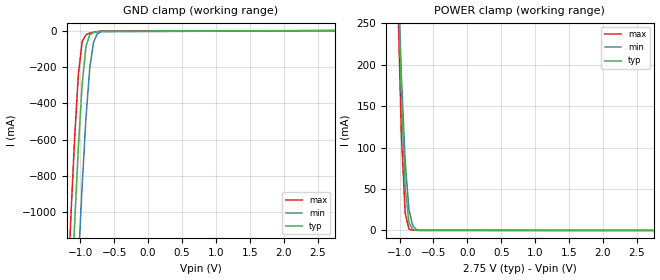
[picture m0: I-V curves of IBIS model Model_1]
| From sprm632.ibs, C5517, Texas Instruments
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| Model based on original model for IC33THYPD
|   Sub model IC33THY_PD_ON_IND_2P75
[model]   Model_1
|[Description]  [2.75V-INPUT-PD-X, IND]
|   PD,IND,
|[Input Load]   PD
|[Output Drive]
|Voltage   2.75V
|Mode   INPUT
Model_type   Input
Polarity   Non-Inverting
Vinl =  0.7
Vinh =  1.7
C_comp   0.88152539p  0.83844711p  0.88864286p
[Model Spec]
Vinl   0.7   0.7   0.7
Vinh   1.7   1.7   1.7
[Temperature Range]   25   105   -40
[Voltage Range]   2.75   2.475   3.025
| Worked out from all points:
|   GND clamp passes 1 mA (typ) near -0.59 V on its own axis
|   POWER clamp passes 1 mA (typ) near -0.79 V on its own axis
[POWER_clamp]
-2.75V    7.27A      6.262A     8.251A
-1.028V   318.4mA    321mA      289.5mA
-972.2mV  160.5mA    185.6mA    114.9mA
-916.7mV  52.38mA    82.72mA    20.8mA
-861.1mV  9.552mA    25.5mA     1.814mA
-805.6mV  1.329mA    5.828mA    224.5uA
-750mV    215.5uA    1.175mA    112.3uA
-694.4mV  80.76uA    256.9uA    104.8uA
2.75V     -84.09pA   -14.35uA   24.32uA
[GND_clamp]
-2.75V    -17A       -17.63A    -16.56A
-1.194V   -2A        -2.688A    -1.495A
-1.139V   -1.516A    -2.198A    -1.02A
-1.083V   -1.056A    -1.723A    -584.9mA
-1.028V   -635.2mA   -1.268A    -236.1mA
-972.2mV  -291mA     -845.8mA   -59.93mA
-916.7mV  -86.57mA   -479.1mA   -22.05mA
-861.1mV  -22.91mA   -206.5mA   -14.2mA
-805.6mV  -10.26mA   -63.94mA   -9.582mA
-750mV    -6.123mA   -17.61mA   -5.862mA
-694.4mV  -3.584mA   -6.2mA     -3.052mA
2.75V     61.47uA    35.47uA    104.1uA
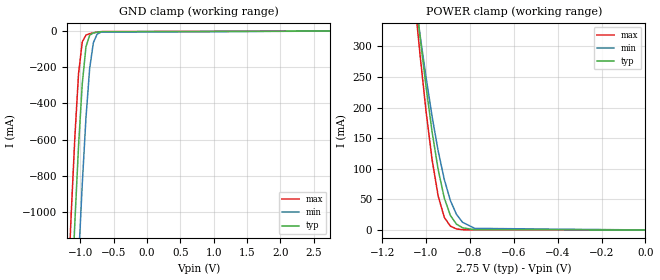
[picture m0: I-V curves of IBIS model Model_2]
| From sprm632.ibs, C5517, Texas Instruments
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| Model based on original model for IC33THYPD
|   Sub model IC33THY_PD_OFF_IND_2P75
[model]   Model_2
|[Description]  [2.75V-INPUT-PD_OFF-X, IND]
|   PD_OFF,IND,
|[Input Load]   PD_OFF
|[Output Drive]
|Voltage   2.75V
|Mode   INPUT
Model_type   Input
Polarity   Non-Inverting
Vinl =  0.7
Vinh =  1.7
C_comp   0.88152539p  0.83844711p  0.88864286p
[Model Spec]
Vinl   0.7   0.7   0.7
Vinh   1.7   1.7   1.7
[Temperature Range]   25   105   -40
[Voltage Range]   2.75   2.475   3.025
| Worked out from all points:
|   GND clamp passes 1 mA (typ) near -0.60 V on its own axis
|   POWER clamp passes 1 mA (typ) near -0.80 V on its own axis
[POWER_clamp]
-2.75V    7.27A      6.262A     8.251A
-1.056V   408.2mA    396.6mA    392.6mA
-1.028V   318.4mA    321mA      289.4mA
-1V       234.9mA    250.1mA    195mA
-972.2mV  160.4mA    185.5mA    114.9mA
-944.4mV  98.35mA    129mA      55.3mA
-916.7mV  52.33mA    82.69mA    20.7mA
-888.9mV  23.73mA    48.12mA    6.231mA
-861.1mV  9.493mA    25.47mA    1.71mA
-833.3mV  3.542mA    12.5mA     458.8uA
-777.8mV  444.2uA    2.594mA    31.13uA
0V        254pA      2.979nA    144.1pA
[GND_clamp]
-2.75V    -17A       -17.63A    -16.56A
-1.194V   -2A        -2.688A    -1.495A
-1.139V   -1.516A    -2.198A    -1.02A
-1.083V   -1.056A    -1.723A    -584.9mA
-1.028V   -635.2mA   -1.268A    -236.1mA
-972.2mV  -291mA     -845.8mA   -59.88mA
-916.7mV  -86.55mA   -479.1mA   -21.97mA
-861.1mV  -22.87mA   -206.5mA   -14.11mA
-805.6mV  -10.22mA   -63.93mA   -9.501mA
-750mV    -6.074mA   -17.59mA   -5.787mA
-694.4mV  -3.536mA   -6.179mA   -2.982mA
2.75V     254pA      4.299nA    119.2pA
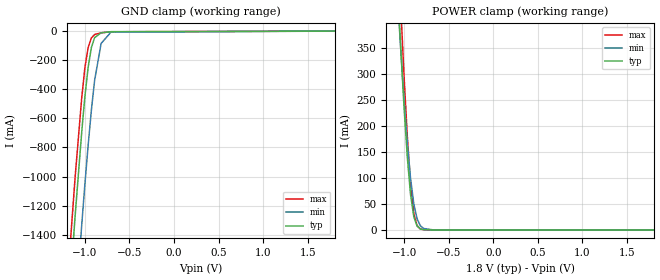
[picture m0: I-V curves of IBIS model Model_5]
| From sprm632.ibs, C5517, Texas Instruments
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| Model based on original model for IC33THYPD
|   Sub model IC33THY_PD_ON_COM_1P8
[model]   Model_5
|[Description]  [1.8V-INPUT-PD-X, COM]
|   PD,COM,
|[Input Load]   PD
|[Output Drive]
|Voltage   1.8V
|Mode   INPUT
Model_type   Input
Polarity   Non-Inverting
Vinl =  0.63
Vinh =  1.17
C_comp   0.92608326p  0.90524032p  0.94286856p
[Model Spec]
Vinl   0.63   0.567   0.693
Vinh   1.17   1.053   1.287
[Temperature Range]   25   105   -10
[Voltage Range]   1.8   1.62   1.98
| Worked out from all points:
|   GND clamp passes 1 mA (typ) near -0.60 V on its own axis
|   POWER clamp passes 1 mA (typ) near -0.79 V on its own axis
[POWER_clamp]
-1.8V     3.329A     2.879A     3.744A
-1.073V   466mA      445.2mA    563mA
-1.036V   345.6mA    343.9mA    424.5mA
-1V       234.9mA    250.1mA    294.9mA
-963.6mV  139.8mA    167.1mA    180mA
-927.3mV  67.8mA     99.04mA    88.62mA
-890.9mV  25.26mA    50.21mA    31.77mA
-854.5mV  7.627mA    21.73mA    8.494mA
-818.2mV  2.034mA    8.241mA    1.915mA
-781.8mV  537.6uA    2.928mA    435.2uA
-672.7mV  28.87uA    127.4uA    35.69uA
1.8V      -54.7pA    -5.012uA   8.703uA
[GND_clamp]
-1.8V     -7.705A    -8.371A    -7.441A
-1.182V   -1.888A    -2.575A    -1.614A
-1.145V   -1.573A    -2.255A    -1.301A
-1.109V   -1.266A    -1.941A    -999.8mA
-1.036V   -696.6mA   -1.336A    -461.3mA
-1V       -449.7mA   -1.052A    -251.6mA
-963.6mV  -248.8mA   -784.8mA   -112.8mA
-927.3mV  -112.6mA   -543.2mA   -46.64mA
-890.9mV  -44.82mA   -337.9mA   -23.68mA
-818.2mV  -11.79mA   -85.27mA   -12mA
-709.1mV  -4.152mA   -7.899mA   -4.826mA
1.8V      20.41uA    11.64uA    31.82uA
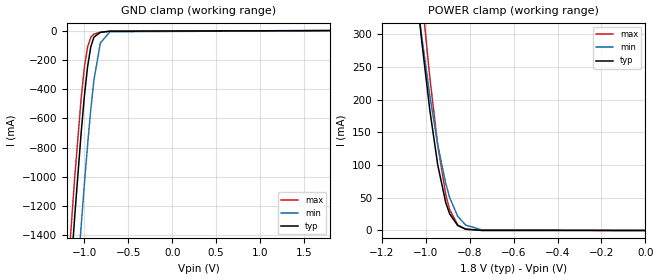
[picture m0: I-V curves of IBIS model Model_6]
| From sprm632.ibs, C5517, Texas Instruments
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| Model based on original model for IC33THYPD
|   Sub model IC33THY_PD_OFF_COM_1P8
[model]   Model_6
|[Description]  [1.8V-INPUT-PD_OFF-X, COM]
|   PD_OFF,COM,
|[Input Load]   PD_OFF
|[Output Drive]
|Voltage   1.8V
|Mode   INPUT
Model_type   Input
Polarity   Non-Inverting
Vinl =  0.63
Vinh =  1.17
C_comp   0.92608326p  0.90524032p  0.94286856p
[Model Spec]
Vinl   0.63   0.567   0.693
Vinh   1.17   1.053   1.287
[Temperature Range]   25   105   -10
[Voltage Range]   1.8   1.62   1.98
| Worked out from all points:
|   GND clamp passes 1 mA (typ) near -0.60 V on its own axis
|   POWER clamp passes 1 mA (typ) near -0.80 V on its own axis
[POWER_clamp]
-1.8V     3.329A     2.879A     3.744A
-1.055V   404.8mA    393.8mA    492.9mA
-1.036V   345.6mA    343.9mA    424.5mA
-1.018V   288.7mA    295.9mA    358.3mA
-981.8mV  184.9mA    207mA      235.1mA
-945.5mV  100.3mA    130.9mA    130.6mA
-909.1mV  42.72mA    71.97mA    55.33mA
-890.9mV  25.25mA    50.2mA     31.74mA
-854.5mV  7.607mA    21.72mA    8.463mA
-818.2mV  2.014mA    8.229mA    1.884mA
-745.5mV  132uA      1.007mA    85.84uA
0V        132pA      1.821nA    116.7pA
[GND_clamp]
-1.8V     -7.705A    -8.371A    -7.441A
-1.182V   -1.888A    -2.575A    -1.614A
-1.145V   -1.573A    -2.255A    -1.301A
-1.109V   -1.266A    -1.941A    -999.8mA
-1.036V   -696.6mA   -1.336A    -461.3mA
-1V       -449.7mA   -1.052A    -251.6mA
-963.6mV  -248.8mA   -784.8mA   -112.8mA
-927.3mV  -112.6mA   -543.2mA   -46.61mA
-890.9mV  -44.81mA   -337.9mA   -23.65mA
-818.2mV  -11.76mA   -85.26mA   -11.96mA
-709.1mV  -4.12mA    -7.886mA   -4.782mA
1.8V      132pA      2.08nA     95.31pA
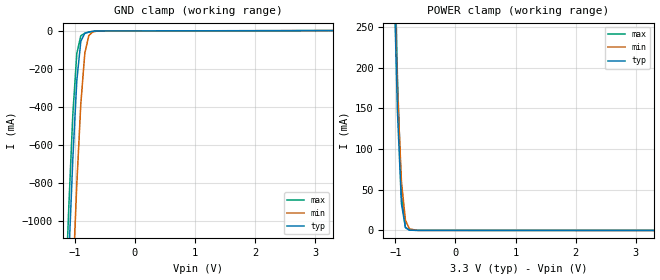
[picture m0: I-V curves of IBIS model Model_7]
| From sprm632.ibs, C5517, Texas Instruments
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| Model based on original model for IC33THYPD
|   Sub model IC33THY_PD_ON_COM_3P3
[model]   Model_7
|[Description]  [3.3V-INPUT-PD-X, COM]
|   PD,COM,
|[Input Load]   PD
|[Output Drive]
|Voltage   3.3V
|Mode   INPUT
Model_type   Input
Polarity   Non-Inverting
Vinl =  0.8
Vinh =  2
C_comp   0.86952386p  0.83844711p  0.87673039p
[Model Spec]
Vinl   0.8   0.8   0.8
Vinh   2   2   2
[Temperature Range]   25   105   -10
[Voltage Range]   3.3   2.97   3.63
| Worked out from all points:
|   GND clamp passes 1 mA (typ) near -0.59 V on its own axis
|   POWER clamp passes 1 mA (typ) near -0.78 V on its own axis
[POWER_clamp]
-3.3V     9.572A     8.242A     10.62A
-1.033V   336mA      335.8mA    413.4mA
-966.7mV  147mA      173.6mA    188.9mA
-900mV    33.1mA     60.41mA    42.36mA
-833.3mV  3.635mA    12.55mA    3.712mA
-766.7mV  387uA      1.932mA    351.1uA
-633.3mV  95.7uA     90.13uA    139.8uA
3.3V      -101.5pA   -26.63uA   30.53uA
[GND_clamp]
-3.3V     -22.43A    -23.04A    -22.19A
-1.167V   -1.756A    -2.441A    -1.482A
-1.1V     -1.191A    -1.863A    -927mA
-1.033V   -674.7mA   -1.312A    -441.8mA
-966.7mV  -263.3mA   -806.2mA   -121.4mA
-900mV    -56.2mA    -384.9mA   -27.18mA
-833.3mV  -14.39mA   -119.2mA   -13.45mA
-766.7mV  -7.115mA   -25.7mA    -8.195mA
-700mV    -3.804mA   -6.765mA   -4.408mA
-633.3mV  -1.704mA   -2.591mA   -1.876mA
3.3V      93.69uA    54.29uA    138.8uA
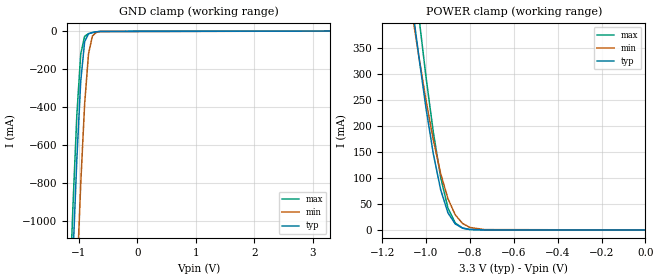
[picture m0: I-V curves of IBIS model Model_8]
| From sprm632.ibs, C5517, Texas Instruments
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| Model based on original model for IC33THYPD
|   Sub model IC33THY_PD_OFF_COM_3P3
[model]   Model_8
|[Description]  [3.3V-INPUT-PD_OFF-X, COM]
|   PD_OFF,COM,
|[Input Load]   PD_OFF
|[Output Drive]
|Voltage   3.3V
|Mode   INPUT
Model_type   Input
Polarity   Non-Inverting
Vinl =  0.8
Vinh =  2
C_comp   0.86952386p  0.83844711p  0.87673039p
[Model Spec]
Vinl   0.8   0.8   0.8
Vinh   2   2   2
[Temperature Range]   25   105   -10
[Voltage Range]   3.3   2.97   3.63
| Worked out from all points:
|   GND clamp passes 1 mA (typ) near -0.59 V on its own axis
|   POWER clamp passes 1 mA (typ) near -0.80 V on its own axis
[POWER_clamp]
-3.3V     9.572A     8.242A     10.62A
-1.067V   445.4mA    427.9mA    539.5mA
-1.033V   335.9mA    335.8mA    413.3mA
-1V       234.9mA    250.1mA    294.9mA
-966.7mV  146.9mA    173.5mA    188.8mA
-933.3mV  77.82mA    109.1mA    101.7mA
-900mV    33.01mA    60.36mA    42.24mA
-866.7mV  11.56mA    29.21mA    13.5mA
-833.3mV  3.542mA    12.5mA     3.575mA
-800mV    1.012mA    4.898mA    862.3uA
-733.3mV  83.43uA    702.6uA    51.03uA
0V        368.6pA    3.926nA    435.5pA
[GND_clamp]
-3.3V     -22.43A    -23.04A    -22.19A
-1.167V   -1.756A    -2.441A    -1.482A
-1.1V     -1.191A    -1.863A    -927mA
-1.033V   -674.7mA   -1.312A    -441.8mA
-966.7mV  -263.3mA   -806.2mA   -121.3mA
-900mV    -56.17mA   -384.9mA   -27.12mA
-833.3mV  -14.34mA   -119.2mA   -13.37mA
-766.7mV  -7.058mA   -25.69mA   -8.118mA
-700mV    -3.749mA   -6.74mA    -4.336mA
-633.3mV  -1.654mA   -2.561mA   -1.811mA
3.3V      368.6pA    8.935nA    310.6pA
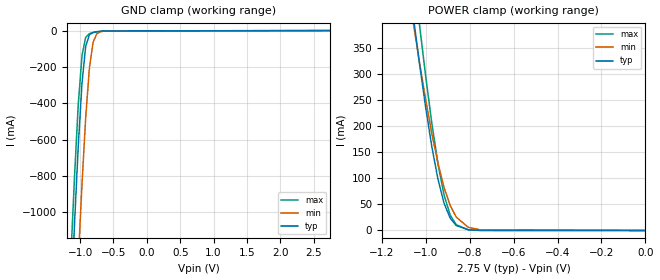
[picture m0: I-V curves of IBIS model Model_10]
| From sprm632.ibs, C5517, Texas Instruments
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| Model based on original model for IC33THYPD
|   Sub model IC33THY_PD_OFF_COM_2P75
[model]   Model_10
|[Description]  [2.75V-INPUT-PD_OFF-X, COM]
|   PD_OFF,COM,
|[Input Load]   PD_OFF
|[Output Drive]
|Voltage   2.75V
|Mode   INPUT
Model_type   Input
Polarity   Non-Inverting
Vinl =  0.7
Vinh =  1.7
C_comp   0.88152539p  0.83844711p  0.88864286p
[Model Spec]
Vinl   0.7   0.7   0.7
Vinh   1.7   1.7   1.7
[Temperature Range]   25   105   -10
[Voltage Range]   2.75   2.475   3.025
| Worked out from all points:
|   GND clamp passes 1 mA (typ) near -0.60 V on its own axis
|   POWER clamp passes 1 mA (typ) near -0.80 V on its own axis
[POWER_clamp]
-2.75V    7.27A      6.262A     8.085A
-1.056V   408.2mA    396.6mA    496.7mA
-1.028V   318.4mA    321mA      393mA
-1V       234.9mA    250.1mA    294.9mA
-972.2mV  160.4mA    185.5mA    205.3mA
-944.4mV  98.35mA    129mA      128.1mA
-916.7mV  52.33mA    82.69mA    68.18mA
-888.9mV  23.73mA    48.12mA    29.7mA
-861.1mV  9.493mA    25.47mA    10.83mA
-805.6mV  1.267mA    5.793mA    1.115mA
-750mV    154uA      1.139mA    102uA
0V        254pA      2.979nA    256.4pA
[GND_clamp]
-2.75V    -17A       -17.63A    -16.75A
-1.139V   -1.516A    -2.198A    -1.246A
-1.083V   -1.056A    -1.723A    -796.9mA
-1.028V   -635.2mA   -1.268A    -406.8mA
-972.2mV  -291mA     -845.8mA   -138.4mA
-916.7mV  -86.55mA   -479.1mA   -37.11mA
-861.1mV  -22.87mA   -206.5mA   -16.79mA
-805.6mV  -10.22mA   -63.93mA   -10.91mA
-750mV    -6.074mA   -17.59mA   -7.059mA
-694.4mV  -3.536mA   -6.179mA   -4.079mA
-638.9mV  -1.787mA   -2.756mA   -1.969mA
2.75V     254pA      4.299nA    195.7pA
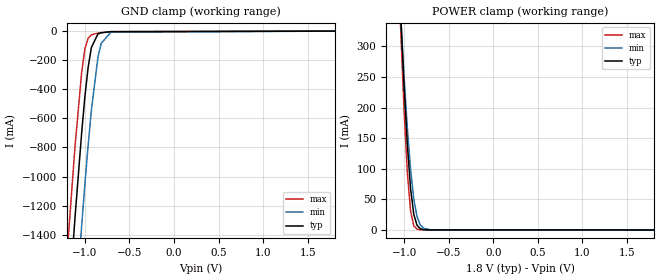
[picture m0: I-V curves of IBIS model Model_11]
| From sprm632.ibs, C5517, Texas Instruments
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| Model based on original model for IC33THYPD
|   Sub model IC33THY_PD_ON_IND_1P8
[model]   Model_11
|[Description]  [1.8V-INPUT-PD-X, IND]
|   PD,IND,
|[Input Load]   PD
|[Output Drive]
|Voltage   1.8V
|Mode   INPUT
Model_type   Input
Polarity   Non-Inverting
Vinl =  0.63
Vinh =  1.17
C_comp   0.92608326p  0.90524032p  0.94286856p
[Model Spec]
Vinl   0.63   0.567   0.693
Vinh   1.17   1.053   1.287
[Temperature Range]   25   105   -40
[Voltage Range]   1.8   1.62   1.98
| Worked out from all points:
|   GND clamp passes 1 mA (typ) near -0.60 V on its own axis
|   POWER clamp passes 1 mA (typ) near -0.79 V on its own axis
[POWER_clamp]
-1.8V     3.329A     2.879A     3.753A
-1.073V   466mA      445.2mA    459.6mA
-1.036V   345.6mA    343.9mA    320.6mA
-1V       234.9mA    250.1mA    195.1mA
-963.6mV  139.8mA    167.1mA    93.99mA
-927.3mV  67.8mA     99.04mA    31mA
-890.9mV  25.26mA    50.21mA    6.862mA
-854.5mV  7.627mA    21.73mA    1.306mA
-818.2mV  2.034mA    8.241mA    253.8uA
-781.8mV  537.6uA    2.928mA    73.12uA
-709.1mV  53.45uA    351.4uA    36.37uA
1.8V      -54.7pA    -5.012uA   9.776uA
[GND_clamp]
-1.8V     -7.705A    -8.371A    -7.226A
-1.182V   -1.888A    -2.575A    -1.385A
-1.145V   -1.573A    -2.255A    -1.075A
-1.109V   -1.266A    -1.941A    -779.8mA
-1.036V   -696.6mA   -1.336A    -281mA
-1V       -449.7mA   -1.052A    -122.4mA
-963.6mV  -248.8mA   -784.8mA   -48.76mA
-927.3mV  -112.6mA   -543.2mA   -24.99mA
-854.5mV  -20.28mA   -183mA     -13.56mA
-818.2mV  -11.79mA   -85.27mA   -10.51mA
-709.1mV  -4.152mA   -7.899mA   -3.673mA
1.8V      20.41uA    11.64uA    35.18uA
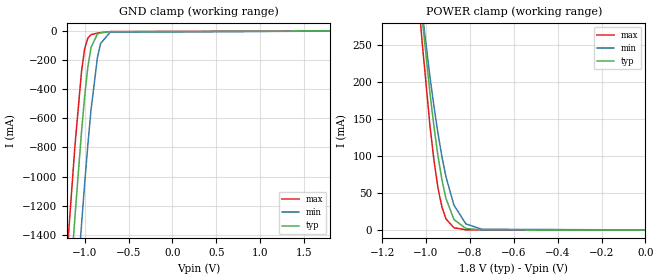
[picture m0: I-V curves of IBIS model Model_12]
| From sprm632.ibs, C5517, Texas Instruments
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| Model based on original model for IC33THYPD
|   Sub model IC33THY_PD_OFF_IND_1P8
[model]   Model_12
|[Description]  [1.8V-INPUT-PD_OFF-X, IND]
|   PD_OFF,IND,
|[Input Load]   PD_OFF
|[Output Drive]
|Voltage   1.8V
|Mode   INPUT
Model_type   Input
Polarity   Non-Inverting
Vinl =  0.63
Vinh =  1.17
C_comp   0.92608326p  0.90524032p  0.94286856p
[Model Spec]
Vinl   0.63   0.567   0.693
Vinh   1.17   1.053   1.287
[Temperature Range]   25   105   -40
[Voltage Range]   1.8   1.62   1.98
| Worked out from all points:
|   GND clamp passes 1 mA (typ) near -0.60 V on its own axis
|   POWER clamp passes 1 mA (typ) near -0.80 V on its own axis
[POWER_clamp]
-1.8V     3.329A     2.879A     3.753A
-1.036V   345.6mA    343.9mA    320.5mA
-1.018V   288.7mA    295.9mA    255.6mA
-981.8mV  184.9mA    207mA      140.6mA
-963.6mV  139.7mA    167.1mA    93.97mA
-945.5mV  100.3mA    130.9mA    57.04mA
-927.3mV  67.78mA    99.03mA    30.97mA
-909.1mV  42.72mA    71.97mA    15.06mA
-872.7mV  14.17mA    33.67mA    2.991mA
-818.2mV  2.014mA    8.229mA    218.6uA
-745.5mV  132uA      1.007mA    6.591uA
0V        132pA      1.821nA    91.6pA
[GND_clamp]
-1.8V     -7.705A    -8.371A    -7.226A
-1.182V   -1.888A    -2.575A    -1.385A
-1.145V   -1.573A    -2.255A    -1.075A
-1.109V   -1.266A    -1.941A    -779.8mA
-1.036V   -696.6mA   -1.336A    -281mA
-1V       -449.7mA   -1.052A    -122.4mA
-963.6mV  -248.8mA   -784.8mA   -48.73mA
-927.3mV  -112.6mA   -543.2mA   -24.95mA
-854.5mV  -20.26mA   -183mA     -13.5mA
-818.2mV  -11.76mA   -85.26mA   -10.46mA
-709.1mV  -4.12mA    -7.886mA   -3.624mA
1.8V      132pA      2.08nA     76.27pA
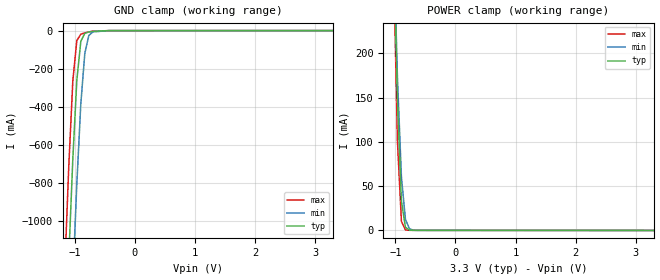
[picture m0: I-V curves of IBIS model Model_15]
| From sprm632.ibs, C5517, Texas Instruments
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| Model based on original model for IC33THYPD
|   Sub model IC33THY_PD_ON_IND_3P3
[model]   Model_15
|[Description]  [3.3V-INPUT-PD-X, IND]
|   PD,IND,
|[Input Load]   PD
|[Output Drive]
|Voltage   3.3V
|Mode   INPUT
Model_type   Input
Polarity   Non-Inverting
Vinl =  0.8
Vinh =  2
C_comp   0.86952386p  0.83844711p  0.87673039p
[Model Spec]
Vinl   0.8   0.8   0.8
Vinh   2   2   2
[Temperature Range]   25   105   -40
[Voltage Range]   3.3   2.97   3.63
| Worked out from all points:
|   GND clamp passes 1 mA (typ) near -0.59 V on its own axis
|   POWER clamp passes 1 mA (typ) near -0.78 V on its own axis
[POWER_clamp]
-3.3V     9.572A     8.242A     10.87A
-1.033V   336mA      335.8mA    309.6mA
-966.7mV  147mA      173.6mA    101.2mA
-900mV    33.1mA     60.41mA    10.29mA
-833.3mV  3.635mA    12.55mA    616.4uA
-766.7mV  387uA      1.932mA    176.2uA
-700mV    117.1uA    312.6uA    158.6uA
-633.3mV  95.7uA     90.13uA    157.9uA
3.3V      -101.5pA   -26.63uA   34.57uA
[GND_clamp]
-3.3V     -22.43A    -23.04A    -22A
-1.167V   -1.756A    -2.441A    -1.254A
-1.1V     -1.191A    -1.863A    -709.3mA
-1.033V   -674.7mA   -1.312A    -264.7mA
-966.7mV  -263.3mA   -806.2mA   -52.38mA
-900mV    -56.2mA    -384.9mA   -18.8mA
-833.3mV  -14.39mA   -119.2mA   -11.76mA
-766.7mV  -7.115mA   -25.7mA    -6.903mA
-700mV    -3.804mA   -6.765mA   -3.294mA
-433.3mV  -62.88uA   -118.9uA   -56.3uA
3.3V      93.69uA    54.29uA    157.6uA
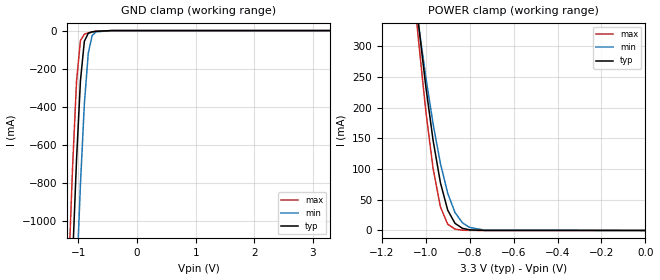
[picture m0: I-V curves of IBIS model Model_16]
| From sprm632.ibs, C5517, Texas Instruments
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| Model based on original model for IC33THYPD
|   Sub model IC33THY_PD_OFF_IND_3P3
[model]   Model_16
|[Description]  [3.3V-INPUT-PD_OFF-X, IND]
|   PD_OFF,IND,
|[Input Load]   PD_OFF
|[Output Drive]
|Voltage   3.3V
|Mode   INPUT
Model_type   Input
Polarity   Non-Inverting
Vinl =  0.8
Vinh =  2
C_comp   0.86952386p  0.83844711p  0.87673039p
[Model Spec]
Vinl   0.8   0.8   0.8
Vinh   2   2   2
[Temperature Range]   25   105   -40
[Voltage Range]   3.3   2.97   3.63
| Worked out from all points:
|   GND clamp passes 1 mA (typ) near -0.59 V on its own axis
|   POWER clamp passes 1 mA (typ) near -0.80 V on its own axis
[POWER_clamp]
-3.3V     9.572A     8.242A     10.87A
-1.067V   445.4mA    427.9mA    435.7mA
-1.033V   335.9mA    335.8mA    309.5mA
-1V       234.9mA    250.1mA    195mA
-966.7mV  146.9mA    173.5mA    101.1mA
-933.3mV  77.82mA    109.1mA    38.46mA
-900mV    33.01mA    60.36mA    10.14mA
-866.7mV  11.56mA    29.21mA    2.249mA
-833.3mV  3.542mA    12.5mA     458.8uA
-800mV    1.012mA    4.898mA    89.45uA
-733.3mV  83.43uA    702.6uA    3.665uA
0V        368.6pA    3.926nA    180.8pA
[GND_clamp]
-3.3V     -22.43A    -23.04A    -22A
-1.167V   -1.756A    -2.441A    -1.254A
-1.1V     -1.191A    -1.863A    -709.3mA
-1.033V   -674.7mA   -1.312A    -264.7mA
-966.7mV  -263.3mA   -806.2mA   -52.32mA
-900mV    -56.17mA   -384.9mA   -18.7mA
-833.3mV  -14.34mA   -119.2mA   -11.67mA
-766.7mV  -7.058mA   -25.69mA   -6.816mA
-700mV    -3.749mA   -6.74mA    -3.214mA
-433.3mV  -28.76uA   -96.03uA   -6.535uA
3.3V      368.6pA    8.935nA    147.2pA
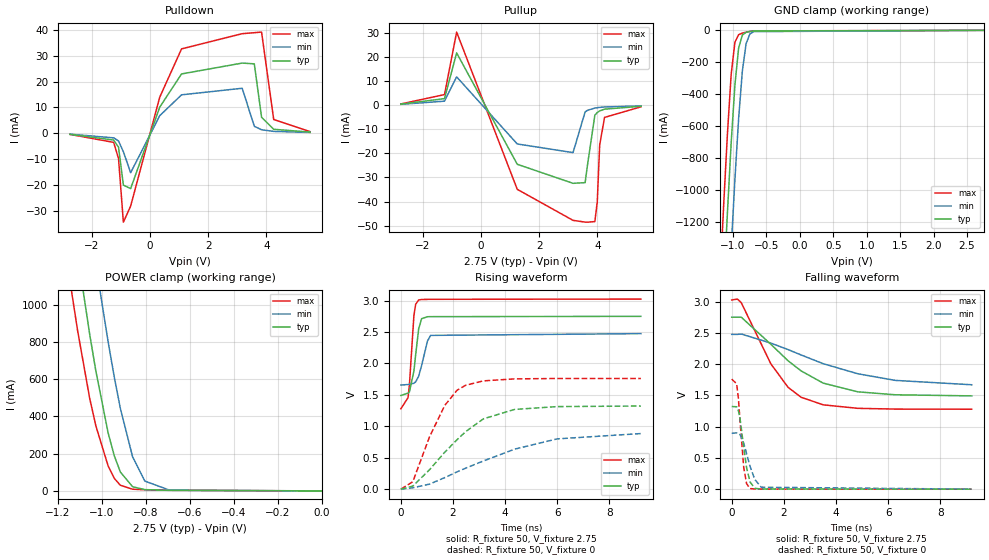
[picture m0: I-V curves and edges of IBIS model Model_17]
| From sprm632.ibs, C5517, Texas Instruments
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| Model based on original model for OC3350CT
|   Sub model OC3350CT_IND_2P75
[model]   Model_17
|[Description]  [2.75V-3-STATE-X-X]
|   , ,
|[Input Load]
|[Output Drive]
|Voltage   2.75V
|Mode   3-STATE
Model_type   3-state
Polarity   Non-Inverting
Enable   Active-Low
Cref =  15.0000pF
Rref =  100.0000M
Vref =  0V
Vmeas =  1.375
C_comp   1.3344371p   1.2993811p   1.3415641p
[Temperature Range]   25   105   -40
[Voltage Range]   2.75   2.475   3.025
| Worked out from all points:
|   slope of the pulldown table from 0 to 0.412 V, typ, clamps not added: 34.2 ohm
|   slope of the pullup table from 0 to 0.412 V, typ, clamps not added: 40.5 ohm
|   GND clamp passes 1 mA (typ) near -0.59 V on its own axis
|   POWER clamp passes 1 mA (typ) near -0.52 V on its own axis
|   rising waveform, R_fixture 50, V_fixture 2.75: 20-80 % time 210ps typ, 288ps min, 162ps max; typ from 1.49 V to 2.75 V
|   rising waveform, R_fixture 50, V_fixture 0: 20-80 % time 1.93ns typ, 3.3ns min, 1.15ns max; typ from 0 V to 1.32 V
|   falling waveform, R_fixture 50, V_fixture 2.75: 20-80 % time 2.23ns typ, 3.33ns min, 1.46ns max; typ from 2.75 V to 1.49 V
|   falling waveform, R_fixture 50, V_fixture 0: 20-80 % time 262ps typ, 387ps min, 195ps max; typ from 1.32 V to 0 V
[POWER_clamp]
-2.75V    16.94A     17.55A     16.52A
-1.167V   1.737A     2.381A     1.292A
-1.111V   1.273A     1.9A       861.3mA
-1.056V   840.8mA    1.438A     496.8mA
-1.028V   643.9mA    1.216A     349.4mA
-972.2mV  311.6mA    800.4mA    133.7mA
-944.4mV  188.9mA    612.4mA    67.69mA
-916.7mV  101.5mA    443mA      30.38mA
-861.1mV  22.6mA     183.2mA    9.262mA
-805.6mV  7.009mA    53.11mA    6.255mA
-694.4mV  3.061mA    4.465mA    3.723mA
0V        269.9pA    3.665nA    128.1pA
[Pulldown]
-2.75V    -442uA     -375.6uA   -474.1uA
-1.25V    -2.654mA   -1.806mA   -3.558mA
-1.083V   -5.416mA   -3.008mA   -9.846mA
-916.7mV  -20.1mA    -7.191mA   -34.47mA
-666.7mV  -21.47mA   -15.31mA   -28.22mA
333.3mV   10.1mA     6.791mA    13.96mA
1.083V    22.95mA    14.86mA    32.66mA
3.167V    27.16mA    17.4mA     38.54mA
3.583V    26.86mA    2.673mA    38.92mA
3.833V    6.162mA    1.323mA    39.16mA
4.25V     1.511mA    698.6uA    5.299mA
5.5V      426.6uA    283.2uA    606.1uA
[Pullup]
-2.75V    418.2uA    329.2uA    487.1uA
-1.25V    2.701mA    1.641mA    4.369mA
-833.3mV  21.65mA    11.72mA    30.28mA
1.25V     -24.52mA   -16.1mA    -34.9mA
3.167V    -32.42mA   -19.68mA   -47.77mA
3.583V    -32.13mA   -2.799mA   -48.5mA
3.667V    -24.56mA   -2.133mA   -48.53mA
3.917V    -4.161mA   -1.221mA   -48.27mA
4V        -3.056mA   -1.065mA   -40.08mA
4.083V    -2.401mA   -943.9uA   -16.54mA
4.25V     -1.668mA   -767.8uA   -5.093mA
5.5V      -494.4uA   -316.6uA   -710uA
[GND_clamp]
-2.75V    -17.09A    -17.75A    -16.63A
-1.194V   -2.084A    -2.795A    -1.56A
-1.139V   -1.598A    -2.303A    -1.082A
-1.083V   -1.133A    -1.824A    -639.4mA
-1.028V   -703.4mA   -1.364A    -275mA
-972.2mV  -342.5mA   -933.9mA   -74.49mA
-916.7mV  -111mA     -552.6mA   -27.1mA
-861.1mV  -29.66mA   -255.8mA   -17.34mA
-805.6mV  -12.76mA   -85.11mA   -11.68mA
-750mV    -7.49mA    -23.64mA   -7.122mA
-694.4mV  -4.355mA   -7.989mA   -3.677mA
2.75V     269.9pA    28.51uA    71.29pA
[Ramp]
dV/dt_f 0.76430358/2.2499866n 0.49810524/3.4588381n  1.0576467/1.4687417n
dV/dt_r 0.79434594/1.9333317n 0.53652254/3.3498741n   1.057181/1.1493145n
R_load = 50
[Rising Waveform]
R_fixture = 50
V_fixture = 2.75
V_fixture_min = 2.475
V_fixture_max = 3.025
0s        1.491V     1.657V     1.28V
274.5ps   1.528V     1.665V     1.455V
329.2ps   1.549V     1.669V     1.666V
500.5ps   1.879V     1.685V     2.763V
568.1ps   2.138V     1.708V     2.943V
683.4ps   2.552V     1.799V     3.011V
796.9ps   2.713V     1.969V     3.018V
1.02ns    2.744V     2.355V     3.02V
1.139ns   2.745V     2.447V     3.021V
9.211ns   2.75V      2.475V     3.025V
[Rising Waveform]
R_fixture = 50
V_fixture = 0
V_fixture_min = 0
V_fixture_max = 0
0s        0V         288.8uV    815.2uV
458.3ps   48.39mV    21.83mV    118mV
1.097ns   308.1mV    80.03mV    830.2mV
1.683ns   586.9mV    183.6mV    1.332V
2.157ns   787.4mV    275.8mV    1.574V
2.488ns   916.1mV    334.5mV    1.654V
3.166ns   1.119V     448.7mV    1.723V
4.366ns   1.269V     637.1mV    1.755V
6.001ns   1.314V     800.5mV    1.761V
9.211ns   1.323V     884.8mV    1.761V
[Falling Waveform]
R_fixture = 50
V_fixture = 2.75
V_fixture_min = 2.475
V_fixture_max = 3.025
0s        2.751V     2.476V     3.026V
221ps     2.751V     2.476V     3.041V
366.4ps   2.751V     2.482V     2.984V
1.499ns   2.319V     2.337V     2.007V
2.162ns   2.054V     2.233V     1.63V
2.663ns   1.892V     2.147V     1.47V
3.513ns   1.696V     2.007V     1.349V
4.84ns    1.557V     1.846V     1.293V
6.276ns   1.51V      1.74V      1.281V
9.211ns   1.492V     1.67V      1.279V
[Falling Waveform]
R_fixture = 50
V_fixture = 0
V_fixture_min = 0
V_fixture_max = 0
0s        1.322V     893.9mV    1.761V
190.6ps   1.318V     900.1mV    1.685V
256.3ps   1.258V     895.8mV    1.457V
319ps     1.134V     873.6mV    1.095V
461.3ps   666.8mV    734.7mV    347.4mV
571.7ps   344.6mV    568.6mV    87.88mV
703.1ps   115.4mV    365.3mV    9.997mV
887.1ps   13.83mV    155.7mV    2.053mV
1.133ns   2.135mV    30.91mV    1.739mV
9.211ns   771.6nV    35.61uV    0V
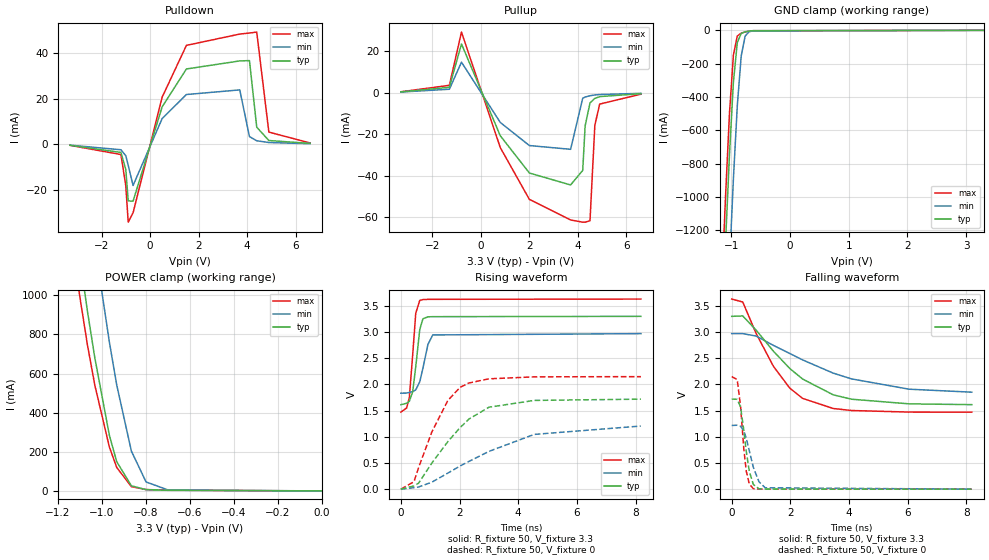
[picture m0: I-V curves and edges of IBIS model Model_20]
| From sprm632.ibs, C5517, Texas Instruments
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| Model based on original model for OC3350CT
|   Sub model OC3350CT_COM_3P3
[model]   Model_20
|[Description]  [3.3V-3-STATE-X-X]
|   , ,
|[Input Load]
|[Output Drive]
|Voltage   3.3V
|Mode   3-STATE
Model_type   3-state
Polarity   Non-Inverting
Enable   Active-Low
Cref =  15.0000pF
Rref =  100.0000M
Vref =  0V
Vmeas =  1.65
C_comp   1.313883p   1.2993811p   1.3212381p
[Temperature Range]   25   105   -10
[Voltage Range]   3.3   2.97   3.63
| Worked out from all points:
|   slope of the pulldown table from 0 to 0.495 V, typ, clamps not added: 30.2 ohm
|   slope of the pullup table from 0 to 0.495 V, typ, clamps not added: 36.2 ohm
|   GND clamp passes 1 mA (typ) near -0.58 V on its own axis
|   POWER clamp passes 1 mA (typ) near -0.52 V on its own axis
|   rising waveform, R_fixture 50, V_fixture 3.3: 20-80 % time 196ps typ, 265ps min, 161ps max; typ from 1.61 V to 3.3 V
|   rising waveform, R_fixture 50, V_fixture 0: 20-80 % time 1.54ns typ, 2.65ns min, 1.02ns max; typ from 0.001 V to 1.72 V
|   falling waveform, R_fixture 50, V_fixture 3.3: 20-80 % time 1.91ns typ, 2.85ns min, 1.38ns max; typ from 3.3 V to 1.61 V
|   falling waveform, R_fixture 50, V_fixture 0: 20-80 % time 240ps typ, 347ps min, 195ps max; typ from 1.72 V to 0 V
[POWER_clamp]
-3.3V     22.37A     22.96A     22.14A
-1.167V   1.737A     2.381A     1.512A
-1.133V   1.455A     2.091A     1.242A
-1.1V     1.183A     1.806A     986.5mA
-1.067V   923.7mA    1.529A     751.1mA
-1.033V   682mA      1.26A      542mA
-966.7mV  284.5mA    761.6mA    224.7mA
-933.3mV  149.5mA    542mA      120.3mA
-866.7mV  26.4mA     203.8mA    21.79mA
-800mV    6.466mA    45.92mA    6.888mA
-700mV    3.149mA    4.854mA    3.951mA
0V        403.5pA    4.834nA    481.9pA
[Pulldown]
-3.3V     -379.4uA   -332.5uA   -410.9uA
-1.2V     -3.536mA   -2.351mA   -4.449mA
-1V       -10.99mA   -4.978mA   -18.18mA
-900mV    -24.8mA    -9.221mA   -34.15mA
-700mV    -24.92mA   -18.03mA   -29.99mA
500mV     16.51mA    11.37mA    20.75mA
1.5V      33.12mA    21.9mA     43.48mA
3.7V      36.65mA    23.93mA    48.44mA
4.1V      36.79mA    3.426mA    48.89mA
4.4V      7.557mA    1.597mA    49.31mA
4.9V      1.707mA    822.5uA    5.402mA
6.6V      436uA      304.4uA    625.7uA
[Pullup]
-3.3V     352.6uA    285.2uA    404.5uA
-1.3V     2.559mA    1.632mA    3.524mA
-800mV    23.47mA    14.67mA    29.18mA
800mV     -20.79mA   -14.38mA   -26.49mA
2V        -38.75mA   -25.51mA   -51.47mA
3.7V      -44.51mA   -27.33mA   -61.38mA
4.2V      -37.5mA    -2.71mA    -62.46mA
4.3V      -15.98mA   -2.138mA   -62.46mA
4.5V      -4.996mA   -1.492mA   -61.74mA
4.7V      -2.802mA   -1.142mA   -15.74mA
4.9V      -1.927mA   -922.6uA   -5.513mA
6.6V      -515.3uA   -347uA     -755.5uA
[GND_clamp]
-3.3V     -22.52A    -23.16A    -22.27A
-1.167V   -1.839A    -2.548A    -1.554A
-1.1V     -1.269A    -1.966A    -993.6mA
-1.033V   -744mA     -1.409A    -496.3mA
-966.7mV  -312.4mA   -893.1mA   -148.8mA
-900mV    -73.25mA   -452.3mA   -33.84mA
-833.3mV  -18.21mA   -153.7mA   -16.45mA
-766.7mV  -8.719mA   -34.69mA   -9.979mA
-700mV    -4.617mA   -8.747mA   -5.338mA
-633.3mV  -2.04mA    -3.207mA   -2.234mA
3.3V      403.5pA    85.4uA     -99.59pA
[Ramp]
dV/dt_f  1.0230885/1.9215656n 0.69092053/2.9599406n  1.3078875/1.380556n
dV/dt_r  1.0321169/1.5386113n 0.72980603/2.6929629n  1.2899667/1.0217464n
R_load = 50
[Rising Waveform]
R_fixture = 50
V_fixture = 3.3
V_fixture_min = 2.97
V_fixture_max = 3.63
0s        1.613V     1.833V     1.471V
195.9ps   1.64V      1.836V     1.55V
287.2ps   1.677V     1.847V     1.741V
403.4ps   1.86V      1.863V     2.566V
507.8ps   2.339V     1.897V     3.358V
644.1ps   3.047V     2.051V     3.605V
752.2ps   3.254V     2.31V      3.62V
922.9ps   3.291V     2.764V     3.624V
1.087ns   3.294V     2.945V     3.625V
8.184ns   3.3V       2.97V      3.63V
[Rising Waveform]
R_fixture = 50
V_fixture = 0
V_fixture_min = 0
V_fixture_max = 0
0s        613.9uV    904.6uV    699.7uV
447.5ps   63.48mV    29.27mV    143.6mV
604.5ps   114.9mV    41.9mV     412.6mV
1.057ns   500.4mV    134.1mV    1.094V
1.601ns   908mV      307.7mV    1.693V
2.019ns   1.176V     442.3mV    1.945V
2.319ns   1.338V     530.3mV    2.028V
3.002ns   1.565V     721.8mV    2.107V
4.545ns   1.695V     1.046V     2.145V
8.184ns   1.719V     1.206V     2.149V
[Falling Waveform]
R_fixture = 50
V_fixture = 3.3
V_fixture_min = 2.97
V_fixture_max = 3.63
0s        3.3V       2.97V      3.63V
376.9ps   3.308V     2.97V      3.574V
832ps     3.037V     2.924V     2.974V
1.423ns   2.634V     2.745V     2.346V
1.983ns   2.303V     2.59V      1.928V
2.415ns   2.104V     2.469V     1.734V
3.459ns   1.802V     2.216V     1.541V
4.082ns   1.718V     2.106V     1.502V
6.049ns   1.629V     1.909V     1.472V
8.184ns   1.614V     1.852V     1.47V
[Falling Waveform]
R_fixture = 50
V_fixture = 0
V_fixture_min = 0
V_fixture_max = 0
0s        1.72V      1.216V     2.15V
188.3ps   1.716V     1.221V     2.093V
301.5ps   1.572V     1.203V     1.586V
413.7ps   1.123V     1.113V     765.5mV
496.1ps   724.8mV    973.5mV    347.1mV
600.1ps   340.6mV    732.8mV    97.64mV
736.9ps   91.01mV    418.6mV    9.912mV
931.6ps   6.381mV    140.3mV    2.489mV
1.142ns   2.381mV    26.7mV     1.98mV
8.184ns   1.963uV    45.61uV    0V
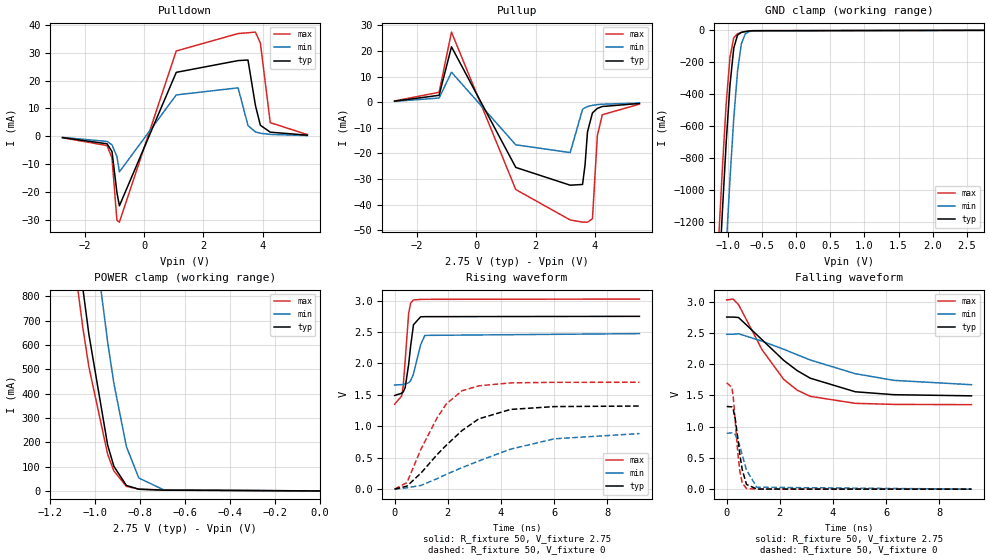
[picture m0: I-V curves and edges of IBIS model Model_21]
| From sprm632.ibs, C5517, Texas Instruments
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| Model based on original model for OC3350CT
|   Sub model OC3350CT_COM_2P75
[model]   Model_21
|[Description]  [2.75V-3-STATE-X-X]
|   , ,
|[Input Load]
|[Output Drive]
|Voltage   2.75V
|Mode   3-STATE
Model_type   3-state
Polarity   Non-Inverting
Enable   Active-Low
Cref =  15.0000pF
Rref =  100.0000M
Vref =  0V
Vmeas =  1.375
C_comp   1.3344371p   1.2993811p   1.3415641p
[Temperature Range]   25   105   -10
[Voltage Range]   2.75   2.475   3.025
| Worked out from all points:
|   slope of the pulldown table from 0 to 0.412 V, typ, clamps not added: 34.2 ohm
|   slope of the pullup table from 0 to 0.412 V, typ, clamps not added: 40.5 ohm
|   GND clamp passes 1 mA (typ) near -0.59 V on its own axis
|   POWER clamp passes 1 mA (typ) near -0.52 V on its own axis
|   rising waveform, R_fixture 50, V_fixture 2.75: 20-80 % time 210ps typ, 288ps min, 172ps max; typ from 1.49 V to 2.75 V
|   rising waveform, R_fixture 50, V_fixture 0: 20-80 % time 1.93ns typ, 3.3ns min, 1.26ns max; typ from 0 V to 1.32 V
|   falling waveform, R_fixture 50, V_fixture 2.75: 20-80 % time 2.23ns typ, 3.34ns min, 1.61ns max; typ from 2.75 V to 1.49 V
|   falling waveform, R_fixture 50, V_fixture 0: 20-80 % time 262ps typ, 387ps min, 207ps max; typ from 1.32 V to 0 V
[POWER_clamp]
-2.75V    16.94A     17.55A     16.71A
-1.167V   1.737A     2.381A     1.512A
-1.139V   1.502A     2.139A     1.286A
-1.111V   1.273A     1.9A       1.07A
-1.056V   840.8mA    1.438A     678.2mA
-1.028V   643.9mA    1.216A     510.1mA
-944.4mV  188.9mA    612.4mA    151mA
-916.7mV  101.5mA    443mA      82.28mA
-861.1mV  22.6mA     183.2mA    18.82mA
-805.6mV  7.009mA    53.11mA    7.278mA
-694.4mV  3.061mA    4.465mA    3.846mA
0V        269.9pA    3.665nA    268.5pA
[Pulldown]
-2.75V    -442uA     -375.6uA   -488.5uA
-1.25V    -2.654mA   -1.806mA   -3.299mA
-1.083V   -5.416mA   -3.008mA   -7.76mA
-916.7mV  -20.1mA    -7.191mA   -30.06mA
-833.3mV  -24.89mA   -12.72mA   -30.76mA
1.083V    22.95mA    14.86mA    30.61mA
3.167V    27.16mA    17.4mA     36.85mA
3.5V      27.37mA    3.87mA     37.14mA
3.75V     11.11mA    1.6mA      37.38mA
3.917V    3.983mA    1.126mA    33.46mA
4.25V     1.511mA    698.6uA    4.923mA
5.5V      426.6uA    283.2uA    642.7uA
[Pullup]
-2.75V    418.2uA    329.2uA    490uA
-1.25V    2.701mA    1.641mA    3.883mA
-833.3mV  21.65mA    11.72mA    27.4mA
1.333V    -25.47mA   -16.64mA   -34.11mA
3.167V    -32.42mA   -19.68mA   -46mA
3.583V    -32.13mA   -2.799mA   -46.82mA
3.667V    -24.56mA   -2.133mA   -46.85mA
3.75V     -11.6mA    -1.713mA   -46.87mA
3.917V    -4.161mA   -1.221mA   -45.51mA
4.083V    -2.401mA   -943.9uA   -12.97mA
4.25V     -1.668mA   -767.8uA   -4.888mA
5.5V      -494.4uA   -316.6uA   -762.1uA
[GND_clamp]
-2.75V    -17.09A    -17.75A    -16.84A
-1.139V   -1.598A    -2.303A    -1.316A
-1.083V   -1.133A    -1.824A    -861.4mA
-1.028V   -703.4mA   -1.364A    -459.8mA
-972.2mV  -342.5mA   -933.9mA   -168.6mA
-916.7mV  -111mA     -552.6mA   -46.56mA
-861.1mV  -29.66mA   -255.8mA   -20.72mA
-805.6mV  -12.76mA   -85.11mA   -13.41mA
-750mV    -7.49mA    -23.64mA   -8.68mA
-694.4mV  -4.355mA   -7.989mA   -5.022mA
-638.9mV  -2.204mA   -3.457mA   -2.429mA
2.75V     269.9pA    28.51uA    -215.6pA
[Ramp]
dV/dt_f 0.76430409/2.2498549n 0.49810139/3.4623434n  1.0144178/1.6146752n
dV/dt_r 0.79434595/1.9333298n 0.53652279/3.3501589n  1.0211187/1.2625832n
R_load = 50
[Rising Waveform]
R_fixture = 50
V_fixture = 2.75
V_fixture_min = 2.475
V_fixture_max = 3.025
0s        1.491V     1.657V     1.352V
265.3ps   1.526V     1.664V     1.482V
323.8ps   1.546V     1.668V     1.646V
395.9ps   1.615V     1.673V     2.032V
528.9ps   1.986V     1.693V     2.799V
603.9ps   2.28V      1.726V     2.961V
710.3ps   2.616V     1.832V     3.011V
979.8ps   2.743V     2.299V     3.02V
1.138ns   2.745V     2.447V     3.021V
9.211ns   2.75V      2.475V     3.025V
[Rising Waveform]
R_fixture = 50
V_fixture = 0
V_fixture_min = 0
V_fixture_max = 0
0s        0V         288.4uV    772.8uV
464.7ps   49.07mV    22.29mV    105.3mV
993.6ps   256.7mV    60.12mV    638.1mV
1.595ns   548.4mV    166.7mV    1.132V
1.941ns   697.8mV    234.9mV    1.354V
2.535ns   932.3mV    342.5mV    1.566V
3.166ns   1.119V     448.6mV    1.644V
4.365ns   1.269V     637mV      1.691V
6.004ns   1.314V     800.8mV    1.7V
9.211ns   1.323V     884.8mV    1.701V
[Falling Waveform]
R_fixture = 50
V_fixture = 2.75
V_fixture_min = 2.475
V_fixture_max = 3.025
0s        2.751V     2.476V     3.025V
244.6ps   2.751V     2.477V     3.039V
447.3ps   2.744V     2.485V     2.949V
1.335ns   2.387V     2.365V     2.226V
2.149ns   2.058V     2.236V     1.753V
2.646ns   1.897V     2.15V      1.584V
3.143ns   1.774V     2.065V     1.484V
4.837ns   1.557V     1.846V     1.372V
6.301ns   1.51V      1.739V     1.355V
9.211ns   1.492V     1.67V      1.351V
[Falling Waveform]
R_fixture = 50
V_fixture = 0
V_fixture_min = 0
V_fixture_max = 0
0s        1.322V     893.9mV    1.701V
193.9ps   1.316V     900.2mV    1.627V
250.9ps   1.266V     896.5mV    1.456V
318.5ps   1.134V     873.6mV    1.11V
414ps     829.8mV    792.4mV    593.6mV
499.4ps   540.4mV    681.2mV    273.4mV
585.6ps   311mV      545.7mV    100mV
745.3ps   76.46mV    305.7mV    8.422mV
1.133ns   2.134mV    30.81mV    1.825mV
9.211ns   770.1nV    35.61uV    0V
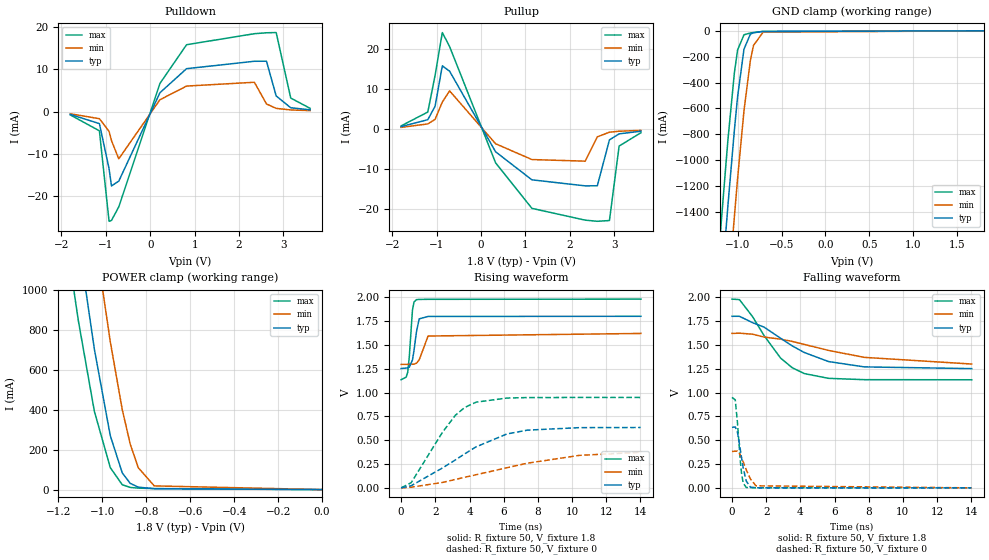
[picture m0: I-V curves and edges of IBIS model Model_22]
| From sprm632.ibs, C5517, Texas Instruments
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| Model based on original model for OC3350CT
|   Sub model OC3350CT_IND_1P8
[model]   Model_22
|[Description]  [1.8V-3-STATE-X-X]
|   , ,
|[Input Load]
|[Output Drive]
|Voltage   1.8V
|Mode   3-STATE
Model_type   3-state
Polarity   Non-Inverting
Enable   Active-Low
Cref =  15.0000pF
Rref =  100.0000M
Vref =  0V
Vmeas =  0.9
C_comp   1.382326p   1.3625191p   1.400048p
[Temperature Range]   25   105   -40
[Voltage Range]   1.8   1.62   1.98
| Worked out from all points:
|   slope of the pulldown table from 0 to 0.27 V, typ, clamps not added: 51 ohm
|   slope of the pullup table from 0 to 0.27 V, typ, clamps not added: 57.1 ohm
|   GND clamp passes 1 mA (typ) near -0.59 V on its own axis
|   POWER clamp passes 1 mA (typ) near -0.52 V on its own axis
|   rising waveform, R_fixture 50, V_fixture 1.8: 20-80 % time 259ps typ, 376ps min, 192ps max; typ from 1.25 V to 1.8 V
|   rising waveform, R_fixture 50, V_fixture 0: 20-80 % time 3.49ns typ, 5.74ns min, 2.09ns max; typ from 0.001 V to 0.634 V
|   falling waveform, R_fixture 50, V_fixture 1.8: 20-80 % time 3.24ns typ, 5.05ns min, 2.09ns max; typ from 1.8 V to 1.25 V
|   falling waveform, R_fixture 50, V_fixture 0: 20-80 % time 354ps typ, 550ps min, 246ps max; typ from 0.634 V to 0 V
[POWER_clamp]
-1.8V     7.656A     8.299A     7.195A
-1.182V   1.868A     2.514A     1.416A
-1.164V   1.711A     2.354A     1.267A
-1.127V   1.405A     2.039A     981.3mA
-1.109V   1.256A     1.883A     846.6mA
-1.036V   703.1mA    1.284A     392.2mA
-963.6mV  270.2mA    740.6mA    110.2mA
-909.1mV  83.65mA    400.5mA    24.3mA
-872.7mV  31.2mA     227.3mA    10.88mA
-836.4mV  12.3mA     109.9mA    7.425mA
-763.6mV  4.548mA    18.58mA    5.183mA
0V        133.9pA    2.238nA    80.44pA
[Pulldown]
-1.8V     -681.8uA   -528.3uA   -794.6uA
-1.145V   -2.847mA   -1.688mA   -4.551mA
-927.3mV  -13.48mA   -4.671mA   -25.92mA
-872.7mV  -17.57mA   -6.854mA   -25.72mA
-709.1mV  -16.44mA   -11.17mA   -22.52mA
218.2mV   4.45mA     2.794mA    6.638mA
818.2mV   10.13mA    6.022mA    15.79mA
2.345V    11.88mA    6.92mA     18.39mA
2.618V    11.89mA    1.797mA    18.61mA
2.836V    3.687mA    752.6uA    18.66mA
3.164V    900.6uA    382.8uA    3.183mA
3.6V      416.6uA    227.7uA    766.1uA
[Pullup]
-1.8V     683.6uA    489.2uA    876.7uA
-1.2V     2.423mA    1.368mA    4.325mA
-1.036V   5.753mA    2.495mA    13.46mA
-872.7mV  15.87mA    6.82mA     24.17mA
-709.1mV  14.53mA    9.611mA    20.69mA
327.3mV   -5.597mA   -3.586mA   -8.356mA
1.145V    -12.6mA    -7.535mA   -19.72mA
2.345V    -14.1mA    -7.935mA   -22.66mA
2.618V    -14.08mA   -1.863mA   -22.95mA
2.891V    -2.622mA   -708.2uA   -22.76mA
3.109V    -1.114mA   -461.6uA   -4.158mA
3.6V      -465.3uA   -255.6uA   -836.1uA
[GND_clamp]
-1.8V     -7.797A    -8.487A    -7.298A
-1.218V   -2.296A    -3.009A    -1.771A
-1.182V   -1.972A    -2.683A    -1.449A
-1.145V   -1.654A    -2.361A    -1.137A
-1.109V   -1.345A    -2.044A    -838.1mA
-1.036V   -766.4mA   -1.434A    -323.2mA
-1V       -510.9mA   -1.144A    -148.7mA
-927.3mV  -142.3mA   -620.2mA   -30.84mA
-854.5mV  -26.15mA   -228.8mA   -16.59mA
-818.2mV  -14.78mA   -112.1mA   -12.85mA
-709.1mV  -5.074mA   -10.31mA   -4.466mA
1.8V      133.9pA    3.271uA    36.4pA
[Ramp]
dV/dt_f 0.33498686/3.2897393n 0.19919624/5.2987374n 0.51434147/2.1166216n
dV/dt_r 0.38059441/3.5004528n 0.22884564/5.899184n  0.56967297/2.0974967n
R_load = 50
[Rising Waveform]
R_fixture = 50
V_fixture = 1.8
V_fixture_min = 1.62
V_fixture_max = 1.98
0s        1.252V     1.295V     1.135V
297.7ps   1.257V     1.296V     1.163V
387.1ps   1.26V      1.296V     1.215V
476.6ps   1.266V     1.297V     1.375V
661ps     1.341V     1.297V     1.863V
751.1ps   1.44V      1.298V     1.949V
895.1ps   1.636V     1.308V     1.975V
1.055ns   1.773V     1.342V     1.977V
1.575ns   1.798V     1.593V     1.978V
14.03ns   1.8V       1.62V      1.98V
[Rising Waveform]
R_fixture = 50
V_fixture = 0
V_fixture_min = 0
V_fixture_max = 0
0s        700.5uV    378uV      998.3uV
588.6ps   23.11mV    7.304mV    54.3mV
2.413ns   208.7mV    57.07mV    582.2mV
3.174ns   293.6mV    88.63mV    762.2mV
3.717ns   356.8mV    111.5mV    843.6mV
4.386ns   430.7mV    137.9mV    899.2mV
6.181ns   565.3mV    211mV      942.4mV
7.383ns   605.6mV    259mV      947.4mV
10.44ns   632.1mV    341.4mV    948.6mV
14.01ns   633.6mV    373.5mV    948.3mV
[Falling Waveform]
R_fixture = 50
V_fixture = 1.8
V_fixture_min = 1.62
V_fixture_max = 1.98
0s        1.8V       1.62V      1.98V
435.4ps   1.8V       1.623V     1.975V
1.206ns   1.733V     1.612V     1.796V
1.879ns   1.686V     1.582V     1.597V
2.843ns   1.57V      1.56V      1.362V
3.537ns   1.488V     1.536V     1.259V
4.232ns   1.42V      1.505V     1.199V
5.65ns    1.325V     1.442V     1.149V
7.742ns   1.269V     1.369V     1.135V
14.03ns   1.251V     1.299V     1.134V
[Falling Waveform]
R_fixture = 50
V_fixture = 0
V_fixture_min = 0
V_fixture_max = 0
0s        634mV      381.4mV    949mV
191.8ps   639.9mV    385.3mV    923.3mV
325ps     579mV      384.8mV    677.2mV
477.9ps   413.1mV    348.1mV    300mV
564.2ps   310.4mV    315mV      144.9mV
661.3ps   205.7mV    271.1mV    47.73mV
835.9ps   71.3mV     188.5mV    4.386mV
1.071ns   8.066mV    95.58mV    1.417mV
1.4ns     913.3uV    21.41mV    1.197mV
14.01ns   210.1nV    14.66uV    0V
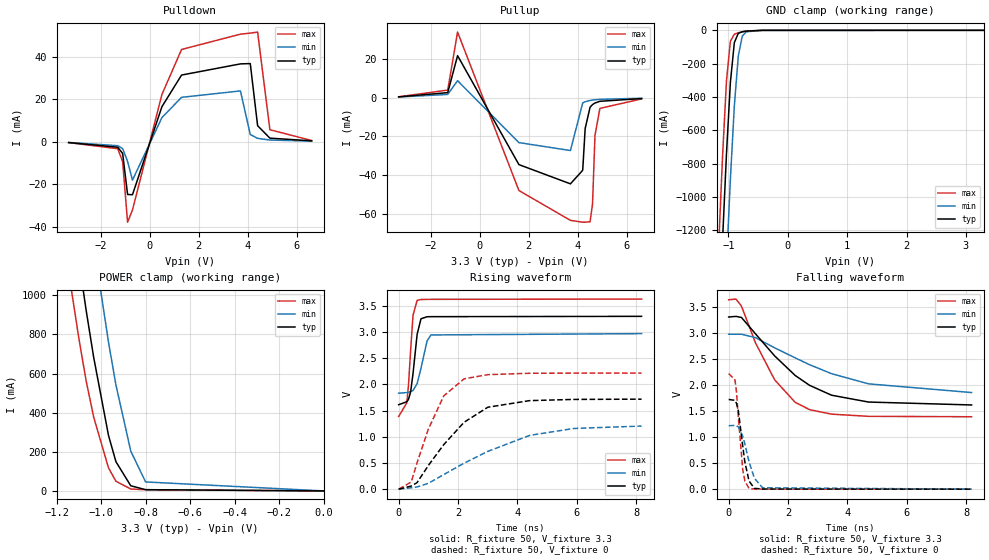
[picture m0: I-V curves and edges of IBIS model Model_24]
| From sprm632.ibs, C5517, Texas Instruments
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| Model based on original model for OC3350CT
|   Sub model OC3350CT_IND_3P3
[model]   Model_24
|[Description]  [3.3V-3-STATE-X-X]
|   , ,
|[Input Load]
|[Output Drive]
|Voltage   3.3V
|Mode   3-STATE
Model_type   3-state
Polarity   Non-Inverting
Enable   Active-Low
Cref =  15.0000pF
Rref =  100.0000M
Vref =  0V
Vmeas =  1.65
C_comp   1.313883p   1.2993811p   1.3212381p
[Temperature Range]   25   105   -40
[Voltage Range]   3.3   2.97   3.63
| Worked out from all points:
|   slope of the pulldown table from 0 to 0.495 V, typ, clamps not added: 30.2 ohm
|   slope of the pullup table from 0 to 0.495 V, typ, clamps not added: 36.2 ohm
|   GND clamp passes 1 mA (typ) near -0.58 V on its own axis
|   POWER clamp passes 1 mA (typ) near -0.52 V on its own axis
|   rising waveform, R_fixture 50, V_fixture 3.3: 20-80 % time 196ps typ, 265ps min, 153ps max; typ from 1.61 V to 3.3 V
|   rising waveform, R_fixture 50, V_fixture 0: 20-80 % time 1.54ns typ, 2.66ns min, 923ps max; typ from 0.001 V to 1.72 V
|   falling waveform, R_fixture 50, V_fixture 3.3: 20-80 % time 1.91ns typ, 2.85ns min, 1.27ns max; typ from 3.3 V to 1.61 V
|   falling waveform, R_fixture 50, V_fixture 0: 20-80 % time 240ps typ, 347ps min, 185ps max; typ from 1.72 V to 0 V
[POWER_clamp]
-3.3V     22.37A     22.96A     21.96A
-1.2V     2.026A     2.675A     1.569A
-1.167V   1.737A     2.381A     1.292A
-1.133V   1.455A     2.091A     1.027A
-1.1V     1.183A     1.806A     781.8mA
-1.067V   923.7mA    1.529A     562.8mA
-1.033V   682mA      1.26A      376.8mA
-966.7mV  284.5mA    761.6mA    118.2mA
-933.3mV  149.5mA    542mA      49.47mA
-866.7mV  26.4mA     203.8mA    9.959mA
-800mV    6.466mA    45.92mA    6.091mA
0V        403.5pA    4.834nA    163.5pA
[Pulldown]
-3.3V     -379.4uA   -332.5uA   -396.2uA
-1.3V     -2.567mA   -1.838mA   -3.256mA
-1.1V     -5.531mA   -3.228mA   -9.379mA
-900mV    -24.8mA    -9.221mA   -37.84mA
-700mV    -24.92mA   -18.03mA   -32.09mA
500mV     16.51mA    11.37mA    22.25mA
1.3V      31.39mA    20.91mA    43.42mA
3.7V      36.65mA    23.93mA    50.64mA
4.1V      36.79mA    3.426mA    51.12mA
4.4V      7.557mA    1.597mA    51.61mA
4.9V      1.707mA    822.5uA    5.677mA
6.6V      436uA      304.4uA    587.7uA
[Pullup]
-3.3V     352.6uA    285.2uA    400.6uA
-1.3V     2.559mA    1.632mA    3.875mA
-900mV    21.62mA    8.718mA    33.78mA
1.6V      -34.58mA   -23.24mA   -47.95mA
3.7V      -44.51mA   -27.33mA   -63.35mA
4.2V      -37.5mA    -2.71mA    -64.29mA
4.3V      -15.98mA   -2.138mA   -64.26mA
4.5V      -4.996mA   -1.492mA   -64.06mA
4.6V      -3.604mA   -1.294mA   -54.92mA
4.7V      -2.802mA   -1.142mA   -19.48mA
4.9V      -1.927mA   -922.6uA   -5.59mA
6.6V      -515.3uA   -347uA     -695.9uA
[GND_clamp]
-3.3V     -22.52A    -23.16A    -22.07A
-1.167V   -1.839A    -2.548A    -1.318A
-1.1V     -1.269A    -1.966A    -766.4mA
-1.033V   -744mA     -1.409A    -305.8mA
-966.7mV  -312.4mA   -893.1mA   -65.16mA
-900mV    -73.25mA   -452.3mA   -23.01mA
-833.3mV  -18.21mA   -153.7mA   -14.34mA
-766.7mV  -8.719mA   -34.69mA   -8.384mA
-700mV    -4.617mA   -8.747mA   -3.962mA
-433.3mV  -35.67uA   -118.9uA   -8.141uA
3.3V      403.5pA    85.4uA     95.55pA
[Ramp]
dV/dt_f  1.0230907/1.9224039n 0.69092388/2.9603124n  1.3568423/1.2759417n
dV/dt_r  1.0321167/1.5385884n 0.72983857/2.6960954n  1.3300534/0.92348523n
R_load = 50
[Rising Waveform]
R_fixture = 50
V_fixture = 3.3
V_fixture_min = 2.97
V_fixture_max = 3.63
0s        1.613V     1.833V     1.389V
274.9ps   1.67V      1.845V     1.65V
329ps     1.713V     1.852V     1.974V
402.8ps   1.859V     1.863V     2.652V
483.4ps   2.208V     1.884V     3.32V
622.6ps   2.959V     2.018V     3.606V
751.9ps   3.254V     2.31V      3.621V
955.3ps   3.292V     2.828V     3.624V
1.087ns   3.294V     2.945V     3.625V
8.184ns   3.3V       2.97V      3.63V
[Rising Waveform]
R_fixture = 50
V_fixture = 0
V_fixture_min = 0
V_fixture_max = 0
0s        615.3uV    905.7uV    830.8uV
424.3ps   60.37mV    27.19mV    137.9mV
620.7ps   126.5mV    43.11mV    505.8mV
1.004ns   455.9mV    112.8mV    1.153V
1.518ns   850.9mV    279.3mV    1.781V
2.204ns   1.278V     497.3mV    2.107V
3.003ns   1.565V     722.1mV    2.187V
4.411ns   1.691V     1.027V     2.213V
5.888ns   1.714V     1.159V     2.216V
8.184ns   1.719V     1.206V     2.216V
[Falling Waveform]
R_fixture = 50
V_fixture = 3.3
V_fixture_min = 2.97
V_fixture_max = 3.63
0s        3.3V       2.97V      3.63V
244.9ps   3.312V     2.97V      3.644V
429.5ps   3.292V     2.97V      3.511V
902.7ps   2.978V     2.905V     2.805V
1.549ns   2.554V     2.709V     2.096V
2.242ns   2.179V     2.517V     1.663V
2.727ns   1.99V      2.385V     1.524V
3.465ns   1.801V     2.214V     1.438V
4.711ns   1.67V      2.019V     1.396V
8.184ns   1.614V     1.852V     1.388V
[Falling Waveform]
R_fixture = 50
V_fixture = 0
V_fixture_min = 0
V_fixture_max = 0
0s        1.72V      1.216V     2.217V
213.4ps   1.702V     1.222V     2.091V
261.3ps   1.649V     1.216V     1.871V
328.3ps   1.493V     1.191V     1.361V
474.2ps   822.1mV    1.014V     377.1mV
545.9ps   518.7mV    863.2mV    152.5mV
686.3ps   154.9mV    525.5mV    14.15mV
865.6ps   16.18mV    210.8mV    2.29mV
1.141ns   2.383mV    26.92mV    1.882mV
8.184ns   1.944uV    45.76uV    0V
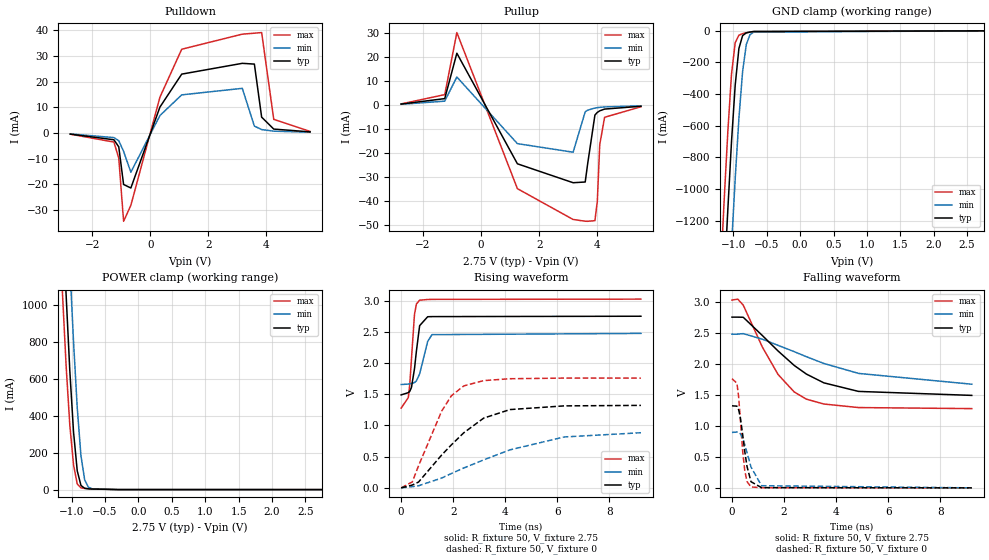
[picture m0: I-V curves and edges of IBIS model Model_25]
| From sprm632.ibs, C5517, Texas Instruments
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| Model based on original model for BC3350CTHYPD
|   Sub model PD_ON_IND_2P75
[model]   Model_25
|[Description]  [2.75V-I/O-PD-X, IND]
|   PD,IND,
|[Input Load]   PD
|[Output Drive]
|Voltage   2.75V
|Mode   I/O
Model_type   I/O
Polarity   Non-Inverting
Enable   Active-Low
Vinl =  0.7
Vinh =  1.7
Cref =  15.0000pF
Rref =  100.0000M
Vref =  0V
Vmeas =  1.375
C_comp   0.88864286p  0.88152539p   1.2993811p
[Model Spec]
Vinl   0.7   0.7   0.7
Vinh   1.7   1.7   1.7
[Temperature Range]   25   105   -40
[Voltage Range]   2.75   2.475   3.025
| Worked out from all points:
|   slope of the pulldown table from 0 to 0.412 V, typ, clamps not added: 34.2 ohm
|   slope of the pullup table from 0 to 0.412 V, typ, clamps not added: 40.5 ohm
|   GND clamp passes 1 mA (typ) near -0.58 V on its own axis
|   POWER clamp passes 1 mA (typ) near -0.52 V on its own axis
|   rising waveform, R_fixture 50, V_fixture 2.75: 20-80 % time 213ps typ, 291ps min, 165ps max; typ from 1.49 V to 2.75 V
|   rising waveform, R_fixture 50, V_fixture 0: 20-80 % time 1.93ns typ, 3.3ns min, 1.15ns max; typ from 0 V to 1.32 V
|   falling waveform, R_fixture 50, V_fixture 2.75: 20-80 % time 2.23ns typ, 3.34ns min, 1.48ns max; typ from 2.75 V to 1.49 V
|   falling waveform, R_fixture 50, V_fixture 0: 20-80 % time 266ps typ, 392ps min, 201ps max; typ from 1.32 V to 0 V
[POWER_clamp]
-2.75V    16.94A     17.55A     16.52A
-1.139V   1.502A     2.139A     1.07A
-1.083V   1.052A     1.667A     668.7mA
-1.028V   643.9mA    1.216A     349.4mA
-972.2mV  311.7mA    800.4mA    133.8mA
-916.7mV  101.6mA    443mA      30.48mA
-861.1mV  22.66mA    183.3mA    9.365mA
-805.6mV  7.07mA     53.14mA    6.359mA
-750mV    4.202mA    13.32mA    4.979mA
-694.4mV  3.123mA    4.501mA    3.827mA
-305.6mV  86.15uA    89.18uA    113.6uA
2.75V     -4.594nA   -15.01uA   24.32uA
[Pulldown]
-2.75V    -442uA     -375.6uA   -474.2uA
-1.25V    -2.654mA   -1.807mA   -3.559mA
-1.083V   -5.418mA   -3.009mA   -9.851mA
-916.7mV  -20.1mA    -7.193mA   -34.46mA
-666.7mV  -21.47mA   -15.31mA   -28.22mA
333.3mV   10.1mA     6.791mA    13.96mA
1.083V    22.95mA    14.86mA    32.66mA
3.167V    27.16mA    17.4mA     38.54mA
3.583V    26.86mA    2.673mA    38.92mA
3.833V    6.162mA    1.323mA    39.16mA
4.25V     1.511mA    698.6uA    5.299mA
5.5V      426.6uA    283.2uA    606.1uA
[Pullup]
-2.75V    418.2uA    329.2uA    487.1uA
-1.25V    2.701mA    1.641mA    4.369mA
-833.3mV  21.65mA    11.72mA    30.28mA
1.25V     -24.52mA   -16.1mA    -34.9mA
3.167V    -32.42mA   -19.68mA   -47.77mA
3.583V    -32.12mA   -2.8mA     -48.5mA
3.667V    -24.56mA   -2.134mA   -48.53mA
3.917V    -4.163mA   -1.221mA   -48.26mA
4V        -3.057mA   -1.065mA   -40.08mA
4.083V    -2.401mA   -944uA     -16.55mA
4.25V     -1.668mA   -767.9uA   -5.094mA
5.5V      -494.4uA   -316.6uA   -710uA
[GND_clamp]
-2.75V    -17.09A    -17.75A    -16.63A
-1.194V   -2.084A    -2.795A    -1.56A
-1.139V   -1.598A    -2.303A    -1.082A
-1.083V   -1.133A    -1.824A    -639.6mA
-1.028V   -703.6mA   -1.364A    -275.3mA
-972.2mV  -342.7mA   -934mA     -74.91mA
-916.7mV  -111.4mA   -552.8mA   -27.49mA
-861.1mV  -29.96mA   -256mA     -17.64mA
-805.6mV  -12.97mA   -85.39mA   -11.91mA
-750mV    -7.643mA   -23.86mA   -7.296mA
-694.4mV  -4.465mA   -8.126mA   -3.801mA
2.75V     61.47uA    63.97uA    104.1uA
[Ramp]
dV/dt_f 0.76490836/2.2506497n 0.49851192/3.4704818n  1.0583364/1.485832n
dV/dt_r 0.79331761/1.9288535n 0.53579978/3.3551272n  1.0556067/1.1482477n
R_load = 50
[Rising Waveform]
R_fixture = 50
V_fixture = 2.75
V_fixture_min = 2.475
V_fixture_max = 3.025
0s        1.489V     1.655V     1.277V
274.7ps   1.525V     1.663V     1.446V
329.5ps   1.545V     1.667V     1.649V
396.6ps   1.609V     1.671V     2.065V
512.3ps   1.907V     1.686V     2.779V
586.7ps   2.192V     1.714V     2.945V
710.2ps   2.598V     1.826V     3.006V
1.019ns   2.741V     2.345V     3.017V
1.184ns   2.743V     2.454V     3.019V
9.211ns   2.749V     2.474V     3.023V
[Rising Waveform]
R_fixture = 50
V_fixture = 0
V_fixture_min = 0
V_fixture_max = 0
0s        0V         272.6uV    780.6uV
429.2ps   45.15mV    19.54mV    95.49mV
668.6ps   93.45mV    33.46mV    354mV
1.552ns   524.2mV    156.4mV    1.226V
1.93ns    688.9mV    230.1mV    1.475V
2.405ns   882mV      318.1mV    1.633V
3.17ns    1.117V     448mV      1.718V
4.181ns   1.254V     609.1mV    1.748V
6.26ns    1.313V     815mV      1.758V
9.211ns   1.321V     883.1mV    1.758V
[Falling Waveform]
R_fixture = 50
V_fixture = 2.75
V_fixture_min = 2.475
V_fixture_max = 3.025
0s        2.749V     2.475V     3.024V
221.5ps   2.749V     2.475V     3.039V
432.2ps   2.747V     2.484V     2.943V
1.167ns   2.453V     2.394V     2.267V
1.77ns    2.204V     2.295V     1.826V
2.391ns   1.971V     2.193V     1.544V
2.859ns   1.832V     2.112V     1.428V
3.529ns   1.691V     2.003V     1.35V
4.861ns   1.553V     1.843V     1.293V
9.211ns   1.489V     1.669V     1.276V
[Falling Waveform]
R_fixture = 50
V_fixture = 0
V_fixture_min = 0
V_fixture_max = 0
0s        1.321V     892.7mV    1.758V
190.5ps   1.316V     898.7mV    1.685V
256.2ps   1.258V     894.5mV    1.465V
318.6ps   1.139V     873.2mV    1.116V
410.7ps   855.9mV    798.6mV    593.4mV
489.2ps   592.1mV    700.9mV    283.5mV
577.1ps   346mV      567.7mV    100.4mV
731.6ps   98.61mV    335mV      14.39mV
1.135ns   3.712mV    34.77mV    2.498mV
9.211ns   1.278uV    35.77uV    0V
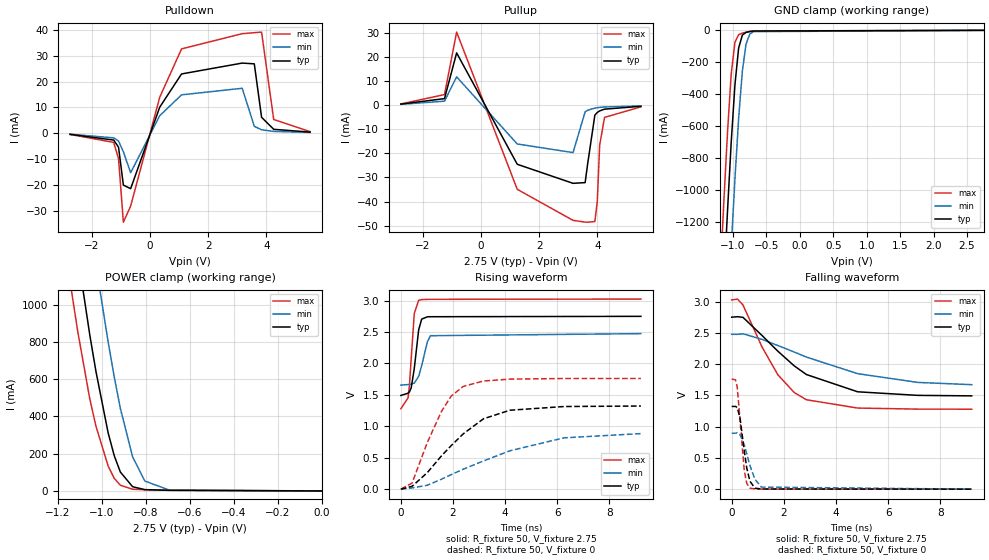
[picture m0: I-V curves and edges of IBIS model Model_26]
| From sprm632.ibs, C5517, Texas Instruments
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| Model based on original model for BC3350CTHYPD
|   Sub model PD_OFF_IND_2P75
[model]   Model_26
|[Description]  [2.75V-I/O-PD_OFF-X, IND]
|   PD_OFF,IND,
|[Input Load]   PD_OFF
|[Output Drive]
|Voltage   2.75V
|Mode   I/O
Model_type   I/O
Polarity   Non-Inverting
Enable   Active-Low
Vinl =  0.7
Vinh =  1.7
Cref =  15.0000pF
Rref =  100.0000M
Vref =  0V
Vmeas =  1.375
C_comp   0.88864286p  0.88152539p   1.2993811p
[Model Spec]
Vinl   0.7   0.7   0.7
Vinh   1.7   1.7   1.7
[Temperature Range]   25   105   -40
[Voltage Range]   2.75   2.475   3.025
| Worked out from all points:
|   slope of the pulldown table from 0 to 0.412 V, typ, clamps not added: 34.2 ohm
|   slope of the pullup table from 0 to 0.412 V, typ, clamps not added: 40.5 ohm
|   GND clamp passes 1 mA (typ) near -0.59 V on its own axis
|   POWER clamp passes 1 mA (typ) near -0.52 V on its own axis
|   rising waveform, R_fixture 50, V_fixture 2.75: 20-80 % time 213ps typ, 290ps min, 165ps max; typ from 1.49 V to 2.75 V
|   rising waveform, R_fixture 50, V_fixture 0: 20-80 % time 1.93ns typ, 3.29ns min, 1.14ns max; typ from 0 V to 1.32 V
|   falling waveform, R_fixture 50, V_fixture 2.75: 20-80 % time 2.23ns typ, 3.33ns min, 1.48ns max; typ from 2.75 V to 1.49 V
|   falling waveform, R_fixture 50, V_fixture 0: 20-80 % time 264ps typ, 390ps min, 199ps max; typ from 1.32 V to 0 V
[POWER_clamp]
-2.75V    16.94A     17.55A     16.52A
-1.167V   1.737A     2.381A     1.292A
-1.111V   1.273A     1.9A       861.3mA
-1.056V   840.8mA    1.438A     496.8mA
-1.028V   643.9mA    1.216A     349.4mA
-972.2mV  311.6mA    800.4mA    133.7mA
-944.4mV  188.9mA    612.4mA    67.69mA
-916.7mV  101.5mA    443mA      30.38mA
-861.1mV  22.6mA     183.2mA    9.262mA
-805.6mV  7.009mA    53.11mA    6.255mA
-694.4mV  3.061mA    4.465mA    3.723mA
0V        327.1pA    3.775nA    188.1pA
[Pulldown]
-2.75V    -442uA     -375.6uA   -474.2uA
-1.25V    -2.654mA   -1.807mA   -3.559mA
-1.083V   -5.418mA   -3.009mA   -9.851mA
-916.7mV  -20.1mA    -7.193mA   -34.46mA
-666.7mV  -21.47mA   -15.31mA   -28.22mA
333.3mV   10.1mA     6.791mA    13.96mA
1.083V    22.95mA    14.86mA    32.66mA
3.167V    27.16mA    17.4mA     38.54mA
3.583V    26.86mA    2.673mA    38.92mA
3.833V    6.162mA    1.323mA    39.16mA
4.25V     1.511mA    698.6uA    5.299mA
5.5V      426.6uA    283.2uA    606.1uA
[Pullup]
-2.75V    418.2uA    329.2uA    487.1uA
-1.25V    2.701mA    1.641mA    4.369mA
-833.3mV  21.65mA    11.72mA    30.28mA
1.25V     -24.52mA   -16.1mA    -34.9mA
3.167V    -32.42mA   -19.68mA   -47.77mA
3.583V    -32.12mA   -2.8mA     -48.5mA
3.667V    -24.56mA   -2.134mA   -48.53mA
3.917V    -4.163mA   -1.221mA   -48.26mA
4V        -3.057mA   -1.065mA   -40.08mA
4.083V    -2.401mA   -944uA     -16.55mA
4.25V     -1.668mA   -767.9uA   -5.094mA
5.5V      -494.4uA   -316.6uA   -710uA
[GND_clamp]
-2.75V    -17.09A    -17.75A    -16.63A
-1.194V   -2.084A    -2.795A    -1.56A
-1.139V   -1.598A    -2.303A    -1.082A
-1.083V   -1.133A    -1.824A    -639.6mA
-1.028V   -703.5mA   -1.364A    -275.3mA
-972.2mV  -342.7mA   -934mA     -74.87mA
-916.7mV  -111.3mA   -552.8mA   -27.41mA
-861.1mV  -29.93mA   -256mA     -17.56mA
-805.6mV  -12.93mA   -85.38mA   -11.83mA
-750mV    -7.594mA   -23.85mA   -7.221mA
-694.4mV  -4.418mA   -8.104mA   -3.731mA
2.75V     327.1pA    28.51uA    123.6pA
[Ramp]
dV/dt_f 0.76421681/2.2477957n 0.49811437/3.4664555n  1.0576226/1.4851522n
dV/dt_r 0.79443793/1.9262057n 0.53649209/3.3528161n   1.057202/1.1456655n
R_load = 50
[Rising Waveform]
R_fixture = 50
V_fixture = 2.75
V_fixture_min = 2.475
V_fixture_max = 3.025
0s        1.491V     1.657V     1.28V
274.7ps   1.527V     1.664V     1.45V
329.5ps   1.548V     1.668V     1.655V
396.6ps   1.612V     1.673V     2.074V
514.8ps   1.92V      1.688V     2.795V
683.1ps   2.535V     1.795V     3.005V
798.4ps   2.706V     1.966V     3.017V
1.019ns   2.743V     2.346V     3.02V
1.137ns   2.744V     2.442V     3.021V
9.211ns   2.75V      2.475V     3.025V
[Rising Waveform]
R_fixture = 50
V_fixture = 0
V_fixture_min = 0
V_fixture_max = 0
0s        0V         270.7uV    777.5uV
429.2ps   45.32mV    19.62mV    96mV
1.01ns    261.3mV    61.88mV    738.6mV
1.554ns   527.9mV    157.5mV    1.234V
1.933ns   693.2mV    231.8mV    1.482V
2.395ns   881mV      317.4mV    1.635V
3.17ns    1.12V      449.4mV    1.721V
4.181ns   1.256V     610.7mV    1.751V
6.26ns    1.315V     816.4mV    1.761V
9.211ns   1.323V     884.3mV    1.761V
[Falling Waveform]
R_fixture = 50
V_fixture = 2.75
V_fixture_min = 2.475
V_fixture_max = 3.025
0s        2.75V      2.476V     3.026V
221.5ps   2.758V     2.476V     3.04V
432.2ps   2.748V     2.485V     2.946V
1.167ns   2.456V     2.395V     2.271V
1.772ns   2.206V     2.297V     1.829V
2.398ns   1.972V     2.193V     1.546V
2.868ns   1.833V     2.112V     1.43V
4.834ns   1.557V     1.847V     1.297V
7.141ns   1.5V       1.707V     1.28V
9.211ns   1.492V     1.671V     1.279V
[Falling Waveform]
R_fixture = 50
V_fixture = 0
V_fixture_min = 0
V_fixture_max = 0
0s        1.323V     893.9mV    1.761V
146.7ps   1.323V     896.2mV    1.748V
212.4ps   1.306V     900.2mV    1.634V
318.6ps   1.141V     874.3mV    1.116V
481.4ps   614.4mV    711.7mV    301.1mV
577.1ps   341.9mV    567.1mV    93.98mV
699.2ps   128mV      378.6mV    17.02mV
888.7ps   16.47mV    160.1mV    3.046mV
1.135ns   2.529mV    32.88mV    1.862mV
9.211ns   1.36uV     36.27uV    0V
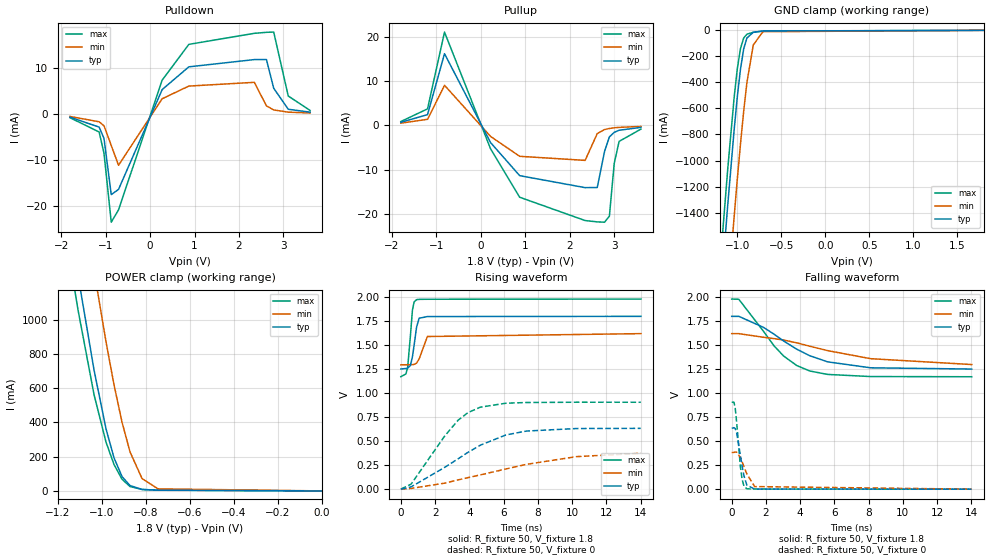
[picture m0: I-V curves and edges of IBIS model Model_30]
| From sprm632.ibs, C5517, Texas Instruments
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| Model based on original model for BC3350CTHYPD
|   Sub model PD_OFF_COM_1P8
[model]   Model_30
|[Description]  [1.8V-I/O-PD_OFF-X, COM]
|   PD_OFF,COM,
|[Input Load]   PD_OFF
|[Output Drive]
|Voltage   1.8V
|Mode   I/O
Model_type   I/O
Polarity   Non-Inverting
Enable   Active-Low
Vinl =  0.63
Vinh =  1.17
Cref =  15.0000pF
Rref =  100.0000M
Vref =  0V
Vmeas =  0.9
C_comp   1.505438p   1.4840531p   1.52103p
[Model Spec]
Vinl   0.63   0.567   0.693
Vinh   1.17   1.053   1.287
[Temperature Range]   25   105   -10
[Voltage Range]   1.8   1.62   1.98
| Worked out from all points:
|   slope of the pulldown table from 0 to 0.27 V, typ, clamps not added: 51 ohm
|   slope of the pullup table from 0 to 0.27 V, typ, clamps not added: 57.1 ohm
|   GND clamp passes 1 mA (typ) near -0.59 V on its own axis
|   POWER clamp passes 1 mA (typ) near -0.52 V on its own axis
|   rising waveform, R_fixture 50, V_fixture 1.8: 20-80 % time 261ps typ, 379ps min, 208ps max; typ from 1.25 V to 1.8 V
|   rising waveform, R_fixture 50, V_fixture 0: 20-80 % time 3.48ns typ, 5.71ns min, 2.28ns max; typ from 0.001 V to 0.634 V
|   falling waveform, R_fixture 50, V_fixture 1.8: 20-80 % time 3.23ns typ, 5.02ns min, 2.28ns max; typ from 1.8 V to 1.25 V
|   falling waveform, R_fixture 50, V_fixture 0: 20-80 % time 357ps typ, 550ps min, 266ps max; typ from 0.634 V to 0 V
[POWER_clamp]
-1.8V     7.656A     8.299A     7.406A
-1.145V   1.557A     2.196A     1.339A
-1.127V   1.405A     2.039A     1.195A
-1.109V   1.256A     1.883A     1.055A
-1.036V   703.1mA    1.284A     559.8mA
-981.8mV  361.6mA    868.9mA    284.1mA
-945.5mV  192.7mA    618.9mA    154mA
-909.1mV  83.65mA    400.5mA    67.92mA
-872.7mV  31.2mA     227.3mA    25.56mA
-818.2mV  8.542mA    72.07mA    8.371mA
-745.5mV  4.031mA    12.05mA    4.916mA
0V        170.6pA    2.308nA    151.6pA
[Pulldown]
-1.8V     -681.9uA   -528.3uA   -799.6uA
-1.145V   -2.848mA   -1.688mA   -3.914mA
-1.036V   -5.317mA   -2.553mA   -8.567mA
-872.7mV  -17.57mA   -6.855mA   -23.59mA
-709.1mV  -16.44mA   -11.17mA   -20.89mA
272.7mV   5.341mA    3.341mA    7.405mA
872.7mV   10.3mA     6.104mA    15.2mA
2.345V    11.88mA    6.92mA     17.61mA
2.618V    11.89mA    1.797mA    17.83mA
2.782V    5.623mA    889uA      17.88mA
3.109V    1.046mA    417.7uA    3.932mA
3.6V      416.6uA    227.7uA    789.5uA
[Pullup]
-1.8V     683.6uA    489.2uA    862.2uA
-1.2V     2.423mA    1.368mA    3.723mA
-818.2mV  16.21mA    9.062mA    21.1mA
218.2mV   -3.905mA   -2.516mA   -5.325mA
872.7mV   -11.39mA   -7.011mA   -16.27mA
2.345V    -14.1mA    -7.933mA   -21.55mA
2.618V    -14.07mA   -1.864mA   -21.85mA
2.782V    -5.914mA   -955.1uA   -21.92mA
2.891V    -2.623mA   -708.3uA   -20.54mA
3V        -1.582mA   -559.9uA   -8.606mA
3.109V    -1.114mA   -461.7uA   -3.639mA
3.6V      -465.4uA   -255.6uA   -860.2uA
[GND_clamp]
-1.8V     -7.797A    -8.487A    -7.522A
-1.182V   -1.972A    -2.683A    -1.687A
-1.145V   -1.654A    -2.361A    -1.372A
-1.109V   -1.345A    -2.044A    -1.068A
-1.036V   -766.6mA   -1.434A    -516.9mA
-1V       -511.1mA   -1.144A    -295mA
-963.6mV  -296.8mA   -871.2mA   -139.2mA
-927.3mV  -142.6mA   -620.4mA   -58.94mA
-890.9mV  -58.94mA   -401.7mA   -29.72mA
-818.2mV  -14.96mA   -112.4mA   -14.89mA
-709.1mV  -5.146mA   -10.44mA   -5.969mA
1.8V      170.6pA    3.271uA    -259.8pA
[Ramp]
dV/dt_f 0.33494281/3.2873853n 0.19913327/5.2259794n  0.4919679/2.3059315n
dV/dt_r 0.38058364/3.483245n  0.22884951/5.8893625n 0.54383768/2.2831261n
R_load = 50
[Rising Waveform]
R_fixture = 50
V_fixture = 1.8
V_fixture_min = 1.62
V_fixture_max = 1.98
0s        1.252V     1.295V     1.172V
292.5ps   1.257V     1.296V     1.2V
395.6ps   1.261V     1.296V     1.265V
556.5ps   1.288V     1.297V     1.595V
675.3ps   1.378V     1.297V     1.864V
772.7ps   1.498V     1.3V       1.949V
917.6ps   1.688V     1.313V     1.974V
1.066ns   1.78V      1.356V     1.977V
1.549ns   1.798V     1.59V      1.978V
14.02ns   1.8V       1.62V      1.98V
[Rising Waveform]
R_fixture = 50
V_fixture = 0
V_fixture_min = 0
V_fixture_max = 0
0s        658.2uV    354.6uV    833.3uV
599.9ps   24.3mV     8.112mV    53.22mV
2.561ns   227.8mV    63.32mV    554.2mV
3.342ns   316.6mV    96.74mV    718mV
3.922ns   383.9mV    120.6mV    797.9mV
4.647ns   458.6mV    149.2mV    854.7mV
6.139ns   565.1mV    210.7mV    895.4mV
7.336ns   605.5mV    258.9mV    902.8mV
10.26ns   631.8mV    339.2mV    905.7mV
14.01ns   633.6mV    374mV      905.4mV
[Falling Waveform]
R_fixture = 50
V_fixture = 1.8
V_fixture_min = 1.62
V_fixture_max = 1.98
0s        1.8V       1.62V      1.98V
414.9ps   1.8V       1.62V      1.978V
1.851ns   1.686V     1.582V     1.646V
2.472ns   1.614V     1.568V     1.493V
3.037ns   1.543V     1.553V     1.386V
3.797ns   1.458V     1.524V     1.288V
4.556ns   1.39V      1.489V     1.231V
5.604ns   1.326V     1.443V     1.195V
8.114ns   1.264V     1.359V     1.173V
14.02ns   1.251V     1.298V     1.171V
[Falling Waveform]
R_fixture = 50
V_fixture = 0
V_fixture_min = 0
V_fixture_max = 0
0s        633.9mV    381.3mV    905.5mV
131ps     640.5mV    383mV      905.5mV
206.2ps   631.4mV    386.9mV    845.2mV
299.2ps   580.8mV    384.2mV    679.2mV
503.5ps   357.1mV    331.4mV    242.3mV
604.9ps   242.4mV    287.6mV    104.6mV
718.7ps   137.4mV    233.7mV    29.78mV
887.1ps   40.96mV    157.5mV    3.767mV
1.342ns   1.044mV    26.9mV     1.382mV
14.01ns   0V         14.93uV    0V
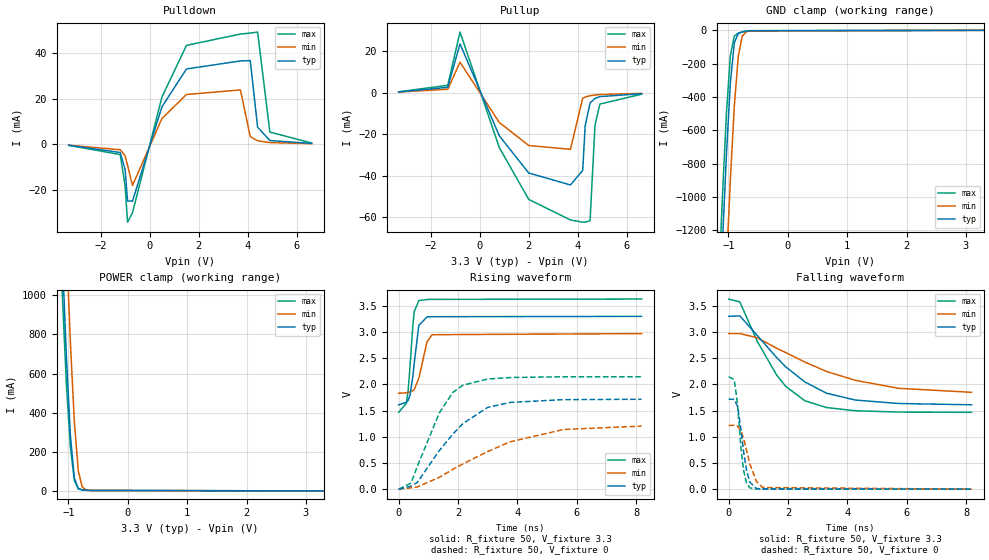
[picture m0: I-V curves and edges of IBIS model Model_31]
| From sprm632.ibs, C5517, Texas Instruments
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| Model based on original model for BC3350CTHYPD
|   Sub model PD_ON_COM_3P3
[model]   Model_31
|[Description]  [3.3V-I/O-PD-X, COM]
|   PD,COM,
|[Input Load]   PD
|[Output Drive]
|Voltage   3.3V
|Mode   I/O
Model_type   I/O
Polarity   Non-Inverting
Enable   Active-Low
Vinl =  0.8
Vinh =  2
Cref =  15.0000pF
Rref =  100.0000M
Vref =  0V
Vmeas =  1.65
C_comp   0.87673039p  0.86952386p   1.2993811p
[Model Spec]
Vinl   0.8   0.8   0.8
Vinh   2   2   2
[Temperature Range]   25   105   -10
[Voltage Range]   3.3   2.97   3.63
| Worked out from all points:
|   slope of the pulldown table from 0 to 0.495 V, typ, clamps not added: 30.2 ohm
|   slope of the pullup table from 0 to 0.495 V, typ, clamps not added: 36.2 ohm
|   GND clamp passes 1 mA (typ) near -0.58 V on its own axis
|   POWER clamp passes 1 mA (typ) near -0.51 V on its own axis
|   rising waveform, R_fixture 50, V_fixture 3.3: 20-80 % time 197ps typ, 267ps min, 165ps max; typ from 1.61 V to 3.3 V
|   rising waveform, R_fixture 50, V_fixture 0: 20-80 % time 1.53ns typ, 2.64ns min, 1.02ns max; typ from 0.001 V to 1.72 V
|   falling waveform, R_fixture 50, V_fixture 3.3: 20-80 % time 1.91ns typ, 2.88ns min, 1.39ns max; typ from 3.3 V to 1.61 V
|   falling waveform, R_fixture 50, V_fixture 0: 20-80 % time 246ps typ, 352ps min, 200ps max; typ from 1.72 V to 0 V
[POWER_clamp]
-3.3V     22.37A     22.96A     22.14A
-1.167V   1.737A     2.381A     1.512A
-1.1V     1.183A     1.806A     986.6mA
-1.033V   682.1mA    1.26A      542.1mA
-966.7mV  284.5mA    761.6mA    224.8mA
-900mV    65.82mA    352.3mA    53.54mA
-833.3mV  11.6mA     102.7mA    10.64mA
-766.7mV  4.746mA    20.06mA    5.625mA
-700mV    3.243mA    4.908mA    4.09mA
-633.3mV  2.292mA    2.258mA    2.914mA
3.3V      -5.816nA   -29.15uA   30.53uA
[Pulldown]
-3.3V     -379.4uA   -332.5uA   -410.9uA
-1.2V     -3.537mA   -2.351mA   -4.45mA
-1V       -10.99mA   -4.979mA   -18.19mA
-900mV    -24.8mA    -9.223mA   -34.14mA
-700mV    -24.92mA   -18.03mA   -29.99mA
500mV     16.51mA    11.37mA    20.75mA
1.5V      33.12mA    21.9mA     43.48mA
3.7V      36.65mA    23.93mA    48.44mA
4.1V      36.79mA    3.426mA    48.89mA
4.4V      7.557mA    1.597mA    49.31mA
4.9V      1.707mA    822.5uA    5.402mA
6.6V      436uA      304.4uA    625.7uA
[Pullup]
-3.3V     352.6uA    285.2uA    404.5uA
-1.3V     2.559mA    1.632mA    3.524mA
-800mV    23.47mA    14.67mA    29.18mA
800mV     -20.79mA   -14.38mA   -26.49mA
2V        -38.75mA   -25.51mA   -51.47mA
3.7V      -44.51mA   -27.32mA   -61.38mA
4.2V      -37.49mA   -2.71mA    -62.46mA
4.3V      -15.99mA   -2.138mA   -62.46mA
4.5V      -4.997mA   -1.493mA   -61.74mA
4.7V      -2.803mA   -1.142mA   -15.75mA
4.9V      -1.928mA   -922.7uA   -5.515mA
6.6V      -515.4uA   -347uA     -755.5uA
[GND_clamp]
-3.3V     -22.52A    -23.16A    -22.27A
-1.167V   -1.839A    -2.548A    -1.554A
-1.1V     -1.269A    -1.966A    -993.7mA
-1.033V   -744.2mA   -1.409A    -496.6mA
-966.7mV  -312.7mA   -893.3mA   -149.2mA
-900mV    -73.59mA   -452.5mA   -34.23mA
-833.3mV  -18.47mA   -154mA     -16.74mA
-766.7mV  -8.896mA   -34.94mA   -10.19mA
-700mV    -4.738mA   -8.896mA   -5.485mA
-633.3mV  -2.121mA   -3.29mA    -2.333mA
3.3V      93.69uA    139.7uA    138.8uA
[Ramp]
dV/dt_f  1.0238659/1.9232564n 0.69143231/2.9931824n  1.3081274/1.3897684n
dV/dt_r  1.0304065/1.5353995n 0.72882488/2.677547n   1.2879696/1.0174418n
R_load = 50
[Rising Waveform]
R_fixture = 50
V_fixture = 3.3
V_fixture_min = 2.97
V_fixture_max = 3.63
0s        1.61V      1.83V      1.467V
258.9ps   1.658V     1.84V      1.639V
317.5ps   1.694V     1.848V     1.871V
381.8ps   1.79V      1.856V     2.34V
476.8ps   2.147V     1.877V     3.125V
524ps     2.403V     1.901V     3.387V
678.6ps   3.126V     2.115V     3.6V
955.3ps   3.287V     2.813V     3.62V
1.126ns   3.291V     2.948V     3.622V
8.184ns   3.298V     2.969V     3.628V
[Rising Waveform]
R_fixture = 50
V_fixture = 0
V_fixture_min = 0
V_fixture_max = 0
0s        585.7uV    869.4uV    670.5uV
417.7ps   58.84mV    26.1mV     115.6mV
625.1ps   127.2mV    42.99mV    432mV
1.367ns   736.1mV    225.1mV    1.453V
1.822ns   1.049V     377.3mV    1.845V
2.162ns   1.251V     481.9mV    1.984V
2.996ns   1.561V     718mV      2.102V
3.764ns   1.656V     905.5mV    2.131V
5.548ns   1.709V     1.139V     2.145V
8.184ns   1.716V     1.204V     2.146V
[Falling Waveform]
R_fixture = 50
V_fixture = 3.3
V_fixture_min = 2.97
V_fixture_max = 3.63
0s        3.298V     2.969V     3.627V
376.9ps   3.306V     2.969V     3.572V
962.9ps   2.933V     2.888V     2.821V
1.612ns   2.514V     2.691V     2.181V
1.926ns   2.332V     2.605V     1.959V
2.568ns   2.045V     2.425V     1.686V
3.299ns   1.83V      2.245V     1.557V
4.271ns   1.7V       2.076V     1.496V
5.73ns    1.634V     1.924V     1.471V
8.184ns   1.61V      1.848V     1.466V
[Falling Waveform]
R_fixture = 50
V_fixture = 0
V_fixture_min = 0
V_fixture_max = 0
0s        1.717V     1.215V     2.146V
189.1ps   1.713V     1.219V     2.09V
301.1ps   1.576V     1.202V     1.605V
415ps     1.133V     1.113V     788.2mV
500ps     729.3mV    971.8mV    366.8mV
600.3ps   364.5mV    743.8mV    117.1mV
714.4ps   133.3mV    480.7mV    24.28mV
934.1ps   12.33mV    148.1mV    4.054mV
1.146ns   3.962mV    31.07mV    2.864mV
8.184ns   2.217uV    43.05uV    0V
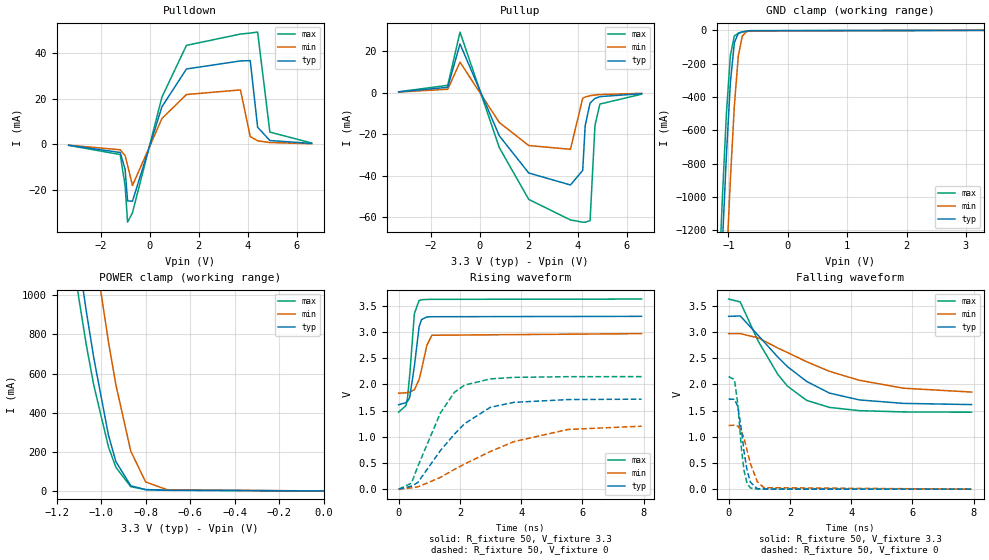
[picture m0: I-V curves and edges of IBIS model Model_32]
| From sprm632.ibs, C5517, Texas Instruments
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| Model based on original model for BC3350CTHYPD
|   Sub model PD_OFF_COM_3P3
[model]   Model_32
|[Description]  [3.3V-I/O-PD_OFF-X, COM]
|   PD_OFF,COM,
|[Input Load]   PD_OFF
|[Output Drive]
|Voltage   3.3V
|Mode   I/O
Model_type   I/O
Polarity   Non-Inverting
Enable   Active-Low
Vinl =  0.8
Vinh =  2
Cref =  15.0000pF
Rref =  100.0000M
Vref =  0V
Vmeas =  1.65
C_comp   0.87673039p  0.86952386p   1.2993811p
[Model Spec]
Vinl   0.8   0.8   0.8
Vinh   2   2   2
[Temperature Range]   25   105   -10
[Voltage Range]   3.3   2.97   3.63
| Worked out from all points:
|   slope of the pulldown table from 0 to 0.495 V, typ, clamps not added: 30.2 ohm
|   slope of the pullup table from 0 to 0.495 V, typ, clamps not added: 36.2 ohm
|   GND clamp passes 1 mA (typ) near -0.58 V on its own axis
|   POWER clamp passes 1 mA (typ) near -0.52 V on its own axis
|   rising waveform, R_fixture 50, V_fixture 3.3: 20-80 % time 199ps typ, 267ps min, 164ps max; typ from 1.61 V to 3.3 V
|   rising waveform, R_fixture 50, V_fixture 0: 20-80 % time 1.53ns typ, 2.63ns min, 1.01ns max; typ from 0.001 V to 1.72 V
|   falling waveform, R_fixture 50, V_fixture 3.3: 20-80 % time 1.91ns typ, 2.86ns min, 1.39ns max; typ from 3.3 V to 1.61 V
|   falling waveform, R_fixture 50, V_fixture 0: 20-80 % time 244ps typ, 350ps min, 199ps max; typ from 1.72 V to 0 V
[POWER_clamp]
-3.3V     22.37A     22.96A     22.14A
-1.167V   1.737A     2.381A     1.512A
-1.133V   1.455A     2.091A     1.242A
-1.1V     1.183A     1.806A     986.5mA
-1.067V   923.7mA    1.529A     751.1mA
-1.033V   682mA      1.26A      542mA
-966.7mV  284.5mA    761.6mA    224.7mA
-933.3mV  149.5mA    542mA      120.3mA
-866.7mV  26.4mA     203.8mA    21.79mA
-800mV    6.466mA    45.92mA    6.888mA
-700mV    3.149mA    4.854mA    3.951mA
0V        473.5pA    4.973nA    559.6pA
[Pulldown]
-3.3V     -379.4uA   -332.5uA   -410.9uA
-1.2V     -3.537mA   -2.351mA   -4.45mA
-1V       -10.99mA   -4.979mA   -18.19mA
-900mV    -24.8mA    -9.223mA   -34.14mA
-700mV    -24.92mA   -18.03mA   -29.99mA
500mV     16.51mA    11.37mA    20.75mA
1.5V      33.12mA    21.9mA     43.48mA
3.7V      36.65mA    23.93mA    48.44mA
4.1V      36.79mA    3.426mA    48.89mA
4.4V      7.557mA    1.597mA    49.31mA
4.9V      1.707mA    822.5uA    5.402mA
6.6V      436uA      304.4uA    625.7uA
[Pullup]
-3.3V     352.6uA    285.2uA    404.5uA
-1.3V     2.559mA    1.632mA    3.524mA
-800mV    23.47mA    14.67mA    29.18mA
800mV     -20.79mA   -14.38mA   -26.49mA
2V        -38.75mA   -25.51mA   -51.47mA
3.7V      -44.51mA   -27.32mA   -61.38mA
4.2V      -37.49mA   -2.71mA    -62.46mA
4.3V      -15.99mA   -2.138mA   -62.46mA
4.5V      -4.997mA   -1.493mA   -61.73mA
4.7V      -2.803mA   -1.142mA   -15.75mA
4.9V      -1.928mA   -922.7uA   -5.515mA
6.6V      -515.4uA   -347uA     -755.5uA
[GND_clamp]
-3.3V     -22.52A    -23.16A    -22.27A
-1.167V   -1.839A    -2.548A    -1.554A
-1.1V     -1.269A    -1.966A    -993.7mA
-1.033V   -744.2mA   -1.409A    -496.5mA
-966.7mV  -312.7mA   -893.3mA   -149.2mA
-900mV    -73.57mA   -452.5mA   -34.16mA
-833.3mV  -18.42mA   -154mA     -16.66mA
-766.7mV  -8.839mA   -34.92mA   -10.11mA
-700mV    -4.683mA   -8.87mA    -5.414mA
-633.3mV  -2.071mA   -3.26mA    -2.268mA
3.3V      473.5pA    85.4uA     -33.23pA
[Ramp]
dV/dt_f  1.0230308/1.9236911n 0.69082822/2.9913011n   1.307581/1.3904679n
dV/dt_r  1.0319633/1.5324042n  0.7298248/2.6739556n  1.2899652/1.0138915n
R_load = 50
[Rising Waveform]
R_fixture = 50
V_fixture = 3.3
V_fixture_min = 2.97
V_fixture_max = 3.63
0s        1.613V     1.833V     1.471V
234.9ps   1.653V     1.84V      1.595V
288.2ps   1.676V     1.847V     1.737V
360.8ps   1.754V     1.856V     2.18V
513.2ps   2.35V      1.898V     3.353V
667.1ps   3.102V     2.093V     3.603V
748.6ps   3.24V      2.29V      3.617V
922.5ps   3.289V     2.751V     3.623V
1.086ns   3.293V     2.939V     3.625V
7.933ns   3.3V       2.97V      3.63V
[Rising Waveform]
R_fixture = 50
V_fixture = 0
V_fixture_min = 0
V_fixture_max = 0
0s        582.9uV    868.7uV    667.3uV
417.7ps   59.07mV    26.21mV    116.2mV
625.2ps   128mV      43.13mV    436.7mV
1.368ns   740.7mV    226.5mV    1.461V
1.821ns   1.052V     378.6mV    1.851V
2.158ns   1.253V     482.7mV    1.988V
2.996ns   1.564V     720.3mV    2.106V
3.764ns   1.658V     907.7mV    2.135V
5.525ns   1.711V     1.14V      2.148V
7.932ns   1.719V     1.203V     2.149V
[Falling Waveform]
R_fixture = 50
V_fixture = 3.3
V_fixture_min = 2.97
V_fixture_max = 3.63
0s        3.3V       2.97V      3.63V
376.9ps   3.308V     2.97V      3.575V
961.9ps   2.938V     2.89V      2.829V
1.608ns   2.52V      2.694V     2.189V
1.923ns   2.338V     2.608V     1.965V
2.548ns   2.056V     2.433V     1.695V
3.295ns   1.834V     2.249V     1.561V
4.268ns   1.704V     2.079V     1.499V
5.705ns   1.638V     1.928V     1.475V
7.933ns   1.615V     1.854V     1.47V
[Falling Waveform]
R_fixture = 50
V_fixture = 0
V_fixture_min = 0
V_fixture_max = 0
0s        1.72V      1.216V     2.15V
189.1ps   1.716V     1.221V     2.093V
301.1ps   1.578V     1.204V     1.606V
415ps     1.133V     1.114V     782.8mV
500.1ps   725.6mV    972.3mV    358.4mV
601ps     357.2mV    741.5mV    108.7mV
711.4ps   131.4mV    484.9mV    21.22mV
934.1ps   9.459mV    144.9mV    2.666mV
1.146ns   2.771mV    28.7mV     2.135mV
7.932ns   3.095uV    52.29uV    0V
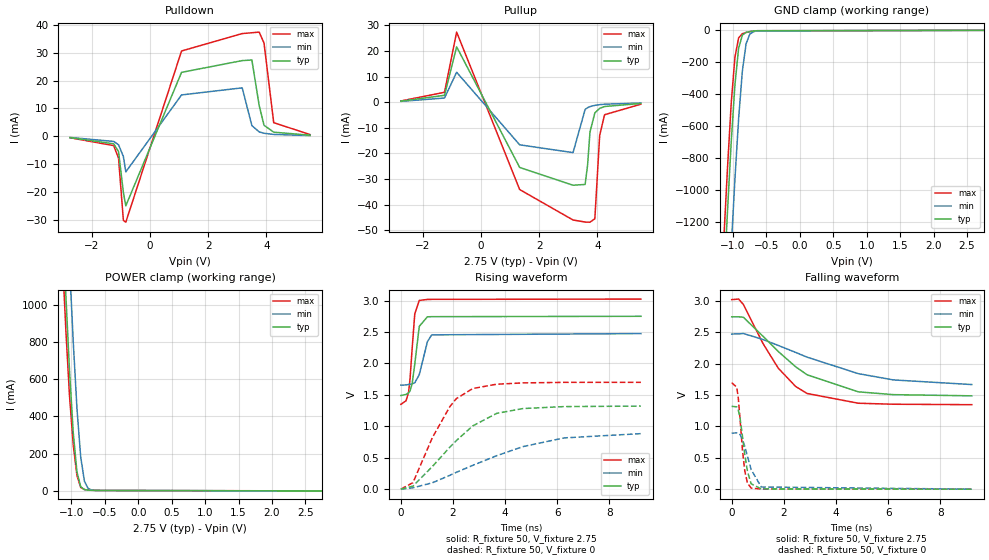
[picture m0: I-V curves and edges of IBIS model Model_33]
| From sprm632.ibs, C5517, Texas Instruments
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| Model based on original model for BC3350CTHYPD
|   Sub model PD_ON_COM_2P75
[model]   Model_33
|[Description]  [2.75V-I/O-PD-X, COM]
|   PD,COM,
|[Input Load]   PD
|[Output Drive]
|Voltage   2.75V
|Mode   I/O
Model_type   I/O
Polarity   Non-Inverting
Enable   Active-Low
Vinl =  0.7
Vinh =  1.7
Cref =  15.0000pF
Rref =  100.0000M
Vref =  0V
Vmeas =  1.375
C_comp   0.88864286p  0.88152539p   1.2993811p
[Model Spec]
Vinl   0.7   0.7   0.7
Vinh   1.7   1.7   1.7
[Temperature Range]   25   105   -10
[Voltage Range]   2.75   2.475   3.025
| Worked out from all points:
|   slope of the pulldown table from 0 to 0.412 V, typ, clamps not added: 34.2 ohm
|   slope of the pullup table from 0 to 0.412 V, typ, clamps not added: 40.5 ohm
|   GND clamp passes 1 mA (typ) near -0.58 V on its own axis
|   POWER clamp passes 1 mA (typ) near -0.52 V on its own axis
|   rising waveform, R_fixture 50, V_fixture 2.75: 20-80 % time 213ps typ, 291ps min, 175ps max; typ from 1.49 V to 2.75 V
|   rising waveform, R_fixture 50, V_fixture 0: 20-80 % time 1.93ns typ, 3.3ns min, 1.27ns max; typ from 0 V to 1.32 V
|   falling waveform, R_fixture 50, V_fixture 2.75: 20-80 % time 2.23ns typ, 3.34ns min, 1.59ns max; typ from 2.75 V to 1.49 V
|   falling waveform, R_fixture 50, V_fixture 0: 20-80 % time 266ps typ, 392ps min, 212ps max; typ from 1.32 V to 0 V
[POWER_clamp]
-2.75V    16.94A     17.55A     16.71A
-1.139V   1.502A     2.139A     1.286A
-1.083V   1.052A     1.667A     866.1mA
-1.028V   643.9mA    1.216A     510.2mA
-972.2mV  311.7mA    800.4mA    245.6mA
-916.7mV  101.6mA    443mA      82.35mA
-861.1mV  22.66mA    183.3mA    18.91mA
-805.6mV  7.07mA     53.14mA    7.37mA
-750mV    4.202mA    13.32mA    5.117mA
-694.4mV  3.123mA    4.501mA    3.938mA
-638.9mV  2.331mA    2.347mA    2.958mA
2.75V     -4.594nA   -15.01uA   21.5uA
[Pulldown]
-2.75V    -442uA     -375.6uA   -488.5uA
-1.25V    -2.654mA   -1.807mA   -3.3mA
-1.083V   -5.418mA   -3.009mA   -7.764mA
-916.7mV  -20.1mA    -7.193mA   -30.06mA
-833.3mV  -24.88mA   -12.72mA   -30.75mA
1.083V    22.95mA    14.86mA    30.61mA
3.167V    27.16mA    17.4mA     36.85mA
3.5V      27.37mA    3.87mA     37.14mA
3.75V     11.11mA    1.6mA      37.38mA
3.917V    3.983mA    1.126mA    33.46mA
4.25V     1.511mA    698.6uA    4.924mA
5.5V      426.6uA    283.2uA    642.7uA
[Pullup]
-2.75V    418.2uA    329.2uA    490uA
-1.25V    2.701mA    1.641mA    3.883mA
-833.3mV  21.65mA    11.72mA    27.4mA
1.333V    -25.47mA   -16.64mA   -34.11mA
3.167V    -32.42mA   -19.68mA   -46mA
3.583V    -32.12mA   -2.8mA     -46.81mA
3.667V    -24.56mA   -2.134mA   -46.85mA
3.75V     -11.61mA   -1.713mA   -46.86mA
3.917V    -4.163mA   -1.221mA   -45.5mA
4.083V    -2.401mA   -944uA     -12.97mA
4.25V     -1.668mA   -767.9uA   -4.889mA
5.5V      -494.4uA   -316.6uA   -762.2uA
[GND_clamp]
-2.75V    -17.09A    -17.75A    -16.84A
-1.139V   -1.598A    -2.303A    -1.316A
-1.083V   -1.133A    -1.824A    -861.6mA
-1.028V   -703.6mA   -1.364A    -460mA
-972.2mV  -342.7mA   -934mA     -168.9mA
-916.7mV  -111.4mA   -552.8mA   -46.96mA
-861.1mV  -29.96mA   -256mA     -21.04mA
-805.6mV  -12.97mA   -85.39mA   -13.66mA
-750mV    -7.643mA   -23.86mA   -8.865mA
-694.4mV  -4.465mA   -8.126mA   -5.156mA
-638.9mV  -2.281mA   -3.54mA    -2.523mA
2.75V     61.47uA    63.97uA    92.23uA
[Ramp]
dV/dt_f 0.76490896/2.2505932n  0.4985079/3.4741637n  1.0149655/1.6015463n
dV/dt_r 0.79331765/1.9288512n 0.53579938/3.3552749n  1.0197169/1.2658938n
R_load = 50
[Rising Waveform]
R_fixture = 50
V_fixture = 2.75
V_fixture_min = 2.475
V_fixture_max = 3.025
0s        1.489V     1.655V     1.349V
199.2ps   1.507V     1.657V     1.406V
294.7ps   1.53V      1.664V     1.538V
353.3ps   1.562V     1.668V     1.762V
435.9ps   1.684V     1.674V     2.25V
533.1ps   1.986V     1.691V     2.786V
706.1ps   2.589V     1.821V     3.001V
1.019ns   2.741V     2.345V     3.017V
1.184ns   2.743V     2.454V     3.018V
9.211ns   2.749V     2.474V     3.023V
[Rising Waveform]
R_fixture = 50
V_fixture = 0
V_fixture_min = 0
V_fixture_max = 0
0s        0V         272.2uV    739.5uV
464.9ps   48.64mV    21.96mV    103.6mV
1.208ns   359.8mV    101.5mV    819.6mV
1.889ns   671.7mV    222.1mV    1.319V
2.133ns   774.3mV    269.2mV    1.441V
2.762ns   1.007V     379.4mV    1.601V
3.675ns   1.205V     531.8mV    1.669V
4.686ns   1.282V     676.9mV    1.69V
6.265ns   1.313V     815.2mV    1.698V
9.211ns   1.321V     883.1mV    1.699V
[Falling Waveform]
R_fixture = 50
V_fixture = 2.75
V_fixture_min = 2.475
V_fixture_max = 3.025
0s        2.75V      2.475V     3.024V
266.9ps   2.75V      2.477V     3.033V
447.5ps   2.743V     2.484V     2.947V
1.206ns   2.437V     2.387V     2.32V
1.786ns   2.197V     2.293V     1.931V
2.452ns   1.953V     2.182V     1.639V
2.892ns   1.825V     2.106V     1.527V
4.859ns   1.553V     1.843V     1.371V
6.203ns   1.508V     1.743V     1.355V
9.211ns   1.489V     1.669V     1.348V
[Falling Waveform]
R_fixture = 50
V_fixture = 0
V_fixture_min = 0
V_fixture_max = 0
0s        1.321V     892.7mV    1.699V
193.8ps   1.314V     898.8mV    1.627V
250.8ps   1.266V     895.2mV    1.462V
318.1ps   1.14V      873.2mV    1.13V
415.9ps   836.6mV    792.6mV    613mV
500.8ps   554.8mV    684.7mV    295.2mV
605.9ps   280.8mV    521.4mV    93.43mV
747ps     86.09mV    313mV      16.48mV
1.135ns   3.705mV    34.63mV    2.704mV
9.211ns   1.277uV    35.74uV    0V
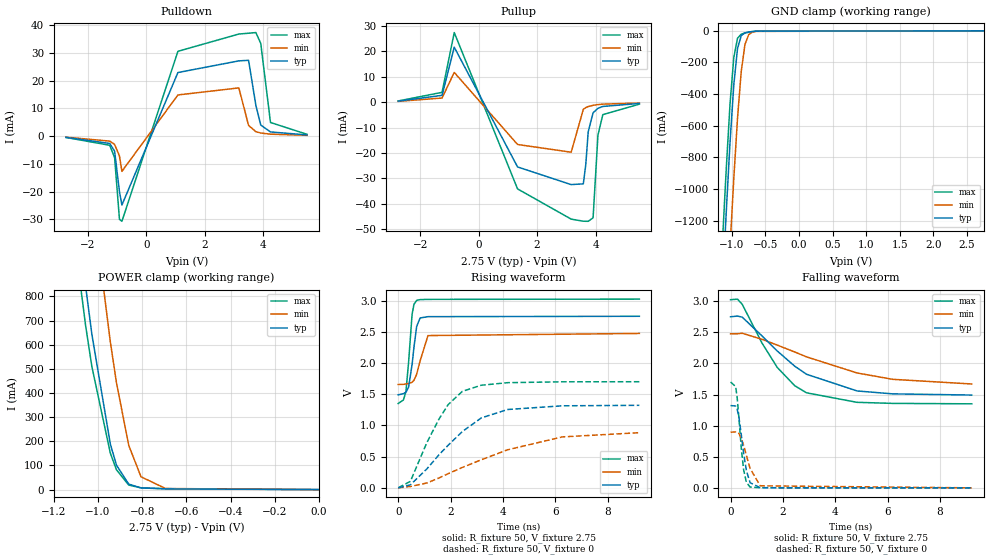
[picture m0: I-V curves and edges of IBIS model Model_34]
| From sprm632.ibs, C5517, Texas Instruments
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| Model based on original model for BC3350CTHYPD
|   Sub model PD_OFF_COM_2P75
[model]   Model_34
|[Description]  [2.75V-I/O-PD_OFF-X, COM]
|   PD_OFF,COM,
|[Input Load]   PD_OFF
|[Output Drive]
|Voltage   2.75V
|Mode   I/O
Model_type   I/O
Polarity   Non-Inverting
Enable   Active-Low
Vinl =  0.7
Vinh =  1.7
Cref =  15.0000pF
Rref =  100.0000M
Vref =  0V
Vmeas =  1.375
C_comp   0.88864286p  0.88152539p   1.2993811p
[Model Spec]
Vinl   0.7   0.7   0.7
Vinh   1.7   1.7   1.7
[Temperature Range]   25   105   -10
[Voltage Range]   2.75   2.475   3.025
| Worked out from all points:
|   slope of the pulldown table from 0 to 0.412 V, typ, clamps not added: 34.2 ohm
|   slope of the pullup table from 0 to 0.412 V, typ, clamps not added: 40.5 ohm
|   GND clamp passes 1 mA (typ) near -0.59 V on its own axis
|   POWER clamp passes 1 mA (typ) near -0.52 V on its own axis
|   rising waveform, R_fixture 50, V_fixture 2.75: 20-80 % time 213ps typ, 290ps min, 174ps max; typ from 1.49 V to 2.75 V
|   rising waveform, R_fixture 50, V_fixture 0: 20-80 % time 1.93ns typ, 3.29ns min, 1.26ns max; typ from 0 V to 1.32 V
|   falling waveform, R_fixture 50, V_fixture 2.75: 20-80 % time 2.23ns typ, 3.34ns min, 1.59ns max; typ from 2.75 V to 1.49 V
|   falling waveform, R_fixture 50, V_fixture 0: 20-80 % time 264ps typ, 390ps min, 210ps max; typ from 1.32 V to 0 V
[POWER_clamp]
-2.75V    16.94A     17.55A     16.71A
-1.167V   1.737A     2.381A     1.512A
-1.139V   1.502A     2.139A     1.286A
-1.111V   1.273A     1.9A       1.07A
-1.056V   840.8mA    1.438A     678.2mA
-1.028V   643.9mA    1.216A     510.1mA
-944.4mV  188.9mA    612.4mA    151mA
-916.7mV  101.5mA    443mA      82.28mA
-861.1mV  22.6mA     183.2mA    18.82mA
-805.6mV  7.009mA    53.11mA    7.278mA
-694.4mV  3.061mA    4.465mA    3.846mA
0V        327.1pA    3.775nA    330.9pA
[Pulldown]
-2.75V    -442uA     -375.6uA   -488.5uA
-1.25V    -2.654mA   -1.807mA   -3.3mA
-1.083V   -5.418mA   -3.009mA   -7.764mA
-916.7mV  -20.1mA    -7.193mA   -30.06mA
-833.3mV  -24.88mA   -12.72mA   -30.75mA
1.083V    22.95mA    14.86mA    30.61mA
3.167V    27.16mA    17.4mA     36.85mA
3.5V      27.37mA    3.87mA     37.14mA
3.75V     11.11mA    1.6mA      37.38mA
3.917V    3.983mA    1.126mA    33.46mA
4.25V     1.511mA    698.6uA    4.923mA
5.5V      426.6uA    283.2uA    642.7uA
[Pullup]
-2.75V    418.2uA    329.2uA    490uA
-1.25V    2.701mA    1.641mA    3.883mA
-833.3mV  21.65mA    11.72mA    27.4mA
1.333V    -25.47mA   -16.64mA   -34.11mA
3.167V    -32.42mA   -19.68mA   -46mA
3.583V    -32.12mA   -2.8mA     -46.82mA
3.667V    -24.56mA   -2.134mA   -46.85mA
3.75V     -11.61mA   -1.713mA   -46.86mA
3.917V    -4.163mA   -1.221mA   -45.5mA
4.083V    -2.401mA   -944uA     -12.97mA
4.25V     -1.668mA   -767.9uA   -4.889mA
5.5V      -494.4uA   -316.6uA   -762.2uA
[GND_clamp]
-2.75V    -17.09A    -17.75A    -16.84A
-1.139V   -1.598A    -2.303A    -1.316A
-1.083V   -1.133A    -1.824A    -861.5mA
-1.028V   -703.5mA   -1.364A    -460mA
-972.2mV  -342.7mA   -934mA     -168.9mA
-916.7mV  -111.3mA   -552.8mA   -46.92mA
-861.1mV  -29.93mA   -256mA     -20.97mA
-805.6mV  -12.93mA   -85.38mA   -13.59mA
-750mV    -7.594mA   -23.85mA   -8.799mA
-694.4mV  -4.418mA   -8.104mA   -5.094mA
-638.9mV  -2.237mA   -3.514mA   -2.466mA
2.75V     327.1pA    28.51uA    -161.6pA
[Ramp]
dV/dt_f 0.76421717/2.2476788n 0.49811059/3.4701056n  1.0142376/1.6008185n
dV/dt_r 0.79443797/1.9262044n 0.53649169/3.3529849n  1.0211504/1.2630748n
R_load = 50
[Rising Waveform]
R_fixture = 50
V_fixture = 2.75
V_fixture_min = 2.475
V_fixture_max = 3.025
0s        1.491V     1.657V     1.352V
199.2ps   1.51V      1.659V     1.409V
294.7ps   1.533V     1.666V     1.542V
396.2ps   1.612V     1.673V     2.013V
529.5ps   1.976V     1.692V     2.778V
601.1ps   2.253V     1.723V     2.942V
704.5ps   2.588V     1.821V     3.005V
836ps     2.723V     2.035V     3.017V
1.137ns   2.744V     2.441V     3.021V
9.211ns   2.75V      2.475V     3.025V
[Rising Waveform]
R_fixture = 50
V_fixture = 0
V_fixture_min = 0
V_fixture_max = 0
0s        0V         270.3uV    736.4uV
464.9ps   48.82mV    22.05mV    104.2mV
1.092ns   302.8mV    78mV       723.9mV
1.559ns   530.6mV    158.6mV    1.104V
1.91ns    684mV      227.4mV    1.335V
2.45ns    902.7mV    327.3mV    1.547V
3.169ns   1.12V      449.4mV    1.645V
4.181ns   1.256V     610.6mV    1.686V
6.265ns   1.315V     816.6mV    1.7V
9.211ns   1.323V     884.3mV    1.701V
[Falling Waveform]
R_fixture = 50
V_fixture = 2.75
V_fixture_min = 2.475
V_fixture_max = 3.025
0s        2.75V      2.476V     3.025V
266.9ps   2.762V     2.478V     3.034V
447.5ps   2.744V     2.485V     2.95V
1.205ns   2.441V     2.388V     2.325V
1.784ns   2.2V       2.295V     1.936V
2.452ns   1.956V     2.184V     1.642V
2.903ns   1.826V     2.106V     1.528V
4.832ns   1.558V     1.847V     1.375V
6.19ns    1.511V     1.745V     1.358V
9.211ns   1.492V     1.67V      1.351V
[Falling Waveform]
R_fixture = 50
V_fixture = 0
V_fixture_min = 0
V_fixture_max = 0
0s        1.323V     893.9mV    1.701V
193.8ps   1.316V     900mV      1.629V
250.8ps   1.268V     896.4mV    1.464V
318.1ps   1.141V     874.3mV    1.129V
415.8ps   836.1mV    793.4mV    608.6mV
500.8ps   552mV      684.8mV    288.6mV
605.5ps   277.2mV    521.1mV    87.81mV
747ps     81.99mV    311mV      12.96mV
1.135ns   2.524mV    32.74mV    1.989mV
9.211ns   1.359uV    36.24uV    0V
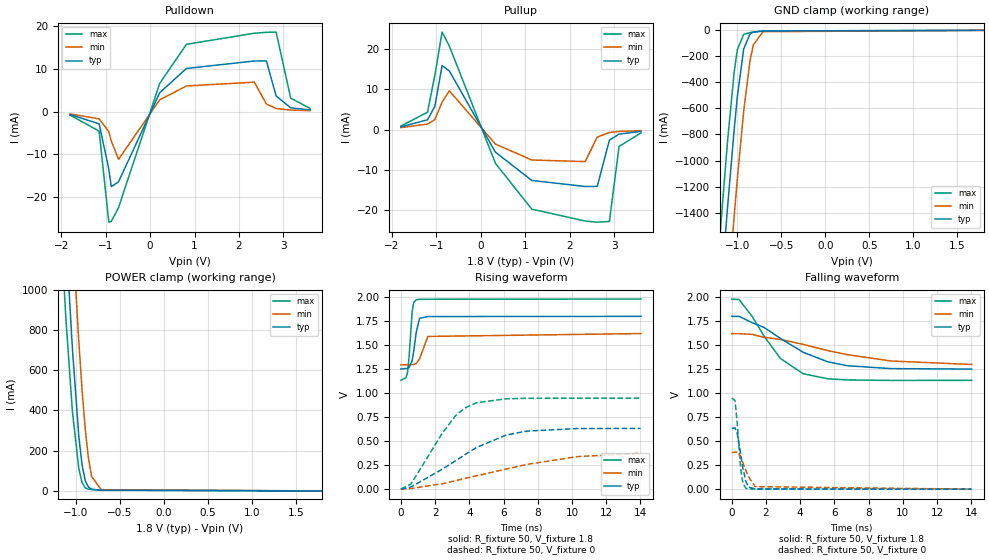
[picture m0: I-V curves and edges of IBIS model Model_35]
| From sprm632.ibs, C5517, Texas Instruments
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| Model based on original model for BC3350CTHYPD
|   Sub model PD_ON_IND_1P8
[model]   Model_35
|[Description]  [1.8V-I/O-PD-X, IND]
|   PD,IND,
|[Input Load]   PD
|[Output Drive]
|Voltage   1.8V
|Mode   I/O
Model_type   I/O
Polarity   Non-Inverting
Enable   Active-Low
Vinl =  0.63
Vinh =  1.17
Cref =  15.0000pF
Rref =  100.0000M
Vref =  0V
Vmeas =  0.9
C_comp   1.505438p   1.4840531p   1.52103p
[Model Spec]
Vinl   0.63   0.567   0.693
Vinh   1.17   1.053   1.287
[Temperature Range]   25   105   -40
[Voltage Range]   1.8   1.62   1.98
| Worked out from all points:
|   slope of the pulldown table from 0 to 0.27 V, typ, clamps not added: 51 ohm
|   slope of the pullup table from 0 to 0.27 V, typ, clamps not added: 57.1 ohm
|   GND clamp passes 1 mA (typ) near -0.58 V on its own axis
|   POWER clamp passes 1 mA (typ) near -0.52 V on its own axis
|   rising waveform, R_fixture 50, V_fixture 1.8: 20-80 % time 262ps typ, 379ps min, 195ps max; typ from 1.25 V to 1.8 V
|   rising waveform, R_fixture 50, V_fixture 0: 20-80 % time 3.48ns typ, 5.71ns min, 2.09ns max; typ from 0.001 V to 0.633 V
|   falling waveform, R_fixture 50, V_fixture 1.8: 20-80 % time 3.24ns typ, 5.09ns min, 2.09ns max; typ from 1.8 V to 1.25 V
|   falling waveform, R_fixture 50, V_fixture 0: 20-80 % time 360ps typ, 553ps min, 249ps max; typ from 0.633 V to 0 V
[POWER_clamp]
-1.8V     7.656A     8.299A     7.195A
-1.182V   1.868A     2.514A     1.416A
-1.145V   1.557A     2.196A     1.122A
-1.109V   1.256A     1.883A     846.6mA
-1.036V   703.1mA    1.284A     392.3mA
-963.6mV  270.2mA    740.6mA    110.3mA
-927.3mV  130.5mA    505.1mA    41.44mA
-890.9mV  51.5mA     307.4mA    15.34mA
-854.5mV  19.14mA    161.4mA    8.678mA
-818.2mV  8.562mA    72.08mA    6.694mA
-709.1mV  3.321mA    5.691mA    4.048mA
1.8V      -3.013nA   -5.095uA   9.776uA
[Pulldown]
-1.8V     -681.9uA   -528.3uA   -794.7uA
-1.145V   -2.848mA   -1.688mA   -4.553mA
-927.3mV  -13.49mA   -4.672mA   -25.91mA
-872.7mV  -17.57mA   -6.855mA   -25.72mA
-709.1mV  -16.44mA   -11.17mA   -22.51mA
218.2mV   4.45mA     2.794mA    6.637mA
818.2mV   10.13mA    6.022mA    15.79mA
2.345V    11.88mA    6.92mA     18.39mA
2.618V    11.89mA    1.797mA    18.61mA
2.836V    3.687mA    752.6uA    18.66mA
3.164V    900.6uA    382.8uA    3.183mA
3.6V      416.6uA    227.7uA    766.1uA
[Pullup]
-1.8V     683.6uA    489.2uA    876.7uA
-1.2V     2.423mA    1.368mA    4.326mA
-1.036V   5.753mA    2.495mA    13.46mA
-872.7mV  15.87mA    6.82mA     24.17mA
-709.1mV  14.53mA    9.611mA    20.69mA
327.3mV   -5.597mA   -3.586mA   -8.356mA
1.145V    -12.6mA    -7.535mA   -19.72mA
2.345V    -14.1mA    -7.933mA   -22.66mA
2.618V    -14.07mA   -1.864mA   -22.95mA
2.891V    -2.623mA   -708.3uA   -22.76mA
3.109V    -1.114mA   -461.7uA   -4.16mA
3.6V      -465.4uA   -255.6uA   -836.2uA
[GND_clamp]
-1.8V     -7.797A    -8.487A    -7.298A
-1.218V   -2.296A    -3.009A    -1.771A
-1.182V   -1.972A    -2.683A    -1.449A
-1.145V   -1.654A    -2.361A    -1.137A
-1.109V   -1.345A    -2.044A    -838.3mA
-1.036V   -766.6mA   -1.434A    -323.5mA
-1V       -511.2mA   -1.144A    -149.1mA
-927.3mV  -142.6mA   -620.4mA   -31.21mA
-854.5mV  -26.42mA   -229.1mA   -16.86mA
-818.2mV  -14.99mA   -112.4mA   -13.08mA
-709.1mV  -5.178mA   -10.46mA   -4.579mA
1.8V      20.41uA    14.91uA    35.18uA
[Ramp]
dV/dt_f 0.33517633/3.2899769n 0.19919084/5.343245n  0.51482225/2.1162412n
dV/dt_r 0.38012486/3.483743n  0.22863027/5.8890356n 0.56893096/2.0917471n
R_load = 50
[Rising Waveform]
R_fixture = 50
V_fixture = 1.8
V_fixture_min = 1.62
V_fixture_max = 1.98
0s        1.251V     1.295V     1.133V
298ps     1.256V     1.295V     1.161V
387.5ps   1.259V     1.296V     1.212V
477ps     1.265V     1.296V     1.368V
661.9ps   1.338V     1.296V     1.852V
753ps     1.437V     1.298V     1.943V
894.7ps   1.629V     1.307V     1.972V
1.091ns   1.779V     1.356V     1.976V
1.575ns   1.797V     1.59V      1.977V
14.03ns   1.799V     1.62V      1.979V
[Rising Waveform]
R_fixture = 50
V_fixture = 0
V_fixture_min = 0
V_fixture_max = 0
0s        658.2uV    354.2uV    946.6uV
588.7ps   22.86mV    7.175mV    53.55mV
2.425ns   209mV      57.05mV    584.1mV
3.194ns   295.3mV    88.92mV    764.7mV
3.742ns   359.3mV    112.1mV    845.3mV
4.421ns   434.2mV    139mV      900.1mV
6.162ns   564mV      210.2mV    941.1mV
7.358ns   604.6mV    258.3mV    946.3mV
10.3ns    631.1mV    339.1mV    947.4mV
14.01ns   632.8mV    373.5mV    947.1mV
[Falling Waveform]
R_fixture = 50
V_fixture = 1.8
V_fixture_min = 1.62
V_fixture_max = 1.98
0s        1.799V     1.619V     1.979V
434.9ps   1.799V     1.619V     1.974V
1.215ns   1.731V     1.611V     1.793V
1.877ns   1.685V     1.581V     1.597V
2.843ns   1.57V      1.559V     1.361V
4.185ns   1.424V     1.507V     1.201V
5.632ns   1.325V     1.442V     1.149V
6.764ns   1.285V     1.4V       1.137V
9.324ns   1.255V     1.334V     1.132V
14.03ns   1.25V      1.298V     1.133V
[Falling Waveform]
R_fixture = 50
V_fixture = 0
V_fixture_min = 0
V_fixture_max = 0
0s        633.2mV    381mV      947.8mV
191.7ps   638.8mV    384.7mV    923.2mV
325ps     580.3mV    384mV      685.8mV
473.6ps   423.7mV    350.3mV    323.3mV
557.4ps   325.3mV    319.4mV    166.1mV
660.6ps   213.7mV    273.7mV    56.97mV
838.5ps   76.07mV    190.3mV    7.804mV
989.6ps   21.73mV    128mV      2.963mV
1.377ns   1.562mV    26.28mV    1.729mV
14.01ns   0V         14.92uV    0V
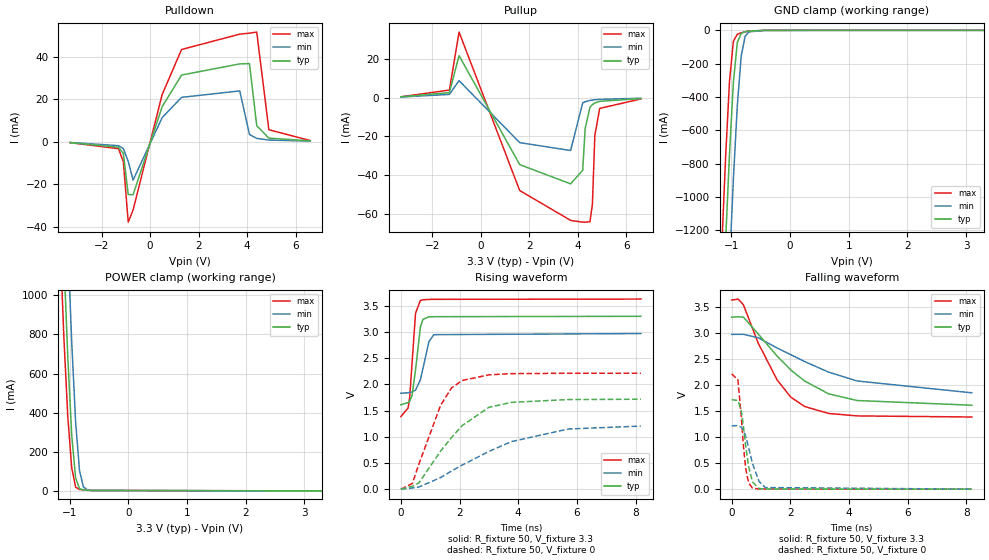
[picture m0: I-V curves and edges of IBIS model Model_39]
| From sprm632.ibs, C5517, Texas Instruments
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| Model based on original model for BC3350CTHYPD
|   Sub model PD_ON_IND_3P3
[model]   Model_39
|[Description]  [3.3V-I/O-PD-X, IND]
|   PD,IND,
|[Input Load]   PD
|[Output Drive]
|Voltage   3.3V
|Mode   I/O
Model_type   I/O
Polarity   Non-Inverting
Enable   Active-Low
Vinl =  0.8
Vinh =  2
Cref =  15.0000pF
Rref =  100.0000M
Vref =  0V
Vmeas =  1.65
C_comp   0.87673039p  0.86952386p   1.2993811p
[Model Spec]
Vinl   0.8   0.8   0.8
Vinh   2   2   2
[Temperature Range]   25   105   -40
[Voltage Range]   3.3   2.97   3.63
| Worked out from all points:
|   slope of the pulldown table from 0 to 0.495 V, typ, clamps not added: 30.2 ohm
|   slope of the pullup table from 0 to 0.495 V, typ, clamps not added: 36.2 ohm
|   GND clamp passes 1 mA (typ) near -0.58 V on its own axis
|   POWER clamp passes 1 mA (typ) near -0.51 V on its own axis
|   rising waveform, R_fixture 50, V_fixture 3.3: 20-80 % time 197ps typ, 267ps min, 157ps max; typ from 1.61 V to 3.3 V
|   rising waveform, R_fixture 50, V_fixture 0: 20-80 % time 1.53ns typ, 2.65ns min, 926ps max; typ from 0.001 V to 1.72 V
|   falling waveform, R_fixture 50, V_fixture 3.3: 20-80 % time 1.91ns typ, 2.88ns min, 1.27ns max; typ from 3.3 V to 1.61 V
|   falling waveform, R_fixture 50, V_fixture 0: 20-80 % time 246ps typ, 352ps min, 190ps max; typ from 1.72 V to 0 V
[POWER_clamp]
-3.3V     22.37A     22.96A     21.96A
-1.167V   1.737A     2.381A     1.292A
-1.1V     1.183A     1.806A     781.9mA
-1.033V   682.1mA    1.26A      376.9mA
-966.7mV  284.5mA    761.6mA    118.3mA
-900mV    65.82mA    352.3mA    19.12mA
-833.3mV  11.6mA     102.7mA    7.434mA
-766.7mV  4.746mA    20.06mA    5.41mA
-700mV    3.243mA    4.908mA    3.989mA
-633.3mV  2.292mA    2.258mA    2.77mA
3.3V      -5.816nA   -29.15uA   34.57uA
[Pulldown]
-3.3V     -379.4uA   -332.5uA   -396.2uA
-1.3V     -2.568mA   -1.838mA   -3.257mA
-1.1V     -5.533mA   -3.228mA   -9.384mA
-900mV    -24.8mA    -9.223mA   -37.83mA
-700mV    -24.92mA   -18.03mA   -32.09mA
500mV     16.51mA    11.37mA    22.25mA
1.3V      31.39mA    20.91mA    43.42mA
3.7V      36.65mA    23.93mA    50.64mA
4.1V      36.79mA    3.426mA    51.12mA
4.4V      7.557mA    1.597mA    51.61mA
4.9V      1.707mA    822.5uA    5.677mA
6.6V      436uA      304.4uA    587.7uA
[Pullup]
-3.3V     352.6uA    285.2uA    400.6uA
-1.3V     2.559mA    1.632mA    3.876mA
-900mV    21.62mA    8.718mA    33.78mA
1.6V      -34.58mA   -23.24mA   -47.95mA
3.7V      -44.51mA   -27.32mA   -63.35mA
4.2V      -37.49mA   -2.71mA    -64.29mA
4.3V      -15.99mA   -2.138mA   -64.26mA
4.5V      -4.997mA   -1.493mA   -64.05mA
4.6V      -3.604mA   -1.294mA   -54.92mA
4.7V      -2.803mA   -1.142mA   -19.49mA
4.9V      -1.928mA   -922.7uA   -5.592mA
6.6V      -515.4uA   -347uA     -695.9uA
[GND_clamp]
-3.3V     -22.52A    -23.16A    -22.07A
-1.167V   -1.839A    -2.548A    -1.318A
-1.1V     -1.269A    -1.966A    -766.5mA
-1.033V   -744.2mA   -1.409A    -306.1mA
-966.7mV  -312.7mA   -893.3mA   -65.59mA
-900mV    -73.59mA   -452.5mA   -23.39mA
-833.3mV  -18.47mA   -154mA     -14.62mA
-766.7mV  -8.896mA   -34.94mA   -8.586mA
-700mV    -4.738mA   -8.896mA   -4.1mA
-433.3mV  -70.41uA   -143.8uA   -58.05uA
3.3V      93.69uA    139.7uA    157.6uA
[Ramp]
dV/dt_f  1.0238676/1.9224735n 0.69144875/2.988505n   1.3572159/1.2708663n
dV/dt_r  1.0304066/1.5353907n 0.72883566/2.684768n   1.3278041/0.92618941n
R_load = 50
[Rising Waveform]
R_fixture = 50
V_fixture = 3.3
V_fixture_min = 2.97
V_fixture_max = 3.63
0s        1.61V      1.83V      1.386V
247.6ps   1.654V     1.839V     1.55V
301.3ps   1.68V      1.846V     1.761V
381.4ps   1.79V      1.856V     2.402V
499.8ps   2.271V     1.889V     3.355V
665.8ps   3.092V     2.088V     3.602V
754.4ps   3.241V     2.304V     3.614V
954.9ps   3.287V     2.813V     3.62V
1.125ns   3.291V     2.948V     3.622V
8.184ns   3.298V     2.969V     3.627V
[Rising Waveform]
R_fixture = 50
V_fixture = 0
V_fixture_min = 0
V_fixture_max = 0
0s        587uV      870.4uV    797.5uV
395ps     55.85mV    23.75mV    110.4mV
612.6ps   118.5mV    42.11mV    475.9mV
1.356ns   728.2mV    221.8mV    1.602V
1.725ns   985.5mV    345.9mV    1.93V
2.091ns   1.213V     460.6mV    2.074V
2.996ns   1.561V     718.2mV    2.181V
3.764ns   1.656V     907.1mV    2.204V
5.703ns   1.71V      1.148V     2.212V
8.184ns   1.716V     1.204V     2.212V
[Falling Waveform]
R_fixture = 50
V_fixture = 3.3
V_fixture_min = 2.97
V_fixture_max = 3.63
0s        3.298V     2.969V     3.627V
219.8ps   3.307V     2.969V     3.646V
398.9ps   3.3V       2.969V     3.538V
901ps     2.978V     2.905V     2.805V
1.548ns   2.553V     2.708V     2.095V
2.019ns   2.283V     2.578V     1.763V
2.488ns   2.074V     2.447V     1.585V
3.302ns   1.829V     2.245V     1.452V
4.274ns   1.7V       2.075V     1.405V
8.184ns   1.61V      1.848V     1.384V
[Falling Waveform]
R_fixture = 50
V_fixture = 0
V_fixture_min = 0
V_fixture_max = 0
0s        1.717V     1.215V     2.213V
213.2ps   1.7V       1.22V      2.092V
327.8ps   1.5V       1.19V      1.389V
401.4ps   1.196V     1.127V     820.5mV
476.9ps   831.7mV    1.014V     403.6mV
577ps     434.6mV    798.4mV    120.5mV
710.4ps   137.7mV    488.3mV    19.34mV
932.8ps   12.43mV    149mV      3.831mV
1.144ns   3.978mV    31.4mV     2.672mV
8.184ns   2.229uV    43.43uV    0V
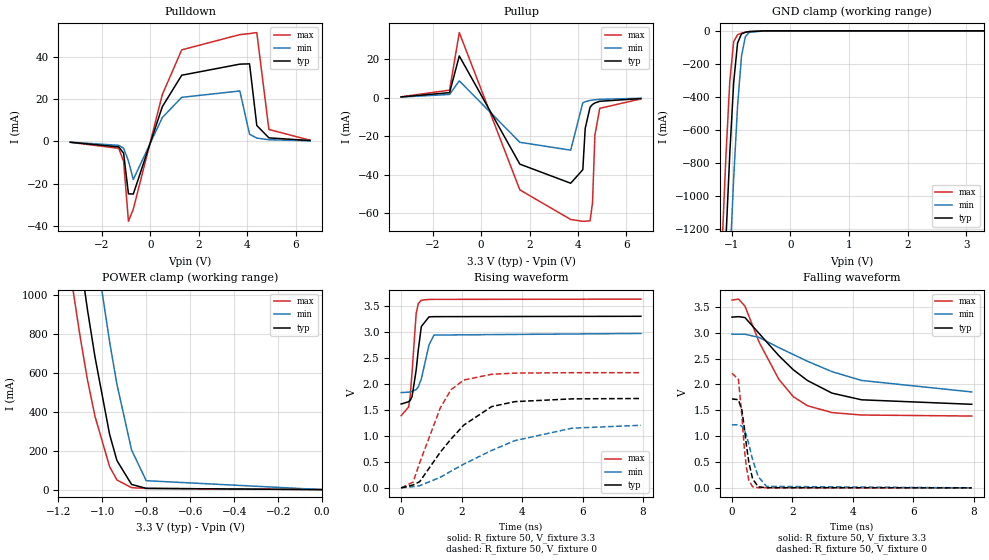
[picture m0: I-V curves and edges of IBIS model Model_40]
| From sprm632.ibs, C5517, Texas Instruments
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| Model based on original model for BC3350CTHYPD
|   Sub model PD_OFF_IND_3P3
[model]   Model_40
|[Description]  [3.3V-I/O-PD_OFF-X, IND]
|   PD_OFF,IND,
|[Input Load]   PD_OFF
|[Output Drive]
|Voltage   3.3V
|Mode   I/O
Model_type   I/O
Polarity   Non-Inverting
Enable   Active-Low
Vinl =  0.8
Vinh =  2
Cref =  15.0000pF
Rref =  100.0000M
Vref =  0V
Vmeas =  1.65
C_comp   0.87673039p  0.86952386p   1.2993811p
[Model Spec]
Vinl   0.8   0.8   0.8
Vinh   2   2   2
[Temperature Range]   25   105   -40
[Voltage Range]   3.3   2.97   3.63
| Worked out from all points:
|   slope of the pulldown table from 0 to 0.495 V, typ, clamps not added: 30.2 ohm
|   slope of the pullup table from 0 to 0.495 V, typ, clamps not added: 36.2 ohm
|   GND clamp passes 1 mA (typ) near -0.58 V on its own axis
|   POWER clamp passes 1 mA (typ) near -0.52 V on its own axis
|   rising waveform, R_fixture 50, V_fixture 3.3: 20-80 % time 199ps typ, 267ps min, 156ps max; typ from 1.61 V to 3.3 V
|   rising waveform, R_fixture 50, V_fixture 0: 20-80 % time 1.53ns typ, 2.64ns min, 923ps max; typ from 0.001 V to 1.72 V
|   falling waveform, R_fixture 50, V_fixture 3.3: 20-80 % time 1.91ns typ, 2.86ns min, 1.27ns max; typ from 3.3 V to 1.61 V
|   falling waveform, R_fixture 50, V_fixture 0: 20-80 % time 244ps typ, 350ps min, 188ps max; typ from 1.72 V to 0 V
[POWER_clamp]
-3.3V     22.37A     22.96A     21.96A
-1.2V     2.026A     2.675A     1.569A
-1.167V   1.737A     2.381A     1.292A
-1.133V   1.455A     2.091A     1.027A
-1.1V     1.183A     1.806A     781.8mA
-1.067V   923.7mA    1.529A     562.8mA
-1.033V   682mA      1.26A      376.8mA
-966.7mV  284.5mA    761.6mA    118.2mA
-933.3mV  149.5mA    542mA      49.47mA
-866.7mV  26.4mA     203.8mA    9.959mA
-800mV    6.466mA    45.92mA    6.091mA
0V        473.5pA    4.973nA    235.8pA
[Pulldown]
-3.3V     -379.4uA   -332.5uA   -396.2uA
-1.3V     -2.568mA   -1.838mA   -3.257mA
-1.1V     -5.533mA   -3.228mA   -9.383mA
-900mV    -24.8mA    -9.223mA   -37.83mA
-700mV    -24.92mA   -18.03mA   -32.09mA
500mV     16.51mA    11.37mA    22.25mA
1.3V      31.39mA    20.91mA    43.42mA
3.7V      36.65mA    23.93mA    50.64mA
4.1V      36.79mA    3.426mA    51.12mA
4.4V      7.557mA    1.597mA    51.61mA
4.9V      1.707mA    822.5uA    5.677mA
6.6V      436uA      304.4uA    587.7uA
[Pullup]
-3.3V     352.6uA    285.2uA    400.6uA
-1.3V     2.559mA    1.632mA    3.875mA
-900mV    21.62mA    8.718mA    33.78mA
1.6V      -34.58mA   -23.24mA   -47.95mA
3.7V      -44.51mA   -27.32mA   -63.35mA
4.2V      -37.49mA   -2.71mA    -64.29mA
4.3V      -15.99mA   -2.138mA   -64.26mA
4.5V      -4.997mA   -1.493mA   -64.05mA
4.6V      -3.604mA   -1.294mA   -54.92mA
4.7V      -2.803mA   -1.142mA   -19.49mA
4.9V      -1.928mA   -922.7uA   -5.592mA
6.6V      -515.4uA   -347uA     -695.9uA
[GND_clamp]
-3.3V     -22.52A    -23.16A    -22.07A
-1.167V   -1.839A    -2.548A    -1.318A
-1.1V     -1.269A    -1.966A    -766.5mA
-1.033V   -744.2mA   -1.409A    -306.1mA
-966.7mV  -312.7mA   -893.3mA   -65.53mA
-900mV    -73.57mA   -452.5mA   -23.29mA
-833.3mV  -18.42mA   -154mA     -14.53mA
-766.7mV  -8.839mA   -34.92mA   -8.499mA
-700mV    -4.683mA   -8.87mA    -4.02mA
-433.3mV  -36.29uA   -120.9uA   -8.285uA
3.3V      473.5pA    85.4uA     158.4pA
[Ramp]
dV/dt_f  1.0230281/1.9212789n 0.69083505/2.9909299n  1.3567499/1.2711499n
dV/dt_r  1.0319633/1.5323931n 0.72983816/2.680399n   1.330014/0.92359747n
R_load = 50
[Rising Waveform]
R_fixture = 50
V_fixture = 3.3
V_fixture_min = 2.97
V_fixture_max = 3.63
0s        1.613V     1.833V     1.389V
247.6ps   1.657V     1.841V     1.556V
301.3ps   1.685V     1.848V     1.769V
360.4ps   1.754V     1.856V     2.223V
497.1ps   2.264V     1.89V      3.355V
566.1ps   2.647V     1.941V     3.542V
667.3ps   3.103V     2.094V     3.609V
922.2ps   3.289V     2.751V     3.624V
1.086ns   3.293V     2.939V     3.625V
7.933ns   3.3V       2.97V      3.63V
[Rising Waveform]
R_fixture = 50
V_fixture = 0
V_fixture_min = 0
V_fixture_max = 0
0s        584.2uV    869.8uV    794.6uV
395.1ps   56.07mV    23.84mV    111mV
613.1ps   119.5mV    42.29mV    482.1mV
1.296ns   687mV      204.3mV    1.54V
1.651ns   940.2mV    322.5mV    1.888V
2.074ns   1.208V     457.5mV    2.075V
2.996ns   1.564V     720.5mV    2.185V
3.764ns   1.659V     908.9mV    2.207V
5.652ns   1.712V     1.148V     2.216V
7.933ns   1.719V     1.204V     2.216V
[Falling Waveform]
R_fixture = 50
V_fixture = 3.3
V_fixture_min = 2.97
V_fixture_max = 3.63
0s        3.3V       2.97V      3.63V
219.8ps   3.309V     2.97V      3.648V
429.4ps   3.292V     2.97V      3.512V
901.1ps   2.982V     2.907V     2.812V
1.548ns   2.557V     2.711V     2.1V
2.026ns   2.284V     2.579V     1.764V
2.497ns   2.075V     2.447V     1.587V
3.31ns    1.831V     2.246V     1.455V
4.288ns   1.702V     2.076V     1.408V
7.933ns   1.615V     1.854V     1.388V
[Falling Waveform]
R_fixture = 50
V_fixture = 0
V_fixture_min = 0
V_fixture_max = 0
0s        1.72V      1.216V     2.216V
213.2ps   1.703V     1.222V     2.096V
327.8ps   1.502V     1.192V     1.389V
408.3ps   1.164V     1.121V     769.5mV
476.9ps   829.2mV    1.015V     395.8mV
558.8ps   491.4mV    841.4mV    145.4mV
682.5ps   173.8mV    546.2mV    21.62mV
867.7ps   20.9mV     216.8mV    3.026mV
1.144ns   2.781mV    29.02mV    2.02mV
7.933ns   3.135uV    51.93uV    0V
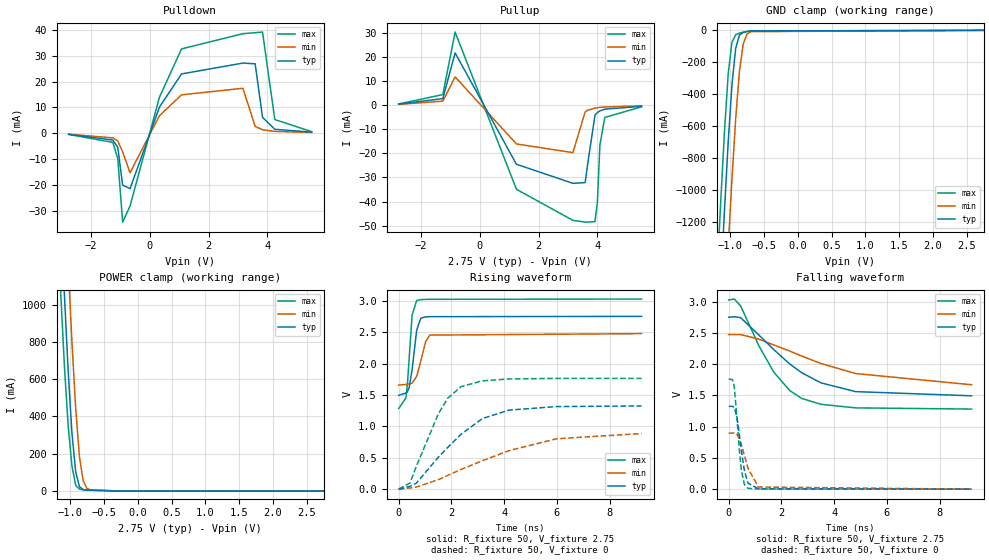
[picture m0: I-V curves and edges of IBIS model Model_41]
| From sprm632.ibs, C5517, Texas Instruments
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| Model based on original model for BC3350CTHYPU
|   Sub model PU_ON_IND_2P75
[model]   Model_41
|[Description]  [2.75V-I/O-PU-X, IND]
|   PU,IND,
|[Input Load]   PU
|[Output Drive]
|Voltage   2.75V
|Mode   I/O
Model_type   I/O
Polarity   Non-Inverting
Enable   Active-Low
Vinl =  0.7
Vinh =  1.7
Cref =  15.0000pF
Rref =  100.0000M
Vref =  0V
Vmeas =  1.375
C_comp   0.88864286p  0.88152539p   1.2993811p
[Model Spec]
Vinl   0.7   0.7   0.7
Vinh   1.7   1.7   1.7
[Temperature Range]   25   105   -40
[Voltage Range]   2.75   2.475   3.025
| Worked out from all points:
|   slope of the pulldown table from 0 to 0.412 V, typ, clamps not added: 34.2 ohm
|   slope of the pullup table from 0 to 0.412 V, typ, clamps not added: 40.5 ohm
|   GND clamp passes 1 mA (typ) near -0.58 V on its own axis
|   POWER clamp passes 1 mA (typ) near -0.52 V on its own axis
|   rising waveform, R_fixture 50, V_fixture 2.75: 20-80 % time 214ps typ, 291ps min, 166ps max; typ from 1.49 V to 2.75 V
|   rising waveform, R_fixture 50, V_fixture 0: 20-80 % time 1.92ns typ, 3.29ns min, 1.14ns max; typ from 0.001 V to 1.32 V
|   falling waveform, R_fixture 50, V_fixture 2.75: 20-80 % time 2.23ns typ, 3.33ns min, 1.48ns max; typ from 2.75 V to 1.49 V
|   falling waveform, R_fixture 50, V_fixture 0: 20-80 % time 264ps typ, 390ps min, 199ps max; typ from 1.32 V to 0.001 V
[POWER_clamp]
-2.75V    16.94A     17.55A     16.52A
-1.139V   1.502A     2.139A     1.07A
-1.083V   1.052A     1.667A     668.7mA
-1.028V   644mA      1.216A     349.4mA
-972.2mV  311.7mA    800.5mA    133.8mA
-916.7mV  101.6mA    443mA      30.47mA
-861.1mV  22.67mA    183.3mA    9.356mA
-805.6mV  7.069mA    53.17mA    6.342mA
-750mV    4.196mA    13.33mA    4.956mA
-694.4mV  3.112mA    4.503mA    3.797mA
-305.6mV  45.84uA    68.42uA    39.8uA
2.75V     -71.61uA   -47.92uA   -113.2uA
[Pulldown]
-2.75V    -442uA     -375.6uA   -474.2uA
-1.25V    -2.654mA   -1.807mA   -3.559mA
-1.083V   -5.418mA   -3.009mA   -9.851mA
-916.7mV  -20.1mA    -7.193mA   -34.46mA
-666.7mV  -21.47mA   -15.31mA   -28.22mA
333.3mV   10.1mA     6.791mA    13.96mA
1.083V    22.95mA    14.86mA    32.66mA
3.167V    27.16mA    17.4mA     38.54mA
3.583V    26.86mA    2.673mA    38.92mA
3.833V    6.162mA    1.323mA    39.16mA
4.25V     1.511mA    698.6uA    5.299mA
5.5V      426.6uA    283.2uA    606.1uA
[Pullup]
-2.75V    418.2uA    329.2uA    487.1uA
-1.25V    2.701mA    1.641mA    4.369mA
-833.3mV  21.65mA    11.72mA    30.28mA
1.25V     -24.52mA   -16.1mA    -34.9mA
3.167V    -32.42mA   -19.68mA   -47.77mA
3.583V    -32.12mA   -2.8mA     -48.5mA
3.667V    -24.56mA   -2.134mA   -48.53mA
3.917V    -4.163mA   -1.221mA   -48.26mA
4V        -3.057mA   -1.065mA   -40.08mA
4.083V    -2.401mA   -944uA     -16.55mA
4.25V     -1.668mA   -767.9uA   -5.094mA
5.5V      -494.4uA   -316.6uA   -710uA
[GND_clamp]
-2.75V    -17.09A    -17.75A    -16.63A
-1.194V   -2.084A    -2.795A    -1.56A
-1.139V   -1.598A    -2.303A    -1.082A
-1.083V   -1.133A    -1.824A    -639.6mA
-1.028V   -703.5mA   -1.364A    -275.3mA
-972.2mV  -342.7mA   -934mA     -74.92mA
-916.7mV  -111.3mA   -552.8mA   -27.5mA
-861.1mV  -29.96mA   -256mA     -17.67mA
-805.6mV  -12.99mA   -85.38mA   -11.94mA
-750mV    -7.662mA   -23.86mA   -7.332mA
-694.4mV  -4.488mA   -8.134mA   -3.843mA
2.75V     323.4pA    41.68uA    -24.39uA
[Ramp]
dV/dt_f 0.76262961/2.2466763n 0.49719902/3.4569395n  1.0553896/1.4855286n
dV/dt_r 0.79494279/1.9257395n 0.53699544/3.3366875n  1.0576048/1.1436477n
R_load = 50
[Rising Waveform]
R_fixture = 50
V_fixture = 2.75
V_fixture_min = 2.475
V_fixture_max = 3.025
0s        1.494V     1.658V     1.284V
274.5ps   1.53V      1.666V     1.453V
329.2ps   1.55V      1.67V      1.657V
396.4ps   1.614V     1.674V     2.073V
509.3ps   1.901V     1.688V     2.769V
682.5ps   2.53V      1.795V     3.002V
836.8ps   2.72V      2.036V     3.017V
1.02ns    2.742V     2.345V     3.02V
1.178ns   2.745V     2.452V     3.021V
9.211ns   2.75V      2.475V     3.025V
[Rising Waveform]
R_fixture = 50
V_fixture = 0
V_fixture_min = 0
V_fixture_max = 0
0s        1.274mV    1.299mV    2.456mV
428.7ps   46.71mV    20.65mV    98.36mV
663.9ps   94.31mV    34.46mV    358.9mV
1.507ns   510.7mV    152mV      1.202V
1.863ns   667.7mV    220.9mV    1.45V
2.366ns   874mV      315.2mV    1.632V
3.168ns   1.123V     451.9mV    1.724V
4.182ns   1.259V     613.5mV    1.754V
5.991ns   1.315V     802.9mV    1.763V
9.211ns   1.325V     886.9mV    1.763V
[Falling Waveform]
R_fixture = 50
V_fixture = 2.75
V_fixture_min = 2.475
V_fixture_max = 3.025
0s        2.75V      2.474V     3.026V
216.5ps   2.758V     2.474V     3.041V
453.1ps   2.743V     2.474V     2.932V
1.139ns   2.469V     2.4V       2.299V
1.716ns   2.231V     2.306V     1.868V
2.321ns   2V         2.208V     1.576V
2.774ns   1.862V     2.129V     1.452V
3.5ns     1.701V     2.01V      1.358V
4.814ns   1.561V     1.85V      1.301V
9.211ns   1.494V     1.671V     1.282V
[Falling Waveform]
R_fixture = 50
V_fixture = 0
V_fixture_min = 0
V_fixture_max = 0
0s        1.325V     895.7mV    1.764V
144.4ps   1.325V     897.8mV    1.752V
210.6ps   1.309V     902mV      1.642V
318.9ps   1.143V     876.1mV    1.12V
413.6ps   848.9mV    798.2mV    580.4mV
486.1ps   602.8mV    707.3mV    290.9mV
596.2ps   300.9mV    538.5mV    76.06mV
731.6ps   97.04mV    334.8mV    14.4mV
1.133ns   5.107mV    35.08mV    4.414mV
9.211ns   1.301mV    1.069mV    1.664mV
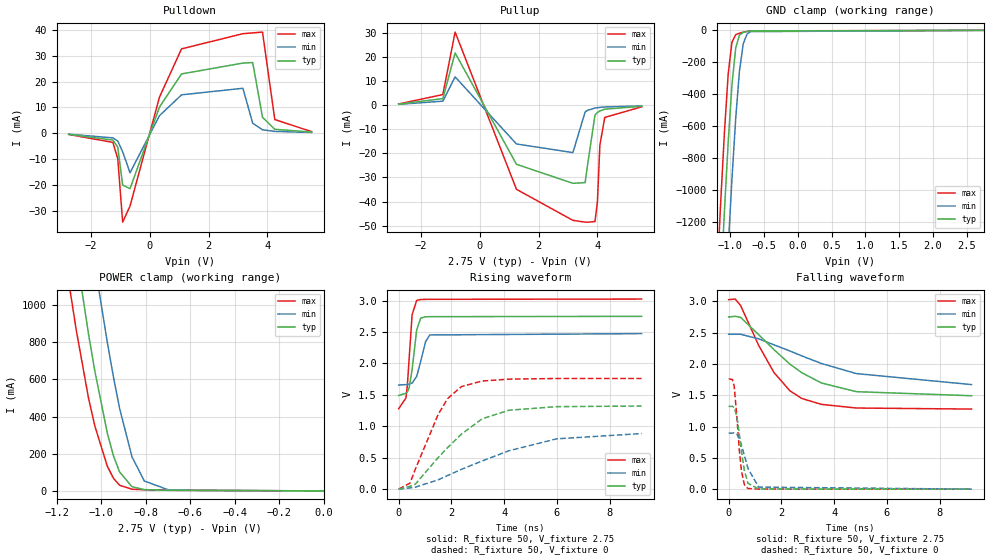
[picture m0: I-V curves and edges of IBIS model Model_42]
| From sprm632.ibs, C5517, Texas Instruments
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| Model based on original model for BC3350CTHYPU
|   Sub model PU_OFF_IND_2P75
[model]   Model_42
|[Description]  [2.75V-I/O-PU_OFF-X, IND]
|   PU_OFF,IND,
|[Input Load]   PU_OFF
|[Output Drive]
|Voltage   2.75V
|Mode   I/O
Model_type   I/O
Polarity   Non-Inverting
Enable   Active-Low
Vinl =  0.7
Vinh =  1.7
Cref =  15.0000pF
Rref =  100.0000M
Vref =  0V
Vmeas =  1.375
C_comp   0.88864286p  0.88152539p   1.2993811p
[Model Spec]
Vinl   0.7   0.7   0.7
Vinh   1.7   1.7   1.7
[Temperature Range]   25   105   -40
[Voltage Range]   2.75   2.475   3.025
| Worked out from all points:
|   slope of the pulldown table from 0 to 0.412 V, typ, clamps not added: 34.2 ohm
|   slope of the pullup table from 0 to 0.412 V, typ, clamps not added: 40.5 ohm
|   GND clamp passes 1 mA (typ) near -0.59 V on its own axis
|   POWER clamp passes 1 mA (typ) near -0.52 V on its own axis
|   rising waveform, R_fixture 50, V_fixture 2.75: 20-80 % time 213ps typ, 290ps min, 165ps max; typ from 1.49 V to 2.75 V
|   rising waveform, R_fixture 50, V_fixture 0: 20-80 % time 1.92ns typ, 3.28ns min, 1.14ns max; typ from 0 V to 1.32 V
|   falling waveform, R_fixture 50, V_fixture 2.75: 20-80 % time 2.23ns typ, 3.33ns min, 1.48ns max; typ from 2.75 V to 1.49 V
|   falling waveform, R_fixture 50, V_fixture 0: 20-80 % time 264ps typ, 390ps min, 199ps max; typ from 1.32 V to 0 V
[POWER_clamp]
-2.75V    16.94A     17.55A     16.52A
-1.167V   1.737A     2.381A     1.292A
-1.111V   1.273A     1.9A       861.3mA
-1.056V   840.9mA    1.438A     496.9mA
-1.028V   643.9mA    1.216A     349.4mA
-972.2mV  311.7mA    800.5mA    133.7mA
-944.4mV  188.9mA    612.4mA    67.71mA
-916.7mV  101.6mA    443mA      30.4mA
-861.1mV  22.63mA    183.3mA    9.269mA
-805.6mV  7.021mA    53.15mA    6.259mA
-694.4mV  3.064mA    4.48mA     3.726mA
0V        324.3pA    3.771nA    185.1pA
[Pulldown]
-2.75V    -442uA     -375.6uA   -474.2uA
-1.25V    -2.654mA   -1.807mA   -3.559mA
-1.083V   -5.417mA   -3.008mA   -9.85mA
-916.7mV  -20.1mA    -7.193mA   -34.46mA
-666.7mV  -21.47mA   -15.31mA   -28.22mA
333.3mV   10.1mA     6.791mA    13.96mA
1.083V    22.95mA    14.86mA    32.66mA
3.167V    27.16mA    17.4mA     38.54mA
3.5V      27.37mA    3.87mA     38.84mA
3.833V    6.162mA    1.323mA    39.16mA
4.25V     1.511mA    698.6uA    5.299mA
5.5V      426.6uA    283.2uA    606.1uA
[Pullup]
-2.75V    418.2uA    329.2uA    487.1uA
-1.25V    2.701mA    1.641mA    4.369mA
-833.3mV  21.65mA    11.72mA    30.28mA
1.25V     -24.52mA   -16.1mA    -34.9mA
3.167V    -32.42mA   -19.68mA   -47.77mA
3.583V    -32.12mA   -2.8mA     -48.5mA
3.667V    -24.56mA   -2.134mA   -48.53mA
3.917V    -4.162mA   -1.221mA   -48.26mA
4V        -3.056mA   -1.065mA   -40.08mA
4.083V    -2.401mA   -944uA     -16.55mA
4.25V     -1.668mA   -767.8uA   -5.094mA
5.5V      -494.4uA   -316.6uA   -710uA
[GND_clamp]
-2.75V    -17.09A    -17.75A    -16.63A
-1.194V   -2.084A    -2.795A    -1.56A
-1.139V   -1.598A    -2.303A    -1.082A
-1.083V   -1.133A    -1.824A    -639.5mA
-1.028V   -703.5mA   -1.364A    -275.3mA
-972.2mV  -342.7mA   -934mA     -74.83mA
-916.7mV  -111.3mA   -552.8mA   -27.39mA
-861.1mV  -29.9mA    -256mA     -17.56mA
-805.6mV  -12.91mA   -85.34mA   -11.83mA
-750mV    -7.591mA   -23.82mA   -7.219mA
-694.4mV  -4.417mA   -8.09mA    -3.73mA
2.75V     324.3pA    28.52uA    120.6pA
[Ramp]
dV/dt_f 0.76423614/2.2478809n 0.49806322/3.4579615n  1.0576891/1.484114n
dV/dt_r 0.79443749/1.9246797n 0.53651305/3.3343581n  1.0572106/1.1415922n
R_load = 50
[Rising Waveform]
R_fixture = 50
V_fixture = 2.75
V_fixture_min = 2.475
V_fixture_max = 3.025
0s        1.491V     1.657V     1.28V
274.5ps   1.527V     1.664V     1.45V
329.2ps   1.548V     1.668V     1.654V
396.4ps   1.612V     1.673V     2.073V
509.7ps   1.902V     1.687V     2.776V
683.3ps   2.536V     1.795V     3.005V
836.8ps   2.723V     2.036V     3.018V
1.02ns    2.743V     2.347V     3.02V
1.179ns   2.745V     2.454V     3.021V
9.211ns   2.75V      2.475V     3.025V
[Rising Waveform]
R_fixture = 50
V_fixture = 0
V_fixture_min = 0
V_fixture_max = 0
0s        0V         274.4uV    790.5uV
428.7ps   45.33mV    19.63mV    95.7mV
632.6ps   80.03mV    31.82mV    319.1mV
1.499ns   503.6mV    148.3mV    1.191V
1.851ns   659.1mV    216.2mV    1.439V
2.377ns   875.1mV    314.9mV    1.632V
3.166ns   1.12V      449.3mV    1.721V
4.177ns   1.256V     610.7mV    1.751V
5.99ns    1.313V     800.9mV    1.761V
9.211ns   1.323V     885mV      1.761V
[Falling Waveform]
R_fixture = 50
V_fixture = 2.75
V_fixture_min = 2.475
V_fixture_max = 3.025
0s        2.75V      2.474V     3.026V
250.8ps   2.761V     2.474V     3.036V
453.1ps   2.743V     2.474V     2.932V
1.139ns   2.467V     2.4V       2.295V
1.717ns   2.229V     2.305V     1.863V
2.322ns   1.997V     2.207V     1.571V
2.776ns   1.859V     2.128V     1.448V
3.516ns   1.696V     2.007V     1.354V
4.841ns   1.557V     1.846V     1.296V
9.211ns   1.492V     1.67V      1.279V
[Falling Waveform]
R_fixture = 50
V_fixture = 0
V_fixture_min = 0
V_fixture_max = 0
0s        1.322V     893.9mV    1.762V
144.4ps   1.322V     896mV      1.75V
210.6ps   1.307V     900.2mV    1.639V
318.9ps   1.139V     874.2mV    1.113V
402.3ps   883.2mV    808.2mV    628.9mV
484.8ps   602.7mV    706.8mV    289.4mV
595ps     299.9mV    538mV      72.72mV
731.2ps   94.22mV    333mV      10.44mV
1.133ns   2.548mV    33.1mV     1.883mV
9.211ns   1.36uV     36.34uV    0V
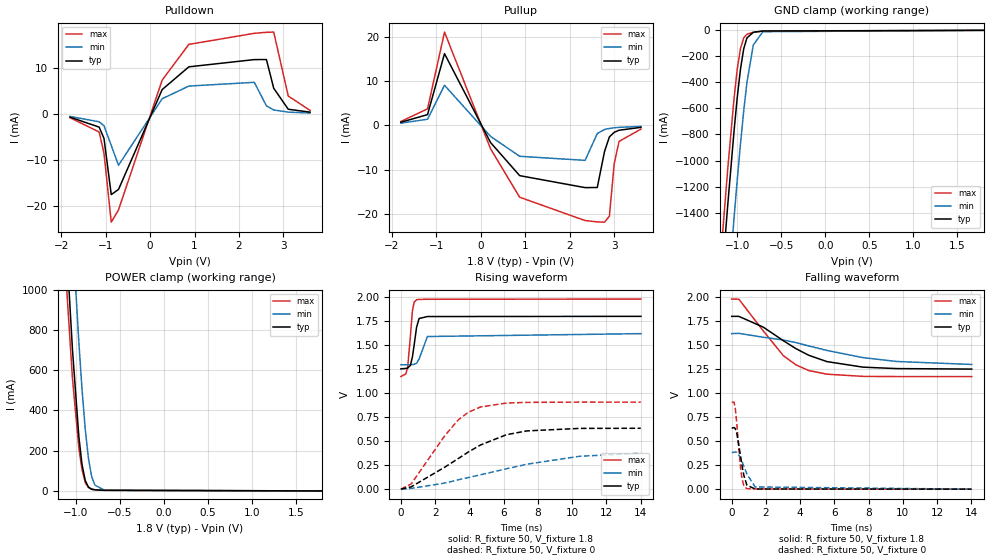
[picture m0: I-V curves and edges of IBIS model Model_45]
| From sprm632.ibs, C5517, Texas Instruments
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| Model based on original model for BC3350CTHYPU
|   Sub model PU_ON_COM_1P8
[model]   Model_45
|[Description]  [1.8V-I/O-PU-X, COM]
|   PU,COM,
|[Input Load]   PU
|[Output Drive]
|Voltage   1.8V
|Mode   I/O
Model_type   I/O
Polarity   Non-Inverting
Enable   Active-Low
Vinl =  0.63
Vinh =  1.17
Cref =  15.0000pF
Rref =  100.0000M
Vref =  0V
Vmeas =  0.9
C_comp   1.5053119p   1.48392p   1.520888p
[Model Spec]
Vinl   0.63   0.567   0.693
Vinh   1.17   1.053   1.287
[Temperature Range]   25   105   -10
[Voltage Range]   1.8   1.62   1.98
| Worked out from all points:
|   slope of the pulldown table from 0 to 0.27 V, typ, clamps not added: 51 ohm
|   slope of the pullup table from 0 to 0.27 V, typ, clamps not added: 57.1 ohm
|   GND clamp passes 1 mA (typ) near -0.58 V on its own axis
|   POWER clamp passes 1 mA (typ) near -0.52 V on its own axis
|   rising waveform, R_fixture 50, V_fixture 1.8: 20-80 % time 263ps typ, 380ps min, 210ps max; typ from 1.25 V to 1.8 V
|   rising waveform, R_fixture 50, V_fixture 0: 20-80 % time 3.48ns typ, 5.72ns min, 2.28ns max; typ from 0.001 V to 0.635 V
|   falling waveform, R_fixture 50, V_fixture 1.8: 20-80 % time 3.23ns typ, 5.05ns min, 2.27ns max; typ from 1.8 V to 1.25 V
|   falling waveform, R_fixture 50, V_fixture 0: 20-80 % time 358ps typ, 552ps min, 266ps max; typ from 0.635 V to 0.001 V
[POWER_clamp]
-1.8V     7.656A     8.299A     7.406A
-1.145V   1.557A     2.196A     1.339A
-1.109V   1.256A     1.883A     1.055A
-1.036V   703.1mA    1.284A     559.8mA
-963.6mV  270.2mA    740.7mA    213.7mA
-927.3mV  130.5mA    505.1mA    105.4mA
-890.9mV  51.54mA    307.4mA    41.92mA
-854.5mV  19.17mA    161.5mA    16.22mA
-818.2mV  8.589mA    72.12mA    8.429mA
-781.8mV  5.336mA    29.22mA    6.065mA
-672.7mV  2.77mA     3.327mA    3.493mA
1.8V      -27.44uA   -17.12uA   -40.43uA
[Pulldown]
-1.8V     -681.9uA   -528.3uA   -799.6uA
-1.145V   -2.848mA   -1.688mA   -3.914mA
-1.036V   -5.317mA   -2.553mA   -8.566mA
-872.7mV  -17.57mA   -6.855mA   -23.59mA
-709.1mV  -16.44mA   -11.17mA   -20.89mA
272.7mV   5.341mA    3.341mA    7.405mA
872.7mV   10.3mA     6.104mA    15.2mA
2.345V    11.88mA    6.92mA     17.61mA
2.618V    11.89mA    1.797mA    17.83mA
2.782V    5.623mA    889uA      17.88mA
3.109V    1.046mA    417.7uA    3.932mA
3.6V      416.6uA    227.7uA    789.5uA
[Pullup]
-1.8V     683.6uA    489.3uA    862.2uA
-1.2V     2.424mA    1.368mA    3.724mA
-818.2mV  16.21mA    9.062mA    21.09mA
218.2mV   -3.905mA   -2.516mA   -5.325mA
872.7mV   -11.39mA   -7.011mA   -16.27mA
2.345V    -14.1mA    -7.933mA   -21.55mA
2.618V    -14.07mA   -1.864mA   -21.85mA
2.782V    -5.913mA   -955.1uA   -21.92mA
2.891V    -2.623mA   -708.3uA   -20.54mA
3V        -1.582mA   -559.9uA   -8.606mA
3.109V    -1.114mA   -461.7uA   -3.639mA
3.6V      -465.4uA   -255.6uA   -860.2uA
[GND_clamp]
-1.8V     -7.797A    -8.487A    -7.522A
-1.182V   -1.972A    -2.683A    -1.687A
-1.145V   -1.654A    -2.361A    -1.372A
-1.109V   -1.345A    -2.044A    -1.068A
-1.036V   -766.6mA   -1.434A    -516.9mA
-1V       -511.1mA   -1.144A    -294.9mA
-963.6mV  -296.8mA   -871.2mA   -139.2mA
-927.3mV  -142.6mA   -620.3mA   -58.93mA
-890.9mV  -58.93mA   -401.7mA   -29.73mA
-818.2mV  -14.97mA   -112.4mA   -14.93mA
-709.1mV  -5.172mA   -10.44mA   -6.008mA
1.8V      168.4pA    9.027uA    -9.797uA
[Ramp]
dV/dt_f 0.33449129/3.2861427n 0.19892922/5.3027978n  0.4910443/2.3030738n
dV/dt_r 0.38093115/3.4873213n 0.22904029/5.8766685n 0.54421786/2.2808819n
R_load = 50
[Rising Waveform]
R_fixture = 50
V_fixture = 1.8
V_fixture_min = 1.62
V_fixture_max = 1.98
0s        1.253V     1.296V     1.174V
292.3ps   1.258V     1.296V     1.201V
395.3ps   1.262V     1.297V     1.265V
557.3ps   1.289V     1.297V     1.596V
675.3ps   1.378V     1.298V     1.86V
775.7ps   1.501V     1.3V       1.947V
917.4ps   1.686V     1.313V     1.973V
1.066ns   1.778V     1.356V     1.976V
1.55ns    1.798V     1.59V      1.978V
14.02ns   1.8V       1.62V      1.98V
[Rising Waveform]
R_fixture = 50
V_fixture = 0
V_fixture_min = 0
V_fixture_max = 0
0s        1.3mV      840.8uV    1.618mV
599.6ps   24.98mV    8.606mV    54.39mV
2.561ns   229.5mV    64.37mV    556.7mV
3.347ns   318.8mV    98mV       721.1mV
3.929ns   386.4mV    122mV      800.7mV
4.656ns   461.2mV    150.6mV    857mV
6.162ns   567.7mV    212.8mV    897.2mV
7.357ns   607.4mV    260.6mV    904.4mV
10.43ns   633.4mV    343.2mV    907.1mV
14.01ns   634.8mV    374.7mV    906.8mV
[Falling Waveform]
R_fixture = 50
V_fixture = 1.8
V_fixture_min = 1.62
V_fixture_max = 1.98
0s        1.8V       1.62V      1.98V
415.2ps   1.8V       1.623V     1.979V
1.85ns    1.687V     1.582V     1.647V
3.021ns   1.546V     1.554V     1.39V
3.759ns   1.463V     1.526V     1.294V
4.497ns   1.395V     1.492V     1.236V
5.556ns   1.329V     1.445V     1.198V
7.669ns   1.271V     1.37V      1.175V
9.633ns   1.256V     1.33V      1.173V
14.02ns   1.251V     1.299V     1.173V
[Falling Waveform]
R_fixture = 50
V_fixture = 0
V_fixture_min = 0
V_fixture_max = 0
0s        635.1mV    382.2mV    906.8mV
131.1ps   641.7mV    383.8mV    906.8mV
206.4ps   632.5mV    387.7mV    846.6mV
299.4ps   581.9mV    385.5mV    680.8mV
503.8ps   357.7mV    332.4mV    243.2mV
605.1ps   243.1mV    288.4mV    105.8mV
718.9ps   138.1mV    234.2mV    31.21mV
887.4ps   41.87mV    158.3mV    5.377mV
1.37ns    2.193mV    23.63mV    2.765mV
14.01ns   624.8uV    496.3uV    771.3uV
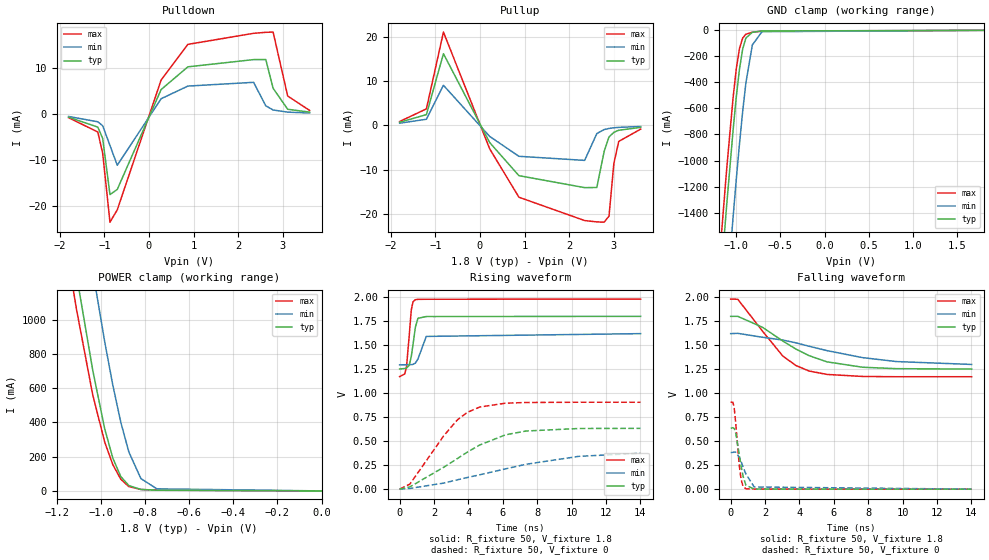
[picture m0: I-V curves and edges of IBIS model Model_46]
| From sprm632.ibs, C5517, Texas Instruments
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| Model based on original model for BC3350CTHYPU
|   Sub model PU_OFF_COM_1P8
[model]   Model_46
|[Description]  [1.8V-I/O-PU_OFF-X, COM]
|   PU_OFF,COM,
|[Input Load]   PU_OFF
|[Output Drive]
|Voltage   1.8V
|Mode   I/O
Model_type   I/O
Polarity   Non-Inverting
Enable   Active-Low
Vinl =  0.63
Vinh =  1.17
Cref =  15.0000pF
Rref =  100.0000M
Vref =  0V
Vmeas =  0.9
C_comp   1.5053119p   1.48392p   1.520888p
[Model Spec]
Vinl   0.63   0.567   0.693
Vinh   1.17   1.053   1.287
[Temperature Range]   25   105   -10
[Voltage Range]   1.8   1.62   1.98
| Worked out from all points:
|   slope of the pulldown table from 0 to 0.27 V, typ, clamps not added: 51 ohm
|   slope of the pullup table from 0 to 0.27 V, typ, clamps not added: 57.1 ohm
|   GND clamp passes 1 mA (typ) near -0.59 V on its own axis
|   POWER clamp passes 1 mA (typ) near -0.52 V on its own axis
|   rising waveform, R_fixture 50, V_fixture 1.8: 20-80 % time 262ps typ, 379ps min, 208ps max; typ from 1.25 V to 1.8 V
|   rising waveform, R_fixture 50, V_fixture 0: 20-80 % time 3.48ns typ, 5.72ns min, 2.28ns max; typ from 0.001 V to 0.634 V
|   falling waveform, R_fixture 50, V_fixture 1.8: 20-80 % time 3.23ns typ, 5.05ns min, 2.28ns max; typ from 1.8 V to 1.25 V
|   falling waveform, R_fixture 50, V_fixture 0: 20-80 % time 357ps typ, 552ps min, 266ps max; typ from 0.634 V to 0 V
[POWER_clamp]
-1.8V     7.656A     8.299A     7.406A
-1.145V   1.557A     2.196A     1.339A
-1.127V   1.405A     2.039A     1.195A
-1.109V   1.256A     1.883A     1.055A
-1.036V   703.1mA    1.284A     559.8mA
-981.8mV  361.6mA    868.9mA    284.1mA
-945.5mV  192.8mA    618.9mA    154.1mA
-909.1mV  83.69mA    400.6mA    67.95mA
-872.7mV  31.23mA    227.4mA    25.58mA
-818.2mV  8.557mA    72.11mA    8.377mA
-745.5mV  4.035mA    12.08mA    4.919mA
0V        168.8pA    2.305nA    149.6pA
[Pulldown]
-1.8V     -681.9uA   -528.3uA   -799.6uA
-1.145V   -2.847mA   -1.688mA   -3.914mA
-1.036V   -5.317mA   -2.553mA   -8.566mA
-872.7mV  -17.57mA   -6.855mA   -23.59mA
-709.1mV  -16.44mA   -11.17mA   -20.89mA
272.7mV   5.341mA    3.341mA    7.405mA
872.7mV   10.3mA     6.104mA    15.2mA
2.345V    11.88mA    6.92mA     17.61mA
2.618V    11.89mA    1.797mA    17.83mA
2.782V    5.623mA    889uA      17.88mA
3.109V    1.046mA    417.7uA    3.932mA
3.6V      416.6uA    227.7uA    789.5uA
[Pullup]
-1.8V     683.6uA    489.3uA    862.2uA
-1.2V     2.424mA    1.368mA    3.724mA
-818.2mV  16.21mA    9.062mA    21.1mA
218.2mV   -3.905mA   -2.516mA   -5.325mA
872.7mV   -11.39mA   -7.011mA   -16.27mA
2.345V    -14.1mA    -7.933mA   -21.55mA
2.618V    -14.07mA   -1.864mA   -21.85mA
2.782V    -5.913mA   -955.1uA   -21.92mA
2.891V    -2.623mA   -708.3uA   -20.54mA
3V        -1.582mA   -559.9uA   -8.605mA
3.109V    -1.114mA   -461.7uA   -3.639mA
3.6V      -465.4uA   -255.6uA   -860.2uA
[GND_clamp]
-1.8V     -7.797A    -8.487A    -7.522A
-1.182V   -1.972A    -2.683A    -1.687A
-1.145V   -1.654A    -2.361A    -1.372A
-1.109V   -1.345A    -2.044A    -1.068A
-1.036V   -766.6mA   -1.434A    -516.9mA
-1V       -511.1mA   -1.144A    -294.9mA
-963.6mV  -296.8mA   -871.2mA   -139.1mA
-927.3mV  -142.6mA   -620.3mA   -58.9mA
-890.9mV  -58.91mA   -401.7mA   -29.69mA
-818.2mV  -14.95mA   -112.3mA   -14.89mA
-709.1mV  -5.144mA   -10.43mA   -5.968mA
1.8V      168.8pA    3.273uA    -261.9pA
[Ramp]
dV/dt_f 0.33495331/3.2867931n  0.1991855/5.3016804n 0.49198272/2.30544n
dV/dt_r 0.38058039/3.4842135n 0.22884158/5.8716399n 0.54383587/2.2798211n
R_load = 50
[Rising Waveform]
R_fixture = 50
V_fixture = 1.8
V_fixture_min = 1.62
V_fixture_max = 1.98
0s        1.252V     1.295V     1.172V
292.3ps   1.257V     1.296V     1.2V
395.3ps   1.261V     1.296V     1.264V
557.3ps   1.289V     1.297V     1.597V
675.3ps   1.378V     1.297V     1.863V
775.8ps   1.502V     1.3V       1.95V
917.4ps   1.687V     1.313V     1.974V
1.066ns   1.78V      1.356V     1.977V
1.55ns    1.798V     1.591V     1.978V
14.02ns   1.8V       1.62V      1.98V
[Rising Waveform]
R_fixture = 50
V_fixture = 0
V_fixture_min = 0
V_fixture_max = 0
0s        674uV      361uV      845.3uV
599.7ps   24.33mV    8.128mV    53.2mV
2.561ns   228.2mV    63.53mV    554.9mV
3.346ns   317.5mV    97.16mV    719.4mV
3.928ns   385.1mV    121.2mV    799.1mV
4.656ns   460mV      149.8mV    855.5mV
6.162ns   566.5mV    211.9mV    895.8mV
7.356ns   606.1mV    259.8mV    902.9mV
10.43ns   632.2mV    342.3mV    905.7mV
14.01ns   633.6mV    373.9mV    905.4mV
[Falling Waveform]
R_fixture = 50
V_fixture = 1.8
V_fixture_min = 1.62
V_fixture_max = 1.98
0s        1.8V       1.62V      1.98V
415.2ps   1.8V       1.623V     1.978V
1.85ns    1.686V     1.582V     1.646V
3.036ns   1.543V     1.553V     1.386V
3.795ns   1.459V     1.524V     1.288V
4.554ns   1.391V     1.489V     1.231V
5.603ns   1.326V     1.443V     1.195V
7.673ns   1.27V      1.37V      1.174V
9.64ns    1.255V     1.329V     1.171V
14.02ns   1.251V     1.299V     1.171V
[Falling Waveform]
R_fixture = 50
V_fixture = 0
V_fixture_min = 0
V_fixture_max = 0
0s        633.9mV    381.4mV    905.4mV
131.1ps   640.5mV    383mV      905.4mV
206.4ps   631.3mV    386.9mV    844.9mV
299.4ps   580.6mV    384.7mV    678.4mV
503.8ps   356.3mV    331.5mV    241.2mV
605.1ps   241.8mV    287.6mV    104mV
718.9ps   136.8mV    233.4mV    29.5mV
887.4ps   40.63mV    157.5mV    3.716mV
1.37ns    1.02mV     22.84mV    1.349mV
14.01ns   0V         13.87uV    0V
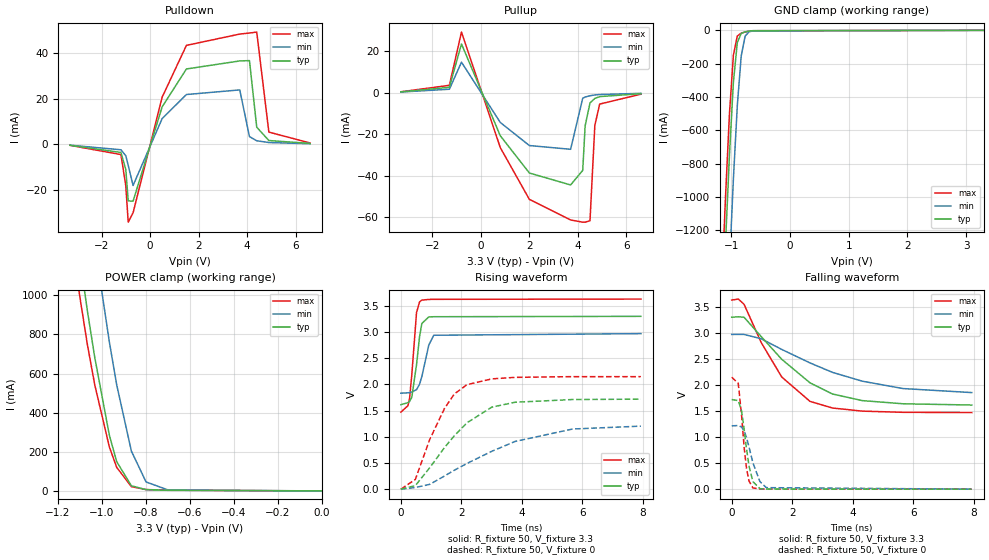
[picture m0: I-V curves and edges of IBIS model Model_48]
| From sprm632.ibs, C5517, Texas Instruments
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| Model based on original model for BC3350CTHYPU
|   Sub model PU_OFF_COM_3P3
[model]   Model_48
|[Description]  [3.3V-I/O-PU_OFF-X, COM]
|   PU_OFF,COM,
|[Input Load]   PU_OFF
|[Output Drive]
|Voltage   3.3V
|Mode   I/O
Model_type   I/O
Polarity   Non-Inverting
Enable   Active-Low
Vinl =  0.8
Vinh =  2
Cref =  15.0000pF
Rref =  100.0000M
Vref =  0V
Vmeas =  1.65
C_comp   0.87673039p  0.86952386p   1.2993811p
[Model Spec]
Vinl   0.8   0.8   0.8
Vinh   2   2   2
[Temperature Range]   25   105   -10
[Voltage Range]   3.3   2.97   3.63
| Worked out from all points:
|   slope of the pulldown table from 0 to 0.495 V, typ, clamps not added: 30.2 ohm
|   slope of the pullup table from 0 to 0.495 V, typ, clamps not added: 36.2 ohm
|   GND clamp passes 1 mA (typ) near -0.58 V on its own axis
|   POWER clamp passes 1 mA (typ) near -0.52 V on its own axis
|   rising waveform, R_fixture 50, V_fixture 3.3: 20-80 % time 199ps typ, 268ps min, 164ps max; typ from 1.61 V to 3.3 V
|   rising waveform, R_fixture 50, V_fixture 0: 20-80 % time 1.53ns typ, 2.63ns min, 1.02ns max; typ from 0.001 V to 1.72 V
|   falling waveform, R_fixture 50, V_fixture 3.3: 20-80 % time 1.91ns typ, 2.86ns min, 1.38ns max; typ from 3.3 V to 1.61 V
|   falling waveform, R_fixture 50, V_fixture 0: 20-80 % time 244ps typ, 350ps min, 198ps max; typ from 1.72 V to 0 V
[POWER_clamp]
-3.3V     22.37A     22.96A     22.14A
-1.167V   1.737A     2.381A     1.512A
-1.133V   1.455A     2.091A     1.242A
-1.1V     1.183A     1.806A     986.6mA
-1.067V   923.7mA    1.529A     751.2mA
-1.033V   682.1mA    1.26A      542.1mA
-966.7mV  284.5mA    761.6mA    224.7mA
-933.3mV  149.5mA    542.1mA    120.4mA
-866.7mV  26.43mA    203.8mA    21.8mA
-800mV    6.477mA    45.96mA    6.894mA
-700mV    3.152mA    4.869mA    3.954mA
0V        470.2pA    4.969nA    556pA
[Pulldown]
-3.3V     -379.4uA   -332.5uA   -410.9uA
-1.2V     -3.537mA   -2.351mA   -4.45mA
-1V       -10.99mA   -4.979mA   -18.19mA
-900mV    -24.8mA    -9.223mA   -34.14mA
-700mV    -24.92mA   -18.03mA   -29.99mA
500mV     16.51mA    11.37mA    20.75mA
1.5V      33.12mA    21.9mA     43.48mA
3.7V      36.65mA    23.93mA    48.44mA
4.1V      36.79mA    3.426mA    48.89mA
4.4V      7.557mA    1.597mA    49.31mA
4.9V      1.707mA    822.5uA    5.402mA
6.6V      436uA      304.4uA    625.7uA
[Pullup]
-3.3V     352.6uA    285.2uA    404.5uA
-1.3V     2.559mA    1.632mA    3.524mA
-800mV    23.47mA    14.67mA    29.18mA
800mV     -20.79mA   -14.38mA   -26.49mA
2V        -38.75mA   -25.51mA   -51.47mA
3.7V      -44.51mA   -27.32mA   -61.38mA
4.2V      -37.49mA   -2.71mA    -62.46mA
4.3V      -15.98mA   -2.138mA   -62.46mA
4.5V      -4.997mA   -1.493mA   -61.74mA
4.7V      -2.803mA   -1.142mA   -15.75mA
4.9V      -1.927mA   -922.7uA   -5.515mA
6.6V      -515.4uA   -347uA     -755.5uA
[GND_clamp]
-3.3V     -22.52A    -23.16A    -22.27A
-1.167V   -1.839A    -2.548A    -1.554A
-1.1V     -1.269A    -1.966A    -993.7mA
-1.033V   -744.2mA   -1.409A    -496.5mA
-966.7mV  -312.6mA   -893.2mA   -149.2mA
-900mV    -73.53mA   -452.5mA   -34.14mA
-833.3mV  -18.4mA    -153.9mA   -16.65mA
-766.7mV  -8.834mA   -34.89mA   -10.11mA
-700mV    -4.682mA   -8.855mA   -5.413mA
-633.3mV  -2.07mA    -3.255mA   -2.268mA
3.3V      470.2pA    85.46uA    -36.92pA
[Ramp]
dV/dt_f  1.0230464/1.9208618n 0.69086528/2.9900382n  1.3077442/1.3777469n
dV/dt_r  1.0319626/1.5308958n 0.72983876/2.6791609n  1.2899647/1.0180473n
R_load = 50
[Rising Waveform]
R_fixture = 50
V_fixture = 3.3
V_fixture_min = 2.97
V_fixture_max = 3.63
0s        1.613V     1.833V     1.471V
234.3ps   1.652V     1.84V      1.594V
287.5ps   1.676V     1.846V     1.734V
360.3ps   1.753V     1.856V     2.176V
518.1ps   2.378V     1.901V     3.374V
618.1ps   2.914V     2.006V     3.576V
693.4ps   3.164V     2.15V      3.61V
923.1ps   3.289V     2.752V     3.623V
1.087ns   3.293V     2.939V     3.625V
7.933ns   3.3V       2.97V      3.63V
[Rising Waveform]
R_fixture = 50
V_fixture = 0
V_fixture_min = 0
V_fixture_max = 0
0s        594.8uV    876uV      679.1uV
478.9ps   68.41mV    31.83mV    187.3mV
955.5ps   411.1mV    92.81mV    952.5mV
1.444ns   796.9mV    252.6mV    1.544V
1.763ns   1.017V     361mV      1.816V
2.182ns   1.267V     490.7mV    1.995V
3.002ns   1.566V     723mV      2.106V
3.774ns   1.66V      911.7mV    2.135V
5.675ns   1.712V     1.149V     2.149V
7.933ns   1.719V     1.204V     2.149V
[Falling Waveform]
R_fixture = 50
V_fixture = 3.3
V_fixture_min = 2.97
V_fixture_max = 3.63
0s        3.3V       2.97V      3.63V
220.3ps   3.309V     2.97V      3.649V
409.6ps   3.299V     2.97V      3.548V
975.4ps   2.929V     2.887V     2.814V
1.655ns   2.492V     2.682V     2.152V
2.588ns   2.041V     2.423V     1.685V
3.33ns    1.827V     2.242V     1.558V
4.313ns   1.7V       2.073V     1.498V
5.664ns   1.639V     1.931V     1.475V
7.933ns   1.615V     1.854V     1.47V
[Falling Waveform]
R_fixture = 50
V_fixture = 0
V_fixture_min = 0
V_fixture_max = 0
0s        1.72V      1.216V     2.15V
217.6ps   1.7V       1.221V     2.029V
328.4ps   1.5V       1.192V     1.404V
413.9ps   1.138V     1.115V     788.3mV
489ps     774.2mV    992.8mV    400.8mV
573.8ps   440.2mV    806.1mV    153.7mV
702.2ps   143.5mV    503.7mV    23.65mV
932ps     9.589mV    146.4mV    2.762mV
1.143ns   2.797mV    29.21mV    2.154mV
7.933ns   3.15uV     51.75uV    0V
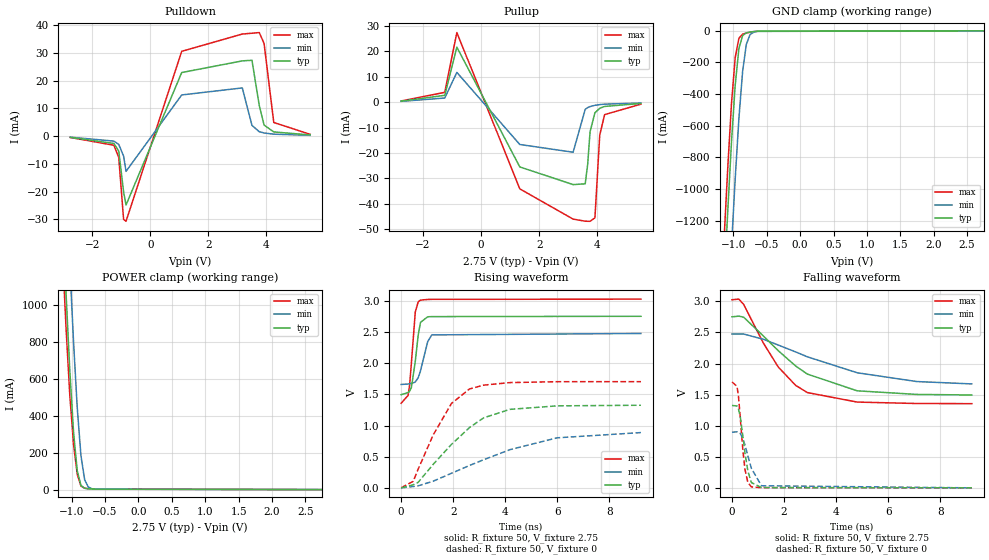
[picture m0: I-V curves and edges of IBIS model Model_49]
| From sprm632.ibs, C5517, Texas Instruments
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| Model based on original model for BC3350CTHYPU
|   Sub model PU_ON_COM_2P75
[model]   Model_49
|[Description]  [2.75V-I/O-PU-X, COM]
|   PU,COM,
|[Input Load]   PU
|[Output Drive]
|Voltage   2.75V
|Mode   I/O
Model_type   I/O
Polarity   Non-Inverting
Enable   Active-Low
Vinl =  0.7
Vinh =  1.7
Cref =  15.0000pF
Rref =  100.0000M
Vref =  0V
Vmeas =  1.375
C_comp   0.88864286p  0.88152539p   1.2993811p
[Model Spec]
Vinl   0.7   0.7   0.7
Vinh   1.7   1.7   1.7
[Temperature Range]   25   105   -10
[Voltage Range]   2.75   2.475   3.025
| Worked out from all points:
|   slope of the pulldown table from 0 to 0.412 V, typ, clamps not added: 34.2 ohm
|   slope of the pullup table from 0 to 0.412 V, typ, clamps not added: 40.5 ohm
|   GND clamp passes 1 mA (typ) near -0.58 V on its own axis
|   POWER clamp passes 1 mA (typ) near -0.52 V on its own axis
|   rising waveform, R_fixture 50, V_fixture 2.75: 20-80 % time 214ps typ, 292ps min, 175ps max; typ from 1.49 V to 2.75 V
|   rising waveform, R_fixture 50, V_fixture 0: 20-80 % time 1.92ns typ, 3.29ns min, 1.26ns max; typ from 0.001 V to 1.32 V
|   falling waveform, R_fixture 50, V_fixture 2.75: 20-80 % time 2.23ns typ, 3.32ns min, 1.59ns max; typ from 2.75 V to 1.49 V
|   falling waveform, R_fixture 50, V_fixture 0: 20-80 % time 264ps typ, 390ps min, 210ps max; typ from 1.32 V to 0.001 V
[POWER_clamp]
-2.75V    16.94A     17.55A     16.71A
-1.139V   1.502A     2.139A     1.286A
-1.083V   1.052A     1.667A     866.1mA
-1.028V   644mA      1.216A     510.2mA
-972.2mV  311.7mA    800.5mA    245.6mA
-916.7mV  101.6mA    443mA      82.35mA
-861.1mV  22.67mA    183.3mA    18.9mA
-805.6mV  7.069mA    53.17mA    7.355mA
-750mV    4.196mA    13.33mA    5.096mA
-694.4mV  3.112mA    4.503mA    3.911mA
-638.9mV  2.316mA    2.344mA    2.926mA
2.75V     -71.61uA   -47.92uA   -101.6uA
[Pulldown]
-2.75V    -442uA     -375.6uA   -488.5uA
-1.25V    -2.654mA   -1.807mA   -3.3mA
-1.083V   -5.418mA   -3.009mA   -7.764mA
-916.7mV  -20.1mA    -7.193mA   -30.06mA
-833.3mV  -24.88mA   -12.72mA   -30.75mA
1.083V    22.95mA    14.86mA    30.61mA
3.167V    27.16mA    17.4mA     36.85mA
3.5V      27.37mA    3.87mA     37.14mA
3.75V     11.11mA    1.6mA      37.38mA
3.917V    3.983mA    1.126mA    33.46mA
4.25V     1.511mA    698.6uA    4.924mA
5.5V      426.6uA    283.2uA    642.7uA
[Pullup]
-2.75V    418.2uA    329.2uA    490uA
-1.25V    2.701mA    1.641mA    3.883mA
-833.3mV  21.65mA    11.72mA    27.4mA
1.333V    -25.47mA   -16.64mA   -34.1mA
3.167V    -32.42mA   -19.68mA   -46mA
3.583V    -32.12mA   -2.8mA     -46.82mA
3.667V    -24.56mA   -2.134mA   -46.85mA
3.75V     -11.61mA   -1.713mA   -46.86mA
3.917V    -4.163mA   -1.221mA   -45.5mA
4.083V    -2.401mA   -944uA     -12.97mA
4.25V     -1.668mA   -767.9uA   -4.889mA
5.5V      -494.4uA   -316.6uA   -762.1uA
[GND_clamp]
-2.75V    -17.09A    -17.75A    -16.84A
-1.139V   -1.598A    -2.303A    -1.316A
-1.083V   -1.133A    -1.824A    -861.5mA
-1.028V   -703.5mA   -1.364A    -460mA
-972.2mV  -342.7mA   -934mA     -168.9mA
-916.7mV  -111.3mA   -552.8mA   -46.97mA
-861.1mV  -29.96mA   -256mA     -21.06mA
-805.6mV  -12.99mA   -85.38mA   -13.69mA
-750mV    -7.662mA   -23.86mA   -8.899mA
-694.4mV  -4.488mA   -8.134mA   -5.195mA
-638.9mV  -2.308mA   -3.554mA   -2.567mA
2.75V     323.4pA    41.68uA    -21.76uA
[Ramp]
dV/dt_f 0.76262987/2.2465359n 0.49727086/3.4609453n  1.0121454/1.6018326n
dV/dt_r 0.79494282/1.9257412n 0.53699569/3.3369519n  1.0215653/1.2584878n
R_load = 50
[Rising Waveform]
R_fixture = 50
V_fixture = 2.75
V_fixture_min = 2.475
V_fixture_max = 3.025
0s        1.494V     1.658V     1.356V
265.3ps   1.527V     1.665V     1.482V
323.8ps   1.548V     1.669V     1.64V
396ps     1.614V     1.674V     2.013V
542.7ps   2.027V     1.697V     2.818V
655.7ps   2.45V      1.767V     2.982V
742.7ps   2.652V     1.875V     3.009V
1.02ns    2.742V     2.345V     3.02V
1.178ns   2.745V     2.452V     3.021V
9.211ns   2.75V      2.475V     3.025V
[Rising Waveform]
R_fixture = 50
V_fixture = 0
V_fixture_min = 0
V_fixture_max = 0
0s        1.273mV    1.299mV    2.326mV
464.6ps   50.28mV    23.1mV     106.8mV
651.8ps   89.18mV    33.87mV    299mV
1.228ns   376.7mV    107.7mV    847.1mV
1.932ns   697.3mV    234.6mV    1.353V
2.627ns   967.8mV    360.4mV    1.586V
3.168ns   1.123V     451.9mV    1.647V
4.181ns   1.259V     613.5mV    1.688V
5.994ns   1.315V     803.1mV    1.702V
9.211ns   1.325V     886.9mV    1.703V
[Falling Waveform]
R_fixture = 50
V_fixture = 2.75
V_fixture_min = 2.475
V_fixture_max = 3.025
0s        2.75V      2.474V     3.025V
263.6ps   2.762V     2.474V     3.035V
447.2ps   2.745V     2.474V     2.951V
1.202ns   2.444V     2.39V      2.331V
1.777ns   2.206V     2.297V     1.944V
2.447ns   1.96V      2.186V     1.648V
2.895ns   1.83V      2.108V     1.533V
4.811ns   1.561V     1.851V     1.38V
7.1ns     1.503V     1.71V      1.357V
9.211ns   1.494V     1.672V     1.355V
[Falling Waveform]
R_fixture = 50
V_fixture = 0
V_fixture_min = 0
V_fixture_max = 0
0s        1.325V     895.7mV    1.704V
193.9ps   1.318V     901.8mV    1.632V
250.9ps   1.27V      898.2mV    1.467V
318.5ps   1.143V     876.2mV    1.133V
415.7ps   840.4mV    795.5mV    615.1mV
499.4ps   559.6mV    688.7mV    296.7mV
609.7ps   271.6mV    516.4mV    87.01mV
745.6ps   85.7mV     314.5mV    16.47mV
1.133ns   5.103mV    34.97mV    4.49mV
9.211ns   1.301mV    1.069mV    1.576mV
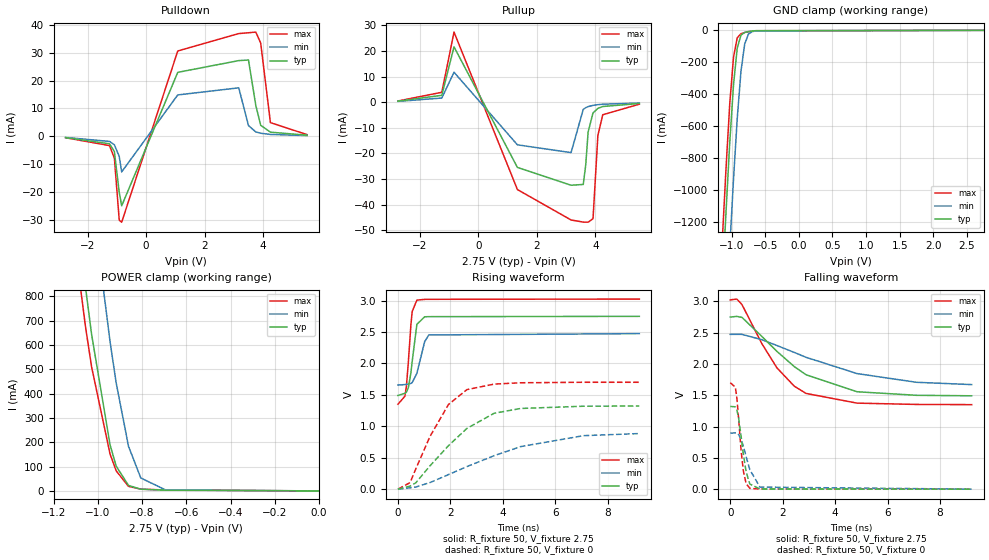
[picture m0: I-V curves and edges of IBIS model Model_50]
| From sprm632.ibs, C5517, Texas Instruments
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| Model based on original model for BC3350CTHYPU
|   Sub model PU_OFF_COM_2P75
[model]   Model_50
|[Description]  [2.75V-I/O-PU_OFF-X, COM]
|   PU_OFF,COM,
|[Input Load]   PU_OFF
|[Output Drive]
|Voltage   2.75V
|Mode   I/O
Model_type   I/O
Polarity   Non-Inverting
Enable   Active-Low
Vinl =  0.7
Vinh =  1.7
Cref =  15.0000pF
Rref =  100.0000M
Vref =  0V
Vmeas =  1.375
C_comp   0.88864286p  0.88152539p   1.2993811p
[Model Spec]
Vinl   0.7   0.7   0.7
Vinh   1.7   1.7   1.7
[Temperature Range]   25   105   -10
[Voltage Range]   2.75   2.475   3.025
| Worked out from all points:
|   slope of the pulldown table from 0 to 0.412 V, typ, clamps not added: 34.2 ohm
|   slope of the pullup table from 0 to 0.412 V, typ, clamps not added: 40.5 ohm
|   GND clamp passes 1 mA (typ) near -0.59 V on its own axis
|   POWER clamp passes 1 mA (typ) near -0.52 V on its own axis
|   rising waveform, R_fixture 50, V_fixture 2.75: 20-80 % time 213ps typ, 290ps min, 174ps max; typ from 1.49 V to 2.75 V
|   rising waveform, R_fixture 50, V_fixture 0: 20-80 % time 1.92ns typ, 3.28ns min, 1.26ns max; typ from 0 V to 1.32 V
|   falling waveform, R_fixture 50, V_fixture 2.75: 20-80 % time 2.23ns typ, 3.32ns min, 1.59ns max; typ from 2.75 V to 1.49 V
|   falling waveform, R_fixture 50, V_fixture 0: 20-80 % time 264ps typ, 390ps min, 210ps max; typ from 1.32 V to 0 V
[POWER_clamp]
-2.75V    16.94A     17.55A     16.71A
-1.167V   1.737A     2.381A     1.512A
-1.139V   1.502A     2.139A     1.286A
-1.111V   1.273A     1.9A       1.07A
-1.056V   840.9mA    1.438A     678.2mA
-1.028V   643.9mA    1.216A     510.2mA
-944.4mV  188.9mA    612.4mA    151.1mA
-916.7mV  101.6mA    443mA      82.31mA
-861.1mV  22.63mA    183.3mA    18.84mA
-805.6mV  7.021mA    53.15mA    7.284mA
-694.4mV  3.064mA    4.48mA     3.849mA
0V        324.3pA    3.771nA    327.9pA
[Pulldown]
-2.75V    -442uA     -375.6uA   -488.5uA
-1.25V    -2.654mA   -1.807mA   -3.3mA
-1.083V   -5.417mA   -3.008mA   -7.763mA
-916.7mV  -20.1mA    -7.193mA   -30.06mA
-833.3mV  -24.88mA   -12.72mA   -30.75mA
1.083V    22.95mA    14.86mA    30.61mA
3.167V    27.16mA    17.4mA     36.85mA
3.5V      27.37mA    3.87mA     37.14mA
3.75V     11.11mA    1.6mA      37.38mA
3.917V    3.983mA    1.126mA    33.46mA
4.25V     1.511mA    698.6uA    4.924mA
5.5V      426.6uA    283.2uA    642.7uA
[Pullup]
-2.75V    418.2uA    329.2uA    490uA
-1.25V    2.701mA    1.641mA    3.883mA
-833.3mV  21.65mA    11.72mA    27.4mA
1.333V    -25.47mA   -16.64mA   -34.11mA
3.167V    -32.42mA   -19.68mA   -46mA
3.583V    -32.12mA   -2.8mA     -46.82mA
3.667V    -24.56mA   -2.134mA   -46.85mA
3.75V     -11.61mA   -1.713mA   -46.86mA
3.917V    -4.162mA   -1.221mA   -45.5mA
4.083V    -2.401mA   -944uA     -12.97mA
4.25V     -1.668mA   -767.8uA   -4.889mA
5.5V      -494.4uA   -316.6uA   -762.1uA
[GND_clamp]
-2.75V    -17.09A    -17.75A    -16.84A
-1.139V   -1.598A    -2.303A    -1.316A
-1.083V   -1.133A    -1.824A    -861.5mA
-1.028V   -703.5mA   -1.364A    -460mA
-972.2mV  -342.7mA   -934mA     -168.9mA
-916.7mV  -111.3mA   -552.8mA   -46.88mA
-861.1mV  -29.9mA    -256mA     -20.96mA
-805.6mV  -12.91mA   -85.34mA   -13.59mA
-750mV    -7.591mA   -23.82mA   -8.797mA
-694.4mV  -4.417mA   -8.09mA    -5.093mA
-638.9mV  -2.236mA   -3.509mA   -2.465mA
2.75V     324.3pA    28.52uA    -164.7pA
[Ramp]
dV/dt_f 0.76423649/2.2477437n 0.49813512/3.4618299n  1.0142601/1.6005145n
dV/dt_r 0.79443751/1.9246804n 0.53651329/3.3346022n  1.0211499/1.2582672n
R_load = 50
[Rising Waveform]
R_fixture = 50
V_fixture = 2.75
V_fixture_min = 2.475
V_fixture_max = 3.025
0s        1.491V     1.657V     1.352V
265.3ps   1.525V     1.664V     1.478V
323.8ps   1.545V     1.668V     1.637V
396ps     1.612V     1.673V     2.012V
493.9ps   1.848V     1.683V     2.61V
543.8ps   2.031V     1.696V     2.827V
722.9ps   2.623V     1.843V     3.008V
1.02ns    2.743V     2.347V     3.02V
1.178ns   2.745V     2.454V     3.021V
9.211ns   2.75V      2.475V     3.025V
[Rising Waveform]
R_fixture = 50
V_fixture = 0
V_fixture_min = 0
V_fixture_max = 0
0s        0V         274uV      748.7uV
464.5ps   48.84mV    22.07mV    104.1mV
680.8ps   100.4mV    34.19mV    322.4mV
1.225ns   371.8mV    105mV      840.3mV
1.928ns   692.4mV    231.6mV    1.347V
2.63ns    966.1mV    358.8mV    1.584V
3.671ns   1.208V     533.1mV    1.672V
4.682ns   1.284V     677.3mV    1.693V
7.082ns   1.32V      851.4mV    1.701V
9.211ns   1.323V     885mV      1.701V
[Falling Waveform]
R_fixture = 50
V_fixture = 2.75
V_fixture_min = 2.475
V_fixture_max = 3.025
0s        2.75V      2.474V     3.025V
250.3ps   2.761V     2.474V     3.038V
447.3ps   2.745V     2.474V     2.95V
1.202ns   2.442V     2.389V     2.328V
1.778ns   2.203V     2.296V     1.94V
2.444ns   1.958V     2.185V     1.645V
2.893ns   1.828V     2.107V     1.53V
4.838ns   1.557V     1.847V     1.375V
7.102ns   1.5V       1.708V     1.354V
9.211ns   1.492V     1.671V     1.351V
[Falling Waveform]
R_fixture = 50
V_fixture = 0
V_fixture_min = 0
V_fixture_max = 0
0s        1.322V     893.9mV    1.702V
193.9ps   1.316V     900mV      1.629V
250.9ps   1.268V     896.4mV    1.463V
318.4ps   1.139V     874.2mV    1.126V
415.7ps   835.7mV    793.3mV    607.9mV
499.7ps   554.4mV    685.9mV    290.6mV
605.4ps   276.8mV    520.8mV    87.45mV
745.6ps   82.63mV    312.2mV    13.06mV
1.133ns   2.544mV    33mV       1.997mV
9.211ns   1.359uV    36.31uV    0V
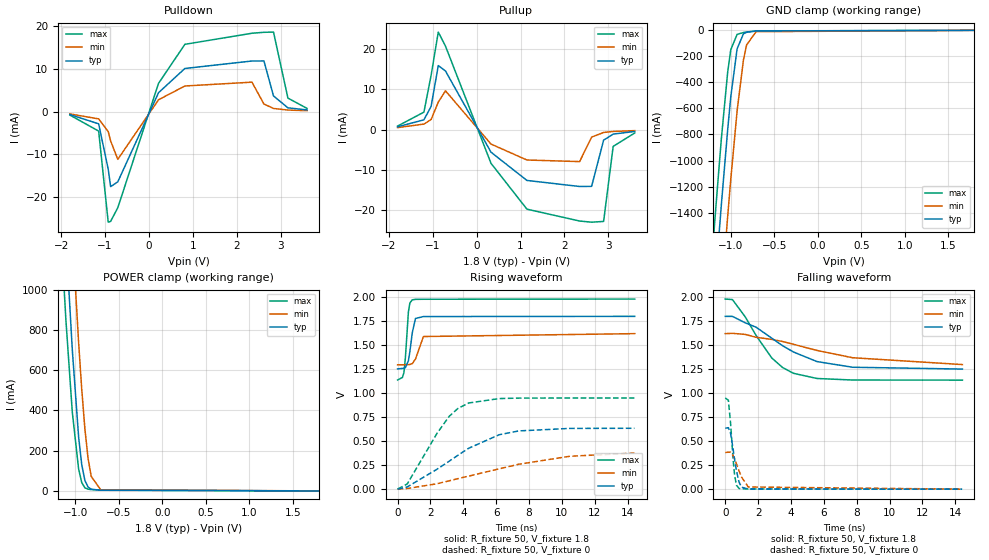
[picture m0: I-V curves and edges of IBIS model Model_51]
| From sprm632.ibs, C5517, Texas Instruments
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| Model based on original model for BC3350CTHYPU
|   Sub model PU_ON_IND_1P8
[model]   Model_51
|[Description]  [1.8V-I/O-PU-X, IND]
|   PU,IND,
|[Input Load]   PU
|[Output Drive]
|Voltage   1.8V
|Mode   I/O
Model_type   I/O
Polarity   Non-Inverting
Enable   Active-Low
Vinl =  0.63
Vinh =  1.17
Cref =  15.0000pF
Rref =  100.0000M
Vref =  0V
Vmeas =  0.9
C_comp   1.5053119p   1.48392p   1.520888p
[Model Spec]
Vinl   0.63   0.567   0.693
Vinh   1.17   1.053   1.287
[Temperature Range]   25   105   -40
[Voltage Range]   1.8   1.62   1.98
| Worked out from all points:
|   slope of the pulldown table from 0 to 0.27 V, typ, clamps not added: 51 ohm
|   slope of the pullup table from 0 to 0.27 V, typ, clamps not added: 57.1 ohm
|   GND clamp passes 1 mA (typ) near -0.58 V on its own axis
|   POWER clamp passes 1 mA (typ) near -0.52 V on its own axis
|   rising waveform, R_fixture 50, V_fixture 1.8: 20-80 % time 263ps typ, 380ps min, 196ps max; typ from 1.25 V to 1.8 V
|   rising waveform, R_fixture 50, V_fixture 0: 20-80 % time 3.48ns typ, 5.76ns min, 2.08ns max; typ from 0.001 V to 0.635 V
|   falling waveform, R_fixture 50, V_fixture 1.8: 20-80 % time 3.23ns typ, 5.07ns min, 2.09ns max; typ from 1.8 V to 1.25 V
|   falling waveform, R_fixture 50, V_fixture 0: 20-80 % time 358ps typ, 552ps min, 247ps max; typ from 0.635 V to 0.001 V
[POWER_clamp]
-1.8V     7.656A     8.299A     7.195A
-1.182V   1.868A     2.514A     1.416A
-1.145V   1.557A     2.196A     1.122A
-1.109V   1.256A     1.883A     846.7mA
-1.036V   703.1mA    1.284A     392.3mA
-963.6mV  270.2mA    740.7mA    110.3mA
-927.3mV  130.5mA    505.1mA    41.48mA
-890.9mV  51.54mA    307.4mA    15.38mA
-854.5mV  19.17mA    161.5mA    8.712mA
-818.2mV  8.589mA    72.12mA    6.725mA
-709.1mV  3.339mA    5.711mA    4.069mA
1.8V      -27.44uA   -17.12uA   -44.66uA
[Pulldown]
-1.8V     -681.9uA   -528.3uA   -794.7uA
-1.145V   -2.848mA   -1.688mA   -4.553mA
-927.3mV  -13.49mA   -4.672mA   -25.91mA
-872.7mV  -17.57mA   -6.855mA   -25.72mA
-709.1mV  -16.44mA   -11.17mA   -22.51mA
218.2mV   4.45mA     2.794mA    6.638mA
818.2mV   10.13mA    6.022mA    15.79mA
2.345V    11.88mA    6.92mA     18.39mA
2.618V    11.89mA    1.797mA    18.61mA
2.836V    3.687mA    752.6uA    18.66mA
3.164V    900.6uA    382.8uA    3.184mA
3.6V      416.6uA    227.7uA    766.1uA
[Pullup]
-1.8V     683.6uA    489.3uA    876.8uA
-1.2V     2.424mA    1.368mA    4.326mA
-1.036V   5.753mA    2.495mA    13.46mA
-872.7mV  15.87mA    6.82mA     24.17mA
-709.1mV  14.53mA    9.61mA     20.69mA
327.3mV   -5.597mA   -3.586mA   -8.356mA
1.145V    -12.6mA    -7.535mA   -19.72mA
2.345V    -14.1mA    -7.933mA   -22.66mA
2.618V    -14.07mA   -1.864mA   -22.95mA
2.891V    -2.623mA   -708.3uA   -22.76mA
3.109V    -1.114mA   -461.7uA   -4.16mA
3.6V      -465.4uA   -255.6uA   -836.2uA
[GND_clamp]
-1.8V     -7.797A    -8.487A    -7.298A
-1.218V   -2.296A    -3.009A    -1.771A
-1.182V   -1.972A    -2.683A    -1.449A
-1.145V   -1.654A    -2.361A    -1.137A
-1.109V   -1.345A    -2.044A    -838.2mA
-1.036V   -766.6mA   -1.434A    -323.5mA
-1V       -511.1mA   -1.144A    -149.1mA
-927.3mV  -142.6mA   -620.3mA   -31.19mA
-854.5mV  -26.4mA    -229.1mA   -16.85mA
-818.2mV  -14.97mA   -112.4mA   -13.06mA
-709.1mV  -5.172mA   -10.44mA   -4.573mA
1.8V      168.4pA    9.027uA    -11uA
[Ramp]
dV/dt_f 0.33449137/3.2861394n 0.19893335/5.2926035n 0.51331363/2.1119144n
dV/dt_r 0.38093151/3.4869521n 0.22904008/5.8793673n 0.57008449/2.087255n
R_load = 50
[Rising Waveform]
R_fixture = 50
V_fixture = 1.8
V_fixture_min = 1.62
V_fixture_max = 1.98
0s        1.253V     1.296V     1.137V
297.6ps   1.258V     1.296V     1.164V
387ps     1.261V     1.296V     1.214V
476.5ps   1.266V     1.297V     1.369V
660.3ps   1.338V     1.297V     1.848V
749.9ps   1.434V     1.299V     1.94V
895.1ps   1.629V     1.308V     1.972V
1.091ns   1.778V     1.356V     1.977V
1.575ns   1.798V     1.59V      1.978V
14.43ns   1.8V       1.62V      1.98V
[Rising Waveform]
R_fixture = 50
V_fixture = 0
V_fixture_min = 0
V_fixture_max = 0
0s        1.301mV    841.2uV    1.77mV
588.7ps   23.62mV    7.704mV    55.1mV
2.392ns   207.8mV    57.07mV    579.6mV
3.138ns   291.5mV    87.88mV    758.6mV
3.671ns   353.8mV    110.5mV    841mV
4.328ns   426.9mV    136.7mV    898.1mV
6.184ns   567.6mV    212.6mV    944.1mV
7.379ns   607.3mV    260.5mV    948.9mV
10.48ns   633.4mV    343.6mV    950.1mV
14.41ns   634.8mV    376.5mV    949.8mV
[Falling Waveform]
R_fixture = 50
V_fixture = 1.8
V_fixture_min = 1.62
V_fixture_max = 1.98
0s        1.8V       1.62V      1.98V
435.4ps   1.8V       1.623V     1.975V
1.215ns   1.733V     1.612V     1.795V
1.876ns   1.687V     1.582V     1.601V
2.828ns   1.573V     1.56V      1.367V
3.489ns   1.494V     1.538V     1.267V
4.149ns   1.429V     1.509V     1.207V
5.582ns   1.329V     1.445V     1.153V
7.748ns   1.27V      1.369V     1.137V
14.43ns   1.251V     1.298V     1.136V
[Falling Waveform]
R_fixture = 50
V_fixture = 0
V_fixture_min = 0
V_fixture_max = 0
0s        635.1mV    382.2mV    950.5mV
191.8ps   640.8mV    385.9mV    925.8mV
325.1ps   581.9mV    385.5mV    687.4mV
480.7ps   415.6mV    348.9mV    306.4mV
568.7ps   311.7mV    315.4mV    147.5mV
680.6ps   193.6mV    264.7mV    43.27mV
836.3ps   75.95mV    191.5mV    7.997mV
989.9ps   21.13mV    127.6mV    3.792mV
1.399ns   2.19mV     23.31mV    2.773mV
14.41ns   624.8uV    494.3uV    809.2uV
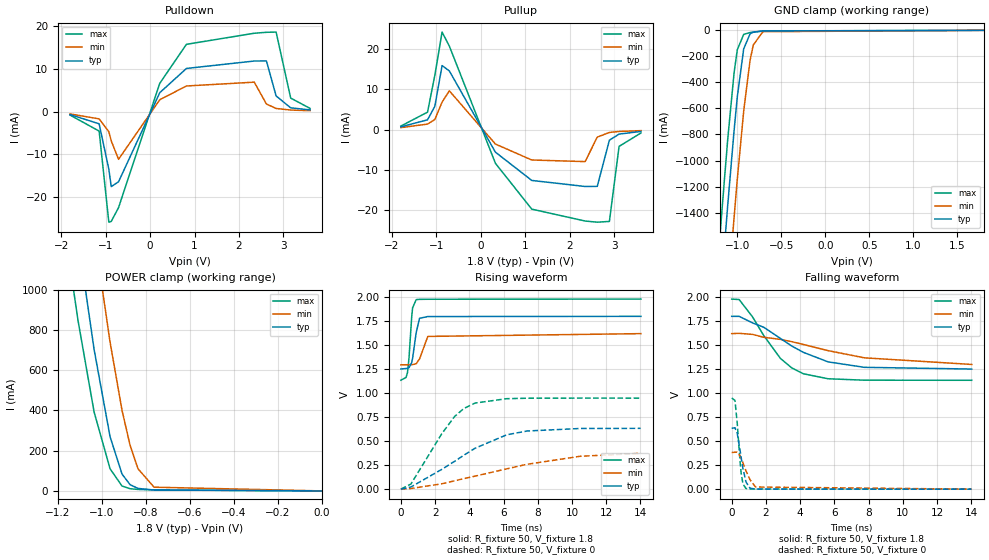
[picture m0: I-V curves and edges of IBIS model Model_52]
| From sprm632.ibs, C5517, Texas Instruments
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| Model based on original model for BC3350CTHYPU
|   Sub model PU_OFF_IND_1P8
[model]   Model_52
|[Description]  [1.8V-I/O-PU_OFF-X, IND]
|   PU_OFF,IND,
|[Input Load]   PU_OFF
|[Output Drive]
|Voltage   1.8V
|Mode   I/O
Model_type   I/O
Polarity   Non-Inverting
Enable   Active-Low
Vinl =  0.63
Vinh =  1.17
Cref =  15.0000pF
Rref =  100.0000M
Vref =  0V
Vmeas =  0.9
C_comp   1.5053119p   1.48392p   1.520888p
[Model Spec]
Vinl   0.63   0.567   0.693
Vinh   1.17   1.053   1.287
[Temperature Range]   25   105   -40
[Voltage Range]   1.8   1.62   1.98
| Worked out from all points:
|   slope of the pulldown table from 0 to 0.27 V, typ, clamps not added: 51 ohm
|   slope of the pullup table from 0 to 0.27 V, typ, clamps not added: 57.1 ohm
|   GND clamp passes 1 mA (typ) near -0.59 V on its own axis
|   POWER clamp passes 1 mA (typ) near -0.52 V on its own axis
|   rising waveform, R_fixture 50, V_fixture 1.8: 20-80 % time 262ps typ, 379ps min, 195ps max; typ from 1.25 V to 1.8 V
|   rising waveform, R_fixture 50, V_fixture 0: 20-80 % time 3.48ns typ, 5.72ns min, 2.08ns max; typ from 0.001 V to 0.634 V
|   falling waveform, R_fixture 50, V_fixture 1.8: 20-80 % time 3.23ns typ, 5.04ns min, 2.09ns max; typ from 1.8 V to 1.25 V
|   falling waveform, R_fixture 50, V_fixture 0: 20-80 % time 357ps typ, 552ps min, 247ps max; typ from 0.634 V to 0 V
[POWER_clamp]
-1.8V     7.656A     8.299A     7.195A
-1.182V   1.868A     2.514A     1.416A
-1.164V   1.711A     2.354A     1.267A
-1.127V   1.405A     2.039A     981.3mA
-1.109V   1.256A     1.883A     846.7mA
-1.036V   703.1mA    1.284A     392.3mA
-963.6mV  270.2mA    740.7mA    110.3mA
-909.1mV  83.69mA    400.6mA    24.32mA
-872.7mV  31.23mA    227.4mA    10.89mA
-836.4mV  12.32mA    110mA      7.43mA
-763.6mV  4.554mA    18.61mA    5.187mA
0V        168.8pA    2.305nA    117.6pA
[Pulldown]
-1.8V     -681.9uA   -528.3uA   -794.7uA
-1.145V   -2.847mA   -1.688mA   -4.553mA
-927.3mV  -13.49mA   -4.672mA   -25.91mA
-872.7mV  -17.57mA   -6.855mA   -25.72mA
-709.1mV  -16.44mA   -11.17mA   -22.51mA
218.2mV   4.45mA     2.794mA    6.638mA
818.2mV   10.13mA    6.022mA    15.79mA
2.345V    11.88mA    6.92mA     18.39mA
2.618V    11.89mA    1.797mA    18.61mA
2.836V    3.687mA    752.6uA    18.66mA
3.164V    900.6uA    382.8uA    3.184mA
3.6V      416.6uA    227.7uA    766.1uA
[Pullup]
-1.8V     683.6uA    489.3uA    876.8uA
-1.2V     2.424mA    1.368mA    4.326mA
-1.036V   5.753mA    2.495mA    13.46mA
-872.7mV  15.87mA    6.82mA     24.17mA
-709.1mV  14.53mA    9.61mA     20.69mA
327.3mV   -5.597mA   -3.586mA   -8.356mA
1.145V    -12.6mA    -7.535mA   -19.72mA
2.345V    -14.1mA    -7.933mA   -22.66mA
2.618V    -14.07mA   -1.864mA   -22.95mA
2.891V    -2.623mA   -708.3uA   -22.76mA
3.109V    -1.114mA   -461.7uA   -4.16mA
3.6V      -465.4uA   -255.6uA   -836.2uA
[GND_clamp]
-1.8V     -7.797A    -8.487A    -7.298A
-1.218V   -2.296A    -3.009A    -1.771A
-1.182V   -1.972A    -2.683A    -1.449A
-1.145V   -1.654A    -2.361A    -1.137A
-1.109V   -1.345A    -2.044A    -838.2mA
-1.036V   -766.6mA   -1.434A    -323.5mA
-1V       -511.1mA   -1.144A    -149mA
-927.3mV  -142.6mA   -620.3mA   -31.15mA
-854.5mV  -26.37mA   -229mA     -16.8mA
-818.2mV  -14.95mA   -112.3mA   -13.02mA
-709.1mV  -5.144mA   -10.43mA   -4.529mA
1.8V      168.8pA    3.273uA    68.62pA
[Ramp]
dV/dt_f 0.33495337/3.2867977n 0.19918921/5.2914326n 0.51437323/2.1135855n
dV/dt_r 0.38058075/3.4838409n 0.22884089/5.874245n  0.56966613/2.0852558n
R_load = 50
[Rising Waveform]
R_fixture = 50
V_fixture = 1.8
V_fixture_min = 1.62
V_fixture_max = 1.98
0s        1.252V     1.295V     1.135V
297.6ps   1.257V     1.296V     1.163V
387ps     1.26V      1.296V     1.213V
476.4ps   1.265V     1.297V     1.368V
634.6ps   1.319V     1.297V     1.798V
685.8ps   1.363V     1.297V     1.889V
895.2ps   1.63V      1.307V     1.974V
1.091ns   1.78V      1.356V     1.977V
1.575ns   1.798V     1.591V     1.978V
14.03ns   1.8V       1.62V      1.98V
[Rising Waveform]
R_fixture = 50
V_fixture = 0
V_fixture_min = 0
V_fixture_max = 0
0s        675.2uV    361.4uV    960.1uV
588.7ps   22.99mV    7.226mV    53.84mV
2.394ns   206.7mV    56.31mV    578.2mV
3.142ns   290.6mV    87.22mV    757.5mV
3.676ns   353.1mV    109.9mV    839.9mV
4.335ns   426.4mV    136.2mV    896.9mV
6.184ns   566.3mV    211.8mV    942.6mV
7.379ns   606.1mV    259.6mV    947.4mV
10.48ns   632.2mV    342.7mV    948.6mV
14.01ns   633.6mV    373.7mV    948.3mV
[Falling Waveform]
R_fixture = 50
V_fixture = 1.8
V_fixture_min = 1.62
V_fixture_max = 1.98
0s        1.8V       1.62V      1.98V
435.4ps   1.8V       1.623V     1.975V
1.216ns   1.732V     1.612V     1.795V
1.876ns   1.686V     1.582V     1.599V
2.847ns   1.57V      1.56V      1.362V
3.517ns   1.49V      1.536V     1.262V
4.188ns   1.425V     1.507V     1.202V
5.629ns   1.326V     1.443V     1.15V
7.751ns   1.269V     1.368V     1.135V
14.03ns   1.251V     1.299V     1.134V
[Falling Waveform]
R_fixture = 50
V_fixture = 0
V_fixture_min = 0
V_fixture_max = 0
0s        633.9mV    381.4mV    949mV
191.8ps   639.7mV    385.1mV    924.2mV
325.1ps   580.6mV    384.7mV    684.7mV
471.7ps   425mV      351mV      324mV
556.1ps   325.1mV    320mV      163.8mV
656.6ps   215.2mV    275.3mV    55.74mV
836.2ps   74.68mV    190.6mV    5.928mV
1.07ns    9.553mV    97.78mV    1.55mV
1.399ns   1.017mV    22.53mV    1.298mV
14.01ns   0V         14.19uV    0V
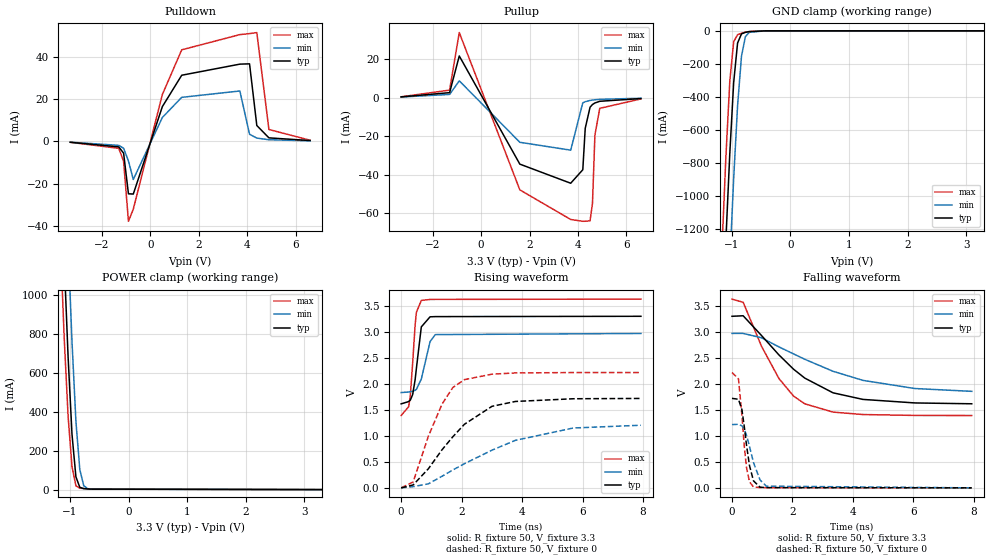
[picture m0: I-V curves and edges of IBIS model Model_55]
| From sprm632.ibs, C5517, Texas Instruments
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| Model based on original model for BC3350CTHYPU
|   Sub model PU_ON_IND_3P3
[model]   Model_55
|[Description]  [3.3V-I/O-PU-X, IND]
|   PU,IND,
|[Input Load]   PU
|[Output Drive]
|Voltage   3.3V
|Mode   I/O
Model_type   I/O
Polarity   Non-Inverting
Enable   Active-Low
Vinl =  0.8
Vinh =  2
Cref =  15.0000pF
Rref =  100.0000M
Vref =  0V
Vmeas =  1.65
C_comp   0.87673039p  0.86952386p   1.2993811p
[Model Spec]
Vinl   0.8   0.8   0.8
Vinh   2   2   2
[Temperature Range]   25   105   -40
[Voltage Range]   3.3   2.97   3.63
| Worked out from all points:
|   slope of the pulldown table from 0 to 0.495 V, typ, clamps not added: 30.2 ohm
|   slope of the pullup table from 0 to 0.495 V, typ, clamps not added: 36.2 ohm
|   GND clamp passes 1 mA (typ) near -0.58 V on its own axis
|   POWER clamp passes 1 mA (typ) near -0.52 V on its own axis
|   rising waveform, R_fixture 50, V_fixture 3.3: 20-80 % time 198ps typ, 268ps min, 157ps max; typ from 1.62 V to 3.3 V
|   rising waveform, R_fixture 50, V_fixture 0: 20-80 % time 1.53ns typ, 2.64ns min, 921ps max; typ from 0.002 V to 1.72 V
|   falling waveform, R_fixture 50, V_fixture 3.3: 20-80 % time 1.91ns typ, 2.84ns min, 1.27ns max; typ from 3.3 V to 1.62 V
|   falling waveform, R_fixture 50, V_fixture 0: 20-80 % time 244ps typ, 350ps min, 189ps max; typ from 1.72 V to 0.002 V
[POWER_clamp]
-3.3V     22.37A     22.96A     21.96A
-1.167V   1.737A     2.381A     1.292A
-1.1V     1.183A     1.806A     781.9mA
-1.033V   682.1mA    1.26A      376.9mA
-966.7mV  284.5mA    761.6mA    118.3mA
-900mV    65.81mA    352.3mA    19.07mA
-833.3mV  11.58mA    102.8mA    7.377mA
-766.7mV  4.716mA    20.06mA    5.345mA
-700mV    3.207mA    4.896mA    3.915mA
-633.3mV  2.25mA     2.24mA     2.686mA
3.3V      -103.5uA   -77.89uA   -161uA
[Pulldown]
-3.3V     -379.4uA   -332.5uA   -396.2uA
-1.3V     -2.568mA   -1.838mA   -3.257mA
-1.1V     -5.533mA   -3.228mA   -9.384mA
-900mV    -24.8mA    -9.223mA   -37.83mA
-700mV    -24.92mA   -18.03mA   -32.09mA
500mV     16.51mA    11.37mA    22.25mA
1.3V      31.39mA    20.91mA    43.43mA
3.7V      36.65mA    23.93mA    50.64mA
4.1V      36.79mA    3.426mA    51.12mA
4.4V      7.557mA    1.597mA    51.61mA
4.9V      1.707mA    822.5uA    5.677mA
6.6V      436uA      304.4uA    587.7uA
[Pullup]
-3.3V     352.6uA    285.2uA    400.6uA
-1.3V     2.559mA    1.632mA    3.875mA
-900mV    21.62mA    8.718mA    33.78mA
1.6V      -34.58mA   -23.24mA   -47.95mA
3.7V      -44.51mA   -27.32mA   -63.35mA
4.2V      -37.5mA    -2.71mA    -64.29mA
4.3V      -15.99mA   -2.138mA   -64.26mA
4.5V      -4.997mA   -1.493mA   -64.05mA
4.6V      -3.604mA   -1.294mA   -54.92mA
4.7V      -2.803mA   -1.142mA   -19.49mA
4.9V      -1.928mA   -922.7uA   -5.592mA
6.6V      -515.4uA   -347uA     -695.9uA
[GND_clamp]
-3.3V     -22.52A    -23.16A    -22.07A
-1.167V   -1.839A    -2.548A    -1.318A
-1.1V     -1.269A    -1.966A    -766.6mA
-1.033V   -744.2mA   -1.409A    -306.1mA
-966.7mV  -312.7mA   -893.3mA   -65.63mA
-900mV    -73.61mA   -452.5mA   -23.44mA
-833.3mV  -18.5mA    -154mA     -14.68mA
-766.7mV  -8.937mA   -34.95mA   -8.658mA
-700mV    -4.785mA   -8.919mA   -4.18mA
-433.3mV  -140uA     -186.8uA   -170.1uA
3.3V      469pA      103.6uA    -33uA
[Ramp]
dV/dt_f  1.0208264/1.9228723n 0.68955466/2.9575569n  1.3540082/1.2742329n
dV/dt_r  1.0324431/1.5316537n 0.73040589/2.6813541n  1.3303754/0.92183205n
R_load = 50
[Rising Waveform]
R_fixture = 50
V_fixture = 3.3
V_fixture_min = 2.97
V_fixture_max = 3.63
0s        1.617V     1.835V     1.393V
249.7ps   1.661V     1.844V     1.563V
304ps     1.689V     1.851V     1.783V
381.9ps   1.797V     1.861V     2.411V
461.5ps   2.077V     1.877V     3.125V
504.6ps   2.3V       1.896V     3.376V
667.1ps   3.096V     2.093V     3.605V
956.6ps   3.29V      2.814V     3.624V
1.128ns   3.294V     2.948V     3.625V
7.932ns   3.3V       2.97V      3.63V
[Rising Waveform]
R_fixture = 50
V_fixture = 0
V_fixture_min = 0
V_fixture_max = 0
0s        2.332mV    2.259mV    2.85mV
397.2ps   58.13mV    25.4mV     115.2mV
901.6ps   369.9mV    79.98mV    996.1mV
1.353ns   734.9mV    225.3mV    1.612V
1.706ns   981.9mV    344.7mV    1.929V
2.094ns   1.225V     467.3mV    2.083V
3.006ns   1.57V      726.9mV    2.188V
3.779ns   1.663V     915.7mV    2.211V
5.697ns   1.715V     1.153V     2.219V
7.932ns   1.721V     1.206V     2.219V
[Falling Waveform]
R_fixture = 50
V_fixture = 3.3
V_fixture_min = 2.97
V_fixture_max = 3.63
0s        3.3V       2.971V     3.63V
369.8ps   3.31V      2.971V     3.569V
977.4ps   2.93V      2.887V     2.723V
1.554ns   2.557V     2.711V     2.103V
2.038ns   2.282V     2.577V     1.765V
2.41ns    2.111V     2.473V     1.617V
3.342ns   1.829V     2.243V     1.458V
4.332ns   1.702V     2.068V     1.411V
6.056ns   1.634V     1.911V     1.394V
7.932ns   1.618V     1.857V     1.392V
[Falling Waveform]
R_fixture = 50
V_fixture = 0
V_fixture_min = 0
V_fixture_max = 0
0s        1.722V     1.218V     2.219V
214.9ps   1.705V     1.224V     2.097V
329.3ps   1.504V     1.194V     1.395V
407.1ps   1.18V      1.126V     794.5mV
479.7ps   827.3mV    1.015V     395.5mV
579.7ps   428.7mV    797.6mV    117.2mV
711.7ps   135.8mV    488.6mV    19.58mV
928.4ps   13.91mV    153.3mV    6.295mV
1.136ns   5.834mV    34.18mV    5.125mV
7.932ns   1.739mV    1.445mV    2.215mV
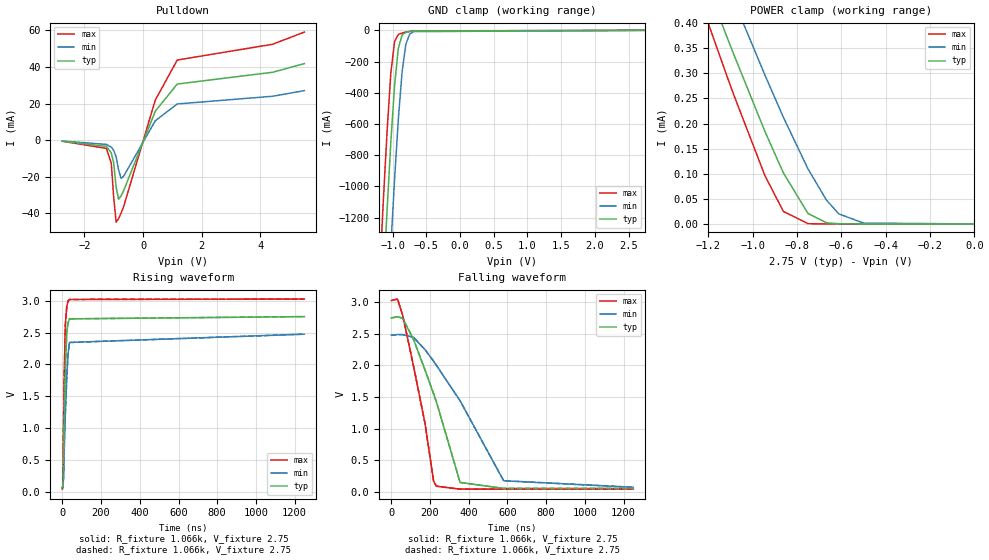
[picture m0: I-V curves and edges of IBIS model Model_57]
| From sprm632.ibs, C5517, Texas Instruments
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| Model based on original model for BI2C33S
|   Sub model BI2C33S_IND_2P75
[model]   Model_57
|[Description]  [2.75V-I/O_OPEN_DRAIN-X-X]
|   , ,
|[Input Load]
|[Output Drive]
|Voltage   2.75V
|Mode   I/O_OPEN_DRAIN
Model_type   I/O_open_drain
Polarity   Non-Inverting
Enable   Active-Low
Vinl =  0.825
Vinh =  1.925
Cref =  400pF
Rref =  528
Vref =  1.8V
Vmeas =  1.375
C_comp   4.5968371p   3.681855p   6.112525p
[Model Spec]
Vinl   0.825   0.7425   0.9075
Vinh   1.925   1.7325   2.1175
[Temperature Range]   25   105   -40
[Voltage Range]   2.75   2.475   3.025
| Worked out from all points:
|   slope of the pulldown table from 0 to 0.412 V, typ, clamps not added: 26.3 ohm
|   GND clamp passes 1 mA (typ) near -0.59 V on its own axis
|   POWER clamp passes 1 mA (typ) near -1.65 V on its own axis
|   rising waveform, R_fixture 1.066k, V_fixture 2.75: 20-80 % time 12ns typ, 17.3ns min, 9.09ns max; typ from 0.056 V to 2.75 V
|   rising waveform, R_fixture 1.066k, V_fixture 2.75: 20-80 % time 12ns typ, 17.3ns min, 9.09ns max; typ from 0.056 V to 2.75 V
|   falling waveform, R_fixture 1.066k, V_fixture 2.75: 20-80 % time 174ns typ, 277ns min, 113ns max; typ from 2.75 V to 0.057 V
|   falling waveform, R_fixture 1.066k, V_fixture 2.75: 20-80 % time 174ns typ, 277ns min, 113ns max; typ from 2.75 V to 0.057 V
[POWER_clamp]
-2.75V    2.337mA    2.336mA    2.439mA
-1.25V    527.3uA    625.5uA    462.8uA
-1.194V   462.9uA    564.3uA    392.6uA
-1.111V   367.5uA    473.6uA    289.1uA
-1.083V   336.1uA    443.6uA    255.2uA
-944.4mV  184.5uA    296.8uA    96.48uA
-861.1mV  101.8uA    212.6uA    24.94uA
-750mV    20.83uA    109.6uA    497nA
-666.7mV  2.323uA    47.43uA    10.22nA
-611.1mV  365.5nA    20.06uA    908.5pA
-500mV    6.261nA    1.781uA    206.9pA
0V        287.9pA    3.669nA    148.4pA
[Pulldown]
-2.75V    -572.6uA   -486.7uA   -612.1uA
-1.25V    -3.416mA   -2.329mA   -4.547mA
-1.083V   -6.943mA   -3.866mA   -12.52mA
-1V       -12.52mA   -5.582mA   -31.38mA
-916.7mV  -25.86mA   -9.174mA   -44.89mA
-833.3mV  -32.31mA   -16.26mA   -42.92mA
-750mV    -30.53mA   -20.86mA   -39.98mA
-666.7mV  -27.88mA   -19.89mA   -36.63mA
416.7mV   15.79mA    10.59mA    21.87mA
1.167V    30.69mA    19.79mA    43.81mA
4.417V    37.12mA    24mA       52.44mA
5.5V      41.87mA    27.08mA    59.1mA
[GND_clamp]
-2.75V    -17.12A    -17.77A    -16.65A
-1.194V   -2.102A    -2.82A     -1.569A
-1.139V   -1.615A    -2.327A    -1.089A
-1.083V   -1.148A    -1.848A    -643.8mA
-1.028V   -716.9mA   -1.386A    -274.7mA
-972.2mV  -352.3mA   -954.2mA   -71.5mA
-916.7mV  -115.4mA   -569.8mA   -26.47mA
-861.1mV  -30.53mA   -267.7mA   -17.24mA
-805.6mV  -12.86mA   -90.47mA   -11.63mA
-750mV    -7.485mA   -25.09mA   -7.098mA
-694.4mV  -4.344mA   -8.305mA   -3.665mA
2.75V     287.9pA    7.044nA    120pA
[Ramp]
dV/dt_f 0.93161873/0.26677204u 0.62695293/0.43115913u  1.2202077/0.16222602u
dV/dt_r 6.7138267m/3.6993922n 4.5327543m/3.8281853n 9.0178666m/3.1676521n
R_load = 50
[Rising Waveform]
R_fixture = 1.066k
V_fixture = 2.75
V_fixture_min = 2.475
V_fixture_max = 3.025
0s        55.82mV    75.31mV    46.28mV
2.318ns   87.64mV    92.59mV    100.6mV
4.017ns   188.8mV    128.2mV    526.6mV
6.106ns   626.7mV    225mV      1.104V
9.936ns   1.266V     705.7mV    1.872V
15.4ns    1.95V      1.241V     2.624V
22.74ns   2.51V      1.79V      2.912V
28.99ns   2.645V     2.151V     2.99V
36.49ns   2.715V     2.345V     3.019V
1.25us    2.75V      2.475V     3.025V
[Rising Waveform]
R_fixture = 1.066k
V_fixture = 2.75
V_fixture_min = 2.475
V_fixture_max = 3.025
0s        55.82mV    75.31mV    46.28mV
2.318ns   87.64mV    92.59mV    100.6mV
4.017ns   188.8mV    128.2mV    526.6mV
6.106ns   626.7mV    225mV      1.104V
9.936ns   1.266V     705.7mV    1.872V
15.4ns    1.95V      1.241V     2.624V
22.74ns   2.51V      1.79V      2.912V
28.99ns   2.645V     2.151V     2.99V
36.49ns   2.715V     2.345V     3.019V
1.25us    2.75V      2.475V     3.025V
[Falling Waveform]
R_fixture = 1.066k
V_fixture = 2.75
V_fixture_min = 2.475
V_fixture_max = 3.025
0s        2.749V     2.476V     3.025V
32.08ns   2.77V      2.487V     3.048V
58.84ns   2.743V     2.487V     2.789V
115ns     2.408V     2.443V     1.984V
174.1ns   1.927V     2.248V     1.081V
218.3ns   1.552V     2.066V     171.8mV
232.5ns   1.429V     2.003V     92.09mV
355.1ns   151.9mV    1.441V     45.73mV
580.1ns   56.85mV    178.5mV    45.49mV
1.25us    56.7mV     75.16mV    45.5mV
[Falling Waveform]
R_fixture = 1.066k
V_fixture = 2.75
V_fixture_min = 2.475
V_fixture_max = 3.025
0s        2.749V     2.476V     3.025V
32.08ns   2.77V      2.487V     3.048V
58.84ns   2.743V     2.487V     2.789V
115ns     2.408V     2.443V     1.984V
174.1ns   1.927V     2.248V     1.081V
218.3ns   1.552V     2.066V     171.8mV
232.5ns   1.429V     2.003V     92.09mV
355.1ns   151.9mV    1.441V     45.73mV
580.1ns   56.85mV    178.5mV    45.49mV
1.25us    56.7mV     75.16mV    45.5mV
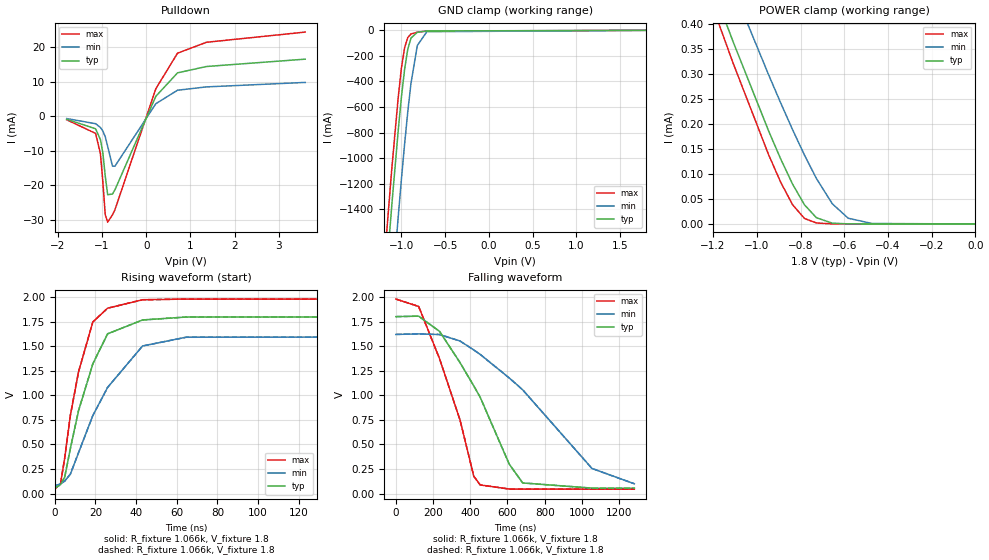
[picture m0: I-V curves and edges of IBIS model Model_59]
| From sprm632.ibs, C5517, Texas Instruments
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| Model based on original model for BI2C33S
|   Sub model BI2C33S_COM_1P8
[model]   Model_59
|[Description]  [1.8V-I/O_OPEN_DRAIN-X-X]
|   , ,
|[Input Load]
|[Output Drive]
|Voltage   1.8V
|Mode   I/O_OPEN_DRAIN
Model_type   I/O_open_drain
Polarity   Non-Inverting
Enable   Active-Low
Vinl =  0.54
Vinh =  1.26
Cref =  400pF
Rref =  528
Vref =  1.8V
Vmeas =  0.9
C_comp   2.8681659p   2.448919p   3.528561p
[Model Spec]
Vinl   0.54   0.486   0.594
Vinh   1.26   1.134   1.386
[Temperature Range]   25   105   -10
[Voltage Range]   1.8   1.62   1.98
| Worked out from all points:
|   slope of the pulldown table from 0 to 0.27 V, typ, clamps not added: 39.3 ohm
|   GND clamp passes 1 mA (typ) near -0.59 V on its own axis
|   POWER clamp passes 1 mA (typ) near -1.65 V on its own axis
|   rising waveform, R_fixture 1.066k, V_fixture 1.8: 20-80 % time 14ns typ, 22.1ns min, 10.5ns max; typ from 0.055 V to 1.8 V
|   rising waveform, R_fixture 1.066k, V_fixture 1.8: 20-80 % time 14ns typ, 22.1ns min, 10.5ns max; typ from 0.055 V to 1.8 V
|   falling waveform, R_fixture 1.066k, V_fixture 1.8: 20-80 % time 284ns typ, 474ns min, 195ns max; typ from 1.8 V to 0.055 V
|   falling waveform, R_fixture 1.066k, V_fixture 1.8: 20-80 % time 284ns typ, 474ns min, 195ns max; typ from 1.8 V to 0.055 V
[POWER_clamp]
-1.8V     1.182mA    1.244mA    1.174mA
-1.382V   682uA      771.8uA    652.3uA
-1.109V   365.2uA    471.4uA    322.4uA
-945.5mV  185.6uA    297.9uA    138uA
-890.9mV  130.2uA    242.3uA    83.62uA
-836.4mV  79.72uA    188.5uA    38.51uA
-781.8mV  38.22uA    137.6uA    10.92uA
-727.3mV  12.39uA    90.87uA    1.955uA
-654.5mV  1.597uA    40.28uA    115.1nA
-581.8mV  126.1nA    11.43uA    5.445nA
-472.7mV  2.356nA    882.5nA    253.2pA
0V        145.8pA    2.241nA    125pA
[Pulldown]
-1.8V     -881.4uA   -683.4uA   -1.029mA
-1.145V   -3.654mA   -2.172mA   -4.984mA
-1.036V   -6.797mA   -3.273mA   -10.89mA
-981.8mV  -10.61mA   -4.286mA   -19mA
-927.3mV  -17.3mA    -5.958mA   -28.54mA
-872.7mV  -22.74mA   -8.73mA    -30.7mA
-763.6mV  -22.55mA   -14.45mA   -28.57mA
-709.1mV  -21.35mA   -14.49mA   -27.12mA
218.2mV   5.772mA    3.625mA    7.966mA
709.1mV   12.56mA    7.529mA    18.26mA
1.364V    14.4mA     8.495mA    21.42mA
3.6V      16.53mA    9.79mA     24.37mA
[GND_clamp]
-1.8V     -7.817A    -8.514A    -7.537A
-1.182V   -1.99A     -2.707A    -1.697A
-1.145V   -1.671A    -2.385A    -1.381A
-1.109V   -1.361A    -2.068A    -1.076A
-1.036V   -780.4mA   -1.456A    -520.9mA
-1V       -522.9mA   -1.166A    -295.7mA
-963.6mV  -305.6mA   -891mA     -136.9mA
-927.3mV  -147.7mA   -638.1mA   -56.43mA
-890.9mV  -60.89mA   -416.5mA   -28.54mA
-818.2mV  -14.95mA   -118.8mA   -14.61mA
-709.1mV  -5.062mA   -10.78mA   -5.866mA
1.8V      145.8pA    2.669nA    100.1pA
[Ramp]
dV/dt_f 0.42259796/0.43036367u 0.25071431/0.66026222u 0.60794538/0.30801606u
dV/dt_r 4.0438561m/4.9469654n 2.5389088m/5.1883782n 5.2583574m/3.819664n
R_load = 50
[Rising Waveform]
R_fixture = 1.066k
V_fixture = 1.8
V_fixture_min = 1.62
V_fixture_max = 1.98
0s        54.61mV    77.38mV    44.63mV
2.851ns   90.7mV     98.44mV    103.8mV
4.865ns   166.1mV    126.8mV    359mV
7.684ns   460.5mV    198.4mV    797.9mV
11.66ns   842.2mV    414.9mV    1.238V
18.73ns   1.322V     794.8mV    1.748V
25.98ns   1.627V     1.081V     1.888V
43.18ns   1.768V     1.503V     1.974V
64.52ns   1.798V     1.592V     1.981V
1.282us   1.8V       1.62V      1.98V
[Rising Waveform]
R_fixture = 1.066k
V_fixture = 1.8
V_fixture_min = 1.62
V_fixture_max = 1.98
0s        54.61mV    77.38mV    44.63mV
2.851ns   90.7mV     98.44mV    103.8mV
4.865ns   166.1mV    126.8mV    359mV
7.684ns   460.5mV    198.4mV    797.9mV
11.66ns   842.2mV    414.9mV    1.238V
18.73ns   1.322V     794.8mV    1.748V
25.98ns   1.627V     1.081V     1.888V
43.18ns   1.768V     1.503V     1.974V
64.52ns   1.798V     1.592V     1.981V
1.282us   1.8V       1.62V      1.98V
[Falling Waveform]
R_fixture = 1.066k
V_fixture = 1.8
V_fixture_min = 1.62
V_fixture_max = 1.98
0s        1.801V     1.62V      1.98V
122.4ns   1.806V     1.625V     1.905V
234.8ns   1.651V     1.619V     1.373V
344.9ns   1.333V     1.553V     749.1mV
418.8ns   1.096V     1.462V     176.9mV
453ns     981.5mV    1.417V     87.59mV
609.2ns   299.9mV    1.177V     45.81mV
681.7ns   107.7mV    1.056V     44.4mV
1.054us   54.87mV    255.3mV    44.3mV
1.282us   54.84mV    99.15mV    44.3mV
[Falling Waveform]
R_fixture = 1.066k
V_fixture = 1.8
V_fixture_min = 1.62
V_fixture_max = 1.98
0s        1.801V     1.62V      1.98V
122.4ns   1.806V     1.625V     1.905V
234.8ns   1.651V     1.619V     1.373V
344.9ns   1.333V     1.553V     749.1mV
418.8ns   1.096V     1.462V     176.9mV
453ns     981.5mV    1.417V     87.59mV
609.2ns   299.9mV    1.177V     45.81mV
681.7ns   107.7mV    1.056V     44.4mV
1.054us   54.87mV    255.3mV    44.3mV
1.282us   54.84mV    99.15mV    44.3mV
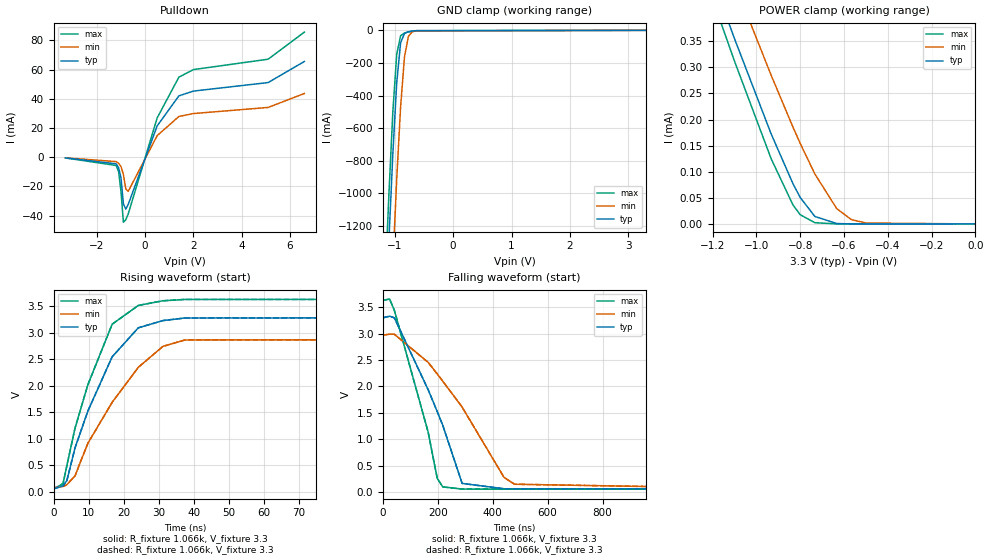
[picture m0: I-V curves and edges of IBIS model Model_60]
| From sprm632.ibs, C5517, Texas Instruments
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| Model based on original model for BI2C33S
|   Sub model BI2C33S_COM_3P3
[model]   Model_60
|[Description]  [3.3V-I/O_OPEN_DRAIN-X-X]
|   , ,
|[Input Load]
|[Output Drive]
|Voltage   3.3V
|Mode   I/O_OPEN_DRAIN
Model_type   I/O_open_drain
Polarity   Non-Inverting
Enable   Active-Low
Vinl =  0.99
Vinh =  2.31
Cref =  400pF
Rref =  528
Vref =  1.8V
Vmeas =  1.65
C_comp   5.420733p   4.3103499p   6.112525p
[Model Spec]
Vinl   0.99   0.891   1.089
Vinh   2.31   2.079   2.541
[Temperature Range]   25   105   -10
[Voltage Range]   3.3   2.97   3.63
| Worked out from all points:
|   slope of the pulldown table from 0 to 0.495 V, typ, clamps not added: 23.3 ohm
|   GND clamp passes 1 mA (typ) near -0.58 V on its own axis
|   POWER clamp passes 1 mA (typ) near -1.65 V on its own axis
|   rising waveform, R_fixture 1.066k, V_fixture 3.3: 20-80 % time 12ns typ, 16.7ns min, 10.2ns max; typ from 0.06 V to 3.3 V
|   rising waveform, R_fixture 1.066k, V_fixture 3.3: 20-80 % time 12ns typ, 16.7ns min, 10.2ns max; typ from 0.06 V to 3.3 V
|   falling waveform, R_fixture 1.066k, V_fixture 3.3: 20-80 % time 148ns typ, 230ns min, 109ns max; typ from 3.3 V to 0.06 V
|   falling waveform, R_fixture 1.066k, V_fixture 3.3: 20-80 % time 148ns typ, 230ns min, 109ns max; typ from 3.3 V to 0.06 V
[POWER_clamp]
-3.3V     3.01mA     2.973mA    3.08mA
-1.233V   508uA      607.1uA    470.9uA
-1.2V     469.3uA    570.4uA    430.6uA
-1.1V     354.9uA    461.5uA    311.7uA
-933.3mV  173uA      285.4uA    125.4uA
-833.3mV  77.13uA    185.6uA    36.43uA
-800mV    50.63uA    154.2uA    17.63uA
-733.3mV  14.35uA    95.78uA    2.414uA
-633.3mV  797.5nA    29.31uA    47.87nA
-566.7mV  72.62nA    8.352uA    3.698nA
-500mV    6.468nA    1.783uA    1.034nA
0V        424.8pA    4.837nA    504.9pA
[Pulldown]
-3.3V     -491.7uA   -431uA     -530.9uA
-1.2V     -4.549mA   -3.03mA    -5.683mA
-1.1V     -7.097mA   -4.151mA   -9.714mA
-1V       -14.06mA   -6.379mA   -23.29mA
-900mV    -32mA      -11.76mA   -44.55mA
-800mV    -35.61mA   -21.73mA   -42.86mA
-700mV    -32.37mA   -23.41mA   -38.94mA
500mV     21.44mA    14.77mA    26.92mA
1.4V      42.03mA    27.89mA    54.85mA
2V        45.3mA     29.9mA     60.03mA
5.1V      51.15mA    34.1mA     67.16mA
6.6V      65.61mA    43.66mA    85.74mA
[GND_clamp]
-3.3V     -22.54A    -23.19A    -22.29A
-1.167V   -1.856A    -2.572A    -1.565A
-1.1V     -1.285A    -1.99A     -1.002A
-1.033V   -757.8mA   -1.431A    -500.3mA
-966.7mV  -321.8mA   -913.2mA   -147.1mA
-900mV    -76.15mA   -468.2mA   -32.69mA
-833.3mV  -18.52mA   -162.2mA   -16.31mA
-766.7mV  -8.727mA   -36.93mA   -9.941mA
-700mV    -4.606mA   -9.113mA   -5.321mA
-633.3mV  -2.034mA   -3.26mA    -2.228mA
3.3V      424.8pA    19.83nA    352.5pA
[Ramp]
dV/dt_f  1.2155625/0.21931859u 0.86086144/0.35818075u  1.4891517/0.15408997u
dV/dt_r  7.759621m/3.2871061n 5.3557038m/3.0387533n 9.1190037m/2.9130284n
R_load = 50
[Rising Waveform]
R_fixture = 1.066k
V_fixture = 3.3
V_fixture_min = 2.97
V_fixture_max = 3.63
0s        60.34mV    77.61mV    52.9mV
2.713ns   113.2mV    104.3mV    158.2mV
3.807ns   215.3mV    136.8mV    496.3mV
6.122ns   827.7mV    303.4mV    1.199V
9.788ns   1.521V     915.9mV    2.017V
16.72ns   2.543V     1.686V     3.157V
24.18ns   3.089V     2.346V     3.51V
31.22ns   3.225V     2.74V      3.598V
37.48ns   3.274V     2.86V      3.623V
1.25us    3.3V       2.97V      3.63V
[Rising Waveform]
R_fixture = 1.066k
V_fixture = 3.3
V_fixture_min = 2.97
V_fixture_max = 3.63
0s        60.34mV    77.61mV    52.9mV
2.713ns   113.2mV    104.3mV    158.2mV
3.807ns   215.3mV    136.8mV    496.3mV
6.122ns   827.7mV    303.4mV    1.199V
9.788ns   1.521V     915.9mV    2.017V
16.72ns   2.543V     1.686V     3.157V
24.18ns   3.089V     2.346V     3.51V
31.22ns   3.225V     2.74V      3.598V
37.48ns   3.274V     2.86V      3.623V
1.25us    3.3V       2.97V      3.63V
[Falling Waveform]
R_fixture = 1.066k
V_fixture = 3.3
V_fixture_min = 2.97
V_fixture_max = 3.63
0s        3.299V     2.971V     3.63V
23.85ns   3.328V     2.988V     3.653V
41.05ns   3.298V     2.987V     3.441V
164.4ns   1.935V     2.454V     1.131V
197.3ns   1.524V     2.236V     259.1mV
217.6ns   1.261V     2.097V     96.62mV
288.2ns   162.2mV    1.607V     55.54mV
440.9ns   60.9mV     276.4mV    53.48mV
479ns     60.37mV    146.9mV    53.48mV
1.25us    60.23mV    77.7mV     53.49mV
[Falling Waveform]
R_fixture = 1.066k
V_fixture = 3.3
V_fixture_min = 2.97
V_fixture_max = 3.63
0s        3.299V     2.971V     3.63V
23.85ns   3.328V     2.988V     3.653V
41.05ns   3.298V     2.987V     3.441V
164.4ns   1.935V     2.454V     1.131V
197.3ns   1.524V     2.236V     259.1mV
217.6ns   1.261V     2.097V     96.62mV
288.2ns   162.2mV    1.607V     55.54mV
440.9ns   60.9mV     276.4mV    53.48mV
479ns     60.37mV    146.9mV    53.48mV
1.25us    60.23mV    77.7mV     53.49mV
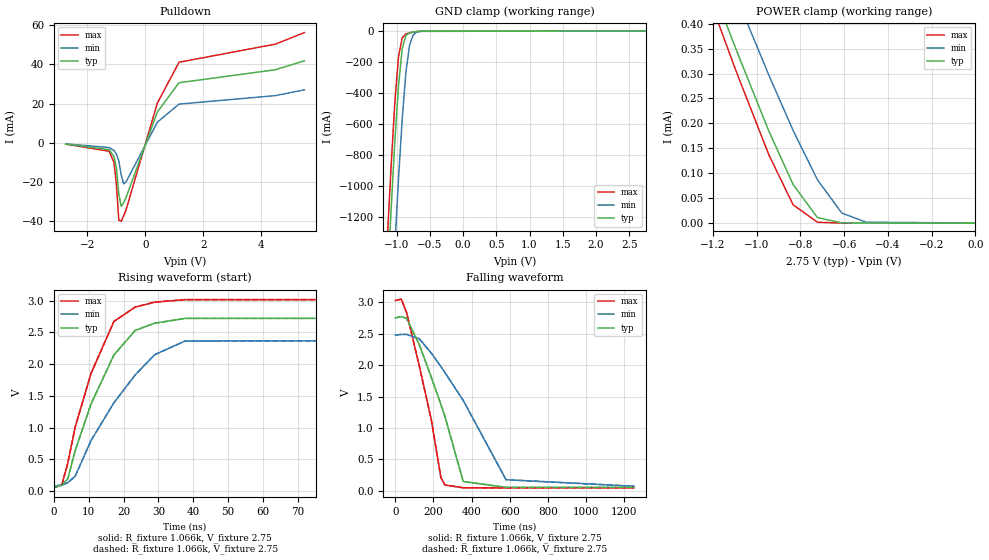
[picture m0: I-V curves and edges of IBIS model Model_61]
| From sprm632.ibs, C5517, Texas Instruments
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| Model based on original model for BI2C33S
|   Sub model BI2C33S_COM_2P75
[model]   Model_61
|[Description]  [2.75V-I/O_OPEN_DRAIN-X-X]
|   , ,
|[Input Load]
|[Output Drive]
|Voltage   2.75V
|Mode   I/O_OPEN_DRAIN
Model_type   I/O_open_drain
Polarity   Non-Inverting
Enable   Active-Low
Vinl =  0.825
Vinh =  1.925
Cref =  400pF
Rref =  528
Vref =  1.8V
Vmeas =  1.375
C_comp   4.5968371p   3.681855p   6.112525p
[Model Spec]
Vinl   0.825   0.7425   0.9075
Vinh   1.925   1.7325   2.1175
[Temperature Range]   25   105   -10
[Voltage Range]   2.75   2.475   3.025
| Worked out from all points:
|   slope of the pulldown table from 0 to 0.412 V, typ, clamps not added: 26.3 ohm
|   GND clamp passes 1 mA (typ) near -0.59 V on its own axis
|   POWER clamp passes 1 mA (typ) near -1.65 V on its own axis
|   rising waveform, R_fixture 1.066k, V_fixture 2.75: 20-80 % time 12ns typ, 17.3ns min, 9.95ns max; typ from 0.058 V to 2.75 V
|   rising waveform, R_fixture 1.066k, V_fixture 2.75: 20-80 % time 12ns typ, 17.3ns min, 9.95ns max; typ from 0.058 V to 2.75 V
|   falling waveform, R_fixture 1.066k, V_fixture 2.75: 20-80 % time 174ns typ, 278ns min, 126ns max; typ from 2.75 V to 0.057 V
|   falling waveform, R_fixture 1.066k, V_fixture 2.75: 20-80 % time 174ns typ, 278ns min, 126ns max; typ from 2.75 V to 0.057 V
[POWER_clamp]
-2.75V    2.337mA    2.336mA    2.378mA
-1.25V    527.3uA    625.5uA    491.1uA
-1.222V   495.1uA    594.8uA    457.4uA
-1.194V   462.9uA    564.3uA    424uA
-1.111V   367.5uA    473.6uA    324.8uA
-1.083V   336.1uA    443.6uA    292.2uA
-944.4mV  184.5uA    296.8uA    137uA
-833.3mV  77.13uA    185.6uA    36.43uA
-722.2mV  10.92uA    86.84uA    1.637uA
-611.1mV  365.5nA    20.06uA    18.58nA
-500mV    6.261nA    1.781uA    640pA
0V        287.9pA    3.669nA    288.1pA
[Pulldown]
-2.75V    -572.6uA   -486.7uA   -630.7uA
-1.25V    -3.416mA   -2.329mA   -4.219mA
-1.083V   -6.943mA   -3.866mA   -9.875mA
-1V       -12.52mA   -5.582mA   -21.04mA
-916.7mV  -25.86mA   -9.174mA   -39.27mA
-833.3mV  -32.31mA   -16.26mA   -39.96mA
-750mV    -30.53mA   -20.86mA   -37.27mA
-666.7mV  -27.88mA   -19.89mA   -34.15mA
416.7mV   15.79mA    10.59mA    20.33mA
1.167V    30.69mA    19.79mA    41.15mA
4.5V      37.33mA    24.14mA    50.38mA
5.5V      41.87mA    27.08mA    56.28mA
[GND_clamp]
-2.75V    -17.12A    -17.77A    -16.85A
-1.139V   -1.615A    -2.327A    -1.325A
-1.083V   -1.148A    -1.848A    -868.8mA
-1.028V   -716.9mA   -1.386A    -463.3mA
-972.2mV  -352.3mA   -954.2mA   -167.1mA
-916.7mV  -115.4mA   -569.8mA   -44.79mA
-861.1mV  -30.53mA   -267.7mA   -20.4mA
-805.6mV  -12.86mA   -90.47mA   -13.34mA
-750mV    -7.485mA   -25.09mA   -8.649mA
-694.4mV  -4.344mA   -8.305mA   -5.007mA
-638.9mV  -2.198mA   -3.519mA   -2.422mA
2.75V     287.9pA    7.044nA    215.3pA
[Ramp]
dV/dt_f 0.93154451/0.26661324u 0.62590676/0.43139496u  1.1812347/0.18361318u
dV/dt_r 6.7103588m/3.6959526n 4.5345619m/3.8254344n 8.3944496m/3.2714124n
R_load = 50
[Rising Waveform]
R_fixture = 1.066k
V_fixture = 2.75
V_fixture_min = 2.475
V_fixture_max = 3.025
0s        57.7mV     75.25mV    48.48mV
2.327ns   88.86mV    93.12mV    100.3mV
3.981ns   188.1mV    127.9mV    432.9mV
6.114ns   634.5mV    231.9mV    1.005V
10.66ns   1.37V      794.1mV    1.852V
17.22ns   2.143V     1.39V      2.673V
23.35ns   2.532V     1.831V     2.9V
28.92ns   2.645V     2.149V     2.977V
37.63ns   2.721V     2.364V     3.017V
1.25us    2.75V      2.475V     3.025V
[Rising Waveform]
R_fixture = 1.066k
V_fixture = 2.75
V_fixture_min = 2.475
V_fixture_max = 3.025
0s        57.7mV     75.25mV    48.48mV
2.327ns   88.86mV    93.12mV    100.3mV
3.981ns   188.1mV    127.9mV    432.9mV
6.114ns   634.5mV    231.9mV    1.005V
10.66ns   1.37V      794.1mV    1.852V
17.22ns   2.143V     1.39V      2.673V
23.35ns   2.532V     1.831V     2.9V
28.92ns   2.645V     2.149V     2.977V
37.63ns   2.721V     2.364V     3.017V
1.25us    2.75V      2.475V     3.025V
[Falling Waveform]
R_fixture = 1.066k
V_fixture = 2.75
V_fixture_min = 2.475
V_fixture_max = 3.025
0s        2.749V     2.475V     3.025V
31.42ns   2.77V      2.487V     3.047V
59.35ns   2.741V     2.487V     2.83V
125.8ns   2.323V     2.417V     1.983V
188.6ns   1.805V     2.189V     1.128V
238.8ns   1.374V     1.976V     211.6mV
259.7ns   1.186V     1.882V     94.62mV
355.5ns   150.6mV    1.439V     50.54mV
580ns     56.85mV    178.6mV    49.13mV
1.25us    56.7mV     75.16mV    49.13mV
[Falling Waveform]
R_fixture = 1.066k
V_fixture = 2.75
V_fixture_min = 2.475
V_fixture_max = 3.025
0s        2.749V     2.475V     3.025V
31.42ns   2.77V      2.487V     3.047V
59.35ns   2.741V     2.487V     2.83V
125.8ns   2.323V     2.417V     1.983V
188.6ns   1.805V     2.189V     1.128V
238.8ns   1.374V     1.976V     211.6mV
259.7ns   1.186V     1.882V     94.62mV
355.5ns   150.6mV    1.439V     50.54mV
580ns     56.85mV    178.6mV    49.13mV
1.25us    56.7mV     75.16mV    49.13mV
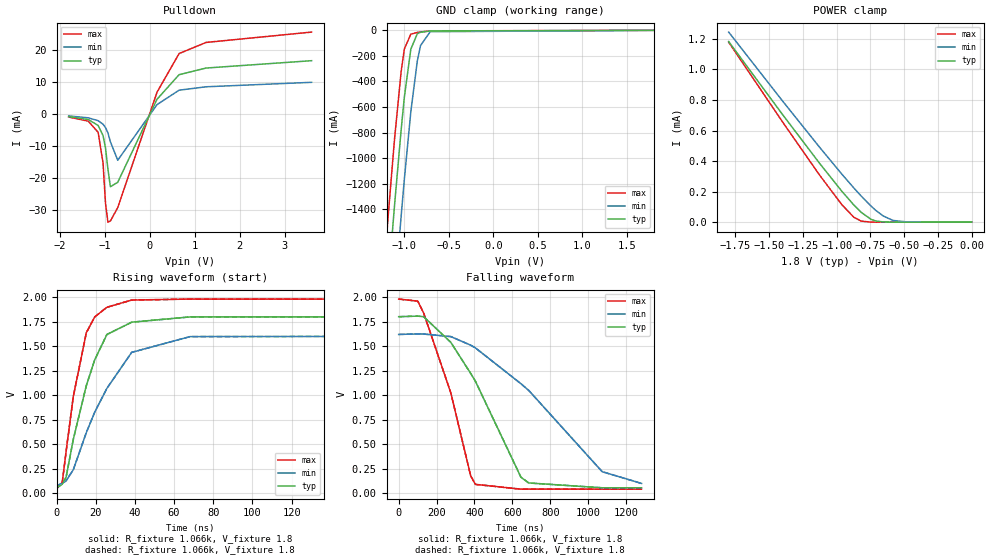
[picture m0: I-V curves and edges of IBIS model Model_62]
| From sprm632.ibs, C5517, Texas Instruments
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| Model based on original model for BI2C33S
|   Sub model BI2C33S_IND_1P8
[model]   Model_62
|[Description]  [1.8V-I/O_OPEN_DRAIN-X-X]
|   , ,
|[Input Load]
|[Output Drive]
|Voltage   1.8V
|Mode   I/O_OPEN_DRAIN
Model_type   I/O_open_drain
Polarity   Non-Inverting
Enable   Active-Low
Vinl =  0.54
Vinh =  1.26
Cref =  400pF
Rref =  528
Vref =  1.8V
Vmeas =  0.9
C_comp   2.8681659p   2.448919p   3.528561p
[Model Spec]
Vinl   0.54   0.486   0.594
Vinh   1.26   1.134   1.386
[Temperature Range]   25   105   -40
[Voltage Range]   1.8   1.62   1.98
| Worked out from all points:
|   slope of the pulldown table from 0 to 0.27 V, typ, clamps not added: 39.3 ohm
|   GND clamp passes 1 mA (typ) near -0.59 V on its own axis
|   POWER clamp passes 1 mA (typ) near -1.65 V on its own axis
|   rising waveform, R_fixture 1.066k, V_fixture 1.8: 20-80 % time 14ns typ, 22ns min, 9.7ns max; typ from 0.055 V to 1.8 V
|   rising waveform, R_fixture 1.066k, V_fixture 1.8: 20-80 % time 14ns typ, 22ns min, 9.7ns max; typ from 0.055 V to 1.8 V
|   falling waveform, R_fixture 1.066k, V_fixture 1.8: 20-80 % time 284ns typ, 472ns min, 174ns max; typ from 1.8 V to 0.055 V
|   falling waveform, R_fixture 1.066k, V_fixture 1.8: 20-80 % time 284ns typ, 472ns min, 174ns max; typ from 1.8 V to 0.055 V
[POWER_clamp]
-1.8V     1.182mA    1.244mA    1.178mA
-1.4V     703.5uA    792.2uA    655uA
-1.127V   385.9uA    491.1uA    308.9uA
-963.6mV  204.7uA    316.7uA    116.7uA
-872.7mV  112.7uA    224.1uA    32.5uA
-818.2mV  64.58uA    171.2uA    7.141uA
-745.5mV  18.95uA    105.8uA    415nA
-709.1mV  7.749uA    76.67uA    75.18nA
-654.5mV  1.597uA    40.28uA    5.775nA
-581.8mV  126.1nA    11.43uA    320.8pA
-472.7mV  2.356nA    882.5nA    139.3pA
0V        145.8pA    2.241nA    93.71pA
[Pulldown]
-1.8V     -881.4uA   -683.4uA   -1.022mA
-1.364V   -1.809mA   -1.269mA   -2.315mA
-1.145V   -3.654mA   -2.172mA   -5.789mA
-1.036V   -6.797mA   -3.273mA   -15.35mA
-981.8mV  -10.61mA   -4.286mA   -27.84mA
-927.3mV  -17.3mA    -5.958mA   -33.79mA
-872.7mV  -22.74mA   -8.73mA    -33.42mA
-709.1mV  -21.35mA   -14.49mA   -29.23mA
163.6mV   4.505mA    2.839mA    6.699mA
654.5mV   12.17mA    7.339mA    18.75mA
1.255V    14.24mA    8.398mA    22.22mA
3.6V      16.53mA    9.79mA     25.44mA
[GND_clamp]
-1.8V     -7.817A    -8.514A    -7.311A
-1.218V   -2.314A    -3.033A    -1.78A
-1.182V   -1.99A     -2.707A    -1.458A
-1.145V   -1.671A    -2.385A    -1.144A
-1.109V   -1.361A    -2.068A    -844mA
-1.036V   -780.4mA   -1.456A    -323.7mA
-1V       -522.9mA   -1.166A    -146.1mA
-927.3mV  -147.7mA   -638.1mA   -29.9mA
-854.5mV  -26.84mA   -240mA     -16.5mA
-818.2mV  -14.95mA   -118.8mA   -12.8mA
-709.1mV  -5.062mA   -10.78mA   -4.451mA
1.8V      145.8pA    2.669nA    76.4pA
[Ramp]
dV/dt_f 0.42260034/0.43053512u 0.25071254/0.66043227u 0.63508671/0.27478397u
dV/dt_r 4.0431844m/4.9468427n 2.5386057m/5.1854082n 5.9428236m/3.9720284n
R_load = 50
[Rising Waveform]
R_fixture = 1.066k
V_fixture = 1.8
V_fixture_min = 1.62
V_fixture_max = 1.98
0s        54.6mV     77.38mV    40.78mV
2.914ns   90.81mV    98.5mV     111.3mV
4.907ns   165.1mV    126.5mV    428.1mV
8.55ns    548.2mV    238.4mV    985.2mV
15.2ns    1.097V     617.8mV    1.637V
19.47ns   1.36V      825.7mV    1.798V
25.69ns   1.619V     1.069V     1.897V
38.36ns   1.745V     1.437V     1.971V
68.19ns   1.799V     1.598V     1.981V
1.282us   1.8V       1.62V      1.98V
[Rising Waveform]
R_fixture = 1.066k
V_fixture = 1.8
V_fixture_min = 1.62
V_fixture_max = 1.98
0s        54.6mV     77.38mV    40.78mV
2.914ns   90.81mV    98.5mV     111.3mV
4.907ns   165.1mV    126.5mV    428.1mV
8.55ns    548.2mV    238.4mV    985.2mV
15.2ns    1.097V     617.8mV    1.637V
19.47ns   1.36V      825.7mV    1.798V
25.69ns   1.619V     1.069V     1.897V
38.36ns   1.745V     1.437V     1.971V
68.19ns   1.799V     1.598V     1.981V
1.282us   1.8V       1.62V      1.98V
[Falling Waveform]
R_fixture = 1.066k
V_fixture = 1.8
V_fixture_min = 1.62
V_fixture_max = 1.98
0s        1.801V     1.62V      1.981V
100.8ns   1.807V     1.625V     1.96V
131.8ns   1.801V     1.624V     1.839V
275.3ns   1.539V     1.598V     1.023V
380.3ns   1.221V     1.51V      174.7mV
405.3ns   1.141V     1.482V     89.58mV
645.1ns   163.3mV    1.117V     40.79mV
686.1ns   104.1mV    1.049V     40.74mV
1.074us   54.88mV    219.1mV    40.78mV
1.282us   54.84mV    98.97mV    40.78mV
[Falling Waveform]
R_fixture = 1.066k
V_fixture = 1.8
V_fixture_min = 1.62
V_fixture_max = 1.98
0s        1.801V     1.62V      1.981V
100.8ns   1.807V     1.625V     1.96V
131.8ns   1.801V     1.624V     1.839V
275.3ns   1.539V     1.598V     1.023V
380.3ns   1.221V     1.51V      174.7mV
405.3ns   1.141V     1.482V     89.58mV
645.1ns   163.3mV    1.117V     40.79mV
686.1ns   104.1mV    1.049V     40.74mV
1.074us   54.88mV    219.1mV    40.78mV
1.282us   54.84mV    98.97mV    40.78mV
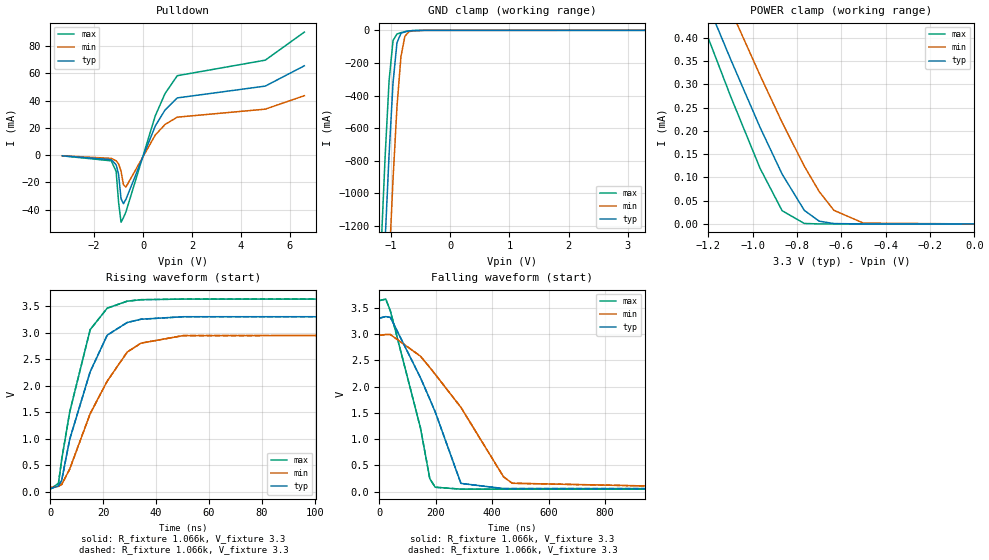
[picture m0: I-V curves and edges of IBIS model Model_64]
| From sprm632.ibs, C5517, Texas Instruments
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| Model based on original model for BI2C33S
|   Sub model BI2C33S_IND_3P3
[model]   Model_64
|[Description]  [3.3V-I/O_OPEN_DRAIN-X-X]
|   , ,
|[Input Load]
|[Output Drive]
|Voltage   3.3V
|Mode   I/O_OPEN_DRAIN
Model_type   I/O_open_drain
Polarity   Non-Inverting
Enable   Active-Low
Vinl =  0.99
Vinh =  2.31
Cref =  400pF
Rref =  528
Vref =  1.8V
Vmeas =  1.65
C_comp   5.420733p   4.3103499p   6.112525p
[Model Spec]
Vinl   0.99   0.891   1.089
Vinh   2.31   2.079   2.541
[Temperature Range]   25   105   -40
[Voltage Range]   3.3   2.97   3.63
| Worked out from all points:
|   slope of the pulldown table from 0 to 0.495 V, typ, clamps not added: 23.3 ohm
|   GND clamp passes 1 mA (typ) near -0.58 V on its own axis
|   POWER clamp passes 1 mA (typ) near -1.65 V on its own axis
|   rising waveform, R_fixture 1.066k, V_fixture 3.3: 20-80 % time 12ns typ, 16.7ns min, 9.39ns max; typ from 0.06 V to 3.3 V
|   rising waveform, R_fixture 1.066k, V_fixture 3.3: 20-80 % time 12ns typ, 16.7ns min, 9.39ns max; typ from 0.06 V to 3.3 V
|   falling waveform, R_fixture 1.066k, V_fixture 3.3: 20-80 % time 148ns typ, 230ns min, 97.6ns max; typ from 3.3 V to 0.06 V
|   falling waveform, R_fixture 1.066k, V_fixture 3.3: 20-80 % time 148ns typ, 230ns min, 97.6ns max; typ from 3.3 V to 0.06 V
[POWER_clamp]
-3.3V     3.01mA     2.973mA    3.173mA
-1.267V   546.8uA    643.9uA    483.9uA
-1.233V   508uA      607.1uA    441.6uA
-1.2V     469.3uA    570.4uA    399.6uA
-1.1V     354.9uA    461.5uA    275.5uA
-966.7mV  208uA      319.9uA    120uA
-866.7mV  107uA      218.1uA    28.46uA
-766.7mV  29.22uA    124.1uA    1.037uA
-700mV    6.043uA    69.9uA     48.52nA
-633.3mV  797.5nA    29.31uA    2.308nA
-500mV    6.468nA    1.783uA    259.9pA
0V        424.8pA    4.837nA    188.1pA
[Pulldown]
-3.3V     -491.7uA   -431uA     -511.9uA
-1.3V     -3.308mA   -2.372mA   -4.167mA
-1.1V     -7.097mA   -4.151mA   -11.93mA
-1V       -14.06mA   -6.379mA   -34.66mA
-900mV    -32mA      -11.76mA   -49.21mA
-800mV    -35.61mA   -21.73mA   -45.85mA
-700mV    -32.37mA   -23.41mA   -41.66mA
500mV     21.44mA    14.77mA    28.86mA
900mV     33.17mA    22.52mA    45.22mA
1.4V      42.03mA    27.89mA    58.32mA
5V        50.69mA    33.78mA    69.74mA
6.6V      65.61mA    43.66mA    90.35mA
[GND_clamp]
-3.3V     -22.54A    -23.19A    -22.09A
-1.167V   -1.856A    -2.572A    -1.326A
-1.1V     -1.285A    -1.99A     -771.8mA
-1.033V   -757.8mA   -1.431A    -306mA
-966.7mV  -321.8mA   -913.2mA   -62.37mA
-900mV    -76.15mA   -468.2mA   -22.68mA
-833.3mV  -18.52mA   -162.2mA   -14.28mA
-766.7mV  -8.727mA   -36.93mA   -8.354mA
-700mV    -4.606mA   -9.113mA   -3.949mA
-633.3mV  -2.034mA   -3.26mA    -1.335mA
-433.3mV  -35.56uA   -118.7uA   -8.107uA
3.3V      424.8pA    19.83nA    149.6pA
[Ramp]
dV/dt_f  1.2155234/0.2193096u 0.86085827/0.35818615u  1.5315116/0.13647397u
dV/dt_r 7.7625617m/3.2897681n 5.3549404m/3.0371957n  10.01966m/3.0083753n
R_load = 50
[Rising Waveform]
R_fixture = 1.066k
V_fixture = 3.3
V_fixture_min = 2.97
V_fixture_max = 3.63
0s        60.35mV    77.61mV    48.81mV
3.096ns   108.3mV    102mV      159.1mV
4.315ns   216.3mV    137.1mV    606.2mV
7.344ns   988.1mV    427.2mV    1.502V
15.08ns   2.261V     1.471V     3.055V
21.53ns   2.951V     2.085V     3.459V
29.07ns   3.189V     2.631V     3.591V
34.28ns   3.251V     2.8V       3.619V
50.32ns   3.298V     2.943V     3.631V
1.25us    3.3V       2.97V      3.63V
[Rising Waveform]
R_fixture = 1.066k
V_fixture = 3.3
V_fixture_min = 2.97
V_fixture_max = 3.63
0s        60.35mV    77.61mV    48.81mV
3.096ns   108.3mV    102mV      159.1mV
4.315ns   216.3mV    137.1mV    606.2mV
7.344ns   988.1mV    427.2mV    1.502V
15.08ns   2.261V     1.471V     3.055V
21.53ns   2.951V     2.085V     3.459V
29.07ns   3.189V     2.631V     3.591V
34.28ns   3.251V     2.8V       3.619V
50.32ns   3.298V     2.943V     3.631V
1.25us    3.3V       2.97V      3.63V
[Falling Waveform]
R_fixture = 1.066k
V_fixture = 3.3
V_fixture_min = 2.97
V_fixture_max = 3.63
0s        3.299V     2.971V     3.631V
23.16ns   3.328V     2.988V     3.661V
39.55ns   3.312V     2.987V     3.434V
146.1ns   2.166V     2.575V     1.211V
179.1ns   1.758V     2.361V     248.3mV
198.2ns   1.518V     2.232V     86.45mV
289.3ns   159.1mV    1.603V     50.1mV
440.2ns   60.93mV    283.6mV    49.7mV
471.3ns   60.45mV    162.1mV    49.7mV
1.25us    60.23mV    77.7mV     49.71mV
[Falling Waveform]
R_fixture = 1.066k
V_fixture = 3.3
V_fixture_min = 2.97
V_fixture_max = 3.63
0s        3.299V     2.971V     3.631V
23.16ns   3.328V     2.988V     3.661V
39.55ns   3.312V     2.987V     3.434V
146.1ns   2.166V     2.575V     1.211V
179.1ns   1.758V     2.361V     248.3mV
198.2ns   1.518V     2.232V     86.45mV
289.3ns   159.1mV    1.603V     50.1mV
440.2ns   60.93mV    283.6mV    49.7mV
471.3ns   60.45mV    162.1mV    49.7mV
1.25us    60.23mV    77.7mV     49.71mV
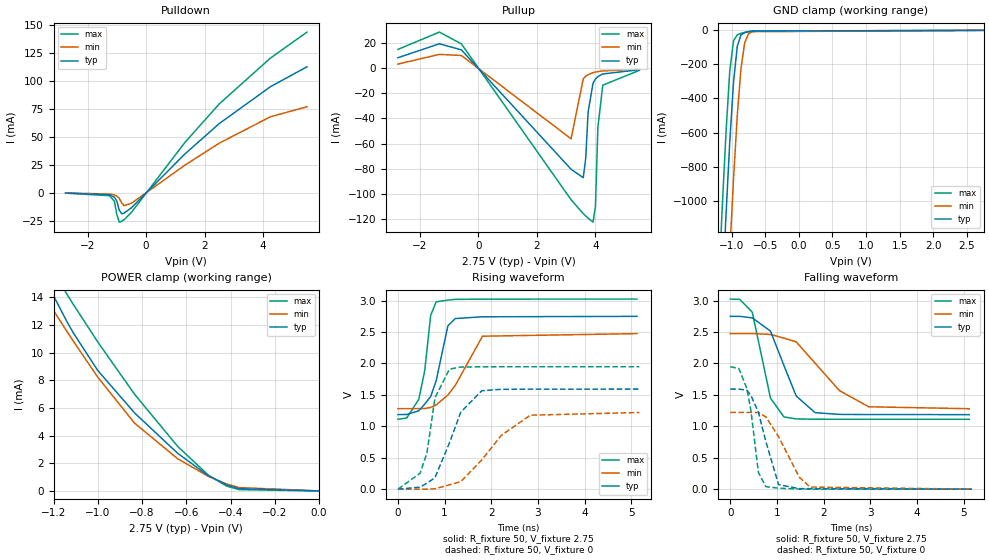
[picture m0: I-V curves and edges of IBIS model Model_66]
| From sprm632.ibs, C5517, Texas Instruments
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| Model based on original model for BC3340CTSCHYPD
|   Sub model SR0_VSS_SR1_VSS_PD_OFF_IND_2P75
[model]   Model_66
|[Description]  [2.75V-I/O-PD_OFF-X, IND]
|   PD_OFF,IND,
|[Input Load]   PD_OFF
|[Output Drive]
|Voltage   2.75V
|Mode   I/O
Model_type   I/O
Polarity   Non-Inverting
Enable   Active-Low
Vinl =  0.7
Vinh =  1.7
Cref =  15.0000pF
Rref =  100.0000M
Vref =  0V
Vmeas =  1.375
C_comp   2.1456989p   2.0494201p   2.2784851p
[Model Spec]
Vinl   0.7   0.7   0.7
Vinh   1.7   1.7   1.7
[Temperature Range]   25   105   -40
[Voltage Range]   2.75   2.475   3.025
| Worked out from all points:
|   slope of the pulldown table from 0 to 0.412 V, typ, clamps not added: 37.1 ohm
|   slope of the pullup table from 0 to 0.412 V, typ, clamps not added: 35.9 ohm
|   GND clamp passes 1 mA (typ) near -0.58 V on its own axis
|   POWER clamp passes 1 mA (typ) near -0.49 V on its own axis
|   rising waveform, R_fixture 50, V_fixture 2.75: 20-80 % time 291ps typ, 508ps min, 206ps max; typ from 1.19 V to 2.75 V
|   rising waveform, R_fixture 50, V_fixture 0: 20-80 % time 498ps typ, 893ps min, 291ps max; typ from 0 V to 1.59 V
|   falling waveform, R_fixture 50, V_fixture 2.75: 20-80 % time 494ps typ, 894ps min, 302ps max; typ from 2.75 V to 1.19 V
|   falling waveform, R_fixture 50, V_fixture 0: 20-80 % time 315ps typ, 495ps min, 206ps max; typ from 1.59 V to 0 V
[POWER_clamp]
-2.75V    68.47mA    53.36mA    82.69mA
-1.25V    15.74mA    14.31mA    17.43mA
-1.194V   13.94mA    12.91mA    15.74mA
-1.139V   12.24mA    11.53mA    14.23mA
-1.111V   11.45mA    10.85mA    13.51mA
-1V       8.713mA    8.23mA     10.78mA
-833.3mV  5.639mA    4.898mA    6.986mA
-638.9mV  2.721mA    2.329mA    3.219mA
-500mV    1.096mA    1.05mA     1.136mA
-416.7mV  423.4uA    494.2uA    344.1uA
-361.1mV  162.2uA    242.3uA    95.25uA
0V        635.3pA    4.99nA     480.7pA
[Pulldown]
-2.75V    -308.5uA   -227.6uA   -349uA
-1.25V    -1.93mA    -1.163mA   -2.672mA
-1.083V   -4.054mA   -1.991mA   -7.636mA
-1V       -7.547mA   -2.954mA   -19.38mA
-916.7mV  -15.6mA    -5.046mA   -26.43mA
-833.3mV  -18.95mA   -9.138mA   -25.59mA
-750mV    -18.23mA   -11.68mA   -24.25mA
-500mV    -13.48mA   -9.45mA    -17.63mA
1.333V    34.87mA    24.79mA    45.26mA
2.5V      61.98mA    44.41mA    79.58mA
4.25V     95.04mA    68.08mA    120.7mA
5.5V      112.9mA    77.06mA    144mA
[Pullup]
-2.75V    8.15mA     3.088mA    14.75mA
-1.333V   19.2mA     10.81mA    28.46mA
-583.3mV  14.38mA    9.918mA    19.15mA
3.167V    -80.24mA   -56.1mA    -104.4mA
3.583V    -86.93mA   -8.662mA   -115.4mA
3.667V    -71.56mA   -6.559mA   -117.3mA
3.75V     -34.81mA   -5.246mA   -119mA
3.917V    -11.98mA   -3.72mA    -122.2mA
4V        -8.724mA   -3.242mA   -109.7mA
4.083V    -6.819mA   -2.87mA    -47.03mA
4.25V     -4.711mA   -2.331mA   -13.63mA
5.5V      -1.388mA   -959.6uA   -1.855mA
[GND_clamp]
-2.75V    -17.03A    -17.67A    -16.58A
-1.194V   -2.025A    -2.722A    -1.509A
-1.139V   -1.54A     -2.231A    -1.032A
-1.083V   -1.078A    -1.755A    -593.8mA
-1.028V   -655mA     -1.299A    -239.9mA
-972.2mV  -306mA     -874.1mA   -62.01mA
-916.7mV  -94.92mA   -503mA     -26.39mA
-861.1mV  -27.21mA   -223.1mA   -17.99mA
-805.6mV  -13.06mA   -72.23mA   -12.38mA
-750mV    -8.039mA   -21.19mA   -7.734mA
-694.4mV  -4.823mA   -8.017mA   -4.133mA
2.75V     635.3pA    52.4uA     350.4pA
[Ramp]
dV/dt_f 0.95026879/0.49704461n 0.72671017/0.8983314n  1.1606848/0.3060458n
dV/dt_r  0.9576758/0.49872645n 0.73401509/0.89912144n  1.1711293/0.29144816n
R_load = 50
[Rising Waveform]
R_fixture = 50
V_fixture = 2.75
V_fixture_min = 2.475
V_fixture_max = 3.025
0s        1.187V     1.281V     1.113V
186.5ps   1.188V     1.281V     1.131V
448ps     1.248V     1.282V     1.431V
573.5ps   1.353V     1.283V     1.884V
701.5ps   1.474V     1.3V       2.765V
819.3ps   1.726V     1.342V     2.981V
1.07ns    2.599V     1.497V     3.009V
1.229ns   2.715V     1.652V     3.02V
1.811ns   2.743V     2.434V     3.024V
5.12ns    2.75V      2.475V     3.025V
[Rising Waveform]
R_fixture = 50
V_fixture = 0
V_fixture_min = 0
V_fixture_max = 0
0s        0V         0V         0V
475.8ps   32.35mV    0V         254mV
621.5ps   96.46mV    0V         576.9mV
793ps     182.1mV    6.245mV    1.453V
1.104ns   737.2mV    68.99mV    1.91V
1.347ns   1.226V     120.1mV    1.943V
1.795ns   1.566V     463.6mV    1.947V
2.212ns   1.589V     854.3mV    1.948V
2.835ns   1.591V     1.177V     1.948V
5.172ns   1.592V     1.22V      1.948V
[Falling Waveform]
R_fixture = 50
V_fixture = 2.75
V_fixture_min = 2.475
V_fixture_max = 3.025
0s        2.75V      2.476V     3.025V
202.3ps   2.75V      2.476V     3.02V
471.6ps   2.726V     2.476V     2.817V
861.5ps   2.515V     2.462V     1.449V
1.15ns    1.968V     2.403V     1.15V
1.413ns   1.482V     2.344V     1.118V
1.818ns   1.217V     2.004V     1.113V
2.338ns   1.19V      1.569V     1.112V
2.966ns   1.187V     1.311V     1.112V
5.12ns    1.186V     1.28V      1.112V
[Falling Waveform]
R_fixture = 50
V_fixture = 0
V_fixture_min = 0
V_fixture_max = 0
0s        1.592V     1.221V     1.948V
184.3ps   1.592V     1.221V     1.92V
355.9ps   1.575V     1.221V     1.602V
443.7ps   1.488V     1.221V     1.243V
602.6ps   1.225V     1.219V     266.5mV
761.6ps   760.5mV    1.151V     40.61mV
1.035ns   71.93mV    835.9mV    15.82mV
1.479ns   8.071mV    189.8mV    1.904mV
1.711ns   7.855mV    33.3mV     1.06mV
5.172ns   4.608uV    74.27uV    0V
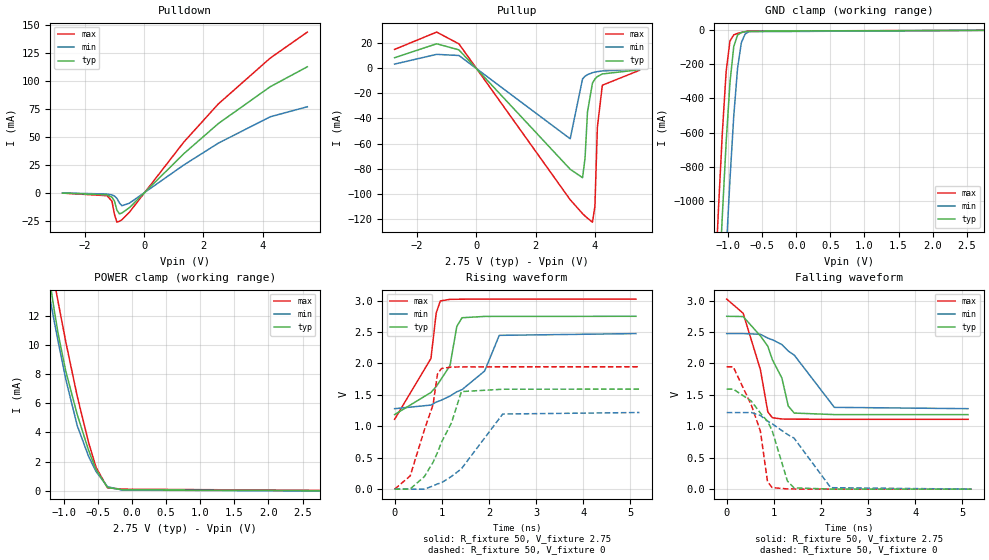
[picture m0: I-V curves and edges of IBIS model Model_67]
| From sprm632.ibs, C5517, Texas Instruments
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| Model based on original model for BC3340CTSCHYPD
|   Sub model SR0_VDD_SR1_VDD_PD_ON_IND_2P75
[model]   Model_67
|[Description]  [2.75V-I/O-PD-X, IND]
|   PD,IND,
|[Input Load]   PD
|[Output Drive]
|Voltage   2.75V
|Mode   I/O
Model_type   I/O
Polarity   Non-Inverting
Enable   Active-Low
Vinl =  0.7
Vinh =  1.7
Cref =  15.0000pF
Rref =  100.0000M
Vref =  0V
Vmeas =  1.375
C_comp   2.1456989p   2.0494201p   2.2784851p
[Model Spec]
Vinl   0.7   0.7   0.7
Vinh   1.7   1.7   1.7
[Temperature Range]   25   105   -40
[Voltage Range]   2.75   2.475   3.025
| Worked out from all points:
|   slope of the pulldown table from 0 to 0.412 V, typ, clamps not added: 37.1 ohm
|   slope of the pullup table from 0 to 0.412 V, typ, clamps not added: 35.9 ohm
|   GND clamp passes 1 mA (typ) near -0.57 V on its own axis
|   POWER clamp passes 1 mA (typ) near -0.48 V on its own axis
|   rising waveform, R_fixture 50, V_fixture 2.75: 20-80 % time 563ps typ, 807ps min, 448ps max; typ from 1.19 V to 2.75 V
|   rising waveform, R_fixture 50, V_fixture 0: 20-80 % time 568ps typ, 804ps min, 449ps max; typ from 0 V to 1.59 V
|   falling waveform, R_fixture 50, V_fixture 2.75: 20-80 % time 532ps typ, 786ps min, 400ps max; typ from 2.75 V to 1.19 V
|   falling waveform, R_fixture 50, V_fixture 0: 20-80 % time 553ps typ, 829ps min, 413ps max; typ from 1.59 V to 0 V
[POWER_clamp]
-2.75V    68.54mA    53.4mA     82.8mA
-1.25V    15.8mA     14.35mA    17.53mA
-1.194V   14.01mA    12.94mA    15.84mA
-1.139V   12.31mA    11.56mA    14.33mA
-1.083V   10.75mA    10.21mA    12.92mA
-972.2mV  8.203mA    7.648mA    10.22mA
-805.6mV  5.244mA    4.485mA    6.506mA
-638.9mV  2.782mA    2.364mA    3.323mA
-527.8mV  1.441mA    1.31mA     1.596mA
-361.1mV  223.7uA    277.8uA    199.5uA
-138.9mV  61.83uA    37.73uA    104.2uA
2.75V     -8.84nA    -15.87uA   24.28uA
[Pulldown]
-2.75V    -308.5uA   -227.6uA   -349uA
-1.25V    -1.93mA    -1.163mA   -2.672mA
-1.083V   -4.054mA   -1.991mA   -7.636mA
-1V       -7.547mA   -2.954mA   -19.38mA
-916.7mV  -15.6mA    -5.046mA   -26.43mA
-833.3mV  -18.95mA   -9.139mA   -25.59mA
-750mV    -18.23mA   -11.68mA   -24.25mA
-500mV    -13.48mA   -9.45mA    -17.63mA
1.333V    34.87mA    24.79mA    45.26mA
2.5V      61.98mA    44.41mA    79.58mA
4.25V     95.04mA    68.08mA    120.7mA
5.5V      112.9mA    77.06mA    144mA
[Pullup]
-2.75V    8.15mA     3.088mA    14.75mA
-1.333V   19.2mA     10.81mA    28.46mA
-583.3mV  14.38mA    9.918mA    19.15mA
3.167V    -80.24mA   -56.1mA    -104.4mA
3.583V    -86.93mA   -8.662mA   -115.4mA
3.667V    -71.56mA   -6.559mA   -117.3mA
3.75V     -34.81mA   -5.246mA   -119mA
3.917V    -11.98mA   -3.72mA    -122.2mA
4V        -8.725mA   -3.242mA   -109.7mA
4.083V    -6.819mA   -2.87mA    -47.03mA
4.25V     -4.711mA   -2.331mA   -13.63mA
5.5V      -1.388mA   -959.6uA   -1.855mA
[GND_clamp]
-2.75V    -17.03A    -17.67A    -16.58A
-1.194V   -2.025A    -2.722A    -1.509A
-1.139V   -1.54A     -2.231A    -1.032A
-1.083V   -1.078A    -1.755A    -593.8mA
-1.028V   -655mA     -1.299A    -239.9mA
-972.2mV  -306mA     -874.1mA   -62.06mA
-916.7mV  -94.94mA   -503mA     -26.47mA
-861.1mV  -27.25mA   -223.2mA   -18.07mA
-805.6mV  -13.1mA    -72.24mA   -12.46mA
-750mV    -8.089mA   -21.21mA   -7.808mA
-694.4mV  -4.87mA    -8.039mA   -4.202mA
2.75V     61.47uA    87.87uA    104.1uA
[Ramp]
dV/dt_f 0.94576841/0.53799721n 0.72304935/0.79655509n   1.155337/0.40370883n
dV/dt_r 0.95570429/0.5685351n 0.73243314/0.80575829n  1.1689084/0.44984048n
R_load = 50
[Rising Waveform]
R_fixture = 50
V_fixture = 2.75
V_fixture_min = 2.475
V_fixture_max = 3.025
0s        1.186V     1.28V      1.111V
770.9ps   1.538V     1.337V     2.078V
882.5ps   1.631V     1.385V     2.802V
969.3ps   1.729V     1.408V     2.993V
1.175ns   1.965V     1.481V     3.019V
1.32ns    2.59V      1.549V     3.02V
1.431ns   2.726V     1.583V     3.021V
1.91ns    2.747V     1.879V     3.022V
2.22ns    2.747V     2.446V     3.023V
5.12ns    2.749V     2.474V     3.023V
[Rising Waveform]
R_fixture = 50
V_fixture = 0
V_fixture_min = 0
V_fixture_max = 0
0s        0V         0V         0V
330.9ps   2.599mV    0V         210.7mV
630.7ps   199.7mV    0V         941.1mV
816.4ps   428.3mV    51.51mV    1.345V
909.8ps   583.4mV    83.54mV    1.831V
996ps     748.8mV    102.2mV    1.92V
1.207ns   1.055V     203.2mV    1.941V
1.417ns   1.552V     323.8mV    1.944V
2.293ns   1.589V     1.195V     1.946V
5.193ns   1.591V     1.219V     1.946V
[Falling Waveform]
R_fixture = 50
V_fixture = 2.75
V_fixture_min = 2.475
V_fixture_max = 3.025
0s        2.749V     2.474V     3.023V
349.2ps   2.745V     2.474V     2.797V
714.8ps   2.437V     2.463V     1.902V
872.7ps   2.272V     2.402V     1.229V
969.2ps   2.059V     2.376V     1.136V
1.171ns   1.767V     2.299V     1.116V
1.307ns   1.32V      2.196V     1.114V
1.433ns   1.21V      2.132V     1.113V
2.284ns   1.186V     1.301V     1.111V
5.12ns    1.185V     1.28V      1.111V
[Falling Waveform]
R_fixture = 50
V_fixture = 0
V_fixture_min = 0
V_fixture_max = 0
0s        1.591V     1.218V     1.946V
138ps     1.591V     1.218V     1.946V
521.8ps   1.401V     1.218V     1.339V
715ps     1.21V      1.173V     923.6mV
866.5ps   1.079V     1.082V     117.2mV
965.2ps   929.6mV    1.04V      24.5mV
1.288ns   129.5mV    870.8mV    3.901mV
1.429ns   20.84mV    811.8mV    2.908mV
2.207ns   1.748mV    23.41mV    692.1uV
5.193ns   12.25uV    158.9uV    0V
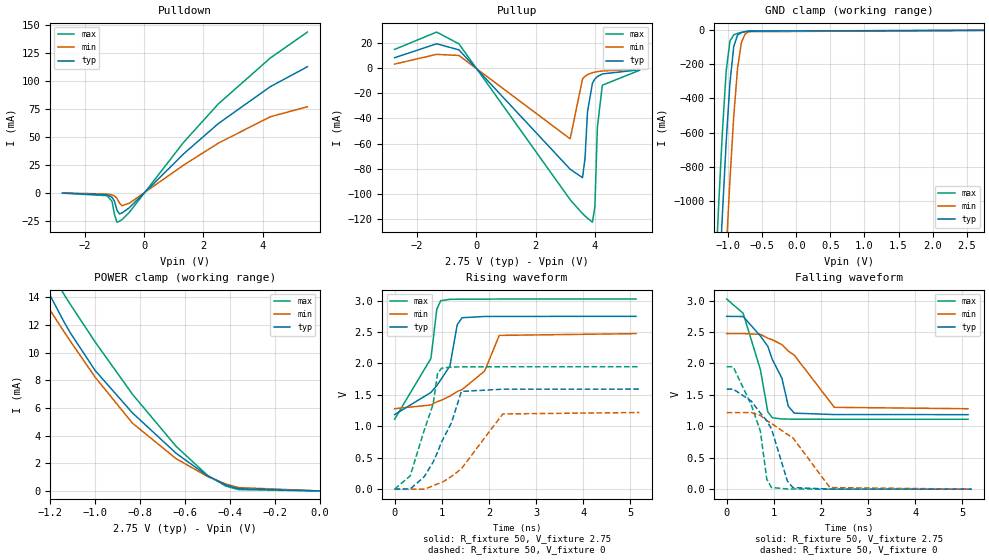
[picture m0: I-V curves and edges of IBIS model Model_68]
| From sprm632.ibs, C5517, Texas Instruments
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| Model based on original model for BC3340CTSCHYPD
|   Sub model SR0_VDD_SR1_VDD_PD_OFF_IND_2P75
[model]   Model_68
|[Description]  [2.75V-I/O-PD_OFF-X, IND]
|   PD_OFF,IND,
|[Input Load]   PD_OFF
|[Output Drive]
|Voltage   2.75V
|Mode   I/O
Model_type   I/O
Polarity   Non-Inverting
Enable   Active-Low
Vinl =  0.7
Vinh =  1.7
Cref =  15.0000pF
Rref =  100.0000M
Vref =  0V
Vmeas =  1.375
C_comp   2.1456989p   2.0494201p   2.2784851p
[Model Spec]
Vinl   0.7   0.7   0.7
Vinh   1.7   1.7   1.7
[Temperature Range]   25   105   -40
[Voltage Range]   2.75   2.475   3.025
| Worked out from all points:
|   slope of the pulldown table from 0 to 0.412 V, typ, clamps not added: 37.1 ohm
|   slope of the pullup table from 0 to 0.412 V, typ, clamps not added: 35.9 ohm
|   GND clamp passes 1 mA (typ) near -0.58 V on its own axis
|   POWER clamp passes 1 mA (typ) near -0.49 V on its own axis
|   rising waveform, R_fixture 50, V_fixture 2.75: 20-80 % time 564ps typ, 808ps min, 449ps max; typ from 1.19 V to 2.75 V
|   rising waveform, R_fixture 50, V_fixture 0: 20-80 % time 568ps typ, 804ps min, 450ps max; typ from 0 V to 1.59 V
|   falling waveform, R_fixture 50, V_fixture 2.75: 20-80 % time 532ps typ, 786ps min, 400ps max; typ from 2.75 V to 1.19 V
|   falling waveform, R_fixture 50, V_fixture 0: 20-80 % time 553ps typ, 829ps min, 413ps max; typ from 1.59 V to 0 V
[POWER_clamp]
-2.75V    68.47mA    53.36mA    82.69mA
-1.25V    15.74mA    14.31mA    17.43mA
-1.194V   13.94mA    12.91mA    15.74mA
-1.139V   12.24mA    11.53mA    14.23mA
-1.111V   11.45mA    10.85mA    13.51mA
-1V       8.713mA    8.23mA     10.78mA
-833.3mV  5.639mA    4.898mA    6.986mA
-638.9mV  2.721mA    2.329mA    3.219mA
-500mV    1.096mA    1.05mA     1.136mA
-416.7mV  423.4uA    494.2uA    344.1uA
-361.1mV  162.2uA    242.3uA    95.25uA
0V        635.3pA    4.99nA     480.7pA
[Pulldown]
-2.75V    -308.5uA   -227.6uA   -349uA
-1.25V    -1.93mA    -1.163mA   -2.672mA
-1.083V   -4.054mA   -1.991mA   -7.636mA
-1V       -7.547mA   -2.954mA   -19.38mA
-916.7mV  -15.6mA    -5.046mA   -26.43mA
-833.3mV  -18.95mA   -9.138mA   -25.59mA
-750mV    -18.23mA   -11.68mA   -24.25mA
-500mV    -13.48mA   -9.45mA    -17.63mA
1.333V    34.87mA    24.79mA    45.26mA
2.5V      61.98mA    44.41mA    79.58mA
4.25V     95.04mA    68.08mA    120.7mA
5.5V      112.9mA    77.06mA    144mA
[Pullup]
-2.75V    8.15mA     3.088mA    14.75mA
-1.333V   19.2mA     10.81mA    28.46mA
-583.3mV  14.38mA    9.918mA    19.15mA
3.167V    -80.24mA   -56.1mA    -104.4mA
3.583V    -86.93mA   -8.662mA   -115.4mA
3.667V    -71.56mA   -6.559mA   -117.3mA
3.75V     -34.81mA   -5.246mA   -119mA
3.917V    -11.98mA   -3.72mA    -122.2mA
4V        -8.724mA   -3.242mA   -109.7mA
4.083V    -6.819mA   -2.87mA    -47.03mA
4.25V     -4.711mA   -2.331mA   -13.63mA
5.5V      -1.388mA   -959.6uA   -1.855mA
[GND_clamp]
-2.75V    -17.03A    -17.67A    -16.58A
-1.194V   -2.025A    -2.722A    -1.509A
-1.139V   -1.54A     -2.231A    -1.032A
-1.083V   -1.078A    -1.755A    -593.8mA
-1.028V   -655mA     -1.299A    -239.9mA
-972.2mV  -306mA     -874.1mA   -62.01mA
-916.7mV  -94.92mA   -503mA     -26.39mA
-861.1mV  -27.21mA   -223.1mA   -17.99mA
-805.6mV  -13.06mA   -72.23mA   -12.38mA
-750mV    -8.039mA   -21.19mA   -7.734mA
-694.4mV  -4.823mA   -8.017mA   -4.133mA
2.75V     635.3pA    52.4uA     350.4pA
[Ramp]
dV/dt_f 0.94584692/0.53779711n 0.72306174/0.79645226n  1.1555402/0.40346492n
dV/dt_r  0.9564728/0.56868001n 0.73294055/0.80596005n  1.1700271/0.45002512n
R_load = 50
[Rising Waveform]
R_fixture = 50
V_fixture = 2.75
V_fixture_min = 2.475
V_fixture_max = 3.025
0s        1.187V     1.281V     1.113V
770.9ps   1.539V     1.339V     2.081V
894.5ps   1.647V     1.39V      2.862V
977.7ps   1.739V     1.411V     2.999V
1.173ns   1.961V     1.481V     3.021V
1.328ns   2.616V     1.554V     3.022V
1.431ns   2.728V     1.584V     3.023V
1.91ns    2.748V     1.88V      3.024V
2.22ns    2.749V     2.447V     3.025V
5.12ns    2.75V      2.475V     3.025V
[Rising Waveform]
R_fixture = 50
V_fixture = 0
V_fixture_min = 0
V_fixture_max = 0
0s        0V         0V         0V
330.9ps   2.594mV    0V         211.9mV
630.7ps   200.5mV    0V         944.3mV
816.3ps   429.9mV    51.69mV    1.348V
909.8ps   585.3mV    83.92mV    1.836V
995.9ps   751mV      102.6mV    1.924V
1.207ns   1.057V     203.7mV    1.944V
1.417ns   1.555V     324.9mV    1.946V
2.293ns   1.591V     1.197V     1.948V
5.193ns   1.592V     1.22V      1.948V
[Falling Waveform]
R_fixture = 50
V_fixture = 2.75
V_fixture_min = 2.475
V_fixture_max = 3.025
0s        2.75V      2.475V     3.025V
349.2ps   2.747V     2.475V     2.799V
714.8ps   2.438V     2.464V     1.903V
872.7ps   2.273V     2.403V     1.229V
969.2ps   2.061V     2.377V     1.136V
1.171ns   1.768V     2.3V       1.117V
1.307ns   1.32V      2.197V     1.115V
1.433ns   1.21V      2.133V     1.114V
2.284ns   1.187V     1.302V     1.112V
5.12ns    1.186V     1.28V      1.112V
[Falling Waveform]
R_fixture = 50
V_fixture = 0
V_fixture_min = 0
V_fixture_max = 0
0s        1.592V     1.219V     1.948V
138ps     1.592V     1.219V     1.948V
521.8ps   1.402V     1.219V     1.34V
715.1ps   1.21V      1.174V     922.2mV
850.6ps   1.089V     1.091V     157.8mV
950.9ps   957mV      1.046V     26.09mV
1.289ns   126mV      870.7mV    3.197mV
1.403ns   25.33mV    819.8mV    2.506mV
2.189ns   1.458mV    25.39mV    560.7uV
5.193ns   4.655uV    104.4uV    0V
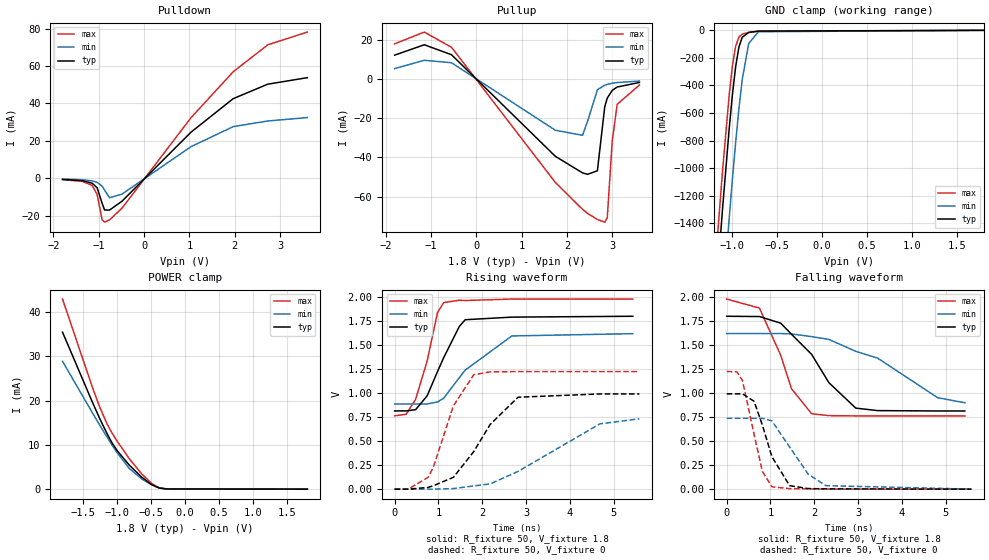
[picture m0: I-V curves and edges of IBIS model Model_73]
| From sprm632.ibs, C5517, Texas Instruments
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| Model based on original model for BC3340CTSCHYPD
|   Sub model SR0_VSS_SR1_VSS_PD_ON_COM_1P8
[model]   Model_73
|[Description]  [1.8V-I/O-PD-X, COM]
|   PD,COM,
|[Input Load]   PD
|[Output Drive]
|Voltage   1.8V
|Mode   I/O
Model_type   I/O
Polarity   Non-Inverting
Enable   Active-Low
Vinl =  0.63
Vinh =  1.17
Cref =  15.0000pF
Rref =  100.0000M
Vref =  0V
Vmeas =  0.9
C_comp   2.213767p   2.135548p   2.3400939p
[Model Spec]
Vinl   0.63   0.567   0.693
Vinh   1.17   1.053   1.287
[Temperature Range]   25   105   -10
[Voltage Range]   1.8   1.62   1.98
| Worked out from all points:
|   slope of the pulldown table from 0 to 0.27 V, typ, clamps not added: 40.2 ohm
|   slope of the pullup table from 0 to 0.27 V, typ, clamps not added: 39.6 ohm
|   GND clamp passes 1 mA (typ) near -0.57 V on its own axis
|   POWER clamp passes 1 mA (typ) near -0.49 V on its own axis
|   rising waveform, R_fixture 50, V_fixture 1.8: 20-80 % time 596ps typ, 941ps min, 388ps max; typ from 0.815 V to 1.8 V
|   rising waveform, R_fixture 50, V_fixture 0: 20-80 % time 1.01ns typ, 1.72ns min, 612ps max; typ from 0 V to 0.991 V
|   falling waveform, R_fixture 50, V_fixture 1.8: 20-80 % time 1.09ns typ, 1.83ns min, 643ps max; typ from 1.8 V to 0.814 V
|   falling waveform, R_fixture 50, V_fixture 0: 20-80 % time 424ps typ, 615ps min, 326ps max; typ from 0.992 V to 0 V
[POWER_clamp]
-1.8V     35.48mA    28.89mA    42.96mA
-1.364V   19.77mA    17.35mA    23.16mA
-1.255V   16.02mA    14.53mA    18.62mA
-1.145V   12.53mA    11.77mA    14.75mA
-1.073V   10.49mA    9.991mA    12.7mA
-1V       8.771mA    8.287mA    10.91mA
-818.2mV  5.427mA    4.679mA    6.879mA
-636.4mV  2.715mA    2.32mA     3.455mA
-490.9mV  1.031mA    994.5uA    1.3mA
-381.8mV  261.4uA    335.8uA    314.2uA
-272.7mV  39.77uA    61.86uA    49.26uA
1.8V      -5.798nA   -5.194uA   8.691uA
[Pulldown]
-1.8V     -609.1uA   -416.1uA   -761.1uA
-1.364V   -1.277mA   -795.9uA   -1.673mA
-1.145V   -2.657mA   -1.407mA   -3.852mA
-1.036V   -5.115mA   -2.184mA   -8.73mA
-927.3mV  -13.32mA   -4.178mA   -22.18mA
-872.7mV  -16.96mA   -6.282mA   -23.48mA
-763.6mV  -17.01mA   -10.42mA   -22.27mA
-490.9mV  -12.33mA   -8.513mA   -16.08mA
1.036V    24.65mA    16.9mA     32.41mA
1.964V    42.51mA    27.58mA    56.87mA
2.727V    50.26mA    30.59mA    71.28mA
3.6V      53.74mA    32.42mA    78.09mA
[Pullup]
-1.8V     12.32mA    5.441mA    18.09mA
-1.145V   17.63mA    9.682mA    24.11mA
-545.5mV  12.54mA    8.453mA    16.36mA
1.745V    -39.39mA   -26.07mA   -52.75mA
2.345V    -47.87mA   -28.67mA   -66.51mA
2.455V    -48.61mA   -21.59mA   -68.56mA
2.673V    -46.79mA   -5.376mA   -71.69mA
2.836V    -13.94mA   -3.011mA   -73.08mA
2.891V    -9.612mA   -2.61mA    -70.75mA
3V        -5.696mA   -2.054mA   -31.66mA
3.109V    -3.979mA   -1.688mA   -12.82mA
3.6V      -1.642mA   -928.2uA   -2.933mA
[GND_clamp]
-1.8V     -7.733A    -8.408A    -7.463A
-1.182V   -1.913A    -2.609A    -1.63A
-1.145V   -1.597A    -2.289A    -1.316A
-1.109V   -1.289A    -1.974A    -1.014A
-1.036V   -716.9mA   -1.367A    -470.3mA
-1V       -467.4mA   -1.081A    -256.9mA
-963.6mV  -262.8mA   -812.5mA   -115.2mA
-927.3mV  -122.1mA   -568.2mA   -49.48mA
-890.9mV  -50.83mA   -358.8mA   -27.66mA
-818.2mV  -14.88mA   -95.25mA   -15.47mA
-709.1mV  -5.604mA   -10.06mA   -6.54mA
1.8V      20.41uA    17.88uA    31.82uA
[Ramp]
dV/dt_f 0.59938764/1.1007705n 0.44655442/1.878138n  0.73966316/0.64704381n
dV/dt_r 0.59723211/1.0086016n 0.44419775/1.7325861n 0.73712685/0.61413097n
R_load = 50
[Rising Waveform]
R_fixture = 50
V_fixture = 1.8
V_fixture_min = 1.62
V_fixture_max = 1.98
0s        814.5mV    886.5mV    763.1mV
263.9ps   814.8mV    886.5mV    779.7mV
479.1ps   827.5mV    886.5mV    934.6mV
743.5ps   972mV      886.5mV    1.335V
980.2ps   1.225V     908mV      1.84V
1.121ns   1.369V     946.9mV    1.942V
1.478ns   1.694V     1.161V     1.967V
1.613ns   1.764V     1.24V      1.964V
2.677ns   1.791V     1.595V     1.979V
5.439ns   1.8V       1.619V     1.979V
[Rising Waveform]
R_fixture = 50
V_fixture = 0
V_fixture_min = 0
V_fixture_max = 0
0s        0V         133.4uV    868.2uV
314.8ps   0V         133.4uV    868.2uV
766.4ps   18.34mV    133.4uV    123.7mV
882.1ps   35.4mV     133.4uV    225.4mV
1.343ns   123.3mV    6.208mV    867.8mV
1.806ns   390.8mV    33.76mV    1.191V
2.181ns   672.9mV    54.8mV     1.221V
2.818ns   957.1mV    184.5mV    1.224V
4.687ns   991.3mV    679.9mV    1.224V
5.59ns    991.4mV    732.5mV    1.224V
[Falling Waveform]
R_fixture = 50
V_fixture = 1.8
V_fixture_min = 1.62
V_fixture_max = 1.98
0s        1.8V       1.62V      1.979V
747.7ps   1.797V     1.62V      1.885V
1.234ns   1.728V     1.62V      1.393V
1.479ns   1.613V     1.616V     1.046V
1.94ns    1.403V     1.588V     785.2mV
2.333ns   1.109V     1.559V     765.5mV
2.947ns   843.7mV    1.435V     762.7mV
3.447ns   817.8mV    1.364V     762.5mV
4.817ns   814mV      952.2mV    762.3mV
5.439ns   813.9mV    899.2mV    762.3mV
[Falling Waveform]
R_fixture = 50
V_fixture = 0
V_fixture_min = 0
V_fixture_max = 0
0s        992.2mV    737.7mV    1.225V
232.3ps   992.2mV    737.7mV    1.221V
361.4ps   992.3mV    737.7mV    1.13V
625.4ps   914.7mV    737.7mV    569.9mV
815.9ps   665.8mV    737.7mV    184.6mV
1.032ns   338.3mV    711.1mV    24.58mV
1.437ns   36.57mV    438.9mV    5.295mV
1.857ns   6.334mV    158.6mV    3.644mV
2.261ns   3.242mV    36.8mV     866.5uV
5.59ns    21.65uV    455.1uV    1.318uV
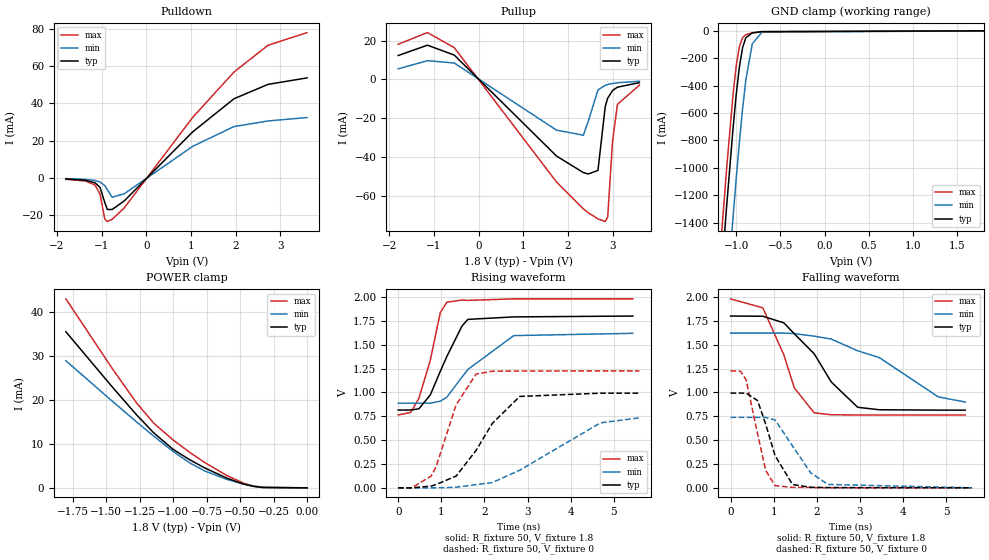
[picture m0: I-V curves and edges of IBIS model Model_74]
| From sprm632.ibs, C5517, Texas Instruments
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| Model based on original model for BC3340CTSCHYPD
|   Sub model SR0_VSS_SR1_VSS_PD_OFF_COM_1P8
[model]   Model_74
|[Description]  [1.8V-I/O-PD_OFF-X, COM]
|   PD_OFF,COM,
|[Input Load]   PD_OFF
|[Output Drive]
|Voltage   1.8V
|Mode   I/O
Model_type   I/O
Polarity   Non-Inverting
Enable   Active-Low
Vinl =  0.63
Vinh =  1.17
Cref =  15.0000pF
Rref =  100.0000M
Vref =  0V
Vmeas =  0.9
C_comp   2.213767p   2.135548p   2.3400939p
[Model Spec]
Vinl   0.63   0.567   0.693
Vinh   1.17   1.053   1.287
[Temperature Range]   25   105   -10
[Voltage Range]   1.8   1.62   1.98
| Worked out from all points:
|   slope of the pulldown table from 0 to 0.27 V, typ, clamps not added: 40.2 ohm
|   slope of the pullup table from 0 to 0.27 V, typ, clamps not added: 39.6 ohm
|   GND clamp passes 1 mA (typ) near -0.58 V on its own axis
|   POWER clamp passes 1 mA (typ) near -0.49 V on its own axis
|   rising waveform, R_fixture 50, V_fixture 1.8: 20-80 % time 596ps typ, 940ps min, 389ps max; typ from 0.815 V to 1.8 V
|   rising waveform, R_fixture 50, V_fixture 0: 20-80 % time 1ns typ, 1.72ns min, 610ps max; typ from 0 V to 0.992 V
|   falling waveform, R_fixture 50, V_fixture 1.8: 20-80 % time 1.09ns typ, 1.83ns min, 642ps max; typ from 1.8 V to 0.814 V
|   falling waveform, R_fixture 50, V_fixture 0: 20-80 % time 422ps typ, 612ps min, 324ps max; typ from 0.993 V to 0 V
[POWER_clamp]
-1.8V     35.46mA    28.87mA    42.93mA
-1.455V   22.97mA    19.72mA    27.15mA
-1.273V   16.61mA    14.99mA    19.31mA
-1.145V   12.51mA    11.76mA    14.72mA
-1V       8.751mA    8.276mA    10.88mA
-872.7mV  6.33mA     5.617mA    8.002mA
-763.6mV  4.531mA    3.848mA    5.75mA
-600mV    2.225mA    1.937mA    2.823mA
-472.7mV  845uA      849.5uA    1.055mA
-400mV    327.9uA    407.8uA    392.6uA
-327.3mV  77.63uA    141.5uA    81.87uA
0V        360.5pA    3.06nA     350.8pA
[Pulldown]
-1.8V     -609.1uA   -416.1uA   -761.1uA
-1.364V   -1.277mA   -795.9uA   -1.673mA
-1.145V   -2.657mA   -1.407mA   -3.852mA
-1.036V   -5.115mA   -2.184mA   -8.73mA
-927.3mV  -13.32mA   -4.178mA   -22.18mA
-872.7mV  -16.96mA   -6.282mA   -23.48mA
-763.6mV  -17.01mA   -10.42mA   -22.27mA
-490.9mV  -12.33mA   -8.513mA   -16.08mA
1.036V    24.65mA    16.9mA     32.41mA
1.964V    42.51mA    27.58mA    56.87mA
2.727V    50.26mA    30.59mA    71.28mA
3.6V      53.74mA    32.42mA    78.09mA
[Pullup]
-1.8V     12.32mA    5.441mA    18.09mA
-1.145V   17.63mA    9.682mA    24.11mA
-545.5mV  12.54mA    8.453mA    16.36mA
1.745V    -39.39mA   -26.07mA   -52.75mA
2.345V    -47.87mA   -28.67mA   -66.51mA
2.455V    -48.61mA   -21.59mA   -68.56mA
2.673V    -46.79mA   -5.376mA   -71.69mA
2.836V    -13.94mA   -3.011mA   -73.08mA
2.891V    -9.612mA   -2.61mA    -70.75mA
3V        -5.696mA   -2.054mA   -31.66mA
3.109V    -3.979mA   -1.688mA   -12.82mA
3.6V      -1.642mA   -928.2uA   -2.933mA
[GND_clamp]
-1.8V     -7.733A    -8.408A    -7.463A
-1.182V   -1.913A    -2.609A    -1.63A
-1.145V   -1.597A    -2.289A    -1.316A
-1.109V   -1.289A    -1.974A    -1.014A
-1.036V   -716.9mA   -1.367A    -470.3mA
-1V       -467.4mA   -1.081A    -256.8mA
-963.6mV  -262.8mA   -812.5mA   -115.2mA
-927.3mV  -122.1mA   -568.2mA   -49.46mA
-890.9mV  -50.82mA   -358.8mA   -27.62mA
-818.2mV  -14.85mA   -95.24mA   -15.42mA
-709.1mV  -5.572mA   -10.04mA   -6.496mA
1.8V      360.5pA    6.236uA    -444pA
[Ramp]
dV/dt_f 0.59939982/1.1002137n 0.44655285/1.8771811n 0.73970998/0.64646052n
dV/dt_r 0.59752652/1.0081047n 0.44440991/1.7331985n 0.73751609/0.61248119n
R_load = 50
[Rising Waveform]
R_fixture = 50
V_fixture = 1.8
V_fixture_min = 1.62
V_fixture_max = 1.98
0s        814.9mV    886.9mV    763.6mV
286.6ps   815.5mV    886.9mV    788.9mV
479.1ps   828mV      886.9mV    936.1mV
743.6ps   973.2mV    886.9mV    1.337V
975.3ps   1.221V     907.4mV    1.836V
1.127ns   1.376V     949.6mV    1.945V
1.477ns   1.694V     1.16V      1.968V
1.613ns   1.765V     1.24V      1.964V
2.677ns   1.791V     1.595V     1.98V
5.439ns   1.8V       1.619V     1.98V
[Rising Waveform]
R_fixture = 50
V_fixture = 0
V_fixture_min = 0
V_fixture_max = 0
0s        0V         137.8uV    866.1uV
314.8ps   0V         137.8uV    866.1uV
766.4ps   18.45mV    137.8uV    124.3mV
882.1ps   35.58mV    137.8uV    226.7mV
1.343ns   123.6mV    6.219mV    871mV
1.806ns   392.8mV    33.88mV    1.192V
2.181ns   675.2mV    54.96mV    1.222V
2.817ns   957.8mV    185mV      1.224V
4.688ns   991.9mV    681mV      1.225V
5.59ns    991.9mV    733mV      1.225V
[Falling Waveform]
R_fixture = 50
V_fixture = 1.8
V_fixture_min = 1.62
V_fixture_max = 1.98
0s        1.8V       1.621V     1.98V
747.7ps   1.798V     1.621V     1.886V
1.234ns   1.729V     1.621V     1.395V
1.479ns   1.614V     1.616V     1.047V
1.94ns    1.404V     1.589V     785.5mV
2.333ns   1.11V      1.559V     766mV
2.947ns   844mV      1.436V     763.2mV
3.447ns   818.2mV    1.365V     763mV
4.817ns   814.4mV    952.5mV    762.9mV
5.439ns   814.3mV    899.5mV    762.9mV
[Falling Waveform]
R_fixture = 50
V_fixture = 0
V_fixture_min = 0
V_fixture_max = 0
0s        992.7mV    738mV      1.226V
232.3ps   992.7mV    738mV      1.221V
361.4ps   992.8mV    738mV      1.131V
625.4ps   915.1mV    738mV      568.4mV
815.6ps   665.9mV    738mV      181.9mV
1.032ns   337mV      711.4mV    22.86mV
1.437ns   35.01mV    438.3mV    4.863mV
1.857ns   5.86mV     157.3mV    3.483mV
2.261ns   3.004mV    35.89mV    733.4uV
5.59ns    6.669uV    413.9uV    0V
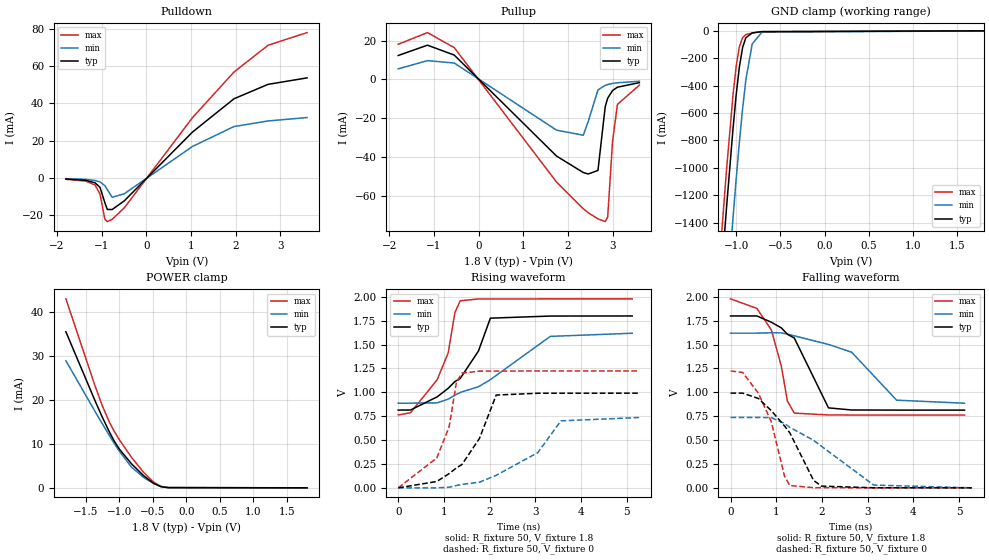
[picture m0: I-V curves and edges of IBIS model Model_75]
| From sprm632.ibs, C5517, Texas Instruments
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| Model based on original model for BC3340CTSCHYPD
|   Sub model SR0_VDD_SR1_VDD_PD_ON_COM_1P8
[model]   Model_75
|[Description]  [1.8V-I/O-PD-X, COM]
|   PD,COM,
|[Input Load]   PD
|[Output Drive]
|Voltage   1.8V
|Mode   I/O
Model_type   I/O
Polarity   Non-Inverting
Enable   Active-Low
Vinl =  0.63
Vinh =  1.17
Cref =  15.0000pF
Rref =  100.0000M
Vref =  0V
Vmeas =  0.9
C_comp   2.213767p   2.135548p   2.3400939p
[Model Spec]
Vinl   0.63   0.567   0.693
Vinh   1.17   1.053   1.287
[Temperature Range]   25   105   -10
[Voltage Range]   1.8   1.62   1.98
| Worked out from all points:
|   slope of the pulldown table from 0 to 0.27 V, typ, clamps not added: 40.2 ohm
|   slope of the pullup table from 0 to 0.27 V, typ, clamps not added: 39.6 ohm
|   GND clamp passes 1 mA (typ) near -0.57 V on its own axis
|   POWER clamp passes 1 mA (typ) near -0.49 V on its own axis
|   rising waveform, R_fixture 50, V_fixture 1.8: 20-80 % time 803ps typ, 1.58ns min, 555ps max; typ from 0.814 V to 1.8 V
|   rising waveform, R_fixture 50, V_fixture 0: 20-80 % time 679ps typ, 1.04ns min, 503ps max; typ from 0 V to 0.991 V
|   falling waveform, R_fixture 50, V_fixture 1.8: 20-80 % time 659ps typ, 1.08ns min, 460ps max; typ from 1.8 V to 0.814 V
|   falling waveform, R_fixture 50, V_fixture 0: 20-80 % time 767ps typ, 1.44ns min, 506ps max; typ from 0.992 V to 0 V
[POWER_clamp]
-1.8V     35.48mA    28.89mA    42.96mA
-1.364V   19.77mA    17.35mA    23.16mA
-1.255V   16.02mA    14.53mA    18.62mA
-1.145V   12.53mA    11.77mA    14.75mA
-1.073V   10.49mA    9.991mA    12.7mA
-1V       8.771mA    8.287mA    10.91mA
-818.2mV  5.427mA    4.679mA    6.879mA
-636.4mV  2.715mA    2.32mA     3.455mA
-490.9mV  1.031mA    994.5uA    1.3mA
-381.8mV  261.4uA    335.8uA    314.2uA
-272.7mV  39.77uA    61.86uA    49.26uA
1.8V      -5.798nA   -5.194uA   8.691uA
[Pulldown]
-1.8V     -609.1uA   -416.1uA   -761.1uA
-1.364V   -1.277mA   -795.9uA   -1.673mA
-1.145V   -2.657mA   -1.407mA   -3.852mA
-1.036V   -5.115mA   -2.184mA   -8.73mA
-927.3mV  -13.32mA   -4.178mA   -22.18mA
-872.7mV  -16.96mA   -6.282mA   -23.48mA
-763.6mV  -17.01mA   -10.42mA   -22.27mA
-490.9mV  -12.33mA   -8.513mA   -16.08mA
1.036V    24.65mA    16.9mA     32.41mA
1.964V    42.51mA    27.58mA    56.87mA
2.727V    50.26mA    30.59mA    71.28mA
3.6V      53.74mA    32.42mA    78.09mA
[Pullup]
-1.8V     12.32mA    5.441mA    18.09mA
-1.145V   17.63mA    9.682mA    24.11mA
-545.5mV  12.54mA    8.453mA    16.36mA
1.745V    -39.39mA   -26.07mA   -52.75mA
2.345V    -47.87mA   -28.67mA   -66.51mA
2.455V    -48.61mA   -21.59mA   -68.56mA
2.673V    -46.79mA   -5.376mA   -71.69mA
2.836V    -13.94mA   -3.011mA   -73.08mA
2.891V    -9.612mA   -2.61mA    -70.75mA
3V        -5.696mA   -2.054mA   -31.66mA
3.109V    -3.979mA   -1.688mA   -12.82mA
3.6V      -1.642mA   -928.2uA   -2.933mA
[GND_clamp]
-1.8V     -7.733A    -8.408A    -7.463A
-1.182V   -1.913A    -2.609A    -1.63A
-1.145V   -1.597A    -2.289A    -1.316A
-1.109V   -1.289A    -1.974A    -1.014A
-1.036V   -716.9mA   -1.367A    -470.3mA
-1V       -467.4mA   -1.081A    -256.9mA
-963.6mV  -262.8mA   -812.5mA   -115.2mA
-927.3mV  -122.1mA   -568.2mA   -49.48mA
-890.9mV  -50.83mA   -358.8mA   -27.66mA
-818.2mV  -14.88mA   -95.25mA   -15.47mA
-709.1mV  -5.604mA   -10.06mA   -6.54mA
1.8V      20.41uA    17.88uA    31.82uA
[Ramp]
dV/dt_f 0.59674317/0.67599897n 0.44446528/1.1171975n  0.7364246/0.47095519n
dV/dt_r 0.59638576/0.68524496n 0.44349353/1.0689179n 0.73591522/0.50589035n
R_load = 50
[Rising Waveform]
R_fixture = 50
V_fixture = 1.8
V_fixture_min = 1.62
V_fixture_max = 1.98
0s        814.5mV    886.6mV    763.1mV
268.6ps   814.9mV    886.6mV    786.4mV
853.6ps   953.2mV    890.2mV    1.133V
1.095ns   1.043V     929.6mV    1.415V
1.241ns   1.113V     969.9mV    1.836V
1.357ns   1.145V     999.2mV    1.959V
1.756ns   1.433V     1.059V     1.978V
2.017ns   1.777V     1.133V     1.978V
3.327ns   1.799V     1.586V     1.979V
5.12ns    1.8V       1.619V     1.979V
[Rising Waveform]
R_fixture = 50
V_fixture = 0
V_fixture_min = 0
V_fixture_max = 0
0s        0V         0V         156.9uV
844.1ps   66.53mV    0V         313.2mV
1.114ns   149.2mV    6.698mV    638.3mV
1.275ns   208.9mV    24.44mV    1.106V
1.394ns   244.3mV    36.38mV    1.202V
1.778ns   517.7mV    58.85mV    1.222V
2.144ns   971.7mV    131.1mV    1.223V
3.056ns   990.6mV    369.4mV    1.224V
3.559ns   991mV      701.4mV    1.224V
5.277ns   991.4mV    736.7mV    1.224V
[Falling Waveform]
R_fixture = 50
V_fixture = 1.8
V_fixture_min = 1.62
V_fixture_max = 1.98
0s        1.8V       1.62V      1.979V
577.3ps   1.8V       1.62V      1.879V
894.7ps   1.734V     1.624V     1.652V
1.112ns   1.675V     1.623V     1.272V
1.245ns   1.608V     1.609V     906.9mV
1.395ns   1.569V     1.592V     782.7mV
2.143ns   837.5mV    1.502V     763.4mV
2.651ns   815.3mV    1.42V      762.7mV
3.634ns   814.2mV    918.1mV    762.4mV
5.12ns    813.9mV    886.2mV    762.3mV
[Falling Waveform]
R_fixture = 50
V_fixture = 0
V_fixture_min = 0
V_fixture_max = 0
0s        992.1mV    737.5mV    1.224V
264.8ps   992.1mV    737.5mV    1.208V
609.2ps   936mV      737.5mV    991mV
891ps     809mV      735.1mV    692.4mV
1.182ns   647.1mV    673.8mV    120.8mV
1.297ns   576.4mV    633.4mV    24.46mV
1.817ns   77.79mV    498.4mV    1.798mV
1.989ns   18.16mV    435.8mV    1.366mV
3.133ns   639.5uV    28.84mV    235uV
5.277ns   37.25uV    259.1uV    3.984uV
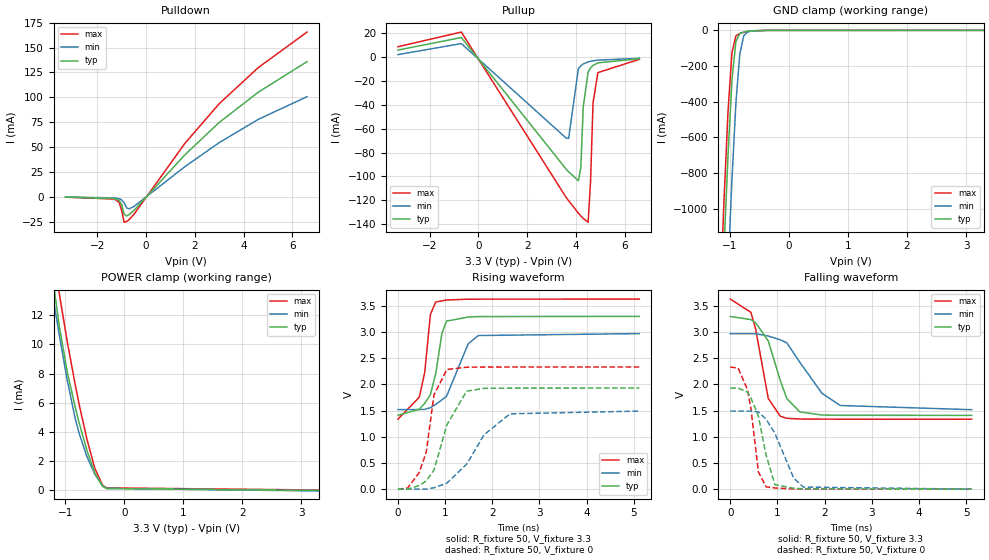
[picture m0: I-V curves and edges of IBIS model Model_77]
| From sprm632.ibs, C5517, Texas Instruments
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| Model based on original model for BC3340CTSCHYPD
|   Sub model SR0_VSS_SR1_VSS_PD_ON_COM_3P3
[model]   Model_77
|[Description]  [3.3V-I/O-PD-X, COM]
|   PD,COM,
|[Input Load]   PD
|[Output Drive]
|Voltage   3.3V
|Mode   I/O
Model_type   I/O
Polarity   Non-Inverting
Enable   Active-Low
Vinl =  0.8
Vinh =  2
Cref =  15.0000pF
Rref =  100.0000M
Vref =  0V
Vmeas =  1.65
C_comp   2.113745p   2.0494201p   2.2478119p
[Model Spec]
Vinl   0.8   0.8   0.8
Vinh   2   2   2
[Temperature Range]   25   105   -10
[Voltage Range]   3.3   2.97   3.63
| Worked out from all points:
|   slope of the pulldown table from 0 to 0.495 V, typ, clamps not added: 36.4 ohm
|   slope of the pullup table from 0 to 0.495 V, typ, clamps not added: 34.9 ohm
|   GND clamp passes 1 mA (typ) near -0.57 V on its own axis
|   POWER clamp passes 1 mA (typ) near -0.48 V on its own axis
|   rising waveform, R_fixture 50, V_fixture 3.3: 20-80 % time 243ps typ, 379ps min, 199ps max; typ from 1.41 V to 3.3 V
|   rising waveform, R_fixture 50, V_fixture 0: 20-80 % time 402ps typ, 704ps min, 277ps max; typ from 0 V to 1.93 V
|   falling waveform, R_fixture 50, V_fixture 3.3: 20-80 % time 391ps typ, 661ps min, 278ps max; typ from 3.3 V to 1.41 V
|   falling waveform, R_fixture 50, V_fixture 0: 20-80 % time 271ps typ, 426ps min, 197ps max; typ from 1.93 V to 0 V
[POWER_clamp]
-3.3V     86.18mA    66.85mA    105.5mA
-1.233V   15.23mA    13.89mA    17.72mA
-1.167V   13.13mA    12.22mA    15.4mA
-1.1V     11.2mA     10.59mA    13.44mA
-966.7mV  8.107mA    7.523mA    10.18mA
-833.3mV  5.722mA    4.941mA    7.259mA
-766.7mV  4.649mA    3.923mA    5.915mA
-633.3mV  2.737mA    2.321mA    3.494mA
-500mV    1.188mA    1.103mA    1.514mA
-366.7mV  275.1uA    317uA      346.6uA
-300mV    133.2uA    140.2uA    177.6uA
3.3V      -11.19nA   -32.41uA   30.46uA
[Pulldown]
-3.3V     -240.7uA   -180.9uA   -287.5uA
-1.3V     -1.697mA   -1.064mA   -2.217mA
-1.1V     -3.762mA   -1.923mA   -5.632mA
-1V       -7.728mA   -3.048mA   -13.97mA
-900mV    -17.44mA   -5.882mA   -25.46mA
-800mV    -19.19mA   -10.95mA   -24.79mA
-700mV    -17.88mA   -12.05mA   -23.02mA
-500mV    -13.74mA   -9.678mA   -17.65mA
1.6V      42.44mA    30.47mA    53.99mA
3V        74.73mA    54.46mA    93.56mA
4.6V      105.1mA    77.82mA    129.8mA
6.6V      135.8mA    100.6mA    165.5mA
[Pullup]
-3.3V     6.015mA    2.203mA    8.83mA
-700mV    16.55mA    11.47mA    21.11mA
3.6V      -93.97mA   -67.88mA   -117.7mA
3.7V      -96.18mA   -68.06mA   -120.4mA
4.1V      -103.6mA   -9.75mA    -130.8mA
4.2V      -92.66mA   -7.165mA   -133.2mA
4.3V      -41.56mA   -5.629mA   -135.2mA
4.5V      -12.4mA    -3.913mA   -138.4mA
4.6V      -8.869mA   -3.389mA   -103.9mA
4.7V      -6.864mA   -2.987mA   -38.55mA
4.9V      -4.698mA   -2.411mA   -12.9mA
6.6V      -1.25mA    -906.2uA   -1.735mA
[GND_clamp]
-3.3V     -22.46A    -23.08A    -22.21A
-1.167V   -1.78A     -2.475A    -1.498A
-1.1V     -1.214A    -1.896A    -940.5mA
-1.033V   -694.9mA   -1.343A    -450.5mA
-966.7mV  -277.7mA   -834.1mA   -123.9mA
-900mV    -62.92mA   -407mA     -30.99mA
-833.3mV  -17.83mA   -131.5mA   -17.15mA
-766.7mV  -9.316mA   -30.29mA   -10.8mA
-700mV    -5.152mA   -8.714mA   -5.993mA
-633.3mV  -2.404mA   -3.568mA   -2.659mA
-366.7mV  -35.97uA   -55.39uA   -41.93uA
3.3V      93.69uA    202uA      138.8uA
[Ramp]
dV/dt_f  1.1470933/0.39689522n 0.88260386/0.66815641n  1.3899122/0.27993433n
dV/dt_r   1.159984/0.39902549n 0.89636192/0.70850584n  1.4012837/0.27743342n
R_load = 50
[Rising Waveform]
R_fixture = 50
V_fixture = 3.3
V_fixture_min = 2.97
V_fixture_max = 3.63
0s        1.41V      1.518V     1.336V
453.5ps   1.526V     1.52V      1.755V
568.3ps   1.639V     1.522V     2.229V
688.7ps   1.806V     1.555V     3.334V
801.5ps   2.205V     1.617V     3.572V
931.9ps   2.968V     1.704V     3.594V
1.03ns    3.207V     1.77V      3.61V
1.49ns    3.285V     2.774V     3.626V
1.705ns   3.294V     2.932V     3.626V
5.12ns    3.298V     2.969V     3.628V
[Rising Waveform]
R_fixture = 50
V_fixture = 0
V_fixture_min = 0
V_fixture_max = 0
0s        0V         0V         0V
204.9ps   0V         0V         21.85mV
453ps     68.37mV    0V         319.4mV
601.5ps   159.9mV    0V         710.1mV
764.9ps   364.1mV    27.65mV    1.799V
1.038ns   1.227V     114.6mV    2.284V
1.456ns   1.871V     475.3mV    2.328V
1.829ns   1.924V     1.04V      2.33V
2.377ns   1.928V     1.438V     2.331V
5.12ns    1.93V      1.49V      2.332V
[Falling Waveform]
R_fixture = 50
V_fixture = 3.3
V_fixture_min = 2.97
V_fixture_max = 3.63
0s        3.297V     2.968V     3.629V
437.3ps   3.237V     2.968V     3.376V
537.6ps   3.178V     2.968V     3.059V
805.4ps   2.832V     2.924V     1.733V
1.062ns   2.071V     2.851V     1.391V
1.2ns     1.728V     2.792V     1.353V
1.477ns   1.475V     2.42V      1.339V
1.948ns   1.415V     1.827V     1.337V
2.334ns   1.41V      1.597V     1.336V
5.12ns    1.409V     1.517V     1.336V
[Falling Waveform]
R_fixture = 50
V_fixture = 0
V_fixture_min = 0
V_fixture_max = 0
0s        1.929V     1.491V     2.333V
168.5ps   1.929V     1.491V     2.308V
362.9ps   1.855V     1.491V     1.904V
437ps     1.743V     1.491V     1.549V
596.8ps   1.395V     1.474V     329mV
759.3ps   650.2mV    1.337V     44.47mV
946.3ps   88.22mV    1.067V     22.57mV
1.345ns   15.79mV    212.6mV    3.807mV
1.55ns    7.608mV    39.86mV    2.256mV
5.12ns    3.643uV    104.4uV    0V
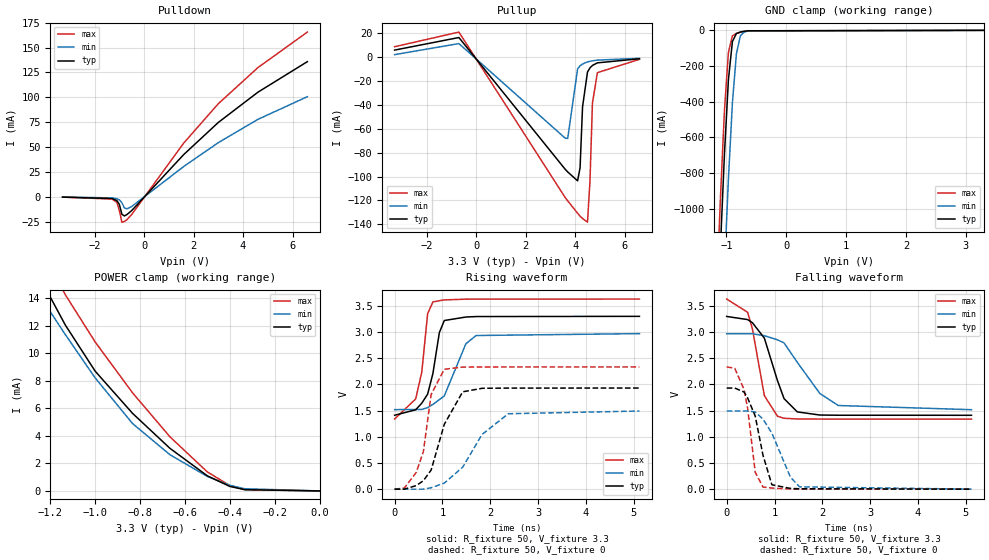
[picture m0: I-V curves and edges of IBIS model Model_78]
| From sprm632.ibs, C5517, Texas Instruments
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| Model based on original model for BC3340CTSCHYPD
|   Sub model SR0_VSS_SR1_VSS_PD_OFF_COM_3P3
[model]   Model_78
|[Description]  [3.3V-I/O-PD_OFF-X, COM]
|   PD_OFF,COM,
|[Input Load]   PD_OFF
|[Output Drive]
|Voltage   3.3V
|Mode   I/O
Model_type   I/O
Polarity   Non-Inverting
Enable   Active-Low
Vinl =  0.8
Vinh =  2
Cref =  15.0000pF
Rref =  100.0000M
Vref =  0V
Vmeas =  1.65
C_comp   2.113745p   2.0494201p   2.2478119p
[Model Spec]
Vinl   0.8   0.8   0.8
Vinh   2   2   2
[Temperature Range]   25   105   -10
[Voltage Range]   3.3   2.97   3.63
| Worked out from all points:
|   slope of the pulldown table from 0 to 0.495 V, typ, clamps not added: 36.4 ohm
|   slope of the pullup table from 0 to 0.495 V, typ, clamps not added: 34.9 ohm
|   GND clamp passes 1 mA (typ) near -0.57 V on its own axis
|   POWER clamp passes 1 mA (typ) near -0.49 V on its own axis
|   rising waveform, R_fixture 50, V_fixture 3.3: 20-80 % time 243ps typ, 379ps min, 199ps max; typ from 1.41 V to 3.3 V
|   rising waveform, R_fixture 50, V_fixture 0: 20-80 % time 397ps typ, 702ps min, 274ps max; typ from 0 V to 1.93 V
|   falling waveform, R_fixture 50, V_fixture 3.3: 20-80 % time 391ps typ, 661ps min, 276ps max; typ from 3.3 V to 1.41 V
|   falling waveform, R_fixture 50, V_fixture 0: 20-80 % time 270ps typ, 424ps min, 196ps max; typ from 1.93 V to 0 V
[POWER_clamp]
-3.3V     86.08mA    66.79mA    105.4mA
-1.267V   16.23mA    14.68mA    18.86mA
-1.233V   15.14mA    13.84mA    17.58mA
-1.2V     14.07mA    13mA       16.38mA
-1.133V   12.04mA    11.35mA    14.24mA
-1V       8.692mA    8.203mA    10.81mA
-833.3mV  5.628mA    4.887mA    7.12mA
-666.7mV  3.091mA    2.627mA    3.926mA
-500mV    1.094mA    1.049mA    1.375mA
-400mV    327.4uA    407uA      391.8uA
-333.3mV  89.34uA    156.7uA    95.64uA
0V        865.7pA    6.551nA    1.001nA
[Pulldown]
-3.3V     -240.7uA   -180.9uA   -287.5uA
-1.3V     -1.697mA   -1.064mA   -2.217mA
-1.1V     -3.762mA   -1.923mA   -5.632mA
-1V       -7.728mA   -3.048mA   -13.97mA
-900mV    -17.44mA   -5.882mA   -25.46mA
-800mV    -19.19mA   -10.95mA   -24.79mA
-700mV    -17.88mA   -12.05mA   -23.02mA
-500mV    -13.74mA   -9.678mA   -17.65mA
1.6V      42.45mA    30.47mA    53.99mA
3V        74.73mA    54.46mA    93.56mA
4.6V      105.1mA    77.82mA    129.8mA
6.6V      135.8mA    100.6mA    165.5mA
[Pullup]
-3.3V     6.015mA    2.203mA    8.83mA
-700mV    16.55mA    11.47mA    21.11mA
3.6V      -93.97mA   -67.88mA   -117.7mA
3.7V      -96.18mA   -68.06mA   -120.4mA
4.1V      -103.6mA   -9.75mA    -130.8mA
4.2V      -92.66mA   -7.165mA   -133.2mA
4.3V      -41.55mA   -5.629mA   -135.2mA
4.5V      -12.4mA    -3.913mA   -138.3mA
4.6V      -8.869mA   -3.389mA   -103.9mA
4.7V      -6.864mA   -2.987mA   -38.55mA
4.9V      -4.698mA   -2.411mA   -12.9mA
6.6V      -1.25mA    -906.2uA   -1.735mA
[GND_clamp]
-3.3V     -22.46A    -23.08A    -22.21A
-1.167V   -1.78A     -2.475A    -1.498A
-1.1V     -1.214A    -1.896A    -940.5mA
-1.033V   -694.9mA   -1.343A    -450.5mA
-966.7mV  -277.7mA   -834.1mA   -123.9mA
-900mV    -62.9mA    -407mA     -30.92mA
-833.3mV  -17.79mA   -131.4mA   -17.07mA
-766.7mV  -9.259mA   -30.27mA   -10.72mA
-700mV    -5.097mA   -8.689mA   -5.922mA
-633.3mV  -2.353mA   -3.537mA   -2.594mA
3.3V      865.7pA    147.8uA    -71.26pA
[Ramp]
dV/dt_f  1.1472467/0.39641842n 0.88264456/0.66777532n  1.3902258/0.27935779n
dV/dt_r  1.1611302/0.39535145n 0.89711689/0.70603561n  1.4027765/0.27499549n
R_load = 50
[Rising Waveform]
R_fixture = 50
V_fixture = 3.3
V_fixture_min = 2.97
V_fixture_max = 3.63
0s        1.411V     1.519V     1.339V
440.9ps   1.516V     1.521V     1.723V
568.6ps   1.642V     1.523V     2.236V
690.9ps   1.815V     1.557V     3.351V
801.5ps   2.21V      1.619V     3.576V
936ps     2.99V      1.709V     3.598V
1.039ns   3.22V      1.78V      3.614V
1.49ns    3.287V     2.776V     3.628V
1.705ns   3.296V     2.934V     3.629V
5.12ns    3.3V       2.97V      3.63V
[Rising Waveform]
R_fixture = 50
V_fixture = 0
V_fixture_min = 0
V_fixture_max = 0
0s        0V         0V         0V
204.9ps   0V         0V         21.93mV
453ps     68.75mV    0V         321.1mV
601.5ps   160.8mV    0V         714mV
764.4ps   365mV      27.6mV     1.808V
1.039ns   1.238V     115.4mV    2.29V
1.424ns   1.859V     419.8mV    2.331V
1.829ns   1.926V     1.045V     2.333V
2.378ns   1.93V      1.44V      2.334V
5.12ns    1.931V     1.492V     2.334V
[Falling Waveform]
R_fixture = 50
V_fixture = 3.3
V_fixture_min = 2.97
V_fixture_max = 3.63
0s        3.299V     2.969V     3.631V
437.3ps   3.239V     2.969V     3.379V
537.6ps   3.18V      2.969V     3.063V
788.5ps   2.884V     2.931V     1.785V
1.062ns   2.074V     2.853V     1.392V
1.2ns     1.729V     2.793V     1.354V
1.477ns   1.476V     2.422V     1.341V
1.948ns   1.416V     1.828V     1.339V
2.334ns   1.412V     1.598V     1.338V
5.12ns    1.411V     1.518V     1.338V
[Falling Waveform]
R_fixture = 50
V_fixture = 0
V_fixture_min = 0
V_fixture_max = 0
0s        1.931V     1.493V     2.335V
168.5ps   1.931V     1.493V     2.31V
362.9ps   1.856V     1.493V     1.905V
437ps     1.745V     1.493V     1.55V
596.7ps   1.396V     1.475V     322.9mV
759.3ps   647.1mV    1.338V     40.84mV
945.5ps   84.28mV    1.069V     21.05mV
1.334ns   13.88mV    226.8mV    3.337mV
1.525ns   7.813mV    44.3mV     1.962mV
5.12ns    3.722uV    72.62uV    0V
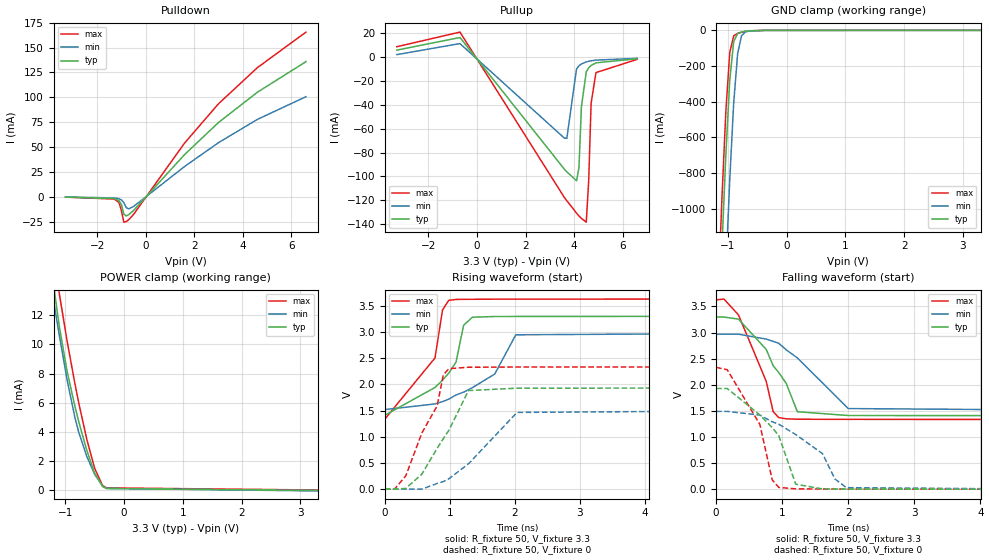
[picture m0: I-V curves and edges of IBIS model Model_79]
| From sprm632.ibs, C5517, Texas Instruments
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| Model based on original model for BC3340CTSCHYPD
|   Sub model SR0_VDD_SR1_VDD_PD_ON_COM_3P3
[model]   Model_79
|[Description]  [3.3V-I/O-PD-X, COM]
|   PD,COM,
|[Input Load]   PD
|[Output Drive]
|Voltage   3.3V
|Mode   I/O
Model_type   I/O
Polarity   Non-Inverting
Enable   Active-Low
Vinl =  0.8
Vinh =  2
Cref =  15.0000pF
Rref =  100.0000M
Vref =  0V
Vmeas =  1.65
C_comp   2.113745p   2.0494201p   2.2478119p
[Model Spec]
Vinl   0.8   0.8   0.8
Vinh   2   2   2
[Temperature Range]   25   105   -10
[Voltage Range]   3.3   2.97   3.63
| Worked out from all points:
|   slope of the pulldown table from 0 to 0.495 V, typ, clamps not added: 36.4 ohm
|   slope of the pullup table from 0 to 0.495 V, typ, clamps not added: 34.9 ohm
|   GND clamp passes 1 mA (typ) near -0.57 V on its own axis
|   POWER clamp passes 1 mA (typ) near -0.48 V on its own axis
|   rising waveform, R_fixture 50, V_fixture 3.3: 20-80 % time 538ps typ, 724ps min, 454ps max; typ from 1.41 V to 3.3 V
|   rising waveform, R_fixture 50, V_fixture 0: 20-80 % time 549ps typ, 751ps min, 458ps max; typ from 0 V to 1.93 V
|   falling waveform, R_fixture 50, V_fixture 3.3: 20-80 % time 516ps typ, 731ps min, 414ps max; typ from 3.3 V to 1.41 V
|   falling waveform, R_fixture 50, V_fixture 0: 20-80 % time 526ps typ, 747ps min, 423ps max; typ from 1.93 V to 0 V
[POWER_clamp]
-3.3V     86.18mA    66.85mA    105.5mA
-1.233V   15.23mA    13.89mA    17.72mA
-1.167V   13.13mA    12.22mA    15.4mA
-1.1V     11.2mA     10.59mA    13.44mA
-966.7mV  8.107mA    7.523mA    10.18mA
-833.3mV  5.722mA    4.941mA    7.259mA
-766.7mV  4.649mA    3.923mA    5.915mA
-633.3mV  2.737mA    2.321mA    3.494mA
-500mV    1.188mA    1.103mA    1.514mA
-366.7mV  275.1uA    317uA      346.6uA
-300mV    133.2uA    140.2uA    177.6uA
3.3V      -11.19nA   -32.41uA   30.46uA
[Pulldown]
-3.3V     -240.7uA   -180.9uA   -287.5uA
-1.3V     -1.697mA   -1.064mA   -2.217mA
-1.1V     -3.762mA   -1.923mA   -5.632mA
-1V       -7.728mA   -3.048mA   -13.97mA
-900mV    -17.44mA   -5.882mA   -25.46mA
-800mV    -19.19mA   -10.95mA   -24.79mA
-700mV    -17.88mA   -12.05mA   -23.02mA
-500mV    -13.74mA   -9.678mA   -17.65mA
1.6V      42.44mA    30.47mA    53.99mA
3V        74.73mA    54.46mA    93.56mA
4.6V      105.1mA    77.82mA    129.8mA
6.6V      135.8mA    100.6mA    165.5mA
[Pullup]
-3.3V     6.015mA    2.203mA    8.83mA
-700mV    16.55mA    11.47mA    21.11mA
3.6V      -93.97mA   -67.88mA   -117.7mA
3.7V      -96.18mA   -68.06mA   -120.4mA
4.1V      -103.6mA   -9.75mA    -130.8mA
4.2V      -92.66mA   -7.165mA   -133.2mA
4.3V      -41.56mA   -5.629mA   -135.2mA
4.5V      -12.4mA    -3.913mA   -138.4mA
4.6V      -8.869mA   -3.389mA   -103.9mA
4.7V      -6.864mA   -2.987mA   -38.55mA
4.9V      -4.698mA   -2.411mA   -12.9mA
6.6V      -1.25mA    -906.2uA   -1.735mA
[GND_clamp]
-3.3V     -22.46A    -23.08A    -22.21A
-1.167V   -1.78A     -2.475A    -1.498A
-1.1V     -1.214A    -1.896A    -940.5mA
-1.033V   -694.9mA   -1.343A    -450.5mA
-966.7mV  -277.7mA   -834.1mA   -123.9mA
-900mV    -62.92mA   -407mA     -30.99mA
-833.3mV  -17.83mA   -131.5mA   -17.15mA
-766.7mV  -9.316mA   -30.29mA   -10.8mA
-700mV    -5.152mA   -8.714mA   -5.993mA
-633.3mV  -2.404mA   -3.568mA   -2.659mA
-366.7mV  -35.97uA   -55.39uA   -41.93uA
3.3V      93.69uA    202uA      138.8uA
[Ramp]
dV/dt_f  1.1416208/0.52068028n 0.87816182/0.73775223n  1.3839781/0.41695141n
dV/dt_r  1.1588019/0.5495999n 0.89537437/0.75257016n  1.3999859/0.45797494n
R_load = 50
[Rising Waveform]
R_fixture = 50
V_fixture = 3.3
V_fixture_min = 2.97
V_fixture_max = 3.63
0s        1.41V      1.518V     1.336V
772.3ps   1.941V     1.627V     2.505V
887.9ps   2.079V     1.67V      3.421V
983.5ps   2.213V     1.718V     3.604V
1.096ns   2.426V     1.798V     3.621V
1.212ns   3.128V     1.851V     3.623V
1.348ns   3.282V     1.938V     3.624V
1.691ns   3.295V     2.197V     3.626V
2.015ns   3.296V     2.946V     3.627V
5.12ns    3.298V     2.969V     3.628V
[Rising Waveform]
R_fixture = 50
V_fixture = 0
V_fixture_min = 0
V_fixture_max = 0
0s        419.3uV    0V         762.7uV
149.7ps   419.3uV    0V         762.7uV
323.5ps   14.77mV    0V         255.4mV
569.3ps   285.6mV    0V         1.071V
805.1ps   779.4mV    109.2mV    1.589V
900ps     963.4mV    145.2mV    2.183V
986.2ps   1.125V     198.6mV    2.299V
1.287ns   1.882V     484mV      2.327V
2.034ns   1.927V     1.465V     2.331V
5.132ns   1.93V      1.49V      2.332V
[Falling Waveform]
R_fixture = 50
V_fixture = 3.3
V_fixture_min = 2.97
V_fixture_max = 3.63
0s        3.297V     2.969V     3.627V
120.3ps   3.297V     2.969V     3.642V
339.3ps   3.258V     2.969V     3.338V
758.3ps   2.678V     2.875V     2.069V
864.1ps   2.365V     2.832V     1.486V
948.9ps   2.234V     2.794V     1.371V
1.062ns   2.026V     2.669V     1.348V
1.23ns    1.484V     2.515V     1.34V
2.001ns   1.411V     1.544V     1.337V
5.12ns    1.409V     1.517V     1.336V
[Falling Waveform]
R_fixture = 50
V_fixture = 0
V_fixture_min = 0
V_fixture_max = 0
0s        1.929V     1.49V      2.333V
168.5ps   1.929V     1.49V      2.29V
663ps     1.422V     1.419V     1.239V
850ps     1.179V     1.29V      177.9mV
948.6ps   1.027V     1.245V     33.59mV
1.205ns   95.95mV    1.046V     5.962mV
1.611ns   4.941mV    680.7mV    2.543mV
1.799ns   3.277mV    194.2mV    1.845mV
1.972ns   2.495mV    28.74mV    1.369mV
5.132ns   10.27uV    144.8uV    0V
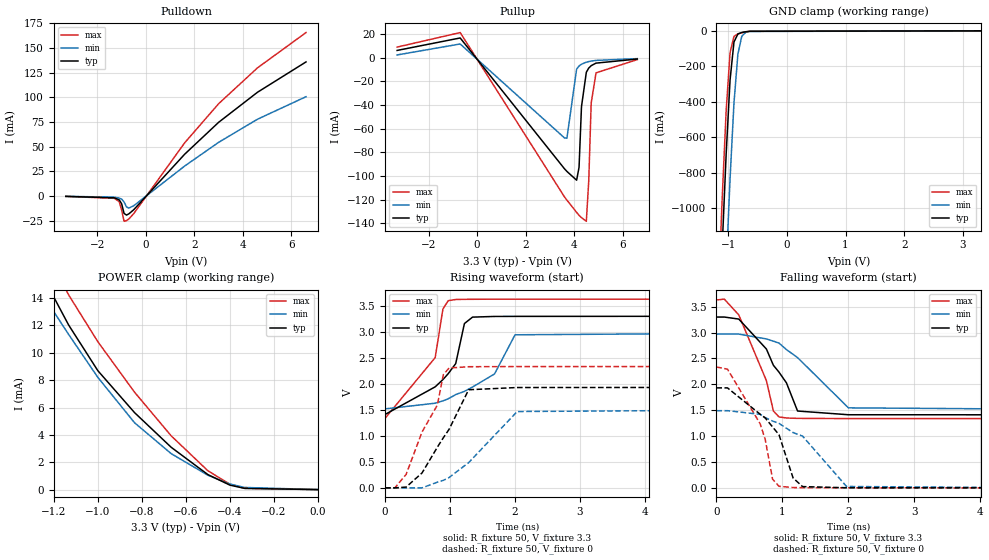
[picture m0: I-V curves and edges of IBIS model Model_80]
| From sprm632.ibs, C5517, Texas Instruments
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| Model based on original model for BC3340CTSCHYPD
|   Sub model SR0_VDD_SR1_VDD_PD_OFF_COM_3P3
[model]   Model_80
|[Description]  [3.3V-I/O-PD_OFF-X, COM]
|   PD_OFF,COM,
|[Input Load]   PD_OFF
|[Output Drive]
|Voltage   3.3V
|Mode   I/O
Model_type   I/O
Polarity   Non-Inverting
Enable   Active-Low
Vinl =  0.8
Vinh =  2
Cref =  15.0000pF
Rref =  100.0000M
Vref =  0V
Vmeas =  1.65
C_comp   2.113745p   2.0494201p   2.2478119p
[Model Spec]
Vinl   0.8   0.8   0.8
Vinh   2   2   2
[Temperature Range]   25   105   -10
[Voltage Range]   3.3   2.97   3.63
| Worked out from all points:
|   slope of the pulldown table from 0 to 0.495 V, typ, clamps not added: 36.4 ohm
|   slope of the pullup table from 0 to 0.495 V, typ, clamps not added: 34.9 ohm
|   GND clamp passes 1 mA (typ) near -0.57 V on its own axis
|   POWER clamp passes 1 mA (typ) near -0.49 V on its own axis
|   rising waveform, R_fixture 50, V_fixture 3.3: 20-80 % time 540ps typ, 724ps min, 454ps max; typ from 1.41 V to 3.3 V
|   rising waveform, R_fixture 50, V_fixture 0: 20-80 % time 549ps typ, 752ps min, 458ps max; typ from 0 V to 1.93 V
|   falling waveform, R_fixture 50, V_fixture 3.3: 20-80 % time 516ps typ, 731ps min, 413ps max; typ from 3.3 V to 1.41 V
|   falling waveform, R_fixture 50, V_fixture 0: 20-80 % time 526ps typ, 747ps min, 423ps max; typ from 1.93 V to 0 V
[POWER_clamp]
-3.3V     86.08mA    66.79mA    105.4mA
-1.267V   16.23mA    14.68mA    18.86mA
-1.233V   15.14mA    13.84mA    17.58mA
-1.2V     14.07mA    13mA       16.38mA
-1.133V   12.04mA    11.35mA    14.24mA
-1V       8.692mA    8.203mA    10.81mA
-833.3mV  5.628mA    4.887mA    7.12mA
-666.7mV  3.091mA    2.627mA    3.926mA
-500mV    1.094mA    1.049mA    1.375mA
-400mV    327.4uA    407uA      391.8uA
-333.3mV  89.34uA    156.7uA    95.64uA
0V        865.7pA    6.551nA    1.001nA
[Pulldown]
-3.3V     -240.7uA   -180.9uA   -287.5uA
-1.3V     -1.697mA   -1.064mA   -2.217mA
-1.1V     -3.762mA   -1.923mA   -5.632mA
-1V       -7.728mA   -3.048mA   -13.97mA
-900mV    -17.44mA   -5.882mA   -25.46mA
-800mV    -19.19mA   -10.95mA   -24.79mA
-700mV    -17.88mA   -12.05mA   -23.02mA
-500mV    -13.74mA   -9.678mA   -17.65mA
1.6V      42.45mA    30.47mA    53.99mA
3V        74.73mA    54.46mA    93.56mA
4.6V      105.1mA    77.82mA    129.8mA
6.6V      135.8mA    100.6mA    165.5mA
[Pullup]
-3.3V     6.015mA    2.203mA    8.83mA
-700mV    16.55mA    11.47mA    21.11mA
3.6V      -93.97mA   -67.88mA   -117.7mA
3.7V      -96.18mA   -68.06mA   -120.4mA
4.1V      -103.6mA   -9.75mA    -130.8mA
4.2V      -92.66mA   -7.165mA   -133.2mA
4.3V      -41.55mA   -5.629mA   -135.2mA
4.5V      -12.4mA    -3.913mA   -138.3mA
4.6V      -8.869mA   -3.389mA   -103.9mA
4.7V      -6.864mA   -2.987mA   -38.55mA
4.9V      -4.698mA   -2.411mA   -12.9mA
6.6V      -1.25mA    -906.2uA   -1.735mA
[GND_clamp]
-3.3V     -22.46A    -23.08A    -22.21A
-1.167V   -1.78A     -2.475A    -1.498A
-1.1V     -1.214A    -1.896A    -940.5mA
-1.033V   -694.9mA   -1.343A    -450.5mA
-966.7mV  -277.7mA   -834.1mA   -123.9mA
-900mV    -62.9mA    -407mA     -30.92mA
-833.3mV  -17.79mA   -131.4mA   -17.07mA
-766.7mV  -9.259mA   -30.27mA   -10.72mA
-700mV    -5.097mA   -8.689mA   -5.922mA
-633.3mV  -2.353mA   -3.537mA   -2.594mA
3.3V      865.7pA    147.8uA    -71.26pA
[Ramp]
dV/dt_f  1.1417642/0.52043684n 0.87819653/0.737574n   1.3842832/0.41667373n
dV/dt_r  1.1599352/0.54973295n  0.8961181/0.7526781n  1.4014712/0.45820542n
R_load = 50
[Rising Waveform]
R_fixture = 50
V_fixture = 3.3
V_fixture_min = 2.97
V_fixture_max = 3.63
0s        1.412V     1.519V     1.338V
771.7ps   1.943V     1.628V     2.506V
891.2ps   2.083V     1.673V     3.441V
972.5ps   2.196V     1.713V     3.6V
1.088ns   2.39V      1.794V     3.623V
1.222ns   3.16V      1.856V     3.626V
1.347ns   3.284V     1.939V     3.627V
1.686ns   3.297V     2.191V     3.629V
2.002ns   3.298V     2.944V     3.629V
5.12ns    3.3V       2.97V      3.63V
[Rising Waveform]
R_fixture = 50
V_fixture = 0
V_fixture_min = 0
V_fixture_max = 0
0s        411.4uV    0V         756.4uV
149.7ps   411.4uV    0V         756.4uV
323.5ps   14.8mV     0V         256.8mV
569.3ps   286.8mV    0V         1.075V
805.1ps   782.1mV    109.7mV    1.592V
897.3ps   963.9mV    144.7mV    2.178V
986.2ps   1.127V     199.4mV    2.305V
1.287ns   1.887V     485.5mV    2.33V
2.035ns   1.93V      1.468V     2.333V
5.132ns   1.931V     1.492V     2.334V
[Falling Waveform]
R_fixture = 50
V_fixture = 3.3
V_fixture_min = 2.97
V_fixture_max = 3.63
0s        3.299V     2.97V      3.629V
120.3ps   3.299V     2.97V      3.645V
339.3ps   3.26V      2.97V      3.341V
758.3ps   2.681V     2.876V     2.07V
864ps     2.367V     2.833V     1.485V
948.9ps   2.235V     2.796V     1.37V
1.062ns   2.027V     2.67V      1.349V
1.23ns    1.484V     2.516V     1.342V
2.001ns   1.412V     1.545V     1.338V
5.12ns    1.411V     1.518V     1.338V
[Falling Waveform]
R_fixture = 50
V_fixture = 0
V_fixture_min = 0
V_fixture_max = 0
0s        1.931V     1.491V     2.335V
168.5ps   1.931V     1.491V     2.292V
663.3ps   1.422V     1.42V      1.238V
739.3ps   1.351V     1.357V     939.6mV
851.3ps   1.177V     1.29V      168.9mV
948.6ps   1.027V     1.246V     29.98mV
1.162ns   191.7mV    1.068V     5.698mV
1.306ns   24.26mV    999.2mV    3.667mV
1.972ns   2.008mV    26.54mV    1.109mV
5.132ns   4.245uV    102.3uV    0V
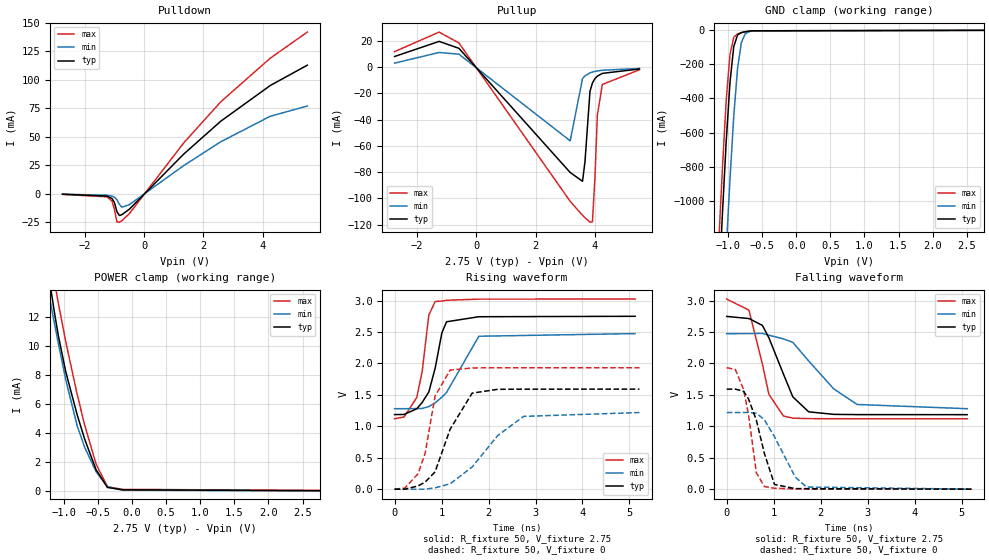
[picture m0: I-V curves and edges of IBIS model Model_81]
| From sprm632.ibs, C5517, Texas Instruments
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| Model based on original model for BC3340CTSCHYPD
|   Sub model SR0_VSS_SR1_VSS_PD_ON_COM_2P75
[model]   Model_81
|[Description]  [2.75V-I/O-PD-X, COM]
|   PD,COM,
|[Input Load]   PD
|[Output Drive]
|Voltage   2.75V
|Mode   I/O
Model_type   I/O
Polarity   Non-Inverting
Enable   Active-Low
Vinl =  0.7
Vinh =  1.7
Cref =  15.0000pF
Rref =  100.0000M
Vref =  0V
Vmeas =  1.375
C_comp   2.1456989p   2.0494201p   2.2784851p
[Model Spec]
Vinl   0.7   0.7   0.7
Vinh   1.7   1.7   1.7
[Temperature Range]   25   105   -10
[Voltage Range]   2.75   2.475   3.025
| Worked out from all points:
|   slope of the pulldown table from 0 to 0.412 V, typ, clamps not added: 37.1 ohm
|   slope of the pullup table from 0 to 0.412 V, typ, clamps not added: 35.9 ohm
|   GND clamp passes 1 mA (typ) near -0.57 V on its own axis
|   POWER clamp passes 1 mA (typ) near -0.48 V on its own axis
|   rising waveform, R_fixture 50, V_fixture 2.75: 20-80 % time 291ps typ, 507ps min, 215ps max; typ from 1.19 V to 2.75 V
|   rising waveform, R_fixture 50, V_fixture 0: 20-80 % time 501ps typ, 894ps min, 321ps max; typ from 0 V to 1.59 V
|   falling waveform, R_fixture 50, V_fixture 2.75: 20-80 % time 496ps typ, 902ps min, 332ps max; typ from 2.75 V to 1.19 V
|   falling waveform, R_fixture 50, V_fixture 0: 20-80 % time 316ps typ, 495ps min, 227ps max; typ from 1.59 V to 0 V
[POWER_clamp]
-2.75V    68.54mA    53.4mA     84.13mA
-1.25V    15.8mA     14.35mA    18.37mA
-1.194V   14.01mA    12.94mA    16.33mA
-1.139V   12.31mA    11.56mA    14.54mA
-1.083V   10.75mA    10.21mA    12.98mA
-972.2mV  8.203mA    7.648mA    10.28mA
-805.6mV  5.244mA    4.485mA    6.656mA
-694.4mV  3.547mA    2.986mA    4.521mA
-527.8mV  1.441mA    1.31mA     1.833mA
-361.1mV  223.7uA    277.8uA    276.3uA
-138.9mV  61.83uA    37.73uA    92.51uA
2.75V     -8.84nA    -15.87uA   21.46uA
[Pulldown]
-2.75V    -308.5uA   -227.6uA   -371.5uA
-1.25V    -1.93mA    -1.163mA   -2.58mA
-1.083V   -4.054mA   -1.991mA   -6.245mA
-1V       -7.547mA   -2.954mA   -13.7mA
-916.7mV  -15.6mA    -5.046mA   -24.44mA
-833.3mV  -18.95mA   -9.139mA   -24.82mA
-750mV    -18.23mA   -11.68mA   -23.55mA
-500mV    -13.48mA   -9.45mA    -17.38mA
1.333V    34.87mA    24.79mA    44.69mA
2.583V    63.77mA    45.72mA    80.76mA
4.25V     95.04mA    68.08mA    119mA
5.5V      112.9mA    77.06mA    141.9mA
[Pullup]
-2.75V    8.15mA     3.088mA    11.86mA
-1.25V    19.65mA    11.21mA    26.74mA
-583.3mV  14.38mA    9.918mA    18.47mA
3.167V    -80.24mA   -56.1mA    -102.2mA
3.583V    -86.93mA   -8.662mA   -112.9mA
3.667V    -71.56mA   -6.559mA   -114.7mA
3.833V    -18.5mA    -4.358mA   -118.1mA
3.917V    -11.98mA   -3.72mA    -117.8mA
4V        -8.725mA   -3.242mA   -84.8mA
4.083V    -6.819mA   -2.87mA    -36.49mA
4.25V     -4.711mA   -2.331mA   -13.16mA
5.5V      -1.388mA   -959.6uA   -2.008mA
[GND_clamp]
-2.75V    -17.03A    -17.67A    -16.78A
-1.139V   -1.54A     -2.231A    -1.261A
-1.083V   -1.078A    -1.755A    -809.5mA
-1.028V   -655mA     -1.299A    -415mA
-972.2mV  -306mA     -874.1mA   -141.2mA
-916.7mV  -94.94mA   -503mA     -40.42mA
-861.1mV  -27.25mA   -223.2mA   -20.89mA
-805.6mV  -13.1mA    -72.24mA   -14.24mA
-750mV    -8.089mA   -21.21mA   -9.46mA
-694.4mV  -4.87mA    -8.039mA   -5.651mA
-638.9mV  -2.576mA   -3.815mA   -2.865mA
2.75V     61.47uA    87.87uA    92.23uA
[Ramp]
dV/dt_f 0.95018123/0.49736185n 0.72655158/0.89667075n  1.1552217/0.33501603n
dV/dt_r 0.95689585/0.50307953n 0.73349818/0.90023581n  1.1609515/0.3224203n
R_load = 50
[Rising Waveform]
R_fixture = 50
V_fixture = 2.75
V_fixture_min = 2.475
V_fixture_max = 3.025
0s        1.186V     1.28V      1.121V
200.2ps   1.188V     1.28V      1.146V
471.8ps   1.278V     1.282V     1.458V
586.8ps   1.379V     1.284V     1.87V
728.3ps   1.545V     1.312V     2.768V
864.3ps   1.926V     1.373V     2.984V
1.006ns   2.485V     1.462V     2.991V
1.106ns   2.662V     1.538V     3.004V
1.793ns   2.742V     2.432V     3.022V
5.12ns    2.749V     2.474V     3.023V
[Rising Waveform]
R_fixture = 50
V_fixture = 0
V_fixture_min = 0
V_fixture_max = 0
0s        0V         0V         192.4uV
220.5ps   0V         0V         18.16mV
500ps     51.15mV    0V         246.7mV
651.2ps   113mV      0V         573.7mV
861.2ps   274.9mV    21.64mV    1.479V
1.182ns   952.8mV    85.02mV    1.893V
1.651ns   1.527V     352.6mV    1.928V
2.194ns   1.588V     851.6mV    1.93V
2.744ns   1.59V      1.157V     1.931V
5.212ns   1.591V     1.219V     1.931V
[Falling Waveform]
R_fixture = 50
V_fixture = 2.75
V_fixture_min = 2.475
V_fixture_max = 3.025
0s        2.748V     2.474V     3.024V
475.6ps   2.714V     2.475V     2.847V
761.2ps   2.604V     2.478V     1.986V
898.3ps   2.408V     2.449V     1.509V
1.207ns   1.833V     2.391V     1.165V
1.407ns   1.469V     2.336V     1.13V
1.746ns   1.23V      2.039V     1.122V
2.278ns   1.19V      1.596V     1.121V
2.778ns   1.186V     1.347V     1.12V
5.12ns    1.185V     1.28V      1.12V
[Falling Waveform]
R_fixture = 50
V_fixture = 0
V_fixture_min = 0
V_fixture_max = 0
0s        1.591V     1.219V     1.932V
184.5ps   1.591V     1.219V     1.903V
360.5ps   1.557V     1.219V     1.585V
463.8ps   1.437V     1.219V     1.189V
631.8ps   1.098V     1.208V     259.9mV
803.4ps   566.3mV    1.104V     40.94mV
1.018ns   74.32mV    833.3mV    14.12mV
1.458ns   8.79mV     194.1mV    3.077mV
1.699ns   8.02mV     33.74mV    1.64mV
5.212ns   9.934uV    106.1uV    0V
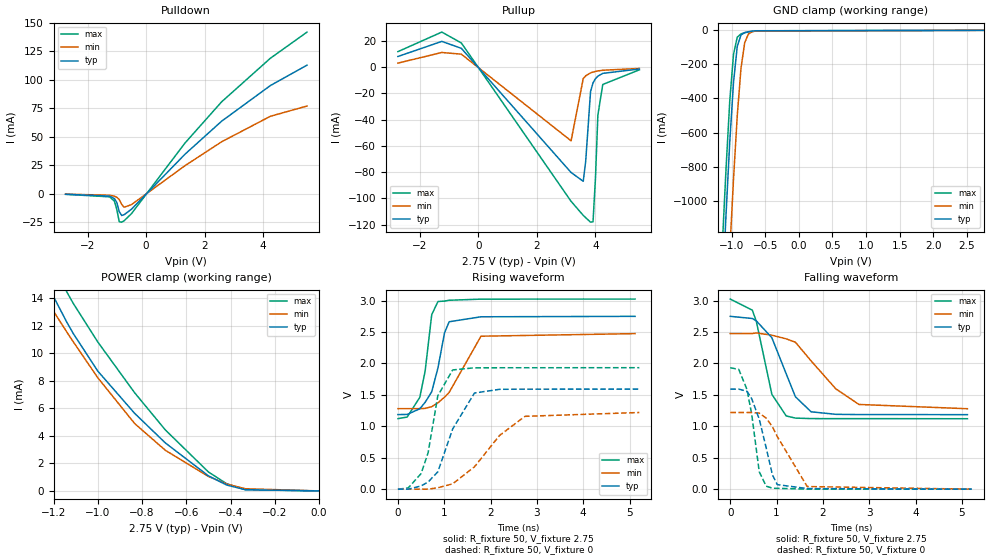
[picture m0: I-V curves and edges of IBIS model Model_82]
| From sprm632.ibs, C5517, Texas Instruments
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| Model based on original model for BC3340CTSCHYPD
|   Sub model SR0_VSS_SR1_VSS_PD_OFF_COM_2P75
[model]   Model_82
|[Description]  [2.75V-I/O-PD_OFF-X, COM]
|   PD_OFF,COM,
|[Input Load]   PD_OFF
|[Output Drive]
|Voltage   2.75V
|Mode   I/O
Model_type   I/O
Polarity   Non-Inverting
Enable   Active-Low
Vinl =  0.7
Vinh =  1.7
Cref =  15.0000pF
Rref =  100.0000M
Vref =  0V
Vmeas =  1.375
C_comp   2.1456989p   2.0494201p   2.2784851p
[Model Spec]
Vinl   0.7   0.7   0.7
Vinh   1.7   1.7   1.7
[Temperature Range]   25   105   -10
[Voltage Range]   2.75   2.475   3.025
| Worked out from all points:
|   slope of the pulldown table from 0 to 0.412 V, typ, clamps not added: 37.1 ohm
|   slope of the pullup table from 0 to 0.412 V, typ, clamps not added: 35.9 ohm
|   GND clamp passes 1 mA (typ) near -0.58 V on its own axis
|   POWER clamp passes 1 mA (typ) near -0.49 V on its own axis
|   rising waveform, R_fixture 50, V_fixture 2.75: 20-80 % time 292ps typ, 508ps min, 215ps max; typ from 1.19 V to 2.75 V
|   rising waveform, R_fixture 50, V_fixture 0: 20-80 % time 497ps typ, 893ps min, 318ps max; typ from 0 V to 1.59 V
|   falling waveform, R_fixture 50, V_fixture 2.75: 20-80 % time 496ps typ, 902ps min, 331ps max; typ from 2.75 V to 1.19 V
|   falling waveform, R_fixture 50, V_fixture 0: 20-80 % time 315ps typ, 495ps min, 226ps max; typ from 1.59 V to 0 V
[POWER_clamp]
-2.75V    68.47mA    53.36mA    84.04mA
-1.25V    15.74mA    14.31mA    18.28mA
-1.194V   13.94mA    12.91mA    16.24mA
-1.139V   12.24mA    11.53mA    14.44mA
-1.111V   11.45mA    10.85mA    13.64mA
-1V       8.713mA    8.23mA     10.83mA
-833.3mV  5.639mA    4.898mA    7.135mA
-694.4mV  3.486mA    2.951mA    4.429mA
-500mV    1.096mA    1.05mA     1.377mA
-416.7mV  423.4uA    494.2uA    514.4uA
-333.3mV  89.36uA    156.8uA    95.66uA
0V        635.3pA    4.99nA     662.4pA
[Pulldown]
-2.75V    -308.5uA   -227.6uA   -371.5uA
-1.25V    -1.93mA    -1.163mA   -2.58mA
-1.083V   -4.054mA   -1.991mA   -6.245mA
-1V       -7.547mA   -2.954mA   -13.7mA
-916.7mV  -15.6mA    -5.046mA   -24.44mA
-833.3mV  -18.95mA   -9.138mA   -24.82mA
-750mV    -18.23mA   -11.68mA   -23.55mA
-500mV    -13.48mA   -9.45mA    -17.38mA
1.333V    34.87mA    24.79mA    44.69mA
2.583V    63.77mA    45.72mA    80.76mA
4.25V     95.04mA    68.08mA    119mA
5.5V      112.9mA    77.06mA    141.9mA
[Pullup]
-2.75V    8.15mA     3.088mA    11.86mA
-1.25V    19.65mA    11.21mA    26.74mA
-583.3mV  14.38mA    9.918mA    18.47mA
3.167V    -80.24mA   -56.1mA    -102.2mA
3.583V    -86.93mA   -8.662mA   -112.9mA
3.667V    -71.56mA   -6.559mA   -114.7mA
3.833V    -18.5mA    -4.358mA   -118.1mA
3.917V    -11.98mA   -3.72mA    -117.8mA
4V        -8.724mA   -3.242mA   -84.8mA
4.083V    -6.819mA   -2.87mA    -36.49mA
4.25V     -4.711mA   -2.331mA   -13.16mA
5.5V      -1.388mA   -959.6uA   -2.008mA
[GND_clamp]
-2.75V    -17.03A    -17.67A    -16.78A
-1.139V   -1.54A     -2.231A    -1.261A
-1.083V   -1.078A    -1.755A    -809.5mA
-1.028V   -655mA     -1.299A    -414.9mA
-972.2mV  -306mA     -874.1mA   -141.2mA
-916.7mV  -94.92mA   -503mA     -40.37mA
-861.1mV  -27.21mA   -223.1mA   -20.83mA
-805.6mV  -13.06mA   -72.23mA   -14.17mA
-750mV    -8.039mA   -21.19mA   -9.394mA
-694.4mV  -4.823mA   -8.017mA   -5.589mA
-638.9mV  -2.532mA   -3.789mA   -2.808mA
2.75V     635.3pA    52.4uA     -264.9pA
[Ramp]
dV/dt_f 0.95026714/0.49684709n 0.72657291/0.89649665n  1.1554137/0.33443352n
dV/dt_r  0.9576756/0.49872607n 0.73401514/0.89915769n  1.1619708/0.31908683n
R_load = 50
[Rising Waveform]
R_fixture = 50
V_fixture = 2.75
V_fixture_min = 2.475
V_fixture_max = 3.025
0s        1.187V     1.281V     1.122V
200.2ps   1.189V     1.281V     1.148V
471.8ps   1.28V      1.282V     1.461V
586.8ps   1.381V     1.285V     1.876V
729.4ps   1.55V      1.313V     2.776V
864.3ps   1.93V      1.374V     2.986V
1.006ns   2.488V     1.464V     2.993V
1.106ns   2.664V     1.54V      3.006V
1.793ns   2.743V     2.434V     3.024V
5.12ns    2.75V      2.475V     3.025V
[Rising Waveform]
R_fixture = 50
V_fixture = 0
V_fixture_min = 0
V_fixture_max = 0
0s        0V         0V         170.6uV
220.5ps   0V         0V         18.24mV
500ps     51.43mV    0V         247.9mV
651.3ps   113.5mV    0V         577.1mV
861.3ps   276.1mV    21.74mV    1.487V
1.182ns   958.3mV    85.37mV    1.897V
1.652ns   1.53V      355.6mV    1.931V
2.194ns   1.589V     854.6mV    1.932V
2.744ns   1.591V     1.159V     1.932V
5.212ns   1.592V     1.22V      1.933V
[Falling Waveform]
R_fixture = 50
V_fixture = 2.75
V_fixture_min = 2.475
V_fixture_max = 3.025
0s        2.75V      2.475V     3.025V
475.6ps   2.716V     2.476V     2.849V
562.4ps   2.678V     2.486V     2.671V
898.3ps   2.41V      2.45V      1.509V
1.208ns   1.834V     2.392V     1.165V
1.407ns   1.47V      2.338V     1.131V
1.746ns   1.231V     2.04V      1.123V
2.278ns   1.191V     1.597V     1.122V
2.778ns   1.187V     1.348V     1.122V
5.12ns    1.186V     1.28V      1.121V
[Falling Waveform]
R_fixture = 50
V_fixture = 0
V_fixture_min = 0
V_fixture_max = 0
0s        1.592V     1.22V      1.933V
184.5ps   1.592V     1.22V      1.905V
360.5ps   1.558V     1.22V      1.586V
463.8ps   1.438V     1.22V      1.188V
625.4ps   1.116V     1.21V      278.1mV
774.4ps   661.8mV    1.13V      48.16mV
911.2ps   225mV      992.6mV    15.41mV
1.016ns   71.91mV    836.5mV    12.92mV
1.661ns   9.392mV    41.61mV    1.481mV
5.212ns   3.828uV    69.36uV    0V
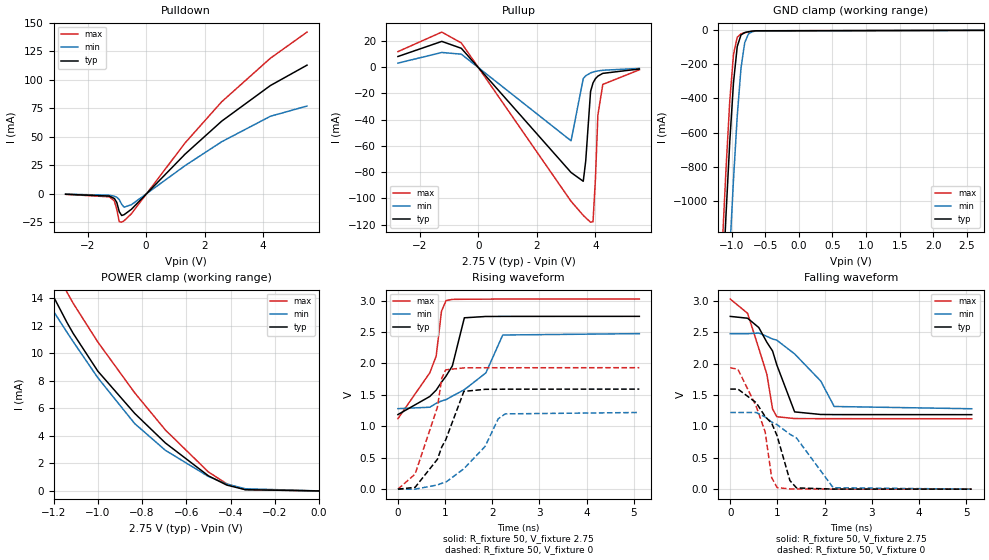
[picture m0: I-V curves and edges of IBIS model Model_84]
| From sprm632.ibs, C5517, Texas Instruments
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| Model based on original model for BC3340CTSCHYPD
|   Sub model SR0_VDD_SR1_VDD_PD_OFF_COM_2P75
[model]   Model_84
|[Description]  [2.75V-I/O-PD_OFF-X, COM]
|   PD_OFF,COM,
|[Input Load]   PD_OFF
|[Output Drive]
|Voltage   2.75V
|Mode   I/O
Model_type   I/O
Polarity   Non-Inverting
Enable   Active-Low
Vinl =  0.7
Vinh =  1.7
Cref =  15.0000pF
Rref =  100.0000M
Vref =  0V
Vmeas =  1.375
C_comp   2.1456989p   2.0494201p   2.2784851p
[Model Spec]
Vinl   0.7   0.7   0.7
Vinh   1.7   1.7   1.7
[Temperature Range]   25   105   -10
[Voltage Range]   2.75   2.475   3.025
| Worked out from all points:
|   slope of the pulldown table from 0 to 0.412 V, typ, clamps not added: 37.1 ohm
|   slope of the pullup table from 0 to 0.412 V, typ, clamps not added: 35.9 ohm
|   GND clamp passes 1 mA (typ) near -0.58 V on its own axis
|   POWER clamp passes 1 mA (typ) near -0.49 V on its own axis
|   rising waveform, R_fixture 50, V_fixture 2.75: 20-80 % time 564ps typ, 807ps min, 460ps max; typ from 1.19 V to 2.75 V
|   rising waveform, R_fixture 50, V_fixture 0: 20-80 % time 567ps typ, 804ps min, 464ps max; typ from 0 V to 1.59 V
|   falling waveform, R_fixture 50, V_fixture 2.75: 20-80 % time 532ps typ, 786ps min, 413ps max; typ from 2.75 V to 1.19 V
|   falling waveform, R_fixture 50, V_fixture 0: 20-80 % time 554ps typ, 830ps min, 430ps max; typ from 1.59 V to 0 V
[POWER_clamp]
-2.75V    68.47mA    53.36mA    84.04mA
-1.25V    15.74mA    14.31mA    18.28mA
-1.194V   13.94mA    12.91mA    16.24mA
-1.139V   12.24mA    11.53mA    14.44mA
-1.111V   11.45mA    10.85mA    13.64mA
-1V       8.713mA    8.23mA     10.83mA
-833.3mV  5.639mA    4.898mA    7.135mA
-694.4mV  3.486mA    2.951mA    4.429mA
-500mV    1.096mA    1.05mA     1.377mA
-416.7mV  423.4uA    494.2uA    514.4uA
-333.3mV  89.36uA    156.8uA    95.66uA
0V        635.3pA    4.99nA     662.4pA
[Pulldown]
-2.75V    -308.5uA   -227.6uA   -371.5uA
-1.25V    -1.93mA    -1.163mA   -2.58mA
-1.083V   -4.054mA   -1.991mA   -6.245mA
-1V       -7.547mA   -2.954mA   -13.7mA
-916.7mV  -15.6mA    -5.046mA   -24.44mA
-833.3mV  -18.95mA   -9.138mA   -24.82mA
-750mV    -18.23mA   -11.68mA   -23.55mA
-500mV    -13.48mA   -9.45mA    -17.38mA
1.333V    34.87mA    24.79mA    44.69mA
2.583V    63.77mA    45.72mA    80.76mA
4.25V     95.04mA    68.08mA    119mA
5.5V      112.9mA    77.06mA    141.9mA
[Pullup]
-2.75V    8.15mA     3.088mA    11.86mA
-1.25V    19.65mA    11.21mA    26.74mA
-583.3mV  14.38mA    9.918mA    18.47mA
3.167V    -80.24mA   -56.1mA    -102.2mA
3.583V    -86.93mA   -8.662mA   -112.9mA
3.667V    -71.56mA   -6.559mA   -114.7mA
3.833V    -18.5mA    -4.358mA   -118.1mA
3.917V    -11.98mA   -3.72mA    -117.8mA
4V        -8.724mA   -3.242mA   -84.8mA
4.083V    -6.819mA   -2.87mA    -36.49mA
4.25V     -4.711mA   -2.331mA   -13.16mA
5.5V      -1.388mA   -959.6uA   -2.008mA
[GND_clamp]
-2.75V    -17.03A    -17.67A    -16.78A
-1.139V   -1.54A     -2.231A    -1.261A
-1.083V   -1.078A    -1.755A    -809.5mA
-1.028V   -655mA     -1.299A    -414.9mA
-972.2mV  -306mA     -874.1mA   -141.2mA
-916.7mV  -94.92mA   -503mA     -40.37mA
-861.1mV  -27.21mA   -223.1mA   -20.83mA
-805.6mV  -13.06mA   -72.23mA   -14.17mA
-750mV    -8.039mA   -21.19mA   -9.394mA
-694.4mV  -4.823mA   -8.017mA   -5.589mA
-638.9mV  -2.532mA   -3.789mA   -2.808mA
2.75V     635.3pA    52.4uA     -264.9pA
[Ramp]
dV/dt_f  0.9455281/0.53802105n 0.72304167/0.79607486n  1.1501773/0.41679253n
dV/dt_r 0.95647345/0.56865927n 0.73294167/0.80597593n  1.1607758/0.46448488n
R_load = 50
[Rising Waveform]
R_fixture = 50
V_fixture = 2.75
V_fixture_min = 2.475
V_fixture_max = 3.025
0s        1.187V     1.281V     1.122V
675.5ps   1.475V     1.304V     1.851V
811.3ps   1.576V     1.366V     2.118V
923.8ps   1.702V     1.403V     2.832V
1.021ns   1.8V       1.425V     3.001V
1.154ns   1.961V     1.481V     3.02V
1.409ns   2.727V     1.583V     3.022V
1.865ns   2.748V     1.85V      3.024V
2.223ns   2.749V     2.453V     3.025V
5.12ns    2.75V      2.475V     3.025V
[Rising Waveform]
R_fixture = 50
V_fixture = 0
V_fixture_min = 0
V_fixture_max = 0
0s        0V         0V         0V
363.8ps   28.97mV    0V         239.8mV
838.3ps   476.8mV    66.94mV    1.307V
929.2ps   670.5mV    93.1mV     1.763V
1.014ns   786.4mV    110.4mV    1.899V
1.399ns   1.556V     325.2mV    1.93V
1.851ns   1.589V     682.4mV    1.932V
2.127ns   1.59V      1.12V      1.932V
2.275ns   1.591V     1.198V     1.932V
5.12ns    1.592V     1.22V      1.933V
[Falling Waveform]
R_fixture = 50
V_fixture = 2.75
V_fixture_min = 2.475
V_fixture_max = 3.025
0s        2.75V      2.475V     3.026V
367.6ps   2.721V     2.475V     2.799V
605.5ps   2.572V     2.485V     2.239V
777.1ps   2.337V     2.432V     1.826V
897.4ps   2.199V     2.39V      1.276V
987.5ps   1.977V     2.371V     1.153V
1.365ns   1.23V      2.153V     1.124V
1.919ns   1.189V     1.721V     1.122V
2.204ns   1.187V     1.316V     1.122V
5.12ns    1.186V     1.28V      1.121V
[Falling Waveform]
R_fixture = 50
V_fixture = 0
V_fixture_min = 0
V_fixture_max = 0
0s        1.593V     1.22V      1.933V
162.3ps   1.593V     1.22V      1.908V
549.2ps   1.377V     1.221V     1.32V
740.2ps   1.156V     1.148V     911.4mV
878.4ps   1.049V     1.068V     183.3mV
992.9ps   850.4mV    1.027V     24.19mV
1.265ns   137.2mV    874.7mV    3.937mV
1.405ns   20.1mV     814mV      2.754mV
2.183ns   1.441mV    22.9mV     722.8uV
5.12ns    6.513uV    116uV      0V
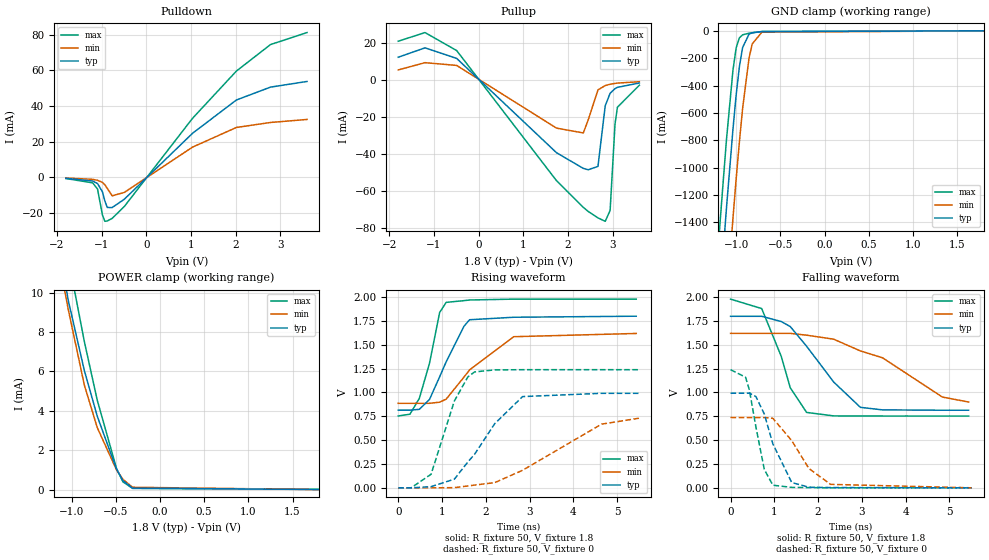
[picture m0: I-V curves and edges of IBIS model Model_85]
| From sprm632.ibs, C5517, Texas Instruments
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| Model based on original model for BC3340CTSCHYPD
|   Sub model SR0_VSS_SR1_VSS_PD_ON_IND_1P8
[model]   Model_85
|[Description]  [1.8V-I/O-PD-X, IND]
|   PD,IND,
|[Input Load]   PD
|[Output Drive]
|Voltage   1.8V
|Mode   I/O
Model_type   I/O
Polarity   Non-Inverting
Enable   Active-Low
Vinl =  0.63
Vinh =  1.17
Cref =  15.0000pF
Rref =  100.0000M
Vref =  0V
Vmeas =  0.9
C_comp   2.213767p   2.135548p   2.3400939p
[Model Spec]
Vinl   0.63   0.567   0.693
Vinh   1.17   1.053   1.287
[Temperature Range]   25   105   -40
[Voltage Range]   1.8   1.62   1.98
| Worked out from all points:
|   slope of the pulldown table from 0 to 0.27 V, typ, clamps not added: 40.2 ohm
|   slope of the pullup table from 0 to 0.27 V, typ, clamps not added: 39.6 ohm
|   GND clamp passes 1 mA (typ) near -0.57 V on its own axis
|   POWER clamp passes 1 mA (typ) near -0.49 V on its own axis
|   rising waveform, R_fixture 50, V_fixture 1.8: 20-80 % time 596ps typ, 940ps min, 366ps max; typ from 0.815 V to 1.8 V
|   rising waveform, R_fixture 50, V_fixture 0: 20-80 % time 1.01ns typ, 1.72ns min, 549ps max; typ from 0 V to 0.991 V
|   falling waveform, R_fixture 50, V_fixture 1.8: 20-80 % time 1.09ns typ, 1.83ns min, 578ps max; typ from 1.8 V to 0.814 V
|   falling waveform, R_fixture 50, V_fixture 0: 20-80 % time 427ps typ, 615ps min, 298ps max; typ from 0.992 V to 0 V
[POWER_clamp]
-1.8V     35.48mA    28.89mA    41.39mA
-1.4V     21.05mA    18.3mA     23.34mA
-1.291V   17.25mA    15.47mA    18.99mA
-1.218V   14.82mA    13.6mA     16.55mA
-1.109V   11.48mA    10.87mA    13.56mA
-1.036V   9.59mA     9.127mA    11.74mA
-854.5mV  6.038mA    5.298mA    7.506mA
-709.1mV  3.728mA    3.147mA    4.541mA
-490.9mV  1.031mA    994.5uA    1.066mA
-418.2mV  453.6uA    514.8uA    389.5uA
-309.1mV  70.25uA    113.8uA    55uA
1.8V      -5.798nA   -5.194uA   9.765uA
[Pulldown]
-1.8V     -609.1uA   -416.1uA   -732.6uA
-1.2V     -2.106mA   -1.185mA   -3.14mA
-1.091V   -3.54mA    -1.719mA   -6.628mA
-981.8mV  -8.172mA   -2.924mA   -21.11mA
-927.3mV  -13.32mA   -4.178mA   -24.72mA
-872.7mV  -16.96mA   -6.282mA   -24.52mA
-763.6mV  -17.01mA   -10.42mA   -23.08mA
-490.9mV  -12.33mA   -8.513mA   -16.39mA
1.036V    24.65mA    16.9mA     33.06mA
2.018V    43.34mA    27.92mA    59.56mA
2.782V    50.56mA    30.73mA    74.44mA
3.6V      53.74mA    32.42mA    81.17mA
[Pullup]
-1.8V     12.32mA    5.441mA    20.99mA
-1.2V     17.41mA    9.382mA    25.68mA
-490.9mV  11.68mA    7.892mA    15.93mA
1.745V    -39.39mA   -26.07mA   -54.54mA
2.345V    -47.87mA   -28.67mA   -68.99mA
2.455V    -48.61mA   -21.59mA   -71.2mA
2.673V    -46.79mA   -5.376mA   -74.67mA
2.836V    -13.94mA   -3.011mA   -76.52mA
2.945V    -7.197mA   -2.3mA     -70.68mA
3.055V    -4.694mA   -1.854mA   -23.89mA
3.109V    -3.979mA   -1.688mA   -14.73mA
3.6V      -1.642mA   -928.2uA   -2.847mA
[GND_clamp]
-1.8V     -7.733A    -8.408A    -7.245A
-1.182V   -1.913A    -2.609A    -1.399A
-1.145V   -1.597A    -2.289A    -1.087A
-1.109V   -1.289A    -1.974A    -790.4mA
-1.036V   -716.9mA   -1.367A    -285.6mA
-1V       -467.4mA   -1.081A    -124.1mA
-963.6mV  -262.8mA   -812.5mA   -51.38mA
-927.3mV  -122.1mA   -568.2mA   -29.27mA
-854.5mV  -24.37mA   -198.6mA   -17.32mA
-818.2mV  -14.88mA   -95.25mA   -13.62mA
-709.1mV  -5.604mA   -10.06mA   -5.016mA
1.8V      20.41uA    17.88uA    35.18uA
[Ramp]
dV/dt_f 0.59938836/1.1009196n 0.44655713/1.8781699n 0.74498516/0.58285336n
dV/dt_r 0.59723212/1.008604n  0.44419829/1.7324177n 0.74594934/0.55036303n
R_load = 50
[Rising Waveform]
R_fixture = 50
V_fixture = 1.8
V_fixture_min = 1.62
V_fixture_max = 1.98
0s        814.5mV    886.5mV    753.7mV
267.5ps   814.6mV    886.5mV    772.3mV
482.2ps   823.4mV    886.5mV    937.8mV
714.3ps   926.4mV    886.5mV    1.305V
946.4ps   1.164V     898.3mV    1.839V
1.096ns   1.322V     930.5mV    1.945V
1.502ns   1.694V     1.161V     1.963V
1.631ns   1.763V     1.237V     1.97V
2.64ns    1.789V     1.585V     1.979V
5.439ns   1.8V       1.619V     1.979V
[Rising Waveform]
R_fixture = 50
V_fixture = 0
V_fixture_min = 0
V_fixture_max = 0
0s        0V         35.45uV    0V
292.5ps   0V         35.45uV    0V
751.2ps   12.85mV    35.45uV    142.7mV
1.283ns   91.29mV    2.2mV      911mV
1.592ns   272.3mV    19.75mV    1.164V
1.746ns   352.7mV    29.22mV    1.216V
2.205ns   672.9mV    54.8mV     1.237V
2.842ns   957.1mV    184.5mV    1.239V
4.646ns   991.3mV    668mV      1.239V
5.51ns    991.4mV    730.9mV    1.239V
[Falling Waveform]
R_fixture = 50
V_fixture = 1.8
V_fixture_min = 1.62
V_fixture_max = 1.98
0s        1.799V     1.62V      1.979V
712ps     1.799V     1.62V      1.88V
1.159ns   1.744V     1.62V      1.378V
1.365ns   1.691V     1.62V      1.049V
1.738ns   1.485V     1.601V     791.1mV
2.356ns   1.11V      1.559V     754.5mV
2.967ns   844.3mV    1.436V     753.3mV
3.472ns   817.8mV    1.364V     753.2mV
4.84ns    814mV      952.2mV    753.1mV
5.439ns   813.9mV    900.1mV    753.1mV
[Falling Waveform]
R_fixture = 50
V_fixture = 0
V_fixture_min = 0
V_fixture_max = 0
0s        992.2mV    737.7mV    1.239V
343.3ps   992.2mV    737.7mV    1.16V
430.5ps   992.7mV    737.7mV    1.026V
577.9ps   958mV      737.7mV    642.3mV
771.5ps   774.3mV    737.7mV    192.9mV
966.6ps   461.4mV    729.2mV    27.85mV
1.398ns   55.81mV    495.6mV    5.008mV
1.791ns   6.976mV    202.5mV    2.989mV
2.286ns   3.197mV    36.69mV    539.6uV
5.51ns    24.49uV    577.8uV    0V
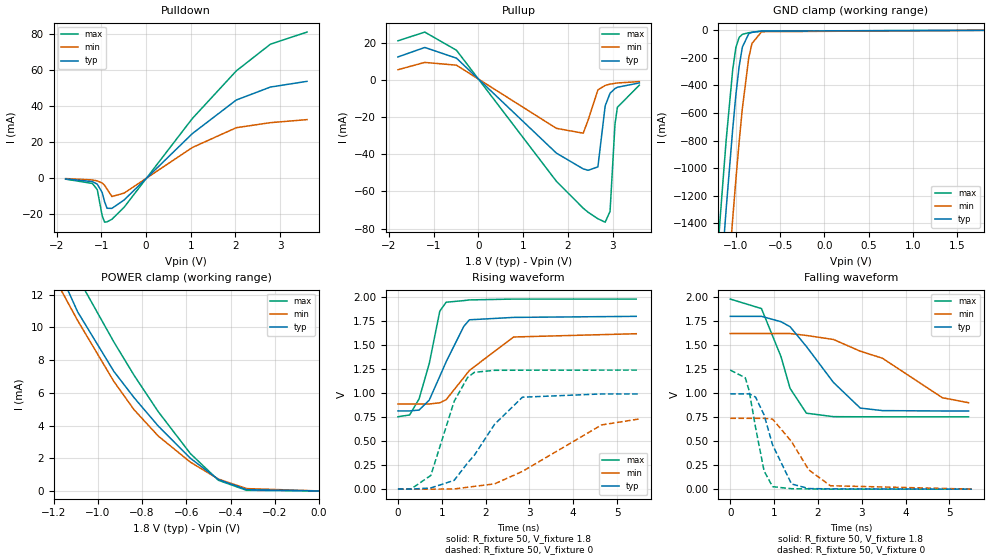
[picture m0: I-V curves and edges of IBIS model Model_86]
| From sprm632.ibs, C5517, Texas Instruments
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| Model based on original model for BC3340CTSCHYPD
|   Sub model SR0_VSS_SR1_VSS_PD_OFF_IND_1P8
[model]   Model_86
|[Description]  [1.8V-I/O-PD_OFF-X, IND]
|   PD_OFF,IND,
|[Input Load]   PD_OFF
|[Output Drive]
|Voltage   1.8V
|Mode   I/O
Model_type   I/O
Polarity   Non-Inverting
Enable   Active-Low
Vinl =  0.63
Vinh =  1.17
Cref =  15.0000pF
Rref =  100.0000M
Vref =  0V
Vmeas =  0.9
C_comp   2.213767p   2.135548p   2.3400939p
[Model Spec]
Vinl   0.63   0.567   0.693
Vinh   1.17   1.053   1.287
[Temperature Range]   25   105   -40
[Voltage Range]   1.8   1.62   1.98
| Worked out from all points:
|   slope of the pulldown table from 0 to 0.27 V, typ, clamps not added: 40.2 ohm
|   slope of the pullup table from 0 to 0.27 V, typ, clamps not added: 39.6 ohm
|   GND clamp passes 1 mA (typ) near -0.58 V on its own axis
|   POWER clamp passes 1 mA (typ) near -0.49 V on its own axis
|   rising waveform, R_fixture 50, V_fixture 1.8: 20-80 % time 596ps typ, 940ps min, 367ps max; typ from 0.815 V to 1.8 V
|   rising waveform, R_fixture 50, V_fixture 0: 20-80 % time 1.01ns typ, 1.72ns min, 547ps max; typ from 0 V to 0.992 V
|   falling waveform, R_fixture 50, V_fixture 1.8: 20-80 % time 1.09ns typ, 1.83ns min, 578ps max; typ from 1.8 V to 0.814 V
|   falling waveform, R_fixture 50, V_fixture 0: 20-80 % time 424ps typ, 612ps min, 296ps max; typ from 0.993 V to 0 V
[POWER_clamp]
-1.8V     35.46mA    28.87mA    41.35mA
-1.455V   22.97mA    19.72mA    25.66mA
-1.291V   17.23mA    15.45mA    18.95mA
-1.2V     14.21mA    13.13mA    15.98mA
-1.091V   10.95mA    10.42mA    13.06mA
-927.3mV  7.308mA    6.692mA    9.107mA
-836.4mV  5.709mA    4.97mA     7.078mA
-727.3mV  3.976mA    3.363mA    4.855mA
-581.8mV  2.001mA    1.761mA    2.286mA
-454.5mV  692.8uA    724.7uA    647.3uA
-327.3mV  77.63uA    141.5uA    35.53uA
0V        360.5pA    3.06nA     310.1pA
[Pulldown]
-1.8V     -609.1uA   -416.1uA   -732.6uA
-1.2V     -2.106mA   -1.185mA   -3.14mA
-1.091V   -3.54mA    -1.719mA   -6.628mA
-981.8mV  -8.172mA   -2.924mA   -21.11mA
-927.3mV  -13.32mA   -4.178mA   -24.71mA
-872.7mV  -16.96mA   -6.282mA   -24.52mA
-763.6mV  -17.01mA   -10.42mA   -23.08mA
-490.9mV  -12.33mA   -8.513mA   -16.39mA
1.036V    24.65mA    16.9mA     33.06mA
2.018V    43.34mA    27.92mA    59.56mA
2.782V    50.56mA    30.73mA    74.44mA
3.6V      53.74mA    32.42mA    81.17mA
[Pullup]
-1.8V     12.32mA    5.441mA    20.99mA
-1.2V     17.41mA    9.382mA    25.68mA
-490.9mV  11.68mA    7.892mA    15.93mA
1.745V    -39.39mA   -26.07mA   -54.54mA
2.345V    -47.87mA   -28.67mA   -68.99mA
2.455V    -48.61mA   -21.59mA   -71.2mA
2.673V    -46.79mA   -5.376mA   -74.67mA
2.836V    -13.94mA   -3.011mA   -76.52mA
2.945V    -7.197mA   -2.3mA     -70.67mA
3.055V    -4.694mA   -1.854mA   -23.89mA
3.109V    -3.979mA   -1.688mA   -14.73mA
3.6V      -1.642mA   -928.2uA   -2.847mA
[GND_clamp]
-1.8V     -7.733A    -8.408A    -7.245A
-1.182V   -1.913A    -2.609A    -1.399A
-1.145V   -1.597A    -2.289A    -1.087A
-1.109V   -1.289A    -1.974A    -790.4mA
-1.036V   -716.9mA   -1.367A    -285.6mA
-1V       -467.4mA   -1.081A    -124.1mA
-963.6mV  -262.8mA   -812.5mA   -51.35mA
-927.3mV  -122.1mA   -568.2mA   -29.23mA
-854.5mV  -24.35mA   -198.6mA   -17.26mA
-818.2mV  -14.85mA   -95.24mA   -13.56mA
-709.1mV  -5.572mA   -10.04mA   -4.967mA
1.8V      360.5pA    6.236uA    210.9pA
[Ramp]
dV/dt_f 0.59940056/1.1003659n 0.44655317/1.8772093n 0.74503244/0.58233895n
dV/dt_r 0.59752652/1.0081069n 0.44440492/1.7330276n 0.74637109/0.54778774n
R_load = 50
[Rising Waveform]
R_fixture = 50
V_fixture = 1.8
V_fixture_min = 1.62
V_fixture_max = 1.98
0s        814.9mV    886.9mV    754.3mV
267.5ps   815mV      886.9mV    773mV
482.2ps   823.9mV    886.9mV    939.5mV
714.3ps   927.3mV    886.9mV    1.307V
955.1ps   1.175V     899.8mV    1.854V
1.101ns   1.327V     932.4mV    1.947V
1.501ns   1.694V     1.161V     1.964V
1.631ns   1.764V     1.237V     1.971V
2.64ns    1.789V     1.585V     1.98V
5.439ns   1.8V       1.619V     1.98V
[Rising Waveform]
R_fixture = 50
V_fixture = 0
V_fixture_min = 0
V_fixture_max = 0
0s        0V         39.27uV    0V
292.5ps   0V         39.27uV    0V
751.2ps   12.93mV    39.27uV    143.3mV
1.283ns   91.7mV     2.224mV    915mV
1.592ns   274.2mV    19.85mV    1.165V
1.746ns   354.8mV    29.36mV    1.217V
2.205ns   675.2mV    54.96mV    1.238V
2.841ns   957.8mV    184.9mV    1.239V
4.646ns   991.9mV    668.9mV    1.24V
5.51ns    991.9mV    731.3mV    1.24V
[Falling Waveform]
R_fixture = 50
V_fixture = 1.8
V_fixture_min = 1.62
V_fixture_max = 1.98
0s        1.8V       1.621V     1.98V
712.1ps   1.8V       1.621V     1.881V
1.159ns   1.744V     1.621V     1.379V
1.365ns   1.692V     1.621V     1.05V
1.738ns   1.486V     1.601V     791.3mV
2.356ns   1.111V     1.559V     755.1mV
2.967ns   844.6mV    1.437V     753.9mV
3.472ns   818.2mV    1.364V     753.8mV
4.84ns    814.4mV    952.6mV    753.7mV
5.439ns   814.3mV    900.4mV    753.7mV
[Falling Waveform]
R_fixture = 50
V_fixture = 0
V_fixture_min = 0
V_fixture_max = 0
0s        992.7mV    738mV      1.24V
343.3ps   992.7mV    738mV      1.16V
430.5ps   993.1mV    738mV      1.026V
577.9ps   958.4mV    738mV      641.4mV
771.4ps   774.7mV    738mV      190.1mV
966.6ps   460.1mV    729.5mV    25.87mV
1.398ns   54.24mV    495.7mV    4.59mV
1.791ns   6.379mV    201.2mV    2.785mV
2.286ns   2.975mV    35.78mV    434.5uV
5.51ns    7.802uV    536uV      0V
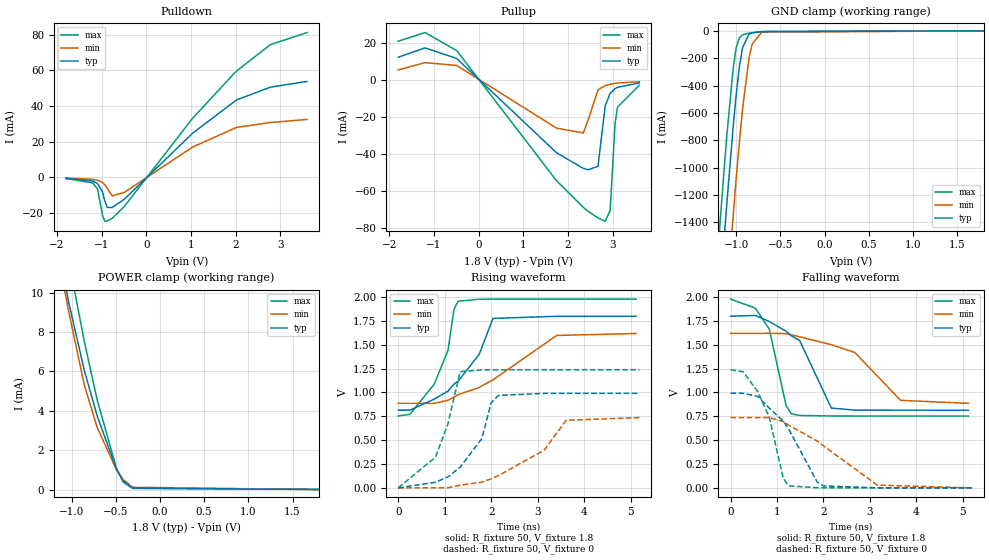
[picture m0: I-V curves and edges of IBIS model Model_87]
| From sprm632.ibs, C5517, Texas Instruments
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| Model based on original model for BC3340CTSCHYPD
|   Sub model SR0_VDD_SR1_VDD_PD_ON_IND_1P8
[model]   Model_87
|[Description]  [1.8V-I/O-PD-X, IND]
|   PD,IND,
|[Input Load]   PD
|[Output Drive]
|Voltage   1.8V
|Mode   I/O
Model_type   I/O
Polarity   Non-Inverting
Enable   Active-Low
Vinl =  0.63
Vinh =  1.17
Cref =  15.0000pF
Rref =  100.0000M
Vref =  0V
Vmeas =  0.9
C_comp   2.213767p   2.135548p   2.3400939p
[Model Spec]
Vinl   0.63   0.567   0.693
Vinh   1.17   1.053   1.287
[Temperature Range]   25   105   -40
[Voltage Range]   1.8   1.62   1.98
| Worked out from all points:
|   slope of the pulldown table from 0 to 0.27 V, typ, clamps not added: 40.2 ohm
|   slope of the pullup table from 0 to 0.27 V, typ, clamps not added: 39.6 ohm
|   GND clamp passes 1 mA (typ) near -0.57 V on its own axis
|   POWER clamp passes 1 mA (typ) near -0.49 V on its own axis
|   rising waveform, R_fixture 50, V_fixture 1.8: 20-80 % time 803ps typ, 1.58ns min, 528ps max; typ from 0.814 V to 1.8 V
|   rising waveform, R_fixture 50, V_fixture 0: 20-80 % time 679ps typ, 1.04ns min, 490ps max; typ from 0 V to 0.991 V
|   falling waveform, R_fixture 50, V_fixture 1.8: 20-80 % time 657ps typ, 1.08ns min, 436ps max; typ from 1.8 V to 0.814 V
|   falling waveform, R_fixture 50, V_fixture 0: 20-80 % time 766ps typ, 1.44ns min, 470ps max; typ from 0.992 V to 0 V
[POWER_clamp]
-1.8V     35.48mA    28.89mA    41.39mA
-1.4V     21.05mA    18.3mA     23.34mA
-1.291V   17.25mA    15.47mA    18.99mA
-1.218V   14.82mA    13.6mA     16.55mA
-1.109V   11.48mA    10.87mA    13.56mA
-1.036V   9.59mA     9.127mA    11.74mA
-854.5mV  6.038mA    5.298mA    7.506mA
-709.1mV  3.728mA    3.147mA    4.541mA
-490.9mV  1.031mA    994.5uA    1.066mA
-418.2mV  453.6uA    514.8uA    389.5uA
-309.1mV  70.25uA    113.8uA    55uA
1.8V      -5.798nA   -5.194uA   9.765uA
[Pulldown]
-1.8V     -609.1uA   -416.1uA   -732.6uA
-1.2V     -2.106mA   -1.185mA   -3.14mA
-1.091V   -3.54mA    -1.719mA   -6.628mA
-981.8mV  -8.172mA   -2.924mA   -21.11mA
-927.3mV  -13.32mA   -4.178mA   -24.72mA
-872.7mV  -16.96mA   -6.282mA   -24.52mA
-763.6mV  -17.01mA   -10.42mA   -23.08mA
-490.9mV  -12.33mA   -8.513mA   -16.39mA
1.036V    24.65mA    16.9mA     33.06mA
2.018V    43.34mA    27.92mA    59.56mA
2.782V    50.56mA    30.73mA    74.44mA
3.6V      53.74mA    32.42mA    81.17mA
[Pullup]
-1.8V     12.32mA    5.441mA    20.99mA
-1.2V     17.41mA    9.382mA    25.68mA
-490.9mV  11.68mA    7.892mA    15.93mA
1.745V    -39.39mA   -26.07mA   -54.54mA
2.345V    -47.87mA   -28.67mA   -68.99mA
2.455V    -48.61mA   -21.59mA   -71.2mA
2.673V    -46.79mA   -5.376mA   -74.67mA
2.836V    -13.94mA   -3.011mA   -76.52mA
2.945V    -7.197mA   -2.3mA     -70.68mA
3.055V    -4.694mA   -1.854mA   -23.89mA
3.109V    -3.979mA   -1.688mA   -14.73mA
3.6V      -1.642mA   -928.2uA   -2.847mA
[GND_clamp]
-1.8V     -7.733A    -8.408A    -7.245A
-1.182V   -1.913A    -2.609A    -1.399A
-1.145V   -1.597A    -2.289A    -1.087A
-1.109V   -1.289A    -1.974A    -790.4mA
-1.036V   -716.9mA   -1.367A    -285.6mA
-1V       -467.4mA   -1.081A    -124.1mA
-963.6mV  -262.8mA   -812.5mA   -51.38mA
-927.3mV  -122.1mA   -568.2mA   -29.27mA
-854.5mV  -24.37mA   -198.6mA   -17.32mA
-818.2mV  -14.88mA   -95.25mA   -13.62mA
-709.1mV  -5.604mA   -10.06mA   -5.016mA
1.8V      20.41uA    17.88uA    35.18uA
[Ramp]
dV/dt_f 0.59674535/0.67583689n 0.44446585/1.1171761n 0.74197366/0.44590382n
dV/dt_r 0.59638577/0.6852442n 0.44351184/1.0611469n 0.74487329/0.49242775n
R_load = 50
[Rising Waveform]
R_fixture = 50
V_fixture = 1.8
V_fixture_min = 1.62
V_fixture_max = 1.98
0s        814.5mV    886.6mV    753.7mV
252.1ps   814.5mV    886.6mV    771.1mV
777.6ps   931.2mV    886.7mV    1.09V
1.072ns   1.014V     918.3mV    1.443V
1.201ns   1.089V     952.2mV    1.875V
1.29ns    1.119V     976.9mV    1.957V
1.742ns   1.399V     1.053V     1.978V
2.04ns    1.777V     1.133V     1.979V
3.41ns    1.799V     1.598V     1.979V
5.12ns    1.8V       1.619V     1.979V
[Rising Waveform]
R_fixture = 50
V_fixture = 0
V_fixture_min = 0
V_fixture_max = 0
0s        0V         0V         0V
801.8ps   58.72mV    0V         321.7mV
1.069ns   114.6mV    1.266mV    669.6mV
1.333ns   216.5mV    28.29mV    1.218V
1.801ns   517.7mV    59.5mV     1.237V
2ns       892.9mV    95.43mV    1.238V
2.159ns   969.7mV    129.2mV    1.238V
3.143ns   990.7mV    396.2mV    1.239V
3.613ns   991.1mV    708mV      1.239V
5.19ns    991.4mV    736.7mV    1.239V
[Falling Waveform]
R_fixture = 50
V_fixture = 1.8
V_fixture_min = 1.62
V_fixture_max = 1.98
0s        1.8V       1.62V      1.979V
532ps     1.808V     1.62V      1.885V
832.4ps   1.745V     1.621V     1.665V
1.197ns   1.642V     1.617V     860.9mV
1.305ns   1.595V     1.605V     777mV
1.486ns   1.546V     1.585V     759.3mV
2.17ns    836.5mV    1.501V     753.8mV
2.675ns   815.4mV    1.42V      753.4mV
3.659ns   814.2mV    917.8mV    753.1mV
5.12ns    813.9mV    886.2mV    753.1mV
[Falling Waveform]
R_fixture = 50
V_fixture = 0
V_fixture_min = 0
V_fixture_max = 0
0s        992.1mV    737.5mV    1.239V
270.4ps   992.1mV    737.5mV    1.218V
587.3ps   958.8mV    737.5mV    1.008V
832ps     835.7mV    737.5mV    742.5mV
1.135ns   700.7mV    696.2mV    100mV
1.249ns   617.8mV    658.7mV    20.69mV
1.865ns   60.64mV    491.3mV    1.452mV
1.996ns   20.58mV    442.4mV    1.151mV
3.158ns   631uV      28.63mV    157.2uV
5.19ns    39.27uV    287.6uV    1.036uV
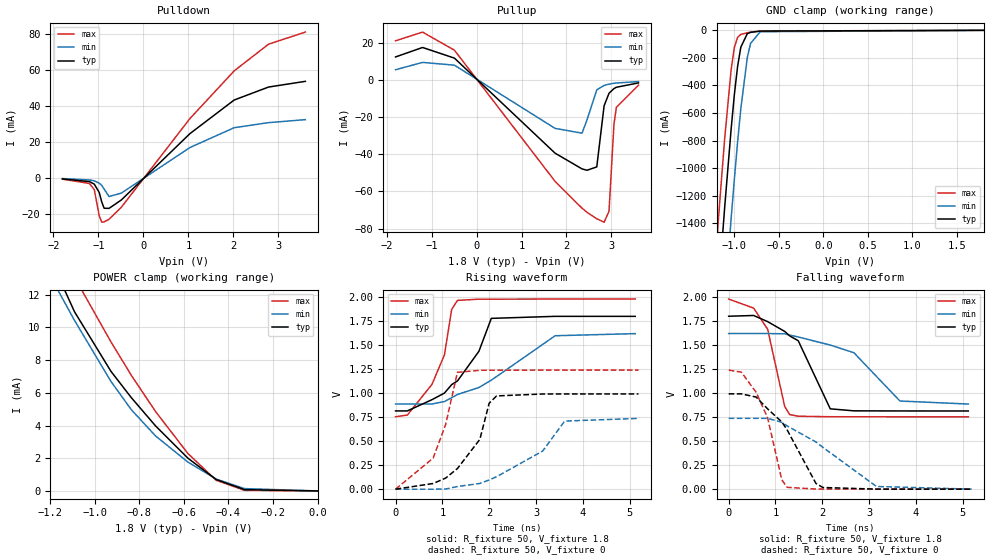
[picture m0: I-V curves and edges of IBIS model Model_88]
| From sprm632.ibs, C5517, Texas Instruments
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| Model based on original model for BC3340CTSCHYPD
|   Sub model SR0_VDD_SR1_VDD_PD_OFF_IND_1P8
[model]   Model_88
|[Description]  [1.8V-I/O-PD_OFF-X, IND]
|   PD_OFF,IND,
|[Input Load]   PD_OFF
|[Output Drive]
|Voltage   1.8V
|Mode   I/O
Model_type   I/O
Polarity   Non-Inverting
Enable   Active-Low
Vinl =  0.63
Vinh =  1.17
Cref =  15.0000pF
Rref =  100.0000M
Vref =  0V
Vmeas =  0.9
C_comp   2.213767p   2.135548p   2.3400939p
[Model Spec]
Vinl   0.63   0.567   0.693
Vinh   1.17   1.053   1.287
[Temperature Range]   25   105   -40
[Voltage Range]   1.8   1.62   1.98
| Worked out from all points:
|   slope of the pulldown table from 0 to 0.27 V, typ, clamps not added: 40.2 ohm
|   slope of the pullup table from 0 to 0.27 V, typ, clamps not added: 39.6 ohm
|   GND clamp passes 1 mA (typ) near -0.58 V on its own axis
|   POWER clamp passes 1 mA (typ) near -0.49 V on its own axis
|   rising waveform, R_fixture 50, V_fixture 1.8: 20-80 % time 803ps typ, 1.58ns min, 528ps max; typ from 0.815 V to 1.8 V
|   rising waveform, R_fixture 50, V_fixture 0: 20-80 % time 680ps typ, 1.04ns min, 491ps max; typ from 0 V to 0.992 V
|   falling waveform, R_fixture 50, V_fixture 1.8: 20-80 % time 657ps typ, 1.08ns min, 436ps max; typ from 1.8 V to 0.814 V
|   falling waveform, R_fixture 50, V_fixture 0: 20-80 % time 766ps typ, 1.44ns min, 470ps max; typ from 0.993 V to 0 V
[POWER_clamp]
-1.8V     35.46mA    28.87mA    41.35mA
-1.455V   22.97mA    19.72mA    25.66mA
-1.291V   17.23mA    15.45mA    18.95mA
-1.2V     14.21mA    13.13mA    15.98mA
-1.091V   10.95mA    10.42mA    13.06mA
-927.3mV  7.308mA    6.692mA    9.107mA
-836.4mV  5.709mA    4.97mA     7.078mA
-727.3mV  3.976mA    3.363mA    4.855mA
-581.8mV  2.001mA    1.761mA    2.286mA
-454.5mV  692.8uA    724.7uA    647.3uA
-327.3mV  77.63uA    141.5uA    35.53uA
0V        360.5pA    3.06nA     310.1pA
[Pulldown]
-1.8V     -609.1uA   -416.1uA   -732.6uA
-1.2V     -2.106mA   -1.185mA   -3.14mA
-1.091V   -3.54mA    -1.719mA   -6.628mA
-981.8mV  -8.172mA   -2.924mA   -21.11mA
-927.3mV  -13.32mA   -4.178mA   -24.71mA
-872.7mV  -16.96mA   -6.282mA   -24.52mA
-763.6mV  -17.01mA   -10.42mA   -23.08mA
-490.9mV  -12.33mA   -8.513mA   -16.39mA
1.036V    24.65mA    16.9mA     33.06mA
2.018V    43.34mA    27.92mA    59.56mA
2.782V    50.56mA    30.73mA    74.44mA
3.6V      53.74mA    32.42mA    81.17mA
[Pullup]
-1.8V     12.32mA    5.441mA    20.99mA
-1.2V     17.41mA    9.382mA    25.68mA
-490.9mV  11.68mA    7.892mA    15.93mA
1.745V    -39.39mA   -26.07mA   -54.54mA
2.345V    -47.87mA   -28.67mA   -68.99mA
2.455V    -48.61mA   -21.59mA   -71.2mA
2.673V    -46.79mA   -5.376mA   -74.67mA
2.836V    -13.94mA   -3.011mA   -76.52mA
2.945V    -7.197mA   -2.3mA     -70.67mA
3.055V    -4.694mA   -1.854mA   -23.89mA
3.109V    -3.979mA   -1.688mA   -14.73mA
3.6V      -1.642mA   -928.2uA   -2.847mA
[GND_clamp]
-1.8V     -7.733A    -8.408A    -7.245A
-1.182V   -1.913A    -2.609A    -1.399A
-1.145V   -1.597A    -2.289A    -1.087A
-1.109V   -1.289A    -1.974A    -790.4mA
-1.036V   -716.9mA   -1.367A    -285.6mA
-1V       -467.4mA   -1.081A    -124.1mA
-963.6mV  -262.8mA   -812.5mA   -51.35mA
-927.3mV  -122.1mA   -568.2mA   -29.23mA
-854.5mV  -24.35mA   -198.6mA   -17.26mA
-818.2mV  -14.85mA   -95.24mA   -13.56mA
-709.1mV  -5.572mA   -10.04mA   -4.967mA
1.8V      360.5pA    6.236uA    210.9pA
[Ramp]
dV/dt_f 0.59675057/0.67574517n 0.44445907/1.1170675n 0.74201219/0.44576863n
dV/dt_r 0.59667613/0.68603276n 0.44370882/1.0635948n 0.74528699/0.49420078n
R_load = 50
[Rising Waveform]
R_fixture = 50
V_fixture = 1.8
V_fixture_min = 1.62
V_fixture_max = 1.98
0s        814.9mV    886.9mV    754.3mV
252.1ps   814.9mV    886.9mV    771.8mV
777.6ps   931.9mV    887mV      1.091V
1.045ns   1.001V     912.6mV    1.399V
1.199ns   1.089V     952.2mV    1.872V
1.323ns   1.127V     986.2mV    1.966V
1.781ns   1.436V     1.059V     1.979V
2.046ns   1.779V     1.135V     1.979V
3.41ns    1.8V       1.598V     1.98V
5.12ns    1.8V       1.62V      1.98V
[Rising Waveform]
R_fixture = 50
V_fixture = 0
V_fixture_min = 0
V_fixture_max = 0
0s        0V         0V         0V
801.8ps   59mV       0V         322.8mV
1.069ns   115mV      1.268mV    671.2mV
1.322ns   214.7mV    27.25mV    1.217V
1.801ns   518.9mV    59.65mV    1.238V
2ns       895.3mV    95.65mV    1.239V
2.159ns   971.2mV    129.6mV    1.239V
3.143ns   991.2mV    397mV      1.24V
3.613ns   991.6mV    709.1mV    1.24V
5.19ns    991.9mV    737.1mV    1.24V
[Falling Waveform]
R_fixture = 50
V_fixture = 1.8
V_fixture_min = 1.62
V_fixture_max = 1.98
0s        1.801V     1.621V     1.98V
532ps     1.809V     1.621V     1.886V
832.4ps   1.745V     1.621V     1.666V
1.197ns   1.643V     1.618V     860.8mV
1.305ns   1.596V     1.605V     776.9mV
1.486ns   1.546V     1.585V     759.7mV
2.17ns    836.7mV    1.501V     754.4mV
2.675ns   815.8mV    1.421V     754mV
3.659ns   814.6mV    918.1mV    753.7mV
5.12ns    814.3mV    886.6mV    753.7mV
[Falling Waveform]
R_fixture = 50
V_fixture = 0
V_fixture_min = 0
V_fixture_max = 0
0s        992.6mV    737.8mV    1.24V
270.4ps   992.6mV    737.8mV    1.219V
587.3ps   959.3mV    737.8mV    1.009V
832ps     835.9mV    737.8mV    742.5mV
1.135ns   700.7mV    696.4mV    97.55mV
1.249ns   617.6mV    658.8mV    19.21mV
1.865ns   59.17mV    491.3mV    1.205mV
2.013ns   17.37mV    435.6mV    922.3uV
3.157ns   504.6uV    27.95mV    105.1uV
5.19ns    13.38uV    215.3uV    0V
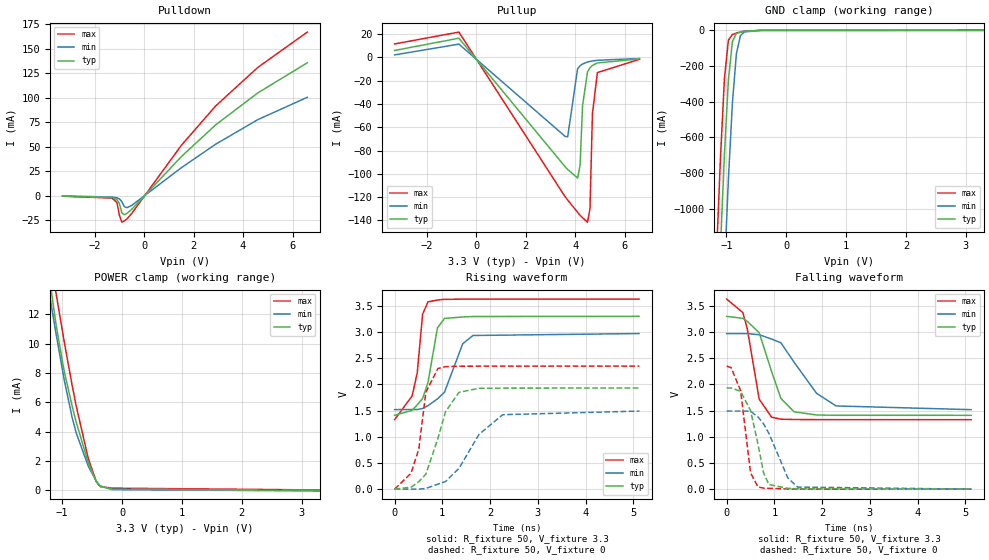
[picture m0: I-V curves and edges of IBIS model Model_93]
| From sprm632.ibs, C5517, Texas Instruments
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| Model based on original model for BC3340CTSCHYPD
|   Sub model SR0_VSS_SR1_VSS_PD_ON_IND_3P3
[model]   Model_93
|[Description]  [3.3V-I/O-PD-X, IND]
|   PD,IND,
|[Input Load]   PD
|[Output Drive]
|Voltage   3.3V
|Mode   I/O
Model_type   I/O
Polarity   Non-Inverting
Enable   Active-Low
Vinl =  0.8
Vinh =  2
Cref =  15.0000pF
Rref =  100.0000M
Vref =  0V
Vmeas =  1.65
C_comp   2.113745p   2.0494201p   2.2478119p
[Model Spec]
Vinl   0.8   0.8   0.8
Vinh   2   2   2
[Temperature Range]   25   105   -40
[Voltage Range]   3.3   2.97   3.63
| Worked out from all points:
|   slope of the pulldown table from 0 to 0.495 V, typ, clamps not added: 36.4 ohm
|   slope of the pullup table from 0 to 0.495 V, typ, clamps not added: 34.9 ohm
|   GND clamp passes 1 mA (typ) near -0.57 V on its own axis
|   POWER clamp passes 1 mA (typ) near -0.48 V on its own axis
|   rising waveform, R_fixture 50, V_fixture 3.3: 20-80 % time 243ps typ, 379ps min, 195ps max; typ from 1.41 V to 3.3 V
|   rising waveform, R_fixture 50, V_fixture 0: 20-80 % time 402ps typ, 708ps min, 259ps max; typ from 0 V to 1.93 V
|   falling waveform, R_fixture 50, V_fixture 3.3: 20-80 % time 394ps typ, 661ps min, 255ps max; typ from 3.3 V to 1.41 V
|   falling waveform, R_fixture 50, V_fixture 0: 20-80 % time 271ps typ, 426ps min, 181ps max; typ from 1.93 V to 0 V
[POWER_clamp]
-3.3V     86.18mA    66.85mA    104.3mA
-1.233V   15.23mA    13.89mA    17mA
-1.167V   13.13mA    12.22mA    15.08mA
-1.1V     11.2mA     10.59mA    13.35mA
-966.7mV  8.107mA    7.523mA    10.12mA
-833.3mV  5.722mA    4.941mA    7.128mA
-766.7mV  4.649mA    3.923mA    5.756mA
-566.7mV  1.907mA    1.668mA    2.202mA
-433.3mV  626.1uA    643.5uA    621.2uA
-366.7mV  275.1uA    317uA      268.7uA
-166.7mV  94.56uA    58.81uA    157.9uA
3.3V      -11.19nA   -32.41uA   34.49uA
[Pulldown]
-3.3V     -240.7uA   -180.9uA   -268.6uA
-1.3V     -1.697mA   -1.064mA   -2.248mA
-1.1V     -3.762mA   -1.923mA   -6.665mA
-1V       -7.728mA   -3.048mA   -19.72mA
-900mV    -17.44mA   -5.882mA   -26.83mA
-800mV    -19.19mA   -10.95mA   -25.48mA
-700mV    -17.88mA   -12.05mA   -23.65mA
-500mV    -13.74mA   -9.678mA   -17.88mA
1.5V      39.94mA    28.65mA    51.41mA
2.9V      72.6mA     52.84mA    91.93mA
4.6V      105.1mA    77.82mA    131.1mA
6.6V      135.8mA    100.6mA    167.1mA
[Pullup]
-3.3V     6.015mA    2.203mA    11.63mA
-700mV    16.55mA    11.47mA    21.8mA
3.6V      -93.97mA   -67.88mA   -119.8mA
3.7V      -96.18mA   -68.06mA   -122.5mA
4.1V      -103.6mA   -9.75mA    -133mA
4.2V      -92.66mA   -7.165mA   -135.5mA
4.3V      -41.56mA   -5.629mA   -137.6mA
4.5V      -12.4mA    -3.913mA   -141.5mA
4.6V      -8.869mA   -3.389mA   -130.3mA
4.7V      -6.864mA   -2.987mA   -48.17mA
4.9V      -4.698mA   -2.411mA   -13mA
6.6V      -1.25mA    -906.2uA   -1.586mA
[GND_clamp]
-3.3V     -22.46A    -23.08A    -22.02A
-1.167V   -1.78A     -2.475A    -1.268A
-1.1V     -1.214A    -1.896A    -719.3mA
-1.033V   -694.9mA   -1.343A    -269mA
-966.7mV  -277.7mA   -834.1mA   -54.82mA
-900mV    -62.92mA   -407mA     -23.21mA
-833.3mV  -17.83mA   -131.5mA   -15.14mA
-766.7mV  -9.316mA   -30.29mA   -9.117mA
-700mV    -5.152mA   -8.714mA   -4.516mA
-433.3mV  -79.9uA    -173.7uA   -60.15uA
3.3V      93.69uA    202uA      157.6uA
[Ramp]
dV/dt_f  1.1470941/0.39688229n 0.88260062/0.66802033n  1.3950088/0.25852668n
dV/dt_r  1.1599871/0.39931107n 0.89636174/0.70945561n  1.4107955/0.26014386n
R_load = 50
[Rising Waveform]
R_fixture = 50
V_fixture = 3.3
V_fixture_min = 2.97
V_fixture_max = 3.63
0s        1.41V      1.518V     1.326V
368.6ps   1.504V     1.52V      1.781V
474.6ps   1.611V     1.52V      2.224V
586.8ps   1.728V     1.54V      3.338V
699.5ps   2.035V     1.593V     3.573V
897ps     3.074V     1.722V     3.609V
1.045ns   3.258V     1.85V      3.621V
1.427ns   3.285V     2.774V     3.626V
1.642ns   3.294V     2.932V     3.626V
5.12ns    3.298V     2.969V     3.627V
[Rising Waveform]
R_fixture = 50
V_fixture = 0
V_fixture_min = 0
V_fixture_max = 0
0s        0V         0V         0V
344.5ps   37.45mV    0V         304.2mV
506.8ps   142.4mV    0V         763.4mV
655.6ps   287.2mV    14.07mV    1.849V
906.8ps   967.5mV    95.73mV    2.303V
1.067ns   1.479V     145.7mV    2.337V
1.35ns    1.848V     398.5mV    2.345V
1.767ns   1.924V     1.043V     2.347V
2.264ns   1.928V     1.421V     2.347V
5.129ns   1.93V      1.49V      2.348V
[Falling Waveform]
R_fixture = 50
V_fixture = 3.3
V_fixture_min = 2.97
V_fixture_max = 3.63
0s        3.297V     2.968V     3.627V
340.6ps   3.259V     2.968V     3.367V
433.9ps   3.2V       2.968V     3.05V
680.4ps   2.985V     2.946V     1.718V
941.7ps   2.243V     2.864V     1.373V
1.136ns   1.73V      2.793V     1.335V
1.412ns   1.477V     2.422V     1.329V
1.883ns   1.415V     1.829V     1.327V
2.291ns   1.41V      1.588V     1.326V
5.12ns    1.409V     1.517V     1.326V
[Falling Waveform]
R_fixture = 50
V_fixture = 0
V_fixture_min = 0
V_fixture_max = 0
0s        1.931V     1.491V     2.348V
93.3ps    1.931V     1.491V     2.317V
291.2ps   1.867V     1.491V     1.881V
500.2ps   1.5V       1.487V     309.5mV
657ps     856.5mV    1.378V     41.38mV
772.2ps   312.6mV    1.246V     20.58mV
882.8ps   88.59mV    1.068V     16.84mV
1.282ns   15.67mV    212.8mV    3.008mV
1.486ns   7.627mV    39.99mV    1.852mV
5.129ns   2.779uV    96.56uV    0V
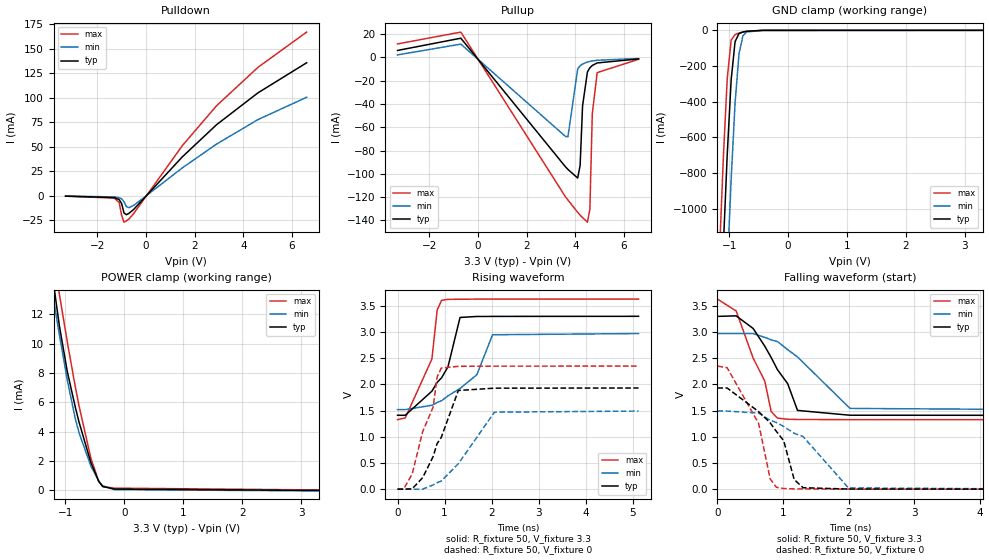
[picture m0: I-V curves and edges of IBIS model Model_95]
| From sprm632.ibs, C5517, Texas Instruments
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| Model based on original model for BC3340CTSCHYPD
|   Sub model SR0_VDD_SR1_VDD_PD_ON_IND_3P3
[model]   Model_95
|[Description]  [3.3V-I/O-PD-X, IND]
|   PD,IND,
|[Input Load]   PD
|[Output Drive]
|Voltage   3.3V
|Mode   I/O
Model_type   I/O
Polarity   Non-Inverting
Enable   Active-Low
Vinl =  0.8
Vinh =  2
Cref =  15.0000pF
Rref =  100.0000M
Vref =  0V
Vmeas =  1.65
C_comp   2.113745p   2.0494201p   2.2478119p
[Model Spec]
Vinl   0.8   0.8   0.8
Vinh   2   2   2
[Temperature Range]   25   105   -40
[Voltage Range]   3.3   2.97   3.63
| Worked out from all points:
|   slope of the pulldown table from 0 to 0.495 V, typ, clamps not added: 36.4 ohm
|   slope of the pullup table from 0 to 0.495 V, typ, clamps not added: 34.9 ohm
|   GND clamp passes 1 mA (typ) near -0.57 V on its own axis
|   POWER clamp passes 1 mA (typ) near -0.48 V on its own axis
|   rising waveform, R_fixture 50, V_fixture 3.3: 20-80 % time 538ps typ, 722ps min, 440ps max; typ from 1.41 V to 3.3 V
|   rising waveform, R_fixture 50, V_fixture 0: 20-80 % time 549ps typ, 751ps min, 444ps max; typ from 0 V to 1.93 V
|   falling waveform, R_fixture 50, V_fixture 3.3: 20-80 % time 517ps typ, 731ps min, 404ps max; typ from 3.3 V to 1.41 V
|   falling waveform, R_fixture 50, V_fixture 0: 20-80 % time 527ps typ, 747ps min, 410ps max; typ from 1.93 V to 0 V
[POWER_clamp]
-3.3V     86.18mA    66.85mA    104.3mA
-1.233V   15.23mA    13.89mA    17mA
-1.167V   13.13mA    12.22mA    15.08mA
-1.1V     11.2mA     10.59mA    13.35mA
-966.7mV  8.107mA    7.523mA    10.12mA
-833.3mV  5.722mA    4.941mA    7.128mA
-766.7mV  4.649mA    3.923mA    5.756mA
-566.7mV  1.907mA    1.668mA    2.202mA
-433.3mV  626.1uA    643.5uA    621.2uA
-366.7mV  275.1uA    317uA      268.7uA
-166.7mV  94.56uA    58.81uA    157.9uA
3.3V      -11.19nA   -32.41uA   34.49uA
[Pulldown]
-3.3V     -240.7uA   -180.9uA   -268.6uA
-1.3V     -1.697mA   -1.064mA   -2.248mA
-1.1V     -3.762mA   -1.923mA   -6.665mA
-1V       -7.728mA   -3.048mA   -19.72mA
-900mV    -17.44mA   -5.882mA   -26.83mA
-800mV    -19.19mA   -10.95mA   -25.48mA
-700mV    -17.88mA   -12.05mA   -23.65mA
-500mV    -13.74mA   -9.678mA   -17.88mA
1.5V      39.94mA    28.65mA    51.41mA
2.9V      72.6mA     52.84mA    91.93mA
4.6V      105.1mA    77.82mA    131.1mA
6.6V      135.8mA    100.6mA    167.1mA
[Pullup]
-3.3V     6.015mA    2.203mA    11.63mA
-700mV    16.55mA    11.47mA    21.8mA
3.6V      -93.97mA   -67.88mA   -119.8mA
3.7V      -96.18mA   -68.06mA   -122.5mA
4.1V      -103.6mA   -9.75mA    -133mA
4.2V      -92.66mA   -7.165mA   -135.5mA
4.3V      -41.56mA   -5.629mA   -137.6mA
4.5V      -12.4mA    -3.913mA   -141.5mA
4.6V      -8.869mA   -3.389mA   -130.3mA
4.7V      -6.864mA   -2.987mA   -48.17mA
4.9V      -4.698mA   -2.411mA   -13mA
6.6V      -1.25mA    -906.2uA   -1.586mA
[GND_clamp]
-3.3V     -22.46A    -23.08A    -22.02A
-1.167V   -1.78A     -2.475A    -1.268A
-1.1V     -1.214A    -1.896A    -719.3mA
-1.033V   -694.9mA   -1.343A    -269mA
-966.7mV  -277.7mA   -834.1mA   -54.82mA
-900mV    -62.92mA   -407mA     -23.21mA
-833.3mV  -17.83mA   -131.5mA   -15.14mA
-766.7mV  -9.316mA   -30.29mA   -9.117mA
-700mV    -5.152mA   -8.714mA   -4.516mA
-433.3mV  -79.9uA    -173.7uA   -60.15uA
3.3V      93.69uA    202uA      157.6uA
[Ramp]
dV/dt_f  1.1416309/0.52098896n 0.87816184/0.73792179n  1.3891315/0.40646151n
dV/dt_r  1.1588016/0.54960411n 0.89537385/0.75248795n  1.4094263/0.44401868n
R_load = 50
[Rising Waveform]
R_fixture = 50
V_fixture = 3.3
V_fixture_min = 2.97
V_fixture_max = 3.63
0s        1.41V      1.518V     1.326V
164.9ps   1.41V      1.518V     1.36V
730.5ps   1.87V      1.601V     2.483V
842.4ps   2.038V     1.654V     3.418V
936.6ps   2.125V     1.688V     3.603V
1.072ns   2.335V     1.78V      3.621V
1.328ns   3.276V     1.921V     3.624V
1.685ns   3.295V     2.184V     3.626V
2.019ns   3.296V     2.946V     3.627V
5.12ns    3.298V     2.969V     3.627V
[Rising Waveform]
R_fixture = 50
V_fixture = 0
V_fixture_min = 0
V_fixture_max = 0
0s        420uV      0V         0V
129ps     420uV      0V         0V
310.7ps   5.138mV    0V         288.2mV
534.4ps   219.9mV    0V         1.098V
757ps     623.2mV    81.25mV    1.568V
839.6ps   866.9mV    122.2mV    2.135V
928.6ps   986.6mV    156mV      2.31V
1.292ns   1.883V     485.1mV    2.344V
2.059ns   1.927V     1.469V     2.347V
5.12ns    1.93V      1.49V      2.348V
[Falling Waveform]
R_fixture = 50
V_fixture = 3.3
V_fixture_min = 2.97
V_fixture_max = 3.63
0s        3.297V     2.969V     3.628V
285.4ps   3.308V     2.969V     3.401V
544ps     3.067V     2.969V     2.503V
721ps     2.73V      2.898V     2.064V
819.2ps   2.512V     2.849V     1.48V
915.3ps   2.279V     2.816V     1.356V
1.07ns    2.014V     2.663V     1.334V
1.22ns    1.503V     2.523V     1.33V
2.019ns   1.411V     1.541V     1.327V
5.12ns    1.409V     1.517V     1.326V
[Falling Waveform]
R_fixture = 50
V_fixture = 0
V_fixture_min = 0
V_fixture_max = 0
0s        1.931V     1.49V      2.348V
148ps     1.931V     1.49V      2.318V
627.6ps   1.48V      1.452V     1.256V
803.1ps   1.267V     1.315V     198.1mV
897.3ps   1.104V     1.272V     36.86mV
1.01ns    923.5mV    1.196V     12.06mV
1.169ns   183.9mV    1.066V     5.577mV
1.305ns   27.88mV    1.003V     4.03mV
1.995ns   2.419mV    24.57mV    1.065mV
5.12ns    13.39uV    153.3uV    0V
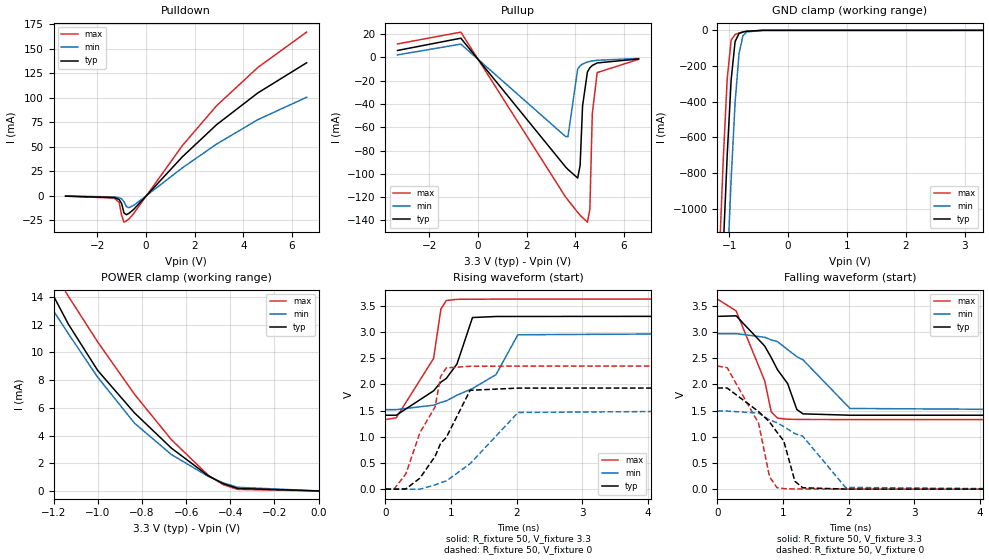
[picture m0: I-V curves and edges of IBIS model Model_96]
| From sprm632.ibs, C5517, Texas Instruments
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| Model based on original model for BC3340CTSCHYPD
|   Sub model SR0_VDD_SR1_VDD_PD_OFF_IND_3P3
[model]   Model_96
|[Description]  [3.3V-I/O-PD_OFF-X, IND]
|   PD_OFF,IND,
|[Input Load]   PD_OFF
|[Output Drive]
|Voltage   3.3V
|Mode   I/O
Model_type   I/O
Polarity   Non-Inverting
Enable   Active-Low
Vinl =  0.8
Vinh =  2
Cref =  15.0000pF
Rref =  100.0000M
Vref =  0V
Vmeas =  1.65
C_comp   2.113745p   2.0494201p   2.2478119p
[Model Spec]
Vinl   0.8   0.8   0.8
Vinh   2   2   2
[Temperature Range]   25   105   -40
[Voltage Range]   3.3   2.97   3.63
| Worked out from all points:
|   slope of the pulldown table from 0 to 0.495 V, typ, clamps not added: 36.4 ohm
|   slope of the pullup table from 0 to 0.495 V, typ, clamps not added: 34.9 ohm
|   GND clamp passes 1 mA (typ) near -0.57 V on its own axis
|   POWER clamp passes 1 mA (typ) near -0.49 V on its own axis
|   rising waveform, R_fixture 50, V_fixture 3.3: 20-80 % time 540ps typ, 723ps min, 442ps max; typ from 1.41 V to 3.3 V
|   rising waveform, R_fixture 50, V_fixture 0: 20-80 % time 549ps typ, 751ps min, 444ps max; typ from 0 V to 1.93 V
|   falling waveform, R_fixture 50, V_fixture 3.3: 20-80 % time 516ps typ, 731ps min, 404ps max; typ from 3.3 V to 1.41 V
|   falling waveform, R_fixture 50, V_fixture 0: 20-80 % time 526ps typ, 746ps min, 410ps max; typ from 1.93 V to 0 V
[POWER_clamp]
-3.3V     86.08mA    66.79mA    104.2mA
-1.267V   16.23mA    14.68mA    17.92mA
-1.233V   15.14mA    13.84mA    16.84mA
-1.2V     14.07mA    13mA       15.85mA
-1.133V   12.04mA    11.35mA    14.05mA
-1V       8.692mA    8.203mA    10.75mA
-833.3mV  5.628mA    4.887mA    6.97mA
-666.7mV  3.091mA    2.627mA    3.701mA
-500mV    1.094mA    1.049mA    1.134mA
-433.3mV  532.4uA    589.2uA    463.5uA
-366.7mV  181.3uA    262.8uA    110.8uA
0V        865.7pA    6.551nA    589.7pA
[Pulldown]
-3.3V     -240.7uA   -180.9uA   -268.6uA
-1.3V     -1.697mA   -1.064mA   -2.248mA
-1.1V     -3.762mA   -1.923mA   -6.664mA
-1V       -7.728mA   -3.048mA   -19.72mA
-900mV    -17.44mA   -5.882mA   -26.83mA
-800mV    -19.19mA   -10.95mA   -25.48mA
-700mV    -17.88mA   -12.05mA   -23.65mA
-500mV    -13.74mA   -9.678mA   -17.88mA
1.5V      39.94mA    28.65mA    51.42mA
2.9V      72.6mA     52.84mA    91.93mA
4.6V      105.1mA    77.82mA    131.1mA
6.6V      135.8mA    100.6mA    167.1mA
[Pullup]
-3.3V     6.015mA    2.203mA    11.63mA
-700mV    16.55mA    11.47mA    21.8mA
3.6V      -93.97mA   -67.88mA   -119.8mA
3.7V      -96.18mA   -68.06mA   -122.5mA
4.1V      -103.6mA   -9.75mA    -133mA
4.2V      -92.66mA   -7.165mA   -135.5mA
4.3V      -41.55mA   -5.629mA   -137.6mA
4.5V      -12.4mA    -3.913mA   -141.5mA
4.6V      -8.869mA   -3.389mA   -130.3mA
4.7V      -6.864mA   -2.987mA   -48.17mA
4.9V      -4.698mA   -2.411mA   -13mA
6.6V      -1.25mA    -906.2uA   -1.586mA
[GND_clamp]
-3.3V     -22.46A    -23.08A    -22.02A
-1.167V   -1.78A     -2.475A    -1.268A
-1.1V     -1.214A    -1.896A    -719.3mA
-1.033V   -694.9mA   -1.343A    -269mA
-966.7mV  -277.7mA   -834.1mA   -54.76mA
-900mV    -62.9mA    -407mA     -23.12mA
-833.3mV  -17.79mA   -131.4mA   -15.05mA
-766.7mV  -9.259mA   -30.27mA   -9.03mA
-700mV    -5.097mA   -8.689mA   -4.435mA
-433.3mV  -45.78uA   -150.7uA   -10.52uA
3.3V      865.7pA    147.8uA    436.6pA
[Ramp]
dV/dt_f  1.1417759/0.5205044n 0.87819675/0.73775235n  1.3894725/0.4062133n
dV/dt_r   1.159935/0.54973888n 0.89611919/0.75257278n   1.41109/0.44423872n
R_load = 50
[Rising Waveform]
R_fixture = 50
V_fixture = 3.3
V_fixture_min = 2.97
V_fixture_max = 3.63
0s        1.412V     1.519V     1.328V
164.9ps   1.412V     1.519V     1.363V
734ps     1.877V     1.604V     2.496V
846ps     2.044V     1.657V     3.44V
927.7ps   2.114V     1.685V     3.602V
1.091ns   2.39V      1.794V     3.625V
1.328ns   3.277V     1.922V     3.627V
1.686ns   3.297V     2.186V     3.629V
2.02ns    3.298V     2.948V     3.629V
5.12ns    3.3V       2.97V      3.63V
[Rising Waveform]
R_fixture = 50
V_fixture = 0
V_fixture_min = 0
V_fixture_max = 0
0s        412.1uV    0V         0V
129ps     412.1uV    0V         0V
310.8ps   5.153mV    0V         289.9mV
525.1ps   209.8mV    0V         1.076V
757.7ps   627mV      82.02mV    1.573V
841ps     873.7mV    123.3mV    2.149V
928.6ps   989.4mV    156.7mV    2.316V
1.292ns   1.888V     486.5mV    2.347V
2.023ns   1.93V      1.464V     2.35V
5.12ns    1.931V     1.492V     2.351V
[Falling Waveform]
R_fixture = 50
V_fixture = 3.3
V_fixture_min = 2.97
V_fixture_max = 3.63
0s        3.299V     2.97V      3.63V
285.4ps   3.31V      2.97V      3.404V
720.9ps   2.732V     2.9V       2.066V
819.2ps   2.514V     2.85V      1.479V
915.2ps   2.281V     2.817V     1.356V
1.07ns    2.015V     2.664V     1.335V
1.21ns    1.52V      2.531V     1.332V
1.304ns   1.438V     2.469V     1.331V
2.019ns   1.412V     1.541V     1.329V
5.12ns    1.411V     1.518V     1.328V
[Falling Waveform]
R_fixture = 50
V_fixture = 0
V_fixture_min = 0
V_fixture_max = 0
0s        1.932V     1.491V     2.351V
148ps     1.932V     1.491V     2.32V
627.5ps   1.481V     1.453V     1.257V
793.1ps   1.285V     1.322V     240.1mV
906.9ps   1.089V     1.269V     29.25mV
1.01ns    922.4mV    1.196V     9.864mV
1.18ns    151.3mV    1.06V      4.395mV
1.3ns     26.69mV    1.011V     3.257mV
1.951ns   2.095mV    33.52mV    923.6uV
5.12ns    6.161uV    109.5uV    0V
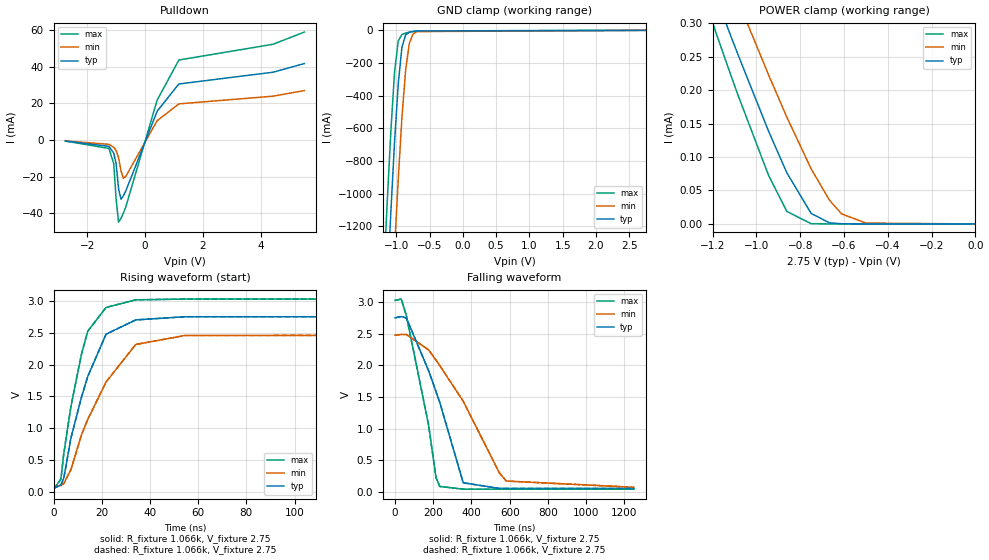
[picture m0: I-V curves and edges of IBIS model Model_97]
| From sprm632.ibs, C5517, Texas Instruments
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| Model based on original model for BI2C33T
|   Sub model BI2C33T_IND_2P75
[model]   Model_97
|[Description]  [2.75V-I/O_OPEN_DRAIN-X-X]
|   , ,
|[Input Load]
|[Output Drive]
|Voltage   2.75V
|Mode   I/O_OPEN_DRAIN
Model_type   I/O_open_drain
Polarity   Non-Inverting
Enable   Active-Low
Vinl =  0.825
Vinh =  1.925
Cref =  400pF
Rref =  528
Vref =  1.8V
Vmeas =  1.375
C_comp   4.5069681p   3.57819p   6.02784p
[Model Spec]
Vinl   0.825   0.7425   0.9075
Vinh   1.925   1.7325   2.1175
[Temperature Range]   25   105   -40
[Voltage Range]   2.75   2.475   3.025
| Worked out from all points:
|   slope of the pulldown table from 0 to 0.412 V, typ, clamps not added: 26.3 ohm
|   GND clamp passes 1 mA (typ) near -0.59 V on its own axis
|   POWER clamp passes 1 mA (typ) near -1.93 V on its own axis
|   rising waveform, R_fixture 1.066k, V_fixture 2.75: 20-80 % time 12ns typ, 17.2ns min, 9.09ns max; typ from 0.056 V to 2.75 V
|   rising waveform, R_fixture 1.066k, V_fixture 2.75: 20-80 % time 12ns typ, 17.2ns min, 9.09ns max; typ from 0.056 V to 2.75 V
|   falling waveform, R_fixture 1.066k, V_fixture 2.75: 20-80 % time 174ns typ, 277ns min, 112ns max; typ from 2.75 V to 0.057 V
|   falling waveform, R_fixture 1.066k, V_fixture 2.75: 20-80 % time 174ns typ, 277ns min, 112ns max; typ from 2.75 V to 0.057 V
[POWER_clamp]
-2.75V    1.753mA    1.752mA    1.829mA
-1.25V    395.5uA    469.1uA    347.1uA
-1.194V   347.2uA    423.3uA    294.4uA
-1.111V   275.6uA    355.2uA    216.8uA
-1.083V   252.1uA    332.7uA    191.4uA
-944.4mV  138.4uA    222.6uA    72.36uA
-861.1mV  76.36uA    159.5uA    18.7uA
-750mV    15.62uA    82.23uA    372.8nA
-666.7mV  1.742uA    35.57uA    7.709nA
-611.1mV  274.2nA    15.05uA    721.5pA
-500mV    4.785nA    1.337uA    193.4pA
0V        277.5pA    3.56nA     142.3pA
[Pulldown]
-2.75V    -575.6uA   -490.2uA   -614.4uA
-1.25V    -3.476mA   -2.373mA   -4.621mA
-1.083V   -7.152mA   -3.971mA   -12.97mA
-1V       -13.05mA   -5.778mA   -32.63mA
-916.7mV  -26.73mA   -9.593mA   -45.01mA
-833.3mV  -32.41mA   -16.89mA   -42.93mA
-750mV    -30.54mA   -21.03mA   -39.99mA
-666.7mV  -27.89mA   -19.9mA    -36.63mA
416.7mV   15.79mA    10.59mA    21.87mA
1.167V    30.69mA    19.79mA    43.81mA
4.417V    37.12mA    24mA       52.44mA
5.5V      41.87mA    27.08mA    59.1mA
[GND_clamp]
-2.75V    -17.07A    -17.72A    -16.61A
-1.194V   -2.061A    -2.769A    -1.538A
-1.139V   -1.576A    -2.277A    -1.059A
-1.083V   -1.111A    -1.799A    -617.2mA
-1.028V   -684mA     -1.34A     -255.6mA
-972.2mV  -327.2mA   -911.8mA   -65.26mA
-916.7mV  -103.4mA   -534mA     -25.42mA
-861.1mV  -27.87mA   -243.1mA   -16.8mA
-805.6mV  -12.31mA   -79.64mA   -11.35mA
-750mV    -7.277mA   -22.22mA   -6.922mA
-694.4mV  -4.234mA   -7.652mA   -3.572mA
2.75V     277.5pA    6.226nA    117.2pA
[Ramp]
dV/dt_f 0.93105822/0.26532945u 0.62422159/0.42325902u  1.2202436/0.1624604u
dV/dt_r 6.6295929m/3.7450294n 4.4666082m/3.8628616n 9.0579343m/3.2718014n
R_load = 50
[Rising Waveform]
R_fixture = 1.066k
V_fixture = 2.75
V_fixture_min = 2.475
V_fixture_max = 3.025
0s        56.18mV    75.45mV    45.9mV
3.046ns   112.7mV    104.5mV    202.5mV
4.269ns   220.8mV    134.6mV    607.3mV
7.235ns   849.2mV    353.3mV    1.345V
11.52ns   1.478V     887.9mV    2.15V
14.18ns   1.811V     1.138V     2.521V
21.79ns   2.476V     1.725V     2.894V
34.1ns    2.699V     2.314V     3.014V
54.51ns   2.749V     2.455V     3.026V
1.25us    2.75V      2.475V     3.025V
[Rising Waveform]
R_fixture = 1.066k
V_fixture = 2.75
V_fixture_min = 2.475
V_fixture_max = 3.025
0s        56.18mV    75.45mV    45.9mV
3.046ns   112.7mV    104.5mV    202.5mV
4.269ns   220.8mV    134.6mV    607.3mV
7.235ns   849.2mV    353.3mV    1.345V
11.52ns   1.478V     887.9mV    2.15V
14.18ns   1.811V     1.138V     2.521V
21.79ns   2.476V     1.725V     2.894V
34.1ns    2.699V     2.314V     3.014V
54.51ns   2.749V     2.455V     3.026V
1.25us    2.75V      2.475V     3.025V
[Falling Waveform]
R_fixture = 1.066k
V_fixture = 2.75
V_fixture_min = 2.475
V_fixture_max = 3.025
0s        2.75V      2.475V     3.025V
32.71ns   2.77V      2.487V     3.046V
59.27ns   2.747V     2.487V     2.784V
175.5ns   1.916V     2.244V     1.059V
214.4ns   1.585V     2.082V     227.3mV
234.1ns   1.415V     1.996V     88mV
356.8ns   146.1mV    1.433V     45.72mV
545.9ns   57.2mV     302.8mV    45.49mV
582.4ns   56.83mV    173.4mV    45.49mV
1.25us    56.7mV     75.18mV    45.49mV
[Falling Waveform]
R_fixture = 1.066k
V_fixture = 2.75
V_fixture_min = 2.475
V_fixture_max = 3.025
0s        2.75V      2.475V     3.025V
32.71ns   2.77V      2.487V     3.046V
59.27ns   2.747V     2.487V     2.784V
175.5ns   1.916V     2.244V     1.059V
214.4ns   1.585V     2.082V     227.3mV
234.1ns   1.415V     1.996V     88mV
356.8ns   146.1mV    1.433V     45.72mV
545.9ns   57.2mV     302.8mV    45.49mV
582.4ns   56.83mV    173.4mV    45.49mV
1.25us    56.7mV     75.18mV    45.49mV
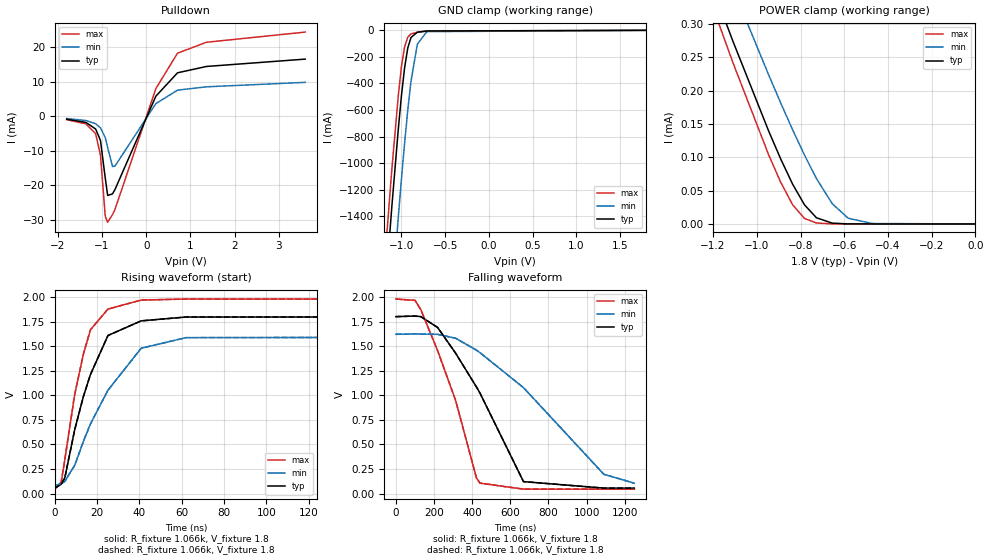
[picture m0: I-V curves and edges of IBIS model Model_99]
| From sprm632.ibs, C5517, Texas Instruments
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| Model based on original model for BI2C33T
|   Sub model BI2C33T_COM_1P8
[model]   Model_99
|[Description]  [1.8V-I/O_OPEN_DRAIN-X-X]
|   , ,
|[Input Load]
|[Output Drive]
|Voltage   1.8V
|Mode   I/O_OPEN_DRAIN
Model_type   I/O_open_drain
Polarity   Non-Inverting
Enable   Active-Low
Vinl =  0.54
Vinh =  1.26
Cref =  400pF
Rref =  528
Vref =  1.8V
Vmeas =  0.9
C_comp   2.7761451p   2.343455p   3.4415601p
[Model Spec]
Vinl   0.54   0.486   0.594
Vinh   1.26   1.134   1.386
[Temperature Range]   25   105   -10
[Voltage Range]   1.8   1.62   1.98
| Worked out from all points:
|   slope of the pulldown table from 0 to 0.27 V, typ, clamps not added: 39.3 ohm
|   GND clamp passes 1 mA (typ) near -0.59 V on its own axis
|   rising waveform, R_fixture 1.066k, V_fixture 1.8: 20-80 % time 13.9ns typ, 22.1ns min, 10.5ns max; typ from 0.055 V to 1.8 V
|   rising waveform, R_fixture 1.066k, V_fixture 1.8: 20-80 % time 13.9ns typ, 22.1ns min, 10.5ns max; typ from 0.055 V to 1.8 V
|   falling waveform, R_fixture 1.066k, V_fixture 1.8: 20-80 % time 284ns typ, 470ns min, 195ns max; typ from 1.8 V to 0.055 V
|   falling waveform, R_fixture 1.066k, V_fixture 1.8: 20-80 % time 284ns typ, 470ns min, 195ns max; typ from 1.8 V to 0.055 V
[POWER_clamp]
-1.8V     886.4uA    933.1uA    880.4uA
-1.382V   511.5uA    578.9uA    489.3uA
-1.109V   273.9uA    353.5uA    241.8uA
-945.5mV  139.2uA    223.4uA    103.5uA
-890.9mV  97.65uA    181.7uA    62.72uA
-836.4mV  59.79uA    141.4uA    28.89uA
-781.8mV  28.66uA    103.2uA    8.193uA
-727.3mV  9.291uA    68.15uA    1.466uA
-654.5mV  1.198uA    30.21uA    86.34nA
-581.8mV  94.65nA    8.572uA    4.126nA
-472.7mV  1.812nA    662.5nA    228.4pA
0V        140.3pA    2.174nA    120.1pA
[Pulldown]
-1.8V     -888.4uA   -690.4uA   -1.036mA
-1.364V   -1.834mA   -1.289mA   -2.253mA
-1.145V   -3.74mA    -2.222mA   -5.105mA
-1.036V   -7.046mA   -3.375mA   -11.33mA
-927.3mV  -17.97mA   -6.221mA   -29.03mA
-872.7mV  -23.02mA   -9.142mA   -30.77mA
-763.6mV  -22.56mA   -14.62mA   -28.58mA
-709.1mV  -21.36mA   -14.53mA   -27.13mA
218.2mV   5.772mA    3.625mA    7.966mA
709.1mV   12.56mA    7.529mA    18.26mA
1.364V    14.4mA     8.495mA    21.42mA
3.6V      16.53mA    9.79mA     24.37mA
[GND_clamp]
-1.8V     -7.773A    -8.459A    -7.499A
-1.182V   -1.949A    -2.656A    -1.662A
-1.145V   -1.632A    -2.335A    -1.347A
-1.109V   -1.323A    -2.019A    -1.043A
-1.036V   -746.7mA   -1.409A    -493.8mA
-1V       -493.2mA   -1.121A    -274.3mA
-963.6mV  -282.3mA   -849.4mA   -124.2mA
-927.3mV  -133.1mA   -600.8mA   -51.47mA
-890.9mV  -54.48mA   -385.3mA   -26.97mA
-818.2mV  -14.19mA   -105.1mA   -14.22mA
-709.1mV  -4.932mA   -9.826mA   -5.721mA
1.8V      140.3pA    2.551nA    97.55pA
[Ramp]
dV/dt_f 0.41925166/0.42368253u 0.25011812/0.64781451u 0.60773809/0.30172244u
dV/dt_r 3.9685437m/4.994332n  2.4376757m/5.0026545n 5.3348169m/4.0509638n
R_load = 50
[Rising Waveform]
R_fixture = 1.066k
V_fixture = 1.8
V_fixture_min = 1.62
V_fixture_max = 1.98
0s        54.58mV    78.79mV    44.88mV
3.07ns    95.93mV    101.4mV    118.5mV
4.76ns    161.9mV    124.9mV    348.4mV
9.43ns    651.6mV    288.4mV    1.012V
13.52ns   988.4mV    530.5mV    1.42V
16.85ns   1.212V     709mV      1.668V
25.14ns   1.61V      1.053V     1.879V
40.83ns   1.759V     1.48V      1.971V
62ns      1.798V     1.588V     1.981V
1.25us    1.8V       1.62V      1.98V
[Rising Waveform]
R_fixture = 1.066k
V_fixture = 1.8
V_fixture_min = 1.62
V_fixture_max = 1.98
0s        54.58mV    78.79mV    44.88mV
3.07ns    95.93mV    101.4mV    118.5mV
4.76ns    161.9mV    124.9mV    348.4mV
9.43ns    651.6mV    288.4mV    1.012V
13.52ns   988.4mV    530.5mV    1.42V
16.85ns   1.212V     709mV      1.668V
25.14ns   1.61V      1.053V     1.879V
40.83ns   1.759V     1.48V      1.971V
62ns      1.798V     1.588V     1.981V
1.25us    1.8V       1.62V      1.98V
[Falling Waveform]
R_fixture = 1.066k
V_fixture = 1.8
V_fixture_min = 1.62
V_fixture_max = 1.98
0s        1.801V     1.621V     1.98V
100.3ns   1.807V     1.625V     1.967V
131ns     1.801V     1.624V     1.872V
218.7ns   1.691V     1.621V     1.456V
313.2ns   1.429V     1.581V     948.2mV
422.4ns   1.085V     1.46V      159.3mV
440.8ns   1.023V     1.434V     105.6mV
668.9ns   121.1mV    1.078V     44.59mV
1.09us    54.96mV    195.9mV    44.3mV
1.25us    54.88mV    104.8mV    44.3mV
[Falling Waveform]
R_fixture = 1.066k
V_fixture = 1.8
V_fixture_min = 1.62
V_fixture_max = 1.98
0s        1.801V     1.621V     1.98V
100.3ns   1.807V     1.625V     1.967V
131ns     1.801V     1.624V     1.872V
218.7ns   1.691V     1.621V     1.456V
313.2ns   1.429V     1.581V     948.2mV
422.4ns   1.085V     1.46V      159.3mV
440.8ns   1.023V     1.434V     105.6mV
668.9ns   121.1mV    1.078V     44.59mV
1.09us    54.96mV    195.9mV    44.3mV
1.25us    54.88mV    104.8mV    44.3mV
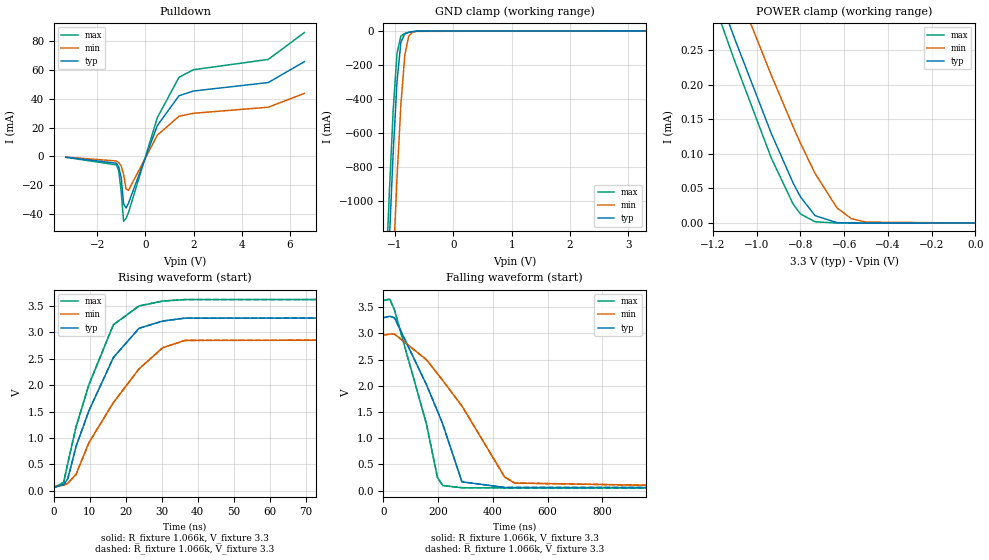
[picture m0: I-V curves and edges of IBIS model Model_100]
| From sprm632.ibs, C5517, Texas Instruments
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| Model based on original model for BI2C33T
|   Sub model BI2C33T_COM_3P3
[model]   Model_100
|[Description]  [3.3V-I/O_OPEN_DRAIN-X-X]
|   , ,
|[Input Load]
|[Output Drive]
|Voltage   3.3V
|Mode   I/O_OPEN_DRAIN
Model_type   I/O_open_drain
Polarity   Non-Inverting
Enable   Active-Low
Vinl =  0.99
Vinh =  2.31
Cref =  400pF
Rref =  528
Vref =  1.8V
Vmeas =  1.65
C_comp   5.331859p   4.20754p   6.02784p
[Model Spec]
Vinl   0.99   0.891   1.089
Vinh   2.31   2.079   2.541
[Temperature Range]   25   105   -10
[Voltage Range]   3.3   2.97   3.63
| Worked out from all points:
|   slope of the pulldown table from 0 to 0.495 V, typ, clamps not added: 23.3 ohm
|   GND clamp passes 1 mA (typ) near -0.58 V on its own axis
|   POWER clamp passes 1 mA (typ) near -1.93 V on its own axis
|   rising waveform, R_fixture 1.066k, V_fixture 3.3: 20-80 % time 12ns typ, 16.7ns min, 10.1ns max; typ from 0.061 V to 3.3 V
|   rising waveform, R_fixture 1.066k, V_fixture 3.3: 20-80 % time 12ns typ, 16.7ns min, 10.1ns max; typ from 0.061 V to 3.3 V
|   falling waveform, R_fixture 1.066k, V_fixture 3.3: 20-80 % time 148ns typ, 230ns min, 109ns max; typ from 3.3 V to 0.06 V
|   falling waveform, R_fixture 1.066k, V_fixture 3.3: 20-80 % time 148ns typ, 230ns min, 109ns max; typ from 3.3 V to 0.06 V
[POWER_clamp]
-3.3V     2.258mA    2.23mA     2.31mA
-1.233V   381uA      455.3uA    353.2uA
-1.2V     352uA      427.8uA    323uA
-1.1V     266.2uA    346.2uA    233.8uA
-933.3mV  129.7uA    214uA      94.07uA
-833.3mV  57.85uA    139.2uA    27.33uA
-800mV    37.97uA    115.6uA    13.22uA
-733.3mV  10.76uA    71.84uA    1.811uA
-633.3mV  598.3nA    21.99uA    36.12nA
-566.7mV  54.6nA     6.265uA    2.973nA
-500mV    4.985nA    1.338uA    960.6pA
0V        410.1pA    4.694nA    487.3pA
[Pulldown]
-3.3V     -494uA     -433.8uA   -533uA
-1.2V     -4.64mA    -3.093mA   -5.796mA
-1.1V     -7.297mA   -4.259mA   -10mA
-1V       -14.66mA   -6.604mA   -24.36mA
-900mV    -32.8mA    -12.31mA   -44.83mA
-800mV    -35.65mA   -22.27mA   -42.88mA
-700mV    -32.38mA   -23.46mA   -38.95mA
500mV     21.44mA    14.77mA    26.92mA
1.4V      42.03mA    27.89mA    54.85mA
2V        45.3mA     29.9mA     60.03mA
5.1V      51.16mA    34.1mA     67.16mA
6.6V      65.62mA    43.66mA    85.74mA
[GND_clamp]
-3.3V     -22.5A     -23.13A    -22.25A
-1.167V   -1.816A    -2.521A    -1.53A
-1.1V     -1.248A    -1.941A    -969.4mA
-1.033V   -724.4mA   -1.385A    -473.6mA
-966.7mV  -297.8mA   -871.3mA   -133.6mA
-900mV    -68.02mA   -435.2mA   -30.62mA
-833.3mV  -17.37mA   -144.7mA   -15.85mA
-766.7mV  -8.463mA   -32.48mA   -9.697mA
-700mV    -4.488mA   -8.365mA   -5.188mA
-633.3mV  -1.982mA   -3.11mA    -2.17mA
3.3V      410.1pA    16.16nA    342.7pA
[Ramp]
dV/dt_f  1.2155225/0.21922737u 0.85955964/0.35370469u  1.4891153/0.15408951u
dV/dt_r 7.6416889m/3.3526202n  5.263757m/3.0672733n  8.965977m/2.9426447n
R_load = 50
[Rising Waveform]
R_fixture = 1.066k
V_fixture = 3.3
V_fixture_min = 2.97
V_fixture_max = 3.63
0s        60.51mV    77.67mV    52.93mV
2.741ns   114.1mV    104.4mV    158.7mV
3.896ns   227mV      139.7mV    523.4mV
6.184ns   840mV      309.5mV    1.211V
9.749ns   1.514V     909.1mV    2.007V
16.55ns   2.523V     1.668V     3.145V
23.68ns   3.077V     2.308V     3.501V
30.27ns   3.215V     2.709V     3.593V
36.48ns   3.27V      2.848V     3.622V
1.25us    3.3V       2.97V      3.63V
[Rising Waveform]
R_fixture = 1.066k
V_fixture = 3.3
V_fixture_min = 2.97
V_fixture_max = 3.63
0s        60.51mV    77.67mV    52.93mV
2.741ns   114.1mV    104.4mV    158.7mV
3.896ns   227mV      139.7mV    523.4mV
6.184ns   840mV      309.5mV    1.211V
9.749ns   1.514V     909.1mV    2.007V
16.55ns   2.523V     1.668V     3.145V
23.68ns   3.077V     2.308V     3.501V
30.27ns   3.215V     2.709V     3.593V
36.48ns   3.27V      2.848V     3.622V
1.25us    3.3V       2.97V      3.63V
[Falling Waveform]
R_fixture = 1.066k
V_fixture = 3.3
V_fixture_min = 2.97
V_fixture_max = 3.63
0s        3.3V       2.97V      3.629V
23.45ns   3.328V     2.988V     3.655V
40.74ns   3.297V     2.987V     3.446V
157.2ns   2.024V     2.5V       1.276V
197.6ns   1.52V      2.233V     251.4mV
217ns     1.27V      2.102V     98.31mV
287.1ns   168.6mV    1.616V     55.64mV
443.5ns   60.83mV    259.4mV    53.48mV
479.7ns   60.37mV    145.5mV    53.48mV
1.25us    60.23mV    77.7mV     53.49mV
[Falling Waveform]
R_fixture = 1.066k
V_fixture = 3.3
V_fixture_min = 2.97
V_fixture_max = 3.63
0s        3.3V       2.97V      3.629V
23.45ns   3.328V     2.988V     3.655V
40.74ns   3.297V     2.987V     3.446V
157.2ns   2.024V     2.5V       1.276V
197.6ns   1.52V      2.233V     251.4mV
217ns     1.27V      2.102V     98.31mV
287.1ns   168.6mV    1.616V     55.64mV
443.5ns   60.83mV    259.4mV    53.48mV
479.7ns   60.37mV    145.5mV    53.48mV
1.25us    60.23mV    77.7mV     53.49mV
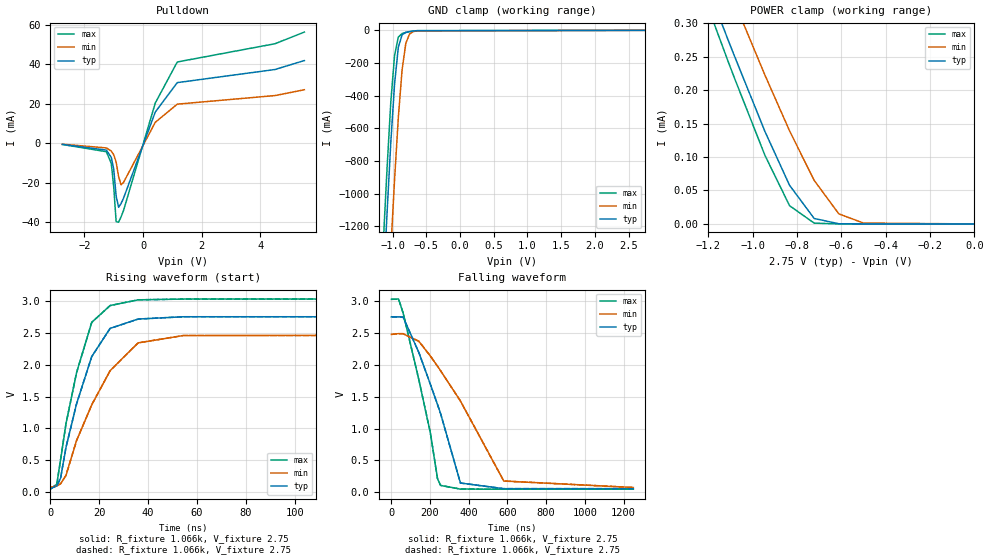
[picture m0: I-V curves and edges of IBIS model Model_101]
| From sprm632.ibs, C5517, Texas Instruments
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| Model based on original model for BI2C33T
|   Sub model BI2C33T_COM_2P75
[model]   Model_101
|[Description]  [2.75V-I/O_OPEN_DRAIN-X-X]
|   , ,
|[Input Load]
|[Output Drive]
|Voltage   2.75V
|Mode   I/O_OPEN_DRAIN
Model_type   I/O_open_drain
Polarity   Non-Inverting
Enable   Active-Low
Vinl =  0.825
Vinh =  1.925
Cref =  400pF
Rref =  528
Vref =  1.8V
Vmeas =  1.375
C_comp   4.5069681p   3.57819p   6.02784p
[Model Spec]
Vinl   0.825   0.7425   0.9075
Vinh   1.925   1.7325   2.1175
[Temperature Range]   25   105   -10
[Voltage Range]   2.75   2.475   3.025
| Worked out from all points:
|   slope of the pulldown table from 0 to 0.412 V, typ, clamps not added: 26.3 ohm
|   GND clamp passes 1 mA (typ) near -0.59 V on its own axis
|   POWER clamp passes 1 mA (typ) near -1.93 V on its own axis
|   rising waveform, R_fixture 1.066k, V_fixture 2.75: 20-80 % time 12ns typ, 17.2ns min, 9.9ns max; typ from 0.056 V to 2.75 V
|   rising waveform, R_fixture 1.066k, V_fixture 2.75: 20-80 % time 12ns typ, 17.2ns min, 9.9ns max; typ from 0.056 V to 2.75 V
|   falling waveform, R_fixture 1.066k, V_fixture 2.75: 20-80 % time 174ns typ, 277ns min, 126ns max; typ from 2.75 V to 0.057 V
|   falling waveform, R_fixture 1.066k, V_fixture 2.75: 20-80 % time 174ns typ, 277ns min, 126ns max; typ from 2.75 V to 0.057 V
[POWER_clamp]
-2.75V    1.753mA    1.752mA    1.784mA
-1.25V    395.5uA    469.1uA    368.3uA
-1.222V   371.3uA    446.1uA    343.1uA
-1.194V   347.2uA    423.3uA    318uA
-1.111V   275.6uA    355.2uA    243.6uA
-1.083V   252.1uA    332.7uA    219.2uA
-944.4mV  138.4uA    222.6uA    102.7uA
-833.3mV  57.85uA    139.2uA    27.32uA
-722.2mV  8.191uA    65.13uA    1.228uA
-611.1mV  274.2nA    15.05uA    14.05nA
-500mV    4.785nA    1.337uA    578.8pA
0V        277.5pA    3.56nA     277.6pA
[Pulldown]
-2.75V    -575.6uA   -490.2uA   -633.5uA
-1.25V    -3.476mA   -2.373mA   -4.291mA
-1.083V   -7.152mA   -3.971mA   -10.2mA
-1V       -13.05mA   -5.778mA   -22mA
-916.7mV  -26.73mA   -9.593mA   -39.74mA
-833.3mV  -32.41mA   -16.89mA   -39.98mA
-750mV    -30.54mA   -21.03mA   -37.28mA
-666.7mV  -27.89mA   -19.9mA    -34.15mA
416.7mV   15.79mA    10.59mA    20.33mA
1.167V    30.69mA    19.79mA    41.15mA
4.5V      37.34mA    24.14mA    50.39mA
5.5V      41.87mA    27.08mA    56.28mA
[GND_clamp]
-2.75V    -17.07A    -17.72A    -16.81A
-1.139V   -1.576A    -2.277A    -1.291A
-1.083V   -1.111A    -1.799A    -837.4mA
-1.028V   -684mA     -1.34A     -437.3mA
-972.2mV  -327.2mA   -911.8mA   -152.3mA
-916.7mV  -103.4mA   -534mA     -41.23mA
-861.1mV  -27.87mA   -243.1mA   -19.67mA
-805.6mV  -12.31mA   -79.64mA   -13mA
-750mV    -7.277mA   -22.22mA   -8.437mA
-694.4mV  -4.234mA   -7.652mA   -4.882mA
-638.9mV  -2.141mA   -3.351mA   -2.36mA
2.75V     277.5pA    6.226nA    209.5pA
[Ramp]
dV/dt_f 0.93105813/0.26567626u 0.62422157/0.42331542u  1.1812011/0.183865u
dV/dt_r 6.6275637m/3.7425992n 4.4793848m/3.8715878n  8.130992m/3.2517464n
R_load = 50
[Rising Waveform]
R_fixture = 1.066k
V_fixture = 2.75
V_fixture_min = 2.475
V_fixture_max = 3.025
0s        56.2mV     75.38mV    49.22mV
2.692ns   102.1mV    99.24mV    130.2mV
4.223ns   223.1mV    134.7mV    512.3mV
6.42ns    704mV      264.7mV    1.073V
10.74ns   1.384V     808.8mV    1.871V
16.95ns   2.125V     1.37V      2.661V
24.47ns   2.567V     1.904V     2.924V
35.93ns   2.713V     2.34V      3.014V
54.43ns   2.749V     2.455V     3.026V
1.25us    2.75V      2.475V     3.025V
[Rising Waveform]
R_fixture = 1.066k
V_fixture = 2.75
V_fixture_min = 2.475
V_fixture_max = 3.025
0s        56.2mV     75.38mV    49.22mV
2.692ns   102.1mV    99.24mV    130.2mV
4.223ns   223.1mV    134.7mV    512.3mV
6.42ns    704mV      264.7mV    1.073V
10.74ns   1.384V     808.8mV    1.871V
16.95ns   2.125V     1.37V      2.661V
24.47ns   2.567V     1.904V     2.924V
35.93ns   2.713V     2.34V      3.014V
54.43ns   2.749V     2.455V     3.026V
1.25us    2.75V      2.475V     3.025V
[Falling Waveform]
R_fixture = 1.066k
V_fixture = 2.75
V_fixture_min = 2.475
V_fixture_max = 3.025
0s        2.75V      2.475V     3.025V
37.19ns   2.75V      2.487V     3.029V
60.72ns   2.746V     2.486V     2.814V
142.2ns   2.191V     2.367V     1.764V
201.9ns   1.691V     2.135V     926.2mV
238.5ns   1.376V     1.977V     215mV
254.5ns   1.233V     1.905V     107.9mV
356.9ns   145.5mV    1.432V     50.43mV
580.9ns   56.84mV    176.6mV    49.13mV
1.25us    56.7mV     75.18mV    49.13mV
[Falling Waveform]
R_fixture = 1.066k
V_fixture = 2.75
V_fixture_min = 2.475
V_fixture_max = 3.025
0s        2.75V      2.475V     3.025V
37.19ns   2.75V      2.487V     3.029V
60.72ns   2.746V     2.486V     2.814V
142.2ns   2.191V     2.367V     1.764V
201.9ns   1.691V     2.135V     926.2mV
238.5ns   1.376V     1.977V     215mV
254.5ns   1.233V     1.905V     107.9mV
356.9ns   145.5mV    1.432V     50.43mV
580.9ns   56.84mV    176.6mV    49.13mV
1.25us    56.7mV     75.18mV    49.13mV
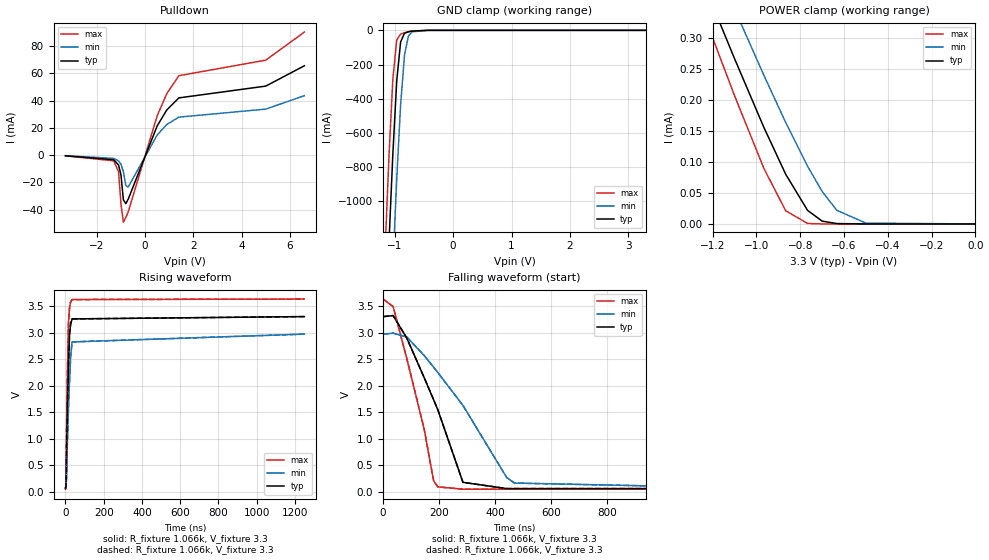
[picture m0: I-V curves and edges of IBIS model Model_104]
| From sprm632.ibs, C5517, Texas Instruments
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| Model based on original model for BI2C33T
|   Sub model BI2C33T_IND_3P3
[model]   Model_104
|[Description]  [3.3V-I/O_OPEN_DRAIN-X-X]
|   , ,
|[Input Load]
|[Output Drive]
|Voltage   3.3V
|Mode   I/O_OPEN_DRAIN
Model_type   I/O_open_drain
Polarity   Non-Inverting
Enable   Active-Low
Vinl =  0.99
Vinh =  2.31
Cref =  400pF
Rref =  528
Vref =  1.8V
Vmeas =  1.65
C_comp   5.331859p   4.20754p   6.02784p
[Model Spec]
Vinl   0.99   0.891   1.089
Vinh   2.31   2.079   2.541
[Temperature Range]   25   105   -40
[Voltage Range]   3.3   2.97   3.63
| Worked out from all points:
|   slope of the pulldown table from 0 to 0.495 V, typ, clamps not added: 23.3 ohm
|   GND clamp passes 1 mA (typ) near -0.58 V on its own axis
|   POWER clamp passes 1 mA (typ) near -1.93 V on its own axis
|   rising waveform, R_fixture 1.066k, V_fixture 3.3: 20-80 % time 12ns typ, 16.7ns min, 9.32ns max; typ from 0.06 V to 3.3 V
|   rising waveform, R_fixture 1.066k, V_fixture 3.3: 20-80 % time 12ns typ, 16.7ns min, 9.32ns max; typ from 0.06 V to 3.3 V
|   falling waveform, R_fixture 1.066k, V_fixture 3.3: 20-80 % time 148ns typ, 231ns min, 97.5ns max; typ from 3.3 V to 0.06 V
|   falling waveform, R_fixture 1.066k, V_fixture 3.3: 20-80 % time 148ns typ, 231ns min, 97.5ns max; typ from 3.3 V to 0.06 V
[POWER_clamp]
-3.3V     2.258mA    2.23mA     2.38mA
-1.267V   410.1uA    482.9uA    363uA
-1.233V   381uA      455.3uA    331.2uA
-1.2V     352uA      427.8uA    299.7uA
-1.1V     266.2uA    346.2uA    206.6uA
-966.7mV  156uA      239.9uA    90uA
-866.7mV  80.25uA    163.6uA    21.34uA
-766.7mV  21.92uA    93.06uA    777.8nA
-700mV    4.533uA    52.43uA    36.44nA
-633.3mV  598.3nA    21.99uA    1.784nA
-500mV    4.985nA    1.338uA    244.8pA
0V        410.1pA    4.694nA    180.2pA
[Pulldown]
-3.3V     -494uA     -433.8uA   -513.6uA
-1.3V     -3.36mA    -2.413mA   -4.226mA
-1.1V     -7.297mA   -4.259mA   -12.32mA
-1V       -14.66mA   -6.604mA   -36.03mA
-900mV    -32.8mA    -12.31mA   -49.27mA
-800mV    -35.65mA   -22.27mA   -45.86mA
-700mV    -32.38mA   -23.46mA   -41.67mA
500mV     21.44mA    14.77mA    28.86mA
900mV     33.17mA    22.52mA    45.22mA
1.4V      42.03mA    27.89mA    58.32mA
5V        50.69mA    33.78mA    69.75mA
6.6V      65.62mA    43.66mA    90.36mA
[GND_clamp]
-3.3V     -22.5A     -23.13A    -22.05A
-1.167V   -1.816A    -2.521A    -1.295A
-1.1V     -1.248A    -1.941A    -744mA
-1.033V   -724.4mA   -1.385A    -285.8mA
-966.7mV  -297.8mA   -871.3mA   -57.12mA
-900mV    -68.02mA   -435.2mA   -21.97mA
-833.3mV  -17.37mA   -144.7mA   -13.93mA
-766.7mV  -8.463mA   -32.48mA   -8.15mA
-700mV    -4.488mA   -8.365mA   -3.849mA
-433.3mV  -34.55uA   -115.3uA   -7.864uA
3.3V      410.1pA    16.16nA    145.7pA
[Ramp]
dV/dt_f  1.2155224/0.21924324u 0.85956003/0.35367287u  1.5315103/0.1367175u
dV/dt_r 7.4715829m/3.1825328n 5.2728589m/3.0913821n 10.236583m/3.1060932n
R_load = 50
[Rising Waveform]
R_fixture = 1.066k
V_fixture = 3.3
V_fixture_min = 2.97
V_fixture_max = 3.63
0s        59.66mV    77.75mV    49.46mV
2.302ns   94.24mV    96.11mV    114.3mV
3.495ns   169mV      123.5mV    461.8mV
6.27ns    856.3mV    320.9mV    1.352V
9.909ns   1.54V      930.8mV    2.21V
15.69ns   2.413V     1.583V     3.177V
21.55ns   2.985V     2.132V     3.478V
26.98ns   3.16V      2.542V     3.577V
34.61ns   3.256V     2.823V     3.621V
1.25us    3.3V       2.97V      3.63V
[Rising Waveform]
R_fixture = 1.066k
V_fixture = 3.3
V_fixture_min = 2.97
V_fixture_max = 3.63
0s        59.66mV    77.75mV    49.46mV
2.302ns   94.24mV    96.11mV    114.3mV
3.495ns   169mV      123.5mV    461.8mV
6.27ns    856.3mV    320.9mV    1.352V
9.909ns   1.54V      930.8mV    2.21V
15.69ns   2.413V     1.583V     3.177V
21.55ns   2.985V     2.132V     3.478V
26.98ns   3.16V      2.542V     3.577V
34.61ns   3.256V     2.823V     3.621V
1.25us    3.3V       2.97V      3.63V
[Falling Waveform]
R_fixture = 1.066k
V_fixture = 3.3
V_fixture_min = 2.97
V_fixture_max = 3.63
0s        3.3V       2.97V      3.631V
35.94ns   3.32V      2.988V     3.49V
84.95ns   2.894V     2.914V     2.506V
146.6ns   2.154V     2.57V      1.189V
180.4ns   1.737V     2.349V     210.8mV
195.5ns   1.548V     2.248V     92.5mV
285.5ns   178.2mV    1.627V     50.16mV
441.7ns   60.81mV    270.5mV    49.7mV
469.7ns   60.41mV    164.6mV    49.71mV
1.25us    60.23mV    77.7mV     49.71mV
[Falling Waveform]
R_fixture = 1.066k
V_fixture = 3.3
V_fixture_min = 2.97
V_fixture_max = 3.63
0s        3.3V       2.97V      3.631V
35.94ns   3.32V      2.988V     3.49V
84.95ns   2.894V     2.914V     2.506V
146.6ns   2.154V     2.57V      1.189V
180.4ns   1.737V     2.349V     210.8mV
195.5ns   1.548V     2.248V     92.5mV
285.5ns   178.2mV    1.627V     50.16mV
441.7ns   60.81mV    270.5mV    49.7mV
469.7ns   60.41mV    164.6mV    49.71mV
1.25us    60.23mV    77.7mV     49.71mV
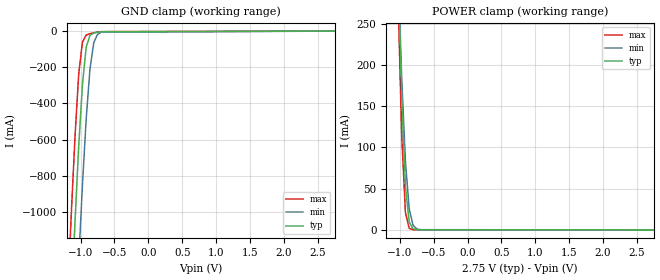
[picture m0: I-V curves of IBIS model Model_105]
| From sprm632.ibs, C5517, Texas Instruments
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| Model based on original model for IC33THYPU
|   Sub model IC33THY_PU_ON_IND_2P75
[model]   Model_105
|[Description]  [2.75V-INPUT-PU-X, IND]
|   PU,IND,
|[Input Load]   PU
|[Output Drive]
|Voltage   2.75V
|Mode   INPUT
Model_type   Input
Polarity   Non-Inverting
Vinl =  0.7
Vinh =  1.7
C_comp   0.88152539p  0.83844711p  0.88864286p
[Model Spec]
Vinl   0.7   0.7   0.7
Vinh   1.7   1.7   1.7
[Temperature Range]   25   105   -40
[Voltage Range]   2.75   2.475   3.025
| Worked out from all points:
|   GND clamp passes 1 mA (typ) near -0.59 V on its own axis
|   POWER clamp passes 1 mA (typ) near -0.79 V on its own axis
[POWER_clamp]
-2.75V    7.271A     6.262A     8.252A
-1.028V   318.5mA    321.1mA    289.5mA
-972.2mV  160.5mA    185.6mA    114.9mA
-916.7mV  52.4mA     82.78mA    20.8mA
-861.1mV  9.559mA    25.54mA    1.804mA
-805.6mV  1.328mA    5.853mA    208.1uA
-750mV    209.8uA    1.186mA    88.96uA
-694.4mV  70.4uA     259.5uA    74.81uA
2.75V     -71.61uA   -47.26uA   -113.2uA
[GND_clamp]
-2.75V    -17A       -17.63A    -16.56A
-1.194V   -2A        -2.688A    -1.495A
-1.139V   -1.516A    -2.198A    -1.02A
-1.083V   -1.056A    -1.723A    -584.9mA
-1.028V   -635.2mA   -1.268A    -236.1mA
-972.2mV  -291mA     -845.8mA   -59.94mA
-916.7mV  -86.56mA   -479.1mA   -22.07mA
-861.1mV  -22.91mA   -206.5mA   -14.22mA
-805.6mV  -10.28mA   -63.93mA   -9.612mA
-750mV    -6.142mA   -17.61mA   -5.899mA
-694.4mV  -3.607mA   -6.208mA   -3.095mA
2.75V     250.3pA    13.17uA    -24.39uA
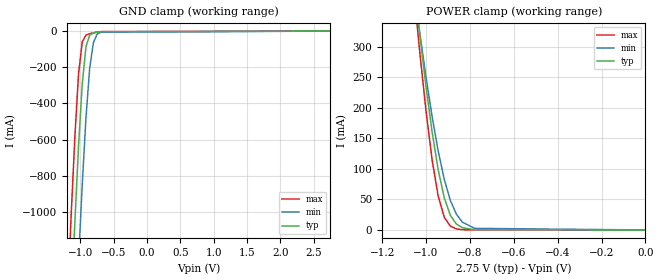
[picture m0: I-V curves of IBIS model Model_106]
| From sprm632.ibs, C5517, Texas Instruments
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| Model based on original model for IC33THYPU
|   Sub model IC33THY_PU_OFF_IND_2P75
[model]   Model_106
|[Description]  [2.75V-INPUT-PU_OFF-X, IND]
|   PU_OFF,IND,
|[Input Load]   PU_OFF
|[Output Drive]
|Voltage   2.75V
|Mode   INPUT
Model_type   Input
Polarity   Non-Inverting
Vinl =  0.7
Vinh =  1.7
C_comp   0.88152539p  0.83844711p  0.88864286p
[Model Spec]
Vinl   0.7   0.7   0.7
Vinh   1.7   1.7   1.7
[Temperature Range]   25   105   -40
[Voltage Range]   2.75   2.475   3.025
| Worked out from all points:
|   GND clamp passes 1 mA (typ) near -0.60 V on its own axis
|   POWER clamp passes 1 mA (typ) near -0.80 V on its own axis
[POWER_clamp]
-2.75V    7.271A     6.262A     8.252A
-1.056V   408.2mA    396.7mA    392.7mA
-1.028V   318.5mA    321.1mA    289.5mA
-1V       234.9mA    250.2mA    195.1mA
-972.2mV  160.5mA    185.6mA    114.9mA
-944.4mV  98.4mA     129.1mA    55.33mA
-916.7mV  52.38mA    82.77mA    20.72mA
-888.9mV  23.77mA    48.19mA    6.241mA
-861.1mV  9.524mA    25.53mA    1.717mA
-833.3mV  3.563mA    12.55mA    464.4uA
-777.8mV  451.6uA    2.632mA    35.29uA
0V        251.2pA    2.976nA    141.1pA
[GND_clamp]
-2.75V    -17A       -17.63A    -16.56A
-1.194V   -2A        -2.688A    -1.495A
-1.139V   -1.516A    -2.198A    -1.02A
-1.083V   -1.056A    -1.723A    -584.9mA
-1.028V   -635.2mA   -1.268A    -236.1mA
-972.2mV  -291mA     -845.8mA   -59.84mA
-916.7mV  -86.5mA    -479.1mA   -21.96mA
-861.1mV  -22.84mA   -206.5mA   -14.11mA
-805.6mV  -10.21mA   -63.89mA   -9.499mA
-750mV    -6.07mA    -17.56mA   -5.786mA
-694.4mV  -3.535mA   -6.164mA   -2.981mA
2.75V     251.2pA    21.48nA    116.1pA
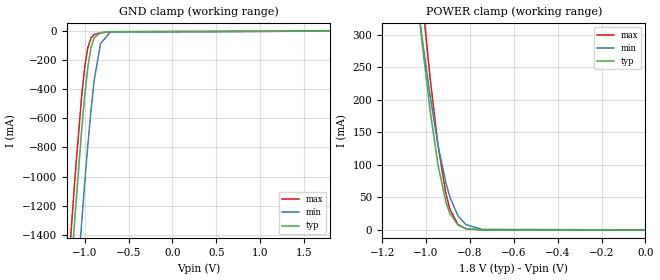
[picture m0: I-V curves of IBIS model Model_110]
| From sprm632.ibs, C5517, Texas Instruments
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| Model based on original model for IC33THYPU
|   Sub model IC33THY_PU_OFF_COM_1P8
[model]   Model_110
|[Description]  [1.8V-INPUT-PU_OFF-X, COM]
|   PU_OFF,COM,
|[Input Load]   PU_OFF
|[Output Drive]
|Voltage   1.8V
|Mode   INPUT
Model_type   Input
Polarity   Non-Inverting
Vinl =  0.63
Vinh =  1.17
C_comp   0.92617999p  0.90533854p  0.94294583p
[Model Spec]
Vinl   0.63   0.567   0.693
Vinh   1.17   1.053   1.287
[Temperature Range]   25   105   -10
[Voltage Range]   1.8   1.62   1.98
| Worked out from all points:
|   GND clamp passes 1 mA (typ) near -0.60 V on its own axis
|   POWER clamp passes 1 mA (typ) near -0.80 V on its own axis
[POWER_clamp]
-1.8V     3.329A     2.879A     3.744A
-1.055V   404.9mA    393.9mA    493mA
-1.036V   345.6mA    344mA      424.6mA
-1.018V   288.8mA    296mA      358.4mA
-981.8mV  185mA      207.1mA    235.2mA
-945.5mV  100.4mA    131mA      130.6mA
-909.1mV  42.76mA    72.05mA    55.36mA
-890.9mV  25.29mA    50.28mA    31.76mA
-854.5mV  7.635mA    21.79mA    8.476mA
-818.2mV  2.03mA     8.282mA    1.89mA
-745.5mV  136.4uA    1.035mA    89.5uA
0V        130.2pA    1.819nA    114.7pA
[GND_clamp]
-1.8V     -7.705A    -8.371A    -7.441A
-1.182V   -1.888A    -2.575A    -1.614A
-1.145V   -1.573A    -2.255A    -1.301A
-1.109V   -1.266A    -1.941A    -999.8mA
-1.036V   -696.5mA   -1.336A    -461.3mA
-1V       -449.6mA   -1.052A    -251.6mA
-963.6mV  -248.8mA   -784.8mA   -112.7mA
-927.3mV  -112.5mA   -543.2mA   -46.57mA
-890.9mV  -44.77mA   -337.9mA   -23.62mA
-818.2mV  -11.74mA   -85.22mA   -11.95mA
-709.1mV  -4.118mA   -7.868mA   -4.781mA
1.8V      130.2pA    3.882nA    93.27pA
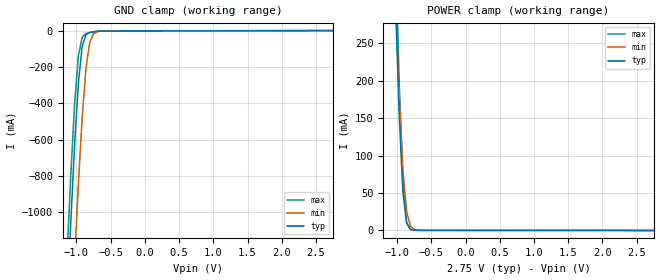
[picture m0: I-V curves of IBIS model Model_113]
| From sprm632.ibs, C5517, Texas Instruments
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| Model based on original model for IC33THYPU
|   Sub model IC33THY_PU_ON_COM_2P75
[model]   Model_113
|[Description]  [2.75V-INPUT-PU-X, COM]
|   PU,COM,
|[Input Load]   PU
|[Output Drive]
|Voltage   2.75V
|Mode   INPUT
Model_type   Input
Polarity   Non-Inverting
Vinl =  0.7
Vinh =  1.7
C_comp   0.88152539p  0.83844711p  0.88864286p
[Model Spec]
Vinl   0.7   0.7   0.7
Vinh   1.7   1.7   1.7
[Temperature Range]   25   105   -10
[Voltage Range]   2.75   2.475   3.025
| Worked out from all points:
|   GND clamp passes 1 mA (typ) near -0.59 V on its own axis
|   POWER clamp passes 1 mA (typ) near -0.79 V on its own axis
[POWER_clamp]
-2.75V    7.271A     6.262A     8.086A
-1.028V   318.5mA    321.1mA    393mA
-972.2mV  160.5mA    185.6mA    205.4mA
-916.7mV  52.4mA     82.78mA    68.25mA
-861.1mV  9.559mA    25.54mA    10.92mA
-805.6mV  1.328mA    5.853mA    1.193mA
-750mV    209.8uA    1.186mA    173.4uA
-638.9mV  49.04uA    75.03uA    60.71uA
2.75V     -71.61uA   -47.26uA   -101.6uA
[GND_clamp]
-2.75V    -17A       -17.63A    -16.75A
-1.139V   -1.516A    -2.198A    -1.246A
-1.083V   -1.056A    -1.723A    -796.9mA
-1.028V   -635.2mA   -1.268A    -406.8mA
-972.2mV  -291mA     -845.8mA   -138.4mA
-916.7mV  -86.56mA   -479.1mA   -37.17mA
-861.1mV  -22.91mA   -206.5mA   -16.88mA
-805.6mV  -10.28mA   -63.93mA   -11.01mA
-750mV    -6.142mA   -17.61mA   -7.159mA
-694.4mV  -3.607mA   -6.208mA   -4.18mA
-638.9mV  -1.858mA   -2.795mA   -2.071mA
2.75V     250.3pA    13.17uA    -21.76uA
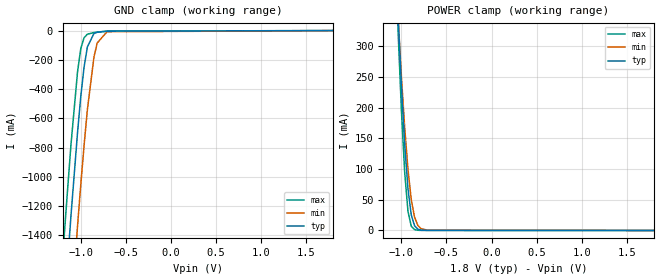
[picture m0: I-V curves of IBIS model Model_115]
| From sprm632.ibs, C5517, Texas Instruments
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| Model based on original model for IC33THYPU
|   Sub model IC33THY_PU_ON_IND_1P8
[model]   Model_115
|[Description]  [1.8V-INPUT-PU-X, IND]
|   PU,IND,
|[Input Load]   PU
|[Output Drive]
|Voltage   1.8V
|Mode   INPUT
Model_type   Input
Polarity   Non-Inverting
Vinl =  0.63
Vinh =  1.17
C_comp   0.92617999p  0.90533854p  0.94294583p
[Model Spec]
Vinl   0.63   0.567   0.693
Vinh   1.17   1.053   1.287
[Temperature Range]   25   105   -40
[Voltage Range]   1.8   1.62   1.98
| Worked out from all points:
|   GND clamp passes 1 mA (typ) near -0.60 V on its own axis
|   POWER clamp passes 1 mA (typ) near -0.79 V on its own axis
[POWER_clamp]
-1.8V     3.329A     2.879A     3.754A
-1.073V   466.1mA    445.3mA    459.6mA
-1.036V   345.6mA    344mA      320.6mA
-1V       234.9mA    250.2mA    195.1mA
-963.6mV  139.8mA    167.2mA    94.03mA
-927.3mV  67.85mA    99.12mA    31.04mA
-890.9mV  25.31mA    50.28mA    6.899mA
-854.5mV  7.66mA     21.79mA    1.34mA
-818.2mV  2.061mA    8.29mA     285uA
-781.8mV  560.8uA    2.966mA    100.9uA
-709.1mV  71.42uA    372.3uA    57.36uA
1.8V      -27.44uA   -17.03uA   -44.66uA
[GND_clamp]
-1.8V     -7.705A    -8.371A    -7.226A
-1.182V   -1.888A    -2.575A    -1.385A
-1.145V   -1.573A    -2.255A    -1.075A
-1.109V   -1.266A    -1.941A    -779.8mA
-1.036V   -696.5mA   -1.336A    -281mA
-1V       -449.7mA   -1.052A    -122.4mA
-963.6mV  -248.8mA   -784.8mA   -48.73mA
-927.3mV  -112.5mA   -543.2mA   -24.97mA
-854.5mV  -20.26mA   -183mA     -13.55mA
-818.2mV  -11.77mA   -85.23mA   -10.5mA
-709.1mV  -4.146mA   -7.885mA   -3.667mA
1.8V      129.8pA    5.759uA    -11uA
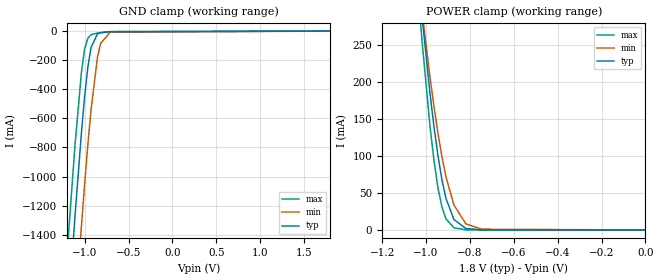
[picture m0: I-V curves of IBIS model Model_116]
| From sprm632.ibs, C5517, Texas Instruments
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| Model based on original model for IC33THYPU
|   Sub model IC33THY_PU_OFF_IND_1P8
[model]   Model_116
|[Description]  [1.8V-INPUT-PU_OFF-X, IND]
|   PU_OFF,IND,
|[Input Load]   PU_OFF
|[Output Drive]
|Voltage   1.8V
|Mode   INPUT
Model_type   Input
Polarity   Non-Inverting
Vinl =  0.63
Vinh =  1.17
C_comp   0.92617999p  0.90533854p  0.94294583p
[Model Spec]
Vinl   0.63   0.567   0.693
Vinh   1.17   1.053   1.287
[Temperature Range]   25   105   -40
[Voltage Range]   1.8   1.62   1.98
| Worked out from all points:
|   GND clamp passes 1 mA (typ) near -0.60 V on its own axis
|   POWER clamp passes 1 mA (typ) near -0.80 V on its own axis
[POWER_clamp]
-1.8V     3.329A     2.879A     3.754A
-1.036V   345.6mA    344mA      320.6mA
-1.018V   288.8mA    296mA      255.7mA
-981.8mV  185mA      207.1mA    140.6mA
-963.6mV  139.8mA    167.2mA    94mA
-945.5mV  100.4mA    131mA      57.07mA
-927.3mV  67.83mA    99.11mA    30.99mA
-909.1mV  42.76mA    72.05mA    15.07mA
-872.7mV  14.21mA    33.74mA    2.999mA
-818.2mV  2.03mA     8.282mA    223.7uA
-745.5mV  136.4uA    1.035mA    10.12uA
0V        130.2pA    1.819nA    89.63pA
[GND_clamp]
-1.8V     -7.705A    -8.371A    -7.226A
-1.182V   -1.888A    -2.575A    -1.385A
-1.145V   -1.573A    -2.255A    -1.075A
-1.109V   -1.266A    -1.941A    -779.8mA
-1.036V   -696.5mA   -1.336A    -281mA
-1V       -449.6mA   -1.052A    -122.3mA
-963.6mV  -248.8mA   -784.8mA   -48.69mA
-927.3mV  -112.5mA   -543.2mA   -24.93mA
-854.5mV  -20.23mA   -183mA     -13.5mA
-818.2mV  -11.74mA   -85.22mA   -10.46mA
-709.1mV  -4.118mA   -7.868mA   -3.623mA
1.8V      130.2pA    3.882nA    74.28pA
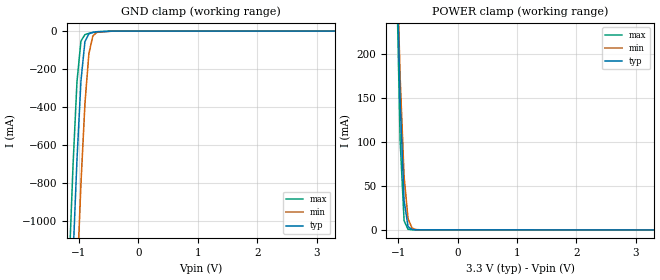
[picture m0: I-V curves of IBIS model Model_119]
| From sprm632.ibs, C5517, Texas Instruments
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| Model based on original model for IC33THYPU
|   Sub model IC33THY_PU_ON_IND_3P3
[model]   Model_119
|[Description]  [3.3V-INPUT-PU-X, IND]
|   PU,IND,
|[Input Load]   PU
|[Output Drive]
|Voltage   3.3V
|Mode   INPUT
Model_type   Input
Polarity   Non-Inverting
Vinl =  0.8
Vinh =  2
C_comp   0.86952386p  0.83844711p  0.87673039p
[Model Spec]
Vinl   0.8   0.8   0.8
Vinh   2   2   2
[Temperature Range]   25   105   -40
[Voltage Range]   3.3   2.97   3.63
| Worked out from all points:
|   GND clamp passes 1 mA (typ) near -0.59 V on its own axis
|   POWER clamp passes 1 mA (typ) near -0.78 V on its own axis
[POWER_clamp]
-3.3V     9.572A     8.243A     10.87A
-1.033V   336mA      335.9mA    309.5mA
-966.7mV  147mA      173.6mA    101.2mA
-900mV    33.09mA    60.44mA    10.25mA
-833.3mV  3.612mA    12.57mA    559.9uA
-766.7mV  357.2uA    1.931mA    110.5uA
-700mV    81.06uA    300.9uA    83.97uA
-633.3mV  53.74uA    72.4uA     74.52uA
3.3V      -103.5uA   -75.37uA   -161uA
[GND_clamp]
-3.3V     -22.43A    -23.04A    -22A
-1.167V   -1.756A    -2.441A    -1.254A
-1.1V     -1.191A    -1.863A    -709.3mA
-1.033V   -674.7mA   -1.312A    -264.8mA
-966.7mV  -263.3mA   -806.2mA   -52.42mA
-900mV    -56.21mA   -384.9mA   -18.85mA
-833.3mV  -14.42mA   -119.2mA   -11.83mA
-766.7mV  -7.156mA   -25.71mA   -6.975mA
-700mV    -3.851mA   -6.789mA   -3.374mA
-433.3mV  -132.5uA   -161.9uA   -168.3uA
3.3V      364pA      18.21uA    -33uA
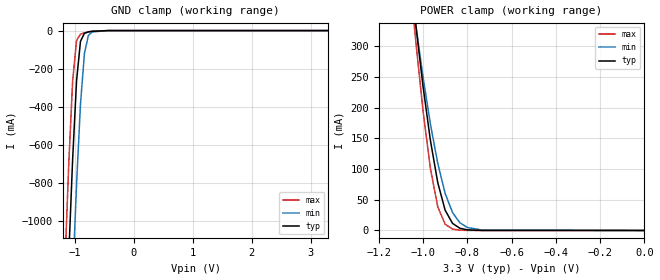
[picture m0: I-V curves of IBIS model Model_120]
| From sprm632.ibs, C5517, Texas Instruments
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| Model based on original model for IC33THYPU
|   Sub model IC33THY_PU_OFF_IND_3P3
[model]   Model_120
|[Description]  [3.3V-INPUT-PU_OFF-X, IND]
|   PU_OFF,IND,
|[Input Load]   PU_OFF
|[Output Drive]
|Voltage   3.3V
|Mode   INPUT
Model_type   Input
Polarity   Non-Inverting
Vinl =  0.8
Vinh =  2
C_comp   0.86952386p  0.83844711p  0.87673039p
[Model Spec]
Vinl   0.8   0.8   0.8
Vinh   2   2   2
[Temperature Range]   25   105   -40
[Voltage Range]   3.3   2.97   3.63
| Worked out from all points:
|   GND clamp passes 1 mA (typ) near -0.59 V on its own axis
|   POWER clamp passes 1 mA (typ) near -0.80 V on its own axis
[POWER_clamp]
-3.3V     9.572A     8.243A     10.87A
-1.067V   445.5mA    428mA      435.8mA
-1.033V   336mA      335.9mA    309.5mA
-1V       234.9mA    250.2mA    195.1mA
-966.7mV  147mA      173.6mA    101.2mA
-933.3mV  77.87mA    109.2mA    38.48mA
-900mV    33.06mA    60.43mA    10.16mA
-866.7mV  11.59mA    29.28mA    2.257mA
-833.3mV  3.563mA    12.55mA    464.4uA
-800mV    1.024mA    4.944mA    94.09uA
-733.3mV  87.24uA    726.8uA    6.973uA
0V        365.2pA    3.923nA    177.2pA
[GND_clamp]
-3.3V     -22.43A    -23.04A    -22A
-1.167V   -1.756A    -2.441A    -1.254A
-1.1V     -1.191A    -1.863A    -709.2mA
-1.033V   -674.7mA   -1.312A    -264.7mA
-966.7mV  -263.3mA   -806.2mA   -52.28mA
-900mV    -56.13mA   -384.9mA   -18.69mA
-833.3mV  -14.32mA   -119.2mA   -11.67mA
-766.7mV  -7.053mA   -25.65mA   -6.814mA
-700mV    -3.748mA   -6.724mA   -3.213mA
-433.3mV  -28.74uA   -95.96uA   -6.528uA
3.3V      365.2pA    64.64nA    143.6pA
